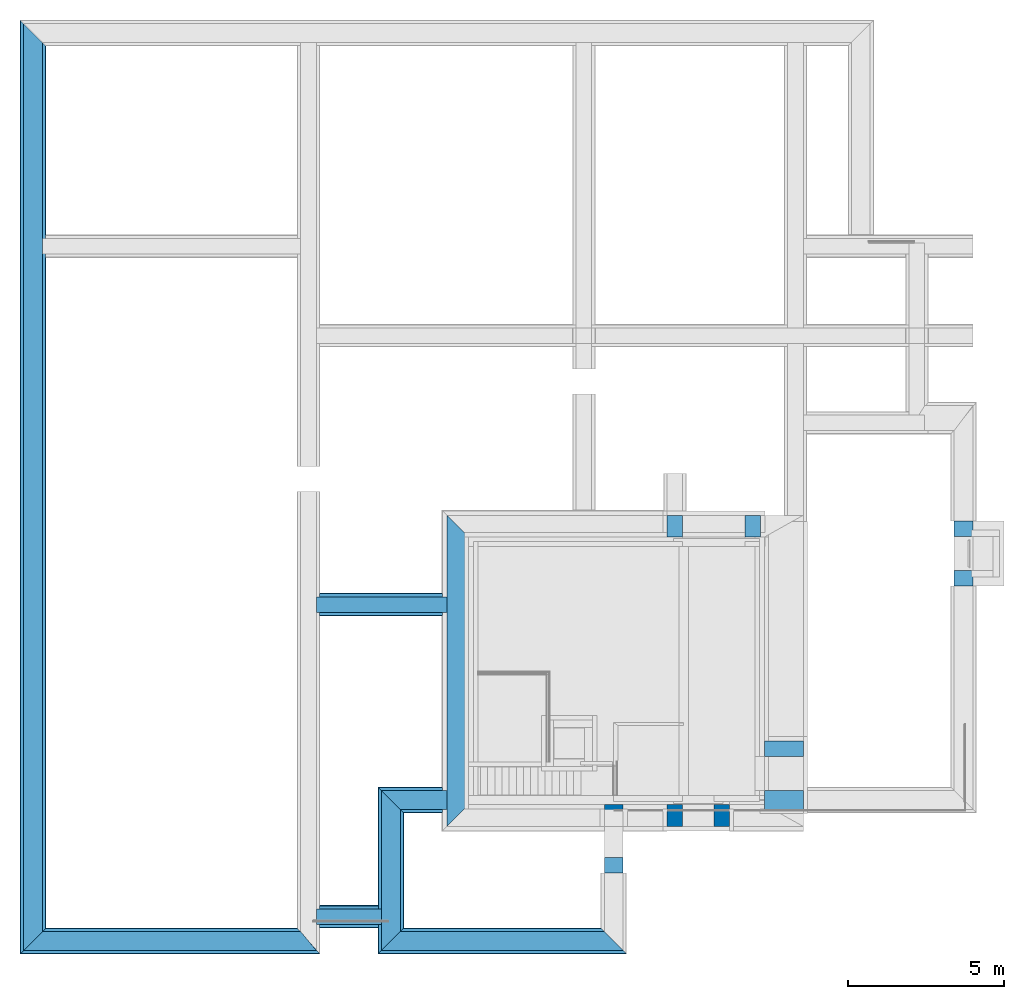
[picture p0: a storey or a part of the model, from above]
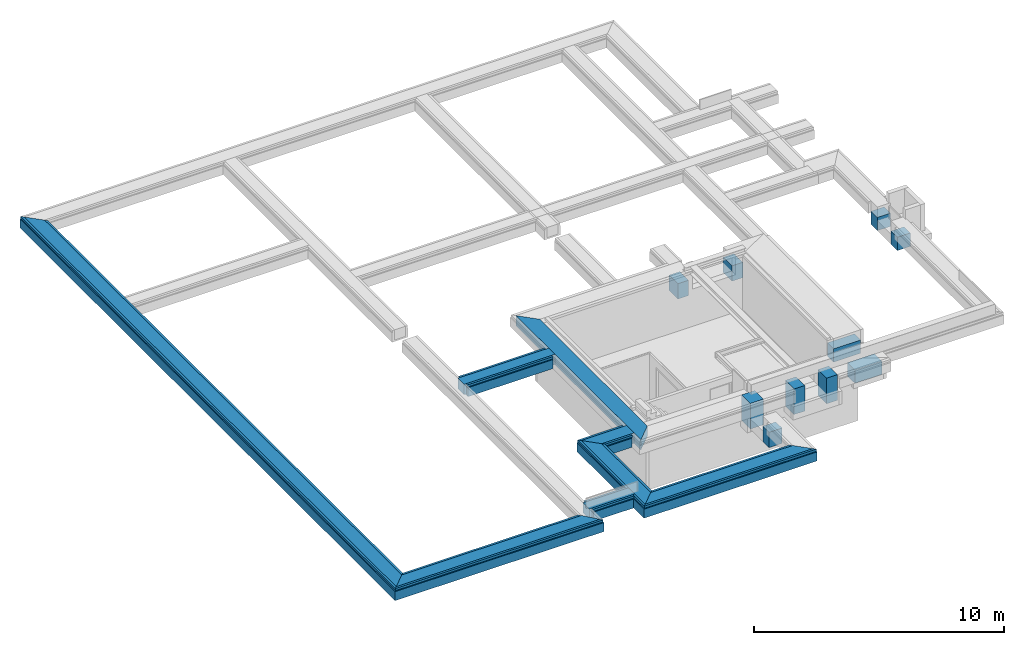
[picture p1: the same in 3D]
Properties of the parts of a building model (IFC2X3), part 1 of 7

# File
Description: ViewDefinition [, SurfaceGeometryAddOnView], Option [Elements to export: Visible elements (on all stories)], Option [Partial Structure Display: Entire Model], Option [IFC Domain: All], Option [Structural Function: All Elements], Option [Convert Grid elements: On], Option [Convert IFC Annotations and Archicad 2D elements: Off], Option [Convert 2D symbols of Doors and Windows: Off], Option [Export geometries that Participates in Collision Detection only: On], Option [Split complex elements: Off], Option [Material Preservation: Explode all], Option [IFC Model position: Survey Point and Project Origin], Option [Curtain Wall export mode: Container Element], Option [Railing export mode: Container Element], Option [Stair export mode: Container Element], Option [Properties To Export: Current Scheme properties only], Option [Space containment: Off], Option [Geometry to type objects: On], Option [Element Properties: Visible Only], Option [Building Material Properties: On], Option [Element Parameters: Off], Option [Component Parameters: Off], Option [IFC Base Quantities: Off], Option [Door Window Parameters: On], Option [IFC Space boundaries: Off], Option [Archicad Zone Categories as IFC Space classification data: Off], Option [Element Classifications: Off]
File name: P:\Project\2022\22004 Zwijndrecht Toermalijn\Archicad\Pdf-Dwg-Ifc-Bimx\20241212 IFC Interieur tbv Daan\22004 Toermalijn IFC totaal.ifc
Time: 2024-12-12T13:59:54
Author: Architect
Organization: Maas Kristinsson Architecten
Written by: DDS_IFC v3.0
Made in: IFC file generated by Graphisoft Archicad 26.0.0 NED FULL Windows version (IFC add-on version: 7004 NED FULL).
Authorization: The authorising person

# IfcProject, Nieuwbouw KC Toermalijn
Description: Schaepmanlaan 23 te Zwijndrecht

# IfcSite, Site
RefLatitude: 51, 27, 0, 0; RefLongitude: 5, 29, 0, 0; RefElevation: 0 mm

# IfcBuildingStorey (4)
In: Naam gebouw
Name | Elevation (mm)
Begane grond | 0
Kelder | -3060
1e verdieping | 3960
2e dakoverzicht | 7820

# IfcBeam: 100X100X5 100 x 100 (5)
In: Begane grond
Type - PredefinedType: BEAM
Material: Metaal - Staal C
Pset_BeamCommon - Slope: 0 deg; IsExternal: no; LoadBearing: yes; Reference: 100X100X5 100 x 100
CPset_Phasing - Renovation Phase: Bestaand
Material Properties - Metaal - Staal C, ThermalConductivity: 52; Metaal - Staal C, SpecificHeatCapacity: 530 J/kg/K; Metaal - Staal C, MassDensity: 7950 kg/m3; Metaal - Staal C, Embodied Energy: 25 (MJ/kg); Metaal - Staal C, Embodied Carbon: 1.91 (kgCO₂/kg); Metaal - Staal C, Name: Metaal - Staal C; Metaal - Staal C, Participates in Collision Detection: yes; Metaal - Staal C, Aardopwarmingsvermogen (GWP): 323.71; Metaal - Staal C, Ozonafbrekend Vermogen (ODP): 0; Metaal - Staal C, Fotochemische Vermogen tot Ozonvorming (POCP): 0.17963; Metaal - Staal C, Verzuringsvermogen (AP): 0.43354; Metaal - Staal C, Eutrofiëringspotentieel (EP): 0.014961; Metaal - Staal C, Abiotisch Uitputtingspotentieel (voor niet fossiele hulpbronnen) (ADPE): 0.00080492; Metaal - Staal C, Abiotisch Uitputtingspotentieel (voor fossiele hulpbronnen) (ADPF): 2862.1; Metaal - Staal C, Databron: https://www.oekobaudat.de/OEKOBAU.DAT/resource/processes/a85fbb4a-60a0-4ba9-9cfa-cdfbe1ec7f00?version=00.01.000

# IfcBeam: 16 Fundering - EPS kist 500x500 1036 x 570 (4)
In: Kelder
Type - PredefinedType: BEAM
Material: Isolatie - Kunststof hard
Pset_BeamCommon - Slope: 0 deg; IsExternal: no; LoadBearing: yes; Reference: 16 Fundering - EPS kist 500x500 1036 x 570
Material Properties - Isolatie - Kunststof hard, ThermalConductivity: 0.029; Isolatie - Kunststof hard, SpecificHeatCapacity: 1470 J/kg/K; Isolatie - Kunststof hard, MassDensity: 100 kg/m3; Isolatie - Kunststof hard, Embodied Energy: 101.5 (MJ/kg); Isolatie - Kunststof hard, Embodied Carbon: 3.48 (kgCO₂/kg); Isolatie - Kunststof hard, Name: Isolatie - Kunststof hard; Isolatie - Kunststof hard, Participates in Collision Detection: yes; Isolatie - Kunststof hard, Aardopwarmingsvermogen (GWP): 0.04; Isolatie - Kunststof hard, Ozonafbrekend Vermogen (ODP): 0; Isolatie - Kunststof hard, Fotochemische Vermogen tot Ozonvorming (POCP): 0; Isolatie - Kunststof hard, Verzuringsvermogen (AP): 0.0000975; Isolatie - Kunststof hard, Eutrofiëringspotentieel (EP): 0.0000237; Isolatie - Kunststof hard, Abiotisch Uitputtingspotentieel (voor niet fossiele hulpbronnen) (ADPE): 0; Isolatie - Kunststof hard, Abiotisch Uitputtingspotentieel (voor fossiele hulpbronnen) (ADPF): 0.47; Isolatie - Kunststof hard, Databron: https://www.oekobaudat.de/OEKOBAU.DAT/resource/processes/41e09ab7-0e73-4303-84fd-97cb0809db02?version=00.04.000
CPset_Phasing - Renovation Phase: Bestaand

# IfcBeam: 16 Fundering - EPS kist 500x500 740 x 570 (11)
In: Kelder
Type - PredefinedType: BEAM
Material: Isolatie - Kunststof hard
Pset_BeamCommon - Slope: 0 deg; IsExternal: no; LoadBearing: yes; Reference: 16 Fundering - EPS kist 500x500 740 x 570
CPset_Phasing - Renovation Phase: Bestaand
Material Properties - Isolatie - Kunststof hard, ThermalConductivity: 0.029; Isolatie - Kunststof hard, SpecificHeatCapacity: 1470 J/kg/K; Isolatie - Kunststof hard, MassDensity: 100 kg/m3; Isolatie - Kunststof hard, Embodied Energy: 101.5 (MJ/kg); Isolatie - Kunststof hard, Embodied Carbon: 3.48 (kgCO₂/kg); Isolatie - Kunststof hard, Name: Isolatie - Kunststof hard; Isolatie - Kunststof hard, Participates in Collision Detection: yes; Isolatie - Kunststof hard, Aardopwarmingsvermogen (GWP): 0.04; Isolatie - Kunststof hard, Ozonafbrekend Vermogen (ODP): 0; Isolatie - Kunststof hard, Fotochemische Vermogen tot Ozonvorming (POCP): 0; Isolatie - Kunststof hard, Verzuringsvermogen (AP): 0.0000975; Isolatie - Kunststof hard, Eutrofiëringspotentieel (EP): 0.0000237; Isolatie - Kunststof hard, Abiotisch Uitputtingspotentieel (voor niet fossiele hulpbronnen) (ADPE): 0; Isolatie - Kunststof hard, Abiotisch Uitputtingspotentieel (voor fossiele hulpbronnen) (ADPF): 0.47; Isolatie - Kunststof hard, Databron: https://www.oekobaudat.de/OEKOBAU.DAT/resource/processes/41e09ab7-0e73-4303-84fd-97cb0809db02?version=00.04.000

# IfcBeam: 16 Fundering - EPS kist 600x500 1040 x 570, n7 Kunststof met cellenstructuur_Regenwaterafvoer-x
In: Kelder
Type - PredefinedType: BEAM
Material: Isolatie - Kunststof hard
Pset_BeamCommon - Slope: 0 deg; IsExternal: no; LoadBearing: yes; Reference: 16 Fundering - EPS kist 600x500 1040 x 570
CPset_Phasing - Renovation Phase: Bestaand
Material Properties - Isolatie - Kunststof hard, ThermalConductivity: 0.029; Isolatie - Kunststof hard, SpecificHeatCapacity: 1470 J/kg/K; Isolatie - Kunststof hard, MassDensity: 100 kg/m3; Isolatie - Kunststof hard, Embodied Energy: 101.5 (MJ/kg); Isolatie - Kunststof hard, Embodied Carbon: 3.48 (kgCO₂/kg); Isolatie - Kunststof hard, Name: Isolatie - Kunststof hard; Isolatie - Kunststof hard, Participates in Collision Detection: yes; Isolatie - Kunststof hard, Aardopwarmingsvermogen (GWP): 0.04; Isolatie - Kunststof hard, Ozonafbrekend Vermogen (ODP): 0; Isolatie - Kunststof hard, Fotochemische Vermogen tot Ozonvorming (POCP): 0; Isolatie - Kunststof hard, Verzuringsvermogen (AP): 0.0000975; Isolatie - Kunststof hard, Eutrofiëringspotentieel (EP): 0.0000237; Isolatie - Kunststof hard, Abiotisch Uitputtingspotentieel (voor niet fossiele hulpbronnen) (ADPE): 0; Isolatie - Kunststof hard, Abiotisch Uitputtingspotentieel (voor fossiele hulpbronnen) (ADPF): 0.47; Isolatie - Kunststof hard, Databron: https://www.oekobaudat.de/OEKOBAU.DAT/resource/processes/41e09ab7-0e73-4303-84fd-97cb0809db02?version=00.04.000

# IfcBeam: 16 Fundering - EPS kist 600x500 840 x 570 (11)
In: Kelder
Type - PredefinedType: BEAM
Material: Isolatie - Kunststof hard
CPset_Phasing - Renovation Phase: Bestaand
Pset_BeamCommon - Slope: 0 deg; IsExternal: no; LoadBearing: yes; Reference: 16 Fundering - EPS kist 600x500 840 x 570
Material Properties - Isolatie - Kunststof hard, ThermalConductivity: 0.029; Isolatie - Kunststof hard, SpecificHeatCapacity: 1470 J/kg/K; Isolatie - Kunststof hard, MassDensity: 100 kg/m3; Isolatie - Kunststof hard, Embodied Energy: 101.5 (MJ/kg); Isolatie - Kunststof hard, Embodied Carbon: 3.48 (kgCO₂/kg); Isolatie - Kunststof hard, Name: Isolatie - Kunststof hard; Isolatie - Kunststof hard, Participates in Collision Detection: yes; Isolatie - Kunststof hard, Aardopwarmingsvermogen (GWP): 0.04; Isolatie - Kunststof hard, Ozonafbrekend Vermogen (ODP): 0; Isolatie - Kunststof hard, Fotochemische Vermogen tot Ozonvorming (POCP): 0; Isolatie - Kunststof hard, Verzuringsvermogen (AP): 0.0000975; Isolatie - Kunststof hard, Eutrofiëringspotentieel (EP): 0.0000237; Isolatie - Kunststof hard, Abiotisch Uitputtingspotentieel (voor niet fossiele hulpbronnen) (ADPE): 0; Isolatie - Kunststof hard, Abiotisch Uitputtingspotentieel (voor fossiele hulpbronnen) (ADPF): 0.47; Isolatie - Kunststof hard, Databron: https://www.oekobaudat.de/OEKOBAU.DAT/resource/processes/41e09ab7-0e73-4303-84fd-97cb0809db02?version=00.04.000

# IfcBeam: 16 Fundering - betonbalk 1250 x 500 (3)
In: Kelder
Type - PredefinedType: BEAM
Material: Beton gewapend C
Pset_BeamCommon - Slope: 0 deg; IsExternal: no; LoadBearing: yes; Reference: 16 Fundering - betonbalk 1250 x 500
CPset_Phasing - Renovation Phase: Bestaand
Material Properties - Beton gewapend C, ThermalConductivity: 2.3; Beton gewapend C, SpecificHeatCapacity: 1000 J/kg/K; Beton gewapend C, MassDensity: 2300 kg/m3; Beton gewapend C, Embodied Energy: 1.92 (MJ/kg); Beton gewapend C, Embodied Carbon: 0.198 (kgCO₂/kg); Beton gewapend C, Name: Beton gewapend C; Beton gewapend C, Participates in Collision Detection: yes; Beton gewapend C, Aardopwarmingsvermogen (GWP): -1.02642; Beton gewapend C, Ozonafbrekend Vermogen (ODP): 0; Beton gewapend C, Fotochemische Vermogen tot Ozonvorming (POCP): 0.000222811; Beton gewapend C, Verzuringsvermogen (AP): -0.00242385; Beton gewapend C, Eutrofiëringspotentieel (EP): -0.000471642; Beton gewapend C, Abiotisch Uitputtingspotentieel (voor niet fossiele hulpbronnen) (ADPE): -2.28121e-07; Beton gewapend C, Abiotisch Uitputtingspotentieel (voor fossiele hulpbronnen) (ADPF): -12.4095; Beton gewapend C, Databron: https://www.oekobaudat.de/OEKOBAU.DAT/resource/processes/d3b59cac-3b4e-4d18-8c3a-780b553c9591?version=20.19.120

# IfcBeam: 16 Fundering - betonbalk 500 x 500 (11)
In: Kelder
Type - PredefinedType: BEAM
Material: Beton gewapend C
CPset_Phasing - Renovation Phase: Bestaand
Pset_BeamCommon - Slope: 0 deg; IsExternal: no; LoadBearing: yes; Reference: 16 Fundering - betonbalk 500 x 500
Material Properties - Beton gewapend C, ThermalConductivity: 2.3; Beton gewapend C, SpecificHeatCapacity: 1000 J/kg/K; Beton gewapend C, MassDensity: 2300 kg/m3; Beton gewapend C, Embodied Energy: 1.92 (MJ/kg); Beton gewapend C, Embodied Carbon: 0.198 (kgCO₂/kg); Beton gewapend C, Name: Beton gewapend C; Beton gewapend C, Participates in Collision Detection: yes; Beton gewapend C, Aardopwarmingsvermogen (GWP): -1.02642; Beton gewapend C, Ozonafbrekend Vermogen (ODP): 0; Beton gewapend C, Fotochemische Vermogen tot Ozonvorming (POCP): 0.000222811; Beton gewapend C, Verzuringsvermogen (AP): -0.00242385; Beton gewapend C, Eutrofiëringspotentieel (EP): -0.000471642; Beton gewapend C, Abiotisch Uitputtingspotentieel (voor niet fossiele hulpbronnen) (ADPE): -2.28121e-07; Beton gewapend C, Abiotisch Uitputtingspotentieel (voor fossiele hulpbronnen) (ADPF): -12.4095; Beton gewapend C, Databron: https://www.oekobaudat.de/OEKOBAU.DAT/resource/processes/d3b59cac-3b4e-4d18-8c3a-780b553c9591?version=20.19.120

# IfcBeam: 16 Fundering - betonbalk 600 x 500 (13)
In: Kelder
Type - PredefinedType: BEAM
Material: Beton gewapend C
Material Properties - Beton gewapend C, ThermalConductivity: 2.3; Beton gewapend C, SpecificHeatCapacity: 1000 J/kg/K; Beton gewapend C, MassDensity: 2300 kg/m3; Beton gewapend C, Embodied Energy: 1.92 (MJ/kg); Beton gewapend C, Embodied Carbon: 0.198 (kgCO₂/kg); Beton gewapend C, Name: Beton gewapend C; Beton gewapend C, Participates in Collision Detection: yes; Beton gewapend C, Aardopwarmingsvermogen (GWP): -1.02642; Beton gewapend C, Ozonafbrekend Vermogen (ODP): 0; Beton gewapend C, Fotochemische Vermogen tot Ozonvorming (POCP): 0.000222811; Beton gewapend C, Verzuringsvermogen (AP): -0.00242385; Beton gewapend C, Eutrofiëringspotentieel (EP): -0.000471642; Beton gewapend C, Abiotisch Uitputtingspotentieel (voor niet fossiele hulpbronnen) (ADPE): -2.28121e-07; Beton gewapend C, Abiotisch Uitputtingspotentieel (voor fossiele hulpbronnen) (ADPF): -12.4095; Beton gewapend C, Databron: https://www.oekobaudat.de/OEKOBAU.DAT/resource/processes/d3b59cac-3b4e-4d18-8c3a-780b553c9591?version=20.19.120
CPset_Phasing - Renovation Phase: Bestaand
Pset_BeamCommon - Slope: 0 deg; IsExternal: no; LoadBearing: yes; Reference: 16 Fundering - betonbalk 600 x 500

# IfcBeam: 16 Fundering - betonbalk 700 x 500 (7)
In: Kelder
Type - PredefinedType: BEAM
Material: Beton gewapend C
Pset_BeamCommon - Slope: 0 deg; IsExternal: no; LoadBearing: yes; Reference: 16 Fundering - betonbalk 700 x 500
CPset_Phasing - Renovation Phase: Bestaand
Material Properties - Beton gewapend C, ThermalConductivity: 2.3; Beton gewapend C, SpecificHeatCapacity: 1000 J/kg/K; Beton gewapend C, MassDensity: 2300 kg/m3; Beton gewapend C, Embodied Energy: 1.92 (MJ/kg); Beton gewapend C, Embodied Carbon: 0.198 (kgCO₂/kg); Beton gewapend C, Name: Beton gewapend C; Beton gewapend C, Participates in Collision Detection: yes; Beton gewapend C, Aardopwarmingsvermogen (GWP): -1.02642; Beton gewapend C, Ozonafbrekend Vermogen (ODP): 0; Beton gewapend C, Fotochemische Vermogen tot Ozonvorming (POCP): 0.000222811; Beton gewapend C, Verzuringsvermogen (AP): -0.00242385; Beton gewapend C, Eutrofiëringspotentieel (EP): -0.000471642; Beton gewapend C, Abiotisch Uitputtingspotentieel (voor niet fossiele hulpbronnen) (ADPE): -2.28121e-07; Beton gewapend C, Abiotisch Uitputtingspotentieel (voor fossiele hulpbronnen) (ADPF): -12.4095; Beton gewapend C, Databron: https://www.oekobaudat.de/OEKOBAU.DAT/resource/processes/d3b59cac-3b4e-4d18-8c3a-780b553c9591?version=20.19.120

# IfcBeam: 16 Fundering - betonbalk 800 x 500, f2- Met cement gebonden producten (alle vulmiddelen)_Regenwaterafvoer-x
In: Kelder
Type - PredefinedType: BEAM
Material: Beton gewapend C
Pset_BeamCommon - Slope: 0 deg; IsExternal: no; LoadBearing: yes; Reference: 16 Fundering - betonbalk 800 x 500
CPset_Phasing - Renovation Phase: Bestaand
Material Properties - Beton gewapend C, ThermalConductivity: 2.3; Beton gewapend C, SpecificHeatCapacity: 1000 J/kg/K; Beton gewapend C, MassDensity: 2300 kg/m3; Beton gewapend C, Embodied Energy: 1.92 (MJ/kg); Beton gewapend C, Embodied Carbon: 0.198 (kgCO₂/kg); Beton gewapend C, Name: Beton gewapend C; Beton gewapend C, Participates in Collision Detection: yes; Beton gewapend C, Aardopwarmingsvermogen (GWP): -1.02642; Beton gewapend C, Ozonafbrekend Vermogen (ODP): 0; Beton gewapend C, Fotochemische Vermogen tot Ozonvorming (POCP): 0.000222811; Beton gewapend C, Verzuringsvermogen (AP): -0.00242385; Beton gewapend C, Eutrofiëringspotentieel (EP): -0.000471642; Beton gewapend C, Abiotisch Uitputtingspotentieel (voor niet fossiele hulpbronnen) (ADPE): -2.28121e-07; Beton gewapend C, Abiotisch Uitputtingspotentieel (voor fossiele hulpbronnen) (ADPF): -12.4095; Beton gewapend C, Databron: https://www.oekobaudat.de/OEKOBAU.DAT/resource/processes/d3b59cac-3b4e-4d18-8c3a-780b553c9591?version=20.19.120

# IfcBeam: 200X200X10 200 x 200 (4)
Type - PredefinedType: BEAM
Pset_BeamCommon - Slope: 0 deg; IsExternal: no; LoadBearing: yes; Reference: 200X200X10 200 x 200
CPset_Phasing - Renovation Phase: Bestaand
Name | In | Material = Metaal - Staal C, Name | Metaal - Staal C, ThermalConductivity | Metaal - Staal C, SpecificHeatCapacity (J/kg/K) | Metaal - Staal C, MassDensity (kg/m3) | Metaal - Staal C, Embodied Energy | Metaal - Staal C, Embodied Carbon | Metaal - Staal C, Participates in Collision Detection | Metaal - Staal C, Aardopwarmingsvermogen (GWP) | Metaal - Staal C, Ozonafbrekend Vermogen (ODP) | Metaal - Staal C, Fotochemische Vermogen tot Ozonvorming (POCP) | Metaal - Staal C, Verzuringsvermogen (AP) | Metaal - Staal C, Eutrofiëringspotentieel (EP) | Metaal - Staal C, Abiotisch Uitputtingspotentieel (voor niet fossiele hulpbronnen) (ADPE) | Metaal - Staal C, Abiotisch Uitputtingspotentieel (voor fossiele hulpbronnen) (ADPF) | Metaal - Staal C, Databron
h METAAL_Regenwaterafvoer-x | Begane grond | Metaal - Staal C | 52 | 530 | 7950 | 25 (MJ/kg) | 1.91 (kgCO₂/kg) | yes | 323.71 | 0 | 0.17963 | 0.43354 | 0.014961 | 0.00080492 | 2862.1 | https://www.oekobaudat.de/OEKOBAU.DAT/resource/processes/a85fbb4a-60a0-4ba9-9cfa-cdfbe1ec7f00?version=00.01.000
2 x h METAAL_Regenwaterafvoer-x | 1e verdieping | Metaal - Staal C | 52 | 530 | 7950 | 25 (MJ/kg) | 1.91 (kgCO₂/kg) | yes | 323.71 | 0 | 0.17963 | 0.43354 | 0.014961 | 0.00080492 | 2862.1 | https://www.oekobaudat.de/OEKOBAU.DAT/resource/processes/a85fbb4a-60a0-4ba9-9cfa-cdfbe1ec7f00?version=00.01.000
_Regenwaterafvoer-x | Begane grond

# IfcBeam: 28 THQ 01 400 x 280 (2)
Type - PredefinedType: BEAM
Material: Metaal - Staal C
CPset_Phasing - Renovation Phase: Bestaand
Pset_BeamCommon - Slope: 0 deg; IsExternal: no; LoadBearing: yes; Reference: 28 THQ 01 400 x 280
Material Properties - Metaal - Staal C, ThermalConductivity: 52; Metaal - Staal C, SpecificHeatCapacity: 530 J/kg/K; Metaal - Staal C, MassDensity: 7950 kg/m3; Metaal - Staal C, Embodied Energy: 25 (MJ/kg); Metaal - Staal C, Embodied Carbon: 1.91 (kgCO₂/kg); Metaal - Staal C, Name: Metaal - Staal C; Metaal - Staal C, Participates in Collision Detection: yes; Metaal - Staal C, Aardopwarmingsvermogen (GWP): 323.71; Metaal - Staal C, Ozonafbrekend Vermogen (ODP): 0; Metaal - Staal C, Fotochemische Vermogen tot Ozonvorming (POCP): 0.17963; Metaal - Staal C, Verzuringsvermogen (AP): 0.43354; Metaal - Staal C, Eutrofiëringspotentieel (EP): 0.014961; Metaal - Staal C, Abiotisch Uitputtingspotentieel (voor niet fossiele hulpbronnen) (ADPE): 0.00080492; Metaal - Staal C, Abiotisch Uitputtingspotentieel (voor fossiele hulpbronnen) (ADPF): 2862.1; Metaal - Staal C, Databron: https://www.oekobaudat.de/OEKOBAU.DAT/resource/processes/a85fbb4a-60a0-4ba9-9cfa-cdfbe1ec7f00?version=00.01.000
Name | In
h METAAL_Regenwaterafvoer-x | Begane grond
h METAAL_Regenwaterafvoer-x | 1e verdieping

# IfcBeam: 28 THQ 02 450 x 345, _Regenwaterafvoer-x
In: Begane grond
Type - PredefinedType: BEAM
Pset_BeamCommon - Slope: 0 deg; IsExternal: no; LoadBearing: yes; Reference: 28 THQ 02 450 x 345
CPset_Phasing - Renovation Phase: Bestaand

# IfcBeam: 28 THQ 03 400 x 290 (2)
In: Begane grond
Type - PredefinedType: BEAM
Material: Metaal - Staal C
Pset_BeamCommon - Slope: 0 deg; IsExternal: no; LoadBearing: yes; Reference: 28 THQ 03 400 x 290
CPset_Phasing - Renovation Phase: Bestaand
Material Properties - Metaal - Staal C, ThermalConductivity: 52; Metaal - Staal C, SpecificHeatCapacity: 530 J/kg/K; Metaal - Staal C, MassDensity: 7950 kg/m3; Metaal - Staal C, Embodied Energy: 25 (MJ/kg); Metaal - Staal C, Embodied Carbon: 1.91 (kgCO₂/kg); Metaal - Staal C, Name: Metaal - Staal C; Metaal - Staal C, Participates in Collision Detection: yes; Metaal - Staal C, Aardopwarmingsvermogen (GWP): 323.71; Metaal - Staal C, Ozonafbrekend Vermogen (ODP): 0; Metaal - Staal C, Fotochemische Vermogen tot Ozonvorming (POCP): 0.17963; Metaal - Staal C, Verzuringsvermogen (AP): 0.43354; Metaal - Staal C, Eutrofiëringspotentieel (EP): 0.014961; Metaal - Staal C, Abiotisch Uitputtingspotentieel (voor niet fossiele hulpbronnen) (ADPE): 0.00080492; Metaal - Staal C, Abiotisch Uitputtingspotentieel (voor fossiele hulpbronnen) (ADPF): 2862.1; Metaal - Staal C, Databron: https://www.oekobaudat.de/OEKOBAU.DAT/resource/processes/a85fbb4a-60a0-4ba9-9cfa-cdfbe1ec7f00?version=00.01.000

# IfcBeam: 28 THQ 04 400 x 277, h METAAL_Regenwaterafvoer-x
In: 1e verdieping
Type - PredefinedType: BEAM
Material: Metaal - Staal C
Pset_BeamCommon - Slope: 0 deg; IsExternal: no; LoadBearing: yes; Reference: 28 THQ 04 400 x 277
Material Properties - Metaal - Staal C, ThermalConductivity: 52; Metaal - Staal C, SpecificHeatCapacity: 530 J/kg/K; Metaal - Staal C, MassDensity: 7950 kg/m3; Metaal - Staal C, Embodied Energy: 25 (MJ/kg); Metaal - Staal C, Embodied Carbon: 1.91 (kgCO₂/kg); Metaal - Staal C, Name: Metaal - Staal C; Metaal - Staal C, Participates in Collision Detection: yes; Metaal - Staal C, Aardopwarmingsvermogen (GWP): 323.71; Metaal - Staal C, Ozonafbrekend Vermogen (ODP): 0; Metaal - Staal C, Fotochemische Vermogen tot Ozonvorming (POCP): 0.17963; Metaal - Staal C, Verzuringsvermogen (AP): 0.43354; Metaal - Staal C, Eutrofiëringspotentieel (EP): 0.014961; Metaal - Staal C, Abiotisch Uitputtingspotentieel (voor niet fossiele hulpbronnen) (ADPE): 0.00080492; Metaal - Staal C, Abiotisch Uitputtingspotentieel (voor fossiele hulpbronnen) (ADPF): 2862.1; Metaal - Staal C, Databron: https://www.oekobaudat.de/OEKOBAU.DAT/resource/processes/a85fbb4a-60a0-4ba9-9cfa-cdfbe1ec7f00?version=00.01.000
CPset_Phasing - Renovation Phase: Bestaand

# IfcBeam: 28 THQ 05 400 x 285, h METAAL_Regenwaterafvoer-x
In: 1e verdieping
Type - PredefinedType: BEAM
Material: Metaal - Staal C
Pset_BeamCommon - Slope: 0 deg; IsExternal: no; LoadBearing: yes; Reference: 28 THQ 05 400 x 285
CPset_Phasing - Renovation Phase: Bestaand
Material Properties - Metaal - Staal C, ThermalConductivity: 52; Metaal - Staal C, SpecificHeatCapacity: 530 J/kg/K; Metaal - Staal C, MassDensity: 7950 kg/m3; Metaal - Staal C, Embodied Energy: 25 (MJ/kg); Metaal - Staal C, Embodied Carbon: 1.91 (kgCO₂/kg); Metaal - Staal C, Name: Metaal - Staal C; Metaal - Staal C, Participates in Collision Detection: yes; Metaal - Staal C, Aardopwarmingsvermogen (GWP): 323.71; Metaal - Staal C, Ozonafbrekend Vermogen (ODP): 0; Metaal - Staal C, Fotochemische Vermogen tot Ozonvorming (POCP): 0.17963; Metaal - Staal C, Verzuringsvermogen (AP): 0.43354; Metaal - Staal C, Eutrofiëringspotentieel (EP): 0.014961; Metaal - Staal C, Abiotisch Uitputtingspotentieel (voor niet fossiele hulpbronnen) (ADPE): 0.00080492; Metaal - Staal C, Abiotisch Uitputtingspotentieel (voor fossiele hulpbronnen) (ADPF): 2862.1; Metaal - Staal C, Databron: https://www.oekobaudat.de/OEKOBAU.DAT/resource/processes/a85fbb4a-60a0-4ba9-9cfa-cdfbe1ec7f00?version=00.01.000

# IfcBeam: 28 THQ 06 400 x 275, h METAAL_Regenwaterafvoer-x
In: 1e verdieping
Type - PredefinedType: BEAM
Material: Metaal - Staal C
Pset_BeamCommon - Slope: 0 deg; IsExternal: no; LoadBearing: yes; Reference: 28 THQ 06 400 x 275
Material Properties - Metaal - Staal C, ThermalConductivity: 52; Metaal - Staal C, SpecificHeatCapacity: 530 J/kg/K; Metaal - Staal C, MassDensity: 7950 kg/m3; Metaal - Staal C, Embodied Energy: 25 (MJ/kg); Metaal - Staal C, Embodied Carbon: 1.91 (kgCO₂/kg); Metaal - Staal C, Name: Metaal - Staal C; Metaal - Staal C, Participates in Collision Detection: yes; Metaal - Staal C, Aardopwarmingsvermogen (GWP): 323.71; Metaal - Staal C, Ozonafbrekend Vermogen (ODP): 0; Metaal - Staal C, Fotochemische Vermogen tot Ozonvorming (POCP): 0.17963; Metaal - Staal C, Verzuringsvermogen (AP): 0.43354; Metaal - Staal C, Eutrofiëringspotentieel (EP): 0.014961; Metaal - Staal C, Abiotisch Uitputtingspotentieel (voor niet fossiele hulpbronnen) (ADPE): 0.00080492; Metaal - Staal C, Abiotisch Uitputtingspotentieel (voor fossiele hulpbronnen) (ADPF): 2862.1; Metaal - Staal C, Databron: https://www.oekobaudat.de/OEKOBAU.DAT/resource/processes/a85fbb4a-60a0-4ba9-9cfa-cdfbe1ec7f00?version=00.01.000
CPset_Phasing - Renovation Phase: Bestaand

# IfcBeam: 28 THQ 07 400 x 285, h METAAL_Regenwaterafvoer-x
In: Begane grond
Type - PredefinedType: BEAM
Material: Metaal - Staal C
Pset_BeamCommon - Slope: 0 deg; IsExternal: no; LoadBearing: yes; Reference: 28 THQ 07 400 x 285
CPset_Phasing - Renovation Phase: Bestaand
Material Properties - Metaal - Staal C, ThermalConductivity: 52; Metaal - Staal C, SpecificHeatCapacity: 530 J/kg/K; Metaal - Staal C, MassDensity: 7950 kg/m3; Metaal - Staal C, Embodied Energy: 25 (MJ/kg); Metaal - Staal C, Embodied Carbon: 1.91 (kgCO₂/kg); Metaal - Staal C, Name: Metaal - Staal C; Metaal - Staal C, Participates in Collision Detection: yes; Metaal - Staal C, Aardopwarmingsvermogen (GWP): 323.71; Metaal - Staal C, Ozonafbrekend Vermogen (ODP): 0; Metaal - Staal C, Fotochemische Vermogen tot Ozonvorming (POCP): 0.17963; Metaal - Staal C, Verzuringsvermogen (AP): 0.43354; Metaal - Staal C, Eutrofiëringspotentieel (EP): 0.014961; Metaal - Staal C, Abiotisch Uitputtingspotentieel (voor niet fossiele hulpbronnen) (ADPE): 0.00080492; Metaal - Staal C, Abiotisch Uitputtingspotentieel (voor fossiele hulpbronnen) (ADPF): 2862.1; Metaal - Staal C, Databron: https://www.oekobaudat.de/OEKOBAU.DAT/resource/processes/a85fbb4a-60a0-4ba9-9cfa-cdfbe1ec7f00?version=00.01.000

# IfcBeam: 28 THQ enkele flens 01 315 x 277 (6)
Type - PredefinedType: BEAM
Material: Metaal - Staal C
Pset_BeamCommon - Slope: 0 deg; IsExternal: no; LoadBearing: yes; Reference: 28 THQ enkele flens 01 315 x 277
CPset_Phasing - Renovation Phase: Bestaand
Material Properties - Metaal - Staal C, ThermalConductivity: 52; Metaal - Staal C, SpecificHeatCapacity: 530 J/kg/K; Metaal - Staal C, MassDensity: 7950 kg/m3; Metaal - Staal C, Embodied Energy: 25 (MJ/kg); Metaal - Staal C, Embodied Carbon: 1.91 (kgCO₂/kg); Metaal - Staal C, Name: Metaal - Staal C; Metaal - Staal C, Participates in Collision Detection: yes; Metaal - Staal C, Aardopwarmingsvermogen (GWP): 323.71; Metaal - Staal C, Ozonafbrekend Vermogen (ODP): 0; Metaal - Staal C, Fotochemische Vermogen tot Ozonvorming (POCP): 0.17963; Metaal - Staal C, Verzuringsvermogen (AP): 0.43354; Metaal - Staal C, Eutrofiëringspotentieel (EP): 0.014961; Metaal - Staal C, Abiotisch Uitputtingspotentieel (voor niet fossiele hulpbronnen) (ADPE): 0.00080492; Metaal - Staal C, Abiotisch Uitputtingspotentieel (voor fossiele hulpbronnen) (ADPF): 2862.1; Metaal - Staal C, Databron: https://www.oekobaudat.de/OEKOBAU.DAT/resource/processes/a85fbb4a-60a0-4ba9-9cfa-cdfbe1ec7f00?version=00.01.000
Name | In
5 x h METAAL_Regenwaterafvoer-x | Begane grond
h METAAL_Regenwaterafvoer-x | 1e verdieping

# IfcBeam: 28 THQ enkele flens 02 320 x 280 (4)
In: Begane grond
Type - PredefinedType: BEAM
Material: Metaal - Staal C
Pset_BeamCommon - Slope: 0 deg; IsExternal: no; LoadBearing: yes; Reference: 28 THQ enkele flens 02 320 x 280
CPset_Phasing - Renovation Phase: Bestaand
Material Properties - Metaal - Staal C, ThermalConductivity: 52; Metaal - Staal C, SpecificHeatCapacity: 530 J/kg/K; Metaal - Staal C, MassDensity: 7950 kg/m3; Metaal - Staal C, Embodied Energy: 25 (MJ/kg); Metaal - Staal C, Embodied Carbon: 1.91 (kgCO₂/kg); Metaal - Staal C, Name: Metaal - Staal C; Metaal - Staal C, Participates in Collision Detection: yes; Metaal - Staal C, Aardopwarmingsvermogen (GWP): 323.71; Metaal - Staal C, Ozonafbrekend Vermogen (ODP): 0; Metaal - Staal C, Fotochemische Vermogen tot Ozonvorming (POCP): 0.17963; Metaal - Staal C, Verzuringsvermogen (AP): 0.43354; Metaal - Staal C, Eutrofiëringspotentieel (EP): 0.014961; Metaal - Staal C, Abiotisch Uitputtingspotentieel (voor niet fossiele hulpbronnen) (ADPE): 0.00080492; Metaal - Staal C, Abiotisch Uitputtingspotentieel (voor fossiele hulpbronnen) (ADPF): 2862.1; Metaal - Staal C, Databron: https://www.oekobaudat.de/OEKOBAU.DAT/resource/processes/a85fbb4a-60a0-4ba9-9cfa-cdfbe1ec7f00?version=00.01.000

# IfcBeam: 28 THQ enkele flens 03 315 x 275 (3)
In: 1e verdieping
Type - PredefinedType: BEAM
Material: Metaal - Staal C
Pset_BeamCommon - Slope: 0 deg; IsExternal: no; LoadBearing: yes; Reference: 28 THQ enkele flens 03 315 x 275
CPset_Phasing - Renovation Phase: Bestaand
Material Properties - Metaal - Staal C, ThermalConductivity: 52; Metaal - Staal C, SpecificHeatCapacity: 530 J/kg/K; Metaal - Staal C, MassDensity: 7950 kg/m3; Metaal - Staal C, Embodied Energy: 25 (MJ/kg); Metaal - Staal C, Embodied Carbon: 1.91 (kgCO₂/kg); Metaal - Staal C, Name: Metaal - Staal C; Metaal - Staal C, Participates in Collision Detection: yes; Metaal - Staal C, Aardopwarmingsvermogen (GWP): 323.71; Metaal - Staal C, Ozonafbrekend Vermogen (ODP): 0; Metaal - Staal C, Fotochemische Vermogen tot Ozonvorming (POCP): 0.17963; Metaal - Staal C, Verzuringsvermogen (AP): 0.43354; Metaal - Staal C, Eutrofiëringspotentieel (EP): 0.014961; Metaal - Staal C, Abiotisch Uitputtingspotentieel (voor niet fossiele hulpbronnen) (ADPE): 0.00080492; Metaal - Staal C, Abiotisch Uitputtingspotentieel (voor fossiele hulpbronnen) (ADPF): 2862.1; Metaal - Staal C, Databron: https://www.oekobaudat.de/OEKOBAU.DAT/resource/processes/a85fbb4a-60a0-4ba9-9cfa-cdfbe1ec7f00?version=00.01.000

# IfcBeam: 28 THQ enkele flens 04 318 x 290 (2)
In: Begane grond
Type - PredefinedType: BEAM
Material: Metaal - Staal C
CPset_Phasing - Renovation Phase: Bestaand
Material Properties - Metaal - Staal C, ThermalConductivity: 52; Metaal - Staal C, SpecificHeatCapacity: 530 J/kg/K; Metaal - Staal C, MassDensity: 7950 kg/m3; Metaal - Staal C, Embodied Energy: 25 (MJ/kg); Metaal - Staal C, Embodied Carbon: 1.91 (kgCO₂/kg); Metaal - Staal C, Name: Metaal - Staal C; Metaal - Staal C, Participates in Collision Detection: yes; Metaal - Staal C, Aardopwarmingsvermogen (GWP): 323.71; Metaal - Staal C, Ozonafbrekend Vermogen (ODP): 0; Metaal - Staal C, Fotochemische Vermogen tot Ozonvorming (POCP): 0.17963; Metaal - Staal C, Verzuringsvermogen (AP): 0.43354; Metaal - Staal C, Eutrofiëringspotentieel (EP): 0.014961; Metaal - Staal C, Abiotisch Uitputtingspotentieel (voor niet fossiele hulpbronnen) (ADPE): 0.00080492; Metaal - Staal C, Abiotisch Uitputtingspotentieel (voor fossiele hulpbronnen) (ADPF): 2862.1; Metaal - Staal C, Databron: https://www.oekobaudat.de/OEKOBAU.DAT/resource/processes/a85fbb4a-60a0-4ba9-9cfa-cdfbe1ec7f00?version=00.01.000
Pset_BeamCommon - Slope: 0 deg; IsExternal: no; LoadBearing: yes; Reference: 28 THQ enkele flens 04 318 x 290

# IfcBeam: 28 THQ enkele flens 06 245 x 280 (2)
Type - PredefinedType: BEAM
Material: Metaal - Staal C
CPset_Phasing - Renovation Phase: Bestaand
Pset_BeamCommon - Slope: 0 deg; IsExternal: no; LoadBearing: yes; Reference: 28 THQ enkele flens 06 245 x 280
Material Properties - Metaal - Staal C, ThermalConductivity: 52; Metaal - Staal C, SpecificHeatCapacity: 530 J/kg/K; Metaal - Staal C, MassDensity: 7950 kg/m3; Metaal - Staal C, Embodied Energy: 25 (MJ/kg); Metaal - Staal C, Embodied Carbon: 1.91 (kgCO₂/kg); Metaal - Staal C, Name: Metaal - Staal C; Metaal - Staal C, Participates in Collision Detection: yes; Metaal - Staal C, Aardopwarmingsvermogen (GWP): 323.71; Metaal - Staal C, Ozonafbrekend Vermogen (ODP): 0; Metaal - Staal C, Fotochemische Vermogen tot Ozonvorming (POCP): 0.17963; Metaal - Staal C, Verzuringsvermogen (AP): 0.43354; Metaal - Staal C, Eutrofiëringspotentieel (EP): 0.014961; Metaal - Staal C, Abiotisch Uitputtingspotentieel (voor niet fossiele hulpbronnen) (ADPE): 0.00080492; Metaal - Staal C, Abiotisch Uitputtingspotentieel (voor fossiele hulpbronnen) (ADPF): 2862.1; Metaal - Staal C, Databron: https://www.oekobaudat.de/OEKOBAU.DAT/resource/processes/a85fbb4a-60a0-4ba9-9cfa-cdfbe1ec7f00?version=00.01.000
Name | In
h METAAL_Regenwaterafvoer-x | Begane grond
h METAAL_Regenwaterafvoer-x | 1e verdieping

# IfcBeam: 28 THQ zonder flens 01 202 x 285, h METAAL_Regenwaterafvoer-x
In: 1e verdieping
Type - PredefinedType: BEAM
Material: Metaal - Staal C
Pset_BeamCommon - Slope: 0 deg; IsExternal: no; LoadBearing: yes; Reference: 28 THQ zonder flens 01 202 x 285
CPset_Phasing - Renovation Phase: Bestaand
Material Properties - Metaal - Staal C, ThermalConductivity: 52; Metaal - Staal C, SpecificHeatCapacity: 530 J/kg/K; Metaal - Staal C, MassDensity: 7950 kg/m3; Metaal - Staal C, Embodied Energy: 25 (MJ/kg); Metaal - Staal C, Embodied Carbon: 1.91 (kgCO₂/kg); Metaal - Staal C, Name: Metaal - Staal C; Metaal - Staal C, Participates in Collision Detection: yes; Metaal - Staal C, Aardopwarmingsvermogen (GWP): 323.71; Metaal - Staal C, Ozonafbrekend Vermogen (ODP): 0; Metaal - Staal C, Fotochemische Vermogen tot Ozonvorming (POCP): 0.17963; Metaal - Staal C, Verzuringsvermogen (AP): 0.43354; Metaal - Staal C, Eutrofiëringspotentieel (EP): 0.014961; Metaal - Staal C, Abiotisch Uitputtingspotentieel (voor niet fossiele hulpbronnen) (ADPE): 0.00080492; Metaal - Staal C, Abiotisch Uitputtingspotentieel (voor fossiele hulpbronnen) (ADPF): 2862.1; Metaal - Staal C, Databron: https://www.oekobaudat.de/OEKOBAU.DAT/resource/processes/a85fbb4a-60a0-4ba9-9cfa-cdfbe1ec7f00?version=00.01.000

# IfcBeam: 30 Duco Louvre deur 55 x 2627, _Regenwaterafvoer-x
In: Begane grond
Type - PredefinedType: BEAM
Pset_BeamCommon - Slope: 0 deg; IsExternal: no; LoadBearing: yes; Reference: 30 Duco Louvre deur 55 x 2627
CPset_Phasing - Renovation Phase: Bestaand

# IfcBeam: 31 Betondorpel 250 x 90 (17)
In: Begane grond
Type - PredefinedType: BEAM
Pset_BeamCommon - Slope: 0 deg; IsExternal: no; LoadBearing: yes; Reference: 31 Betondorpel 250 x 90
CPset_Phasing - Renovation Phase: Bestaand

# IfcBeam: 31 HSB boven hoofdentree 880 x 928, 28_Balk-x
In: Begane grond
Type - PredefinedType: BEAM
CPset_Phasing - Renovation Phase: Bestaand
Pset_BeamCommon - Slope: 0 deg; IsExternal: no; LoadBearing: yes; Reference: 31 HSB boven hoofdentree 880 x 928

# IfcBeam: 31 HSB boven kozijnen 214 x 1000 (40)
Type - PredefinedType: BEAM
CPset_Phasing - Renovation Phase: Bestaand
Pset_BeamCommon - Slope: 0 deg; IsExternal: no; LoadBearing: yes; Reference: 31 HSB boven kozijnen 214 x 1000
Name | In
21 x 28_Balk-x | Begane grond
19 x 28_Balk-x | 1e verdieping

# IfcBeam: 34 Glas balustrade binnen 50 x 1800 (7)
Type - PredefinedType: BEAM
Pset_BeamCommon - IsExternal: no; LoadBearing: yes; Reference: 34 Glas balustrade binnen 50 x 1800
CPset_Phasing - Renovation Phase: Bestaand
Name | In | Slope (deg)
3 x _Regenwaterafvoer-x | Begane grond | 33.6901
2 x _Regenwaterafvoer-x | Begane grond | 0
2 x _Regenwaterafvoer-x | 1e verdieping | 0

# IfcBeam: 41 Latei/geveldrager 158 x 112 (35)
Type - PredefinedType: BEAM
Pset_BeamCommon - Slope: 0 deg; IsExternal: no; LoadBearing: yes; Reference: 41 Latei/geveldrager 158 x 112
CPset_Phasing - Renovation Phase: Bestaand
Name | In
19 x _Regenwaterafvoer-x | Begane grond
16 x _Regenwaterafvoer-x | 1e verdieping

# IfcBeam: 41 Nestkast zwaluw 430 x 175 (7)
In: 1e verdieping
Type - PredefinedType: BEAM
Pset_BeamCommon - Slope: 0 deg; IsExternal: no; LoadBearing: yes; Reference: 41 Nestkast zwaluw 430 x 175
CPset_Phasing - Renovation Phase: Bestaand

# IfcBeam: 41 Overgang stucwerk wand-plafond 176 x 176 (2)
In: Begane grond
Type - PredefinedType: BEAM
Pset_BeamCommon - Slope: 0 deg; IsExternal: no; LoadBearing: yes; Reference: 41 Overgang stucwerk wand-plafond 176 x 176
CPset_Phasing - Renovation Phase: Bestaand

# IfcBeam: 41 Plint stucwerk 48 x 250, g2- Gebakken klei_Regenwaterafvoer-x
In: 1e verdieping
Type - PredefinedType: BEAM
Material: 47 waterdichte laag - bitumen
CPset_Phasing - Renovation Phase: Bestaand
Pset_BeamCommon - Slope: 0 deg; IsExternal: no; LoadBearing: yes; Reference: 41 Plint stucwerk 48 x 250
Material Properties - 47 waterdichte laag - bitumen, ThermalConductivity: 0.9; 47 waterdichte laag - bitumen, SpecificHeatCapacity: 840 J/kg/K; 47 waterdichte laag - bitumen, MassDensity: 1600 kg/m3; 47 waterdichte laag - bitumen, Embodied Energy: 3 (MJ/kg); 47 waterdichte laag - bitumen, Embodied Carbon: 0.23 (kgCO₂/kg); 47 waterdichte laag - bitumen, Name: 47 waterdichte laag - bitumen; 47 waterdichte laag - bitumen, Participates in Collision Detection: yes; 47 waterdichte laag - bitumen, Aardopwarmingsvermogen (GWP): 113; 47 waterdichte laag - bitumen, Ozonafbrekend Vermogen (ODP): 0; 47 waterdichte laag - bitumen, Fotochemische Vermogen tot Ozonvorming (POCP): 0.012; 47 waterdichte laag - bitumen, Verzuringsvermogen (AP): 0.094; 47 waterdichte laag - bitumen, Eutrofiëringspotentieel (EP): 0.0189; 47 waterdichte laag - bitumen, Abiotisch Uitputtingspotentieel (voor niet fossiele hulpbronnen) (ADPE): 0.0000099; 47 waterdichte laag - bitumen, Abiotisch Uitputtingspotentieel (voor fossiele hulpbronnen) (ADPF): 1150; 47 waterdichte laag - bitumen, Databron: https://www.oekobaudat.de/OEKOBAU.DAT/resource/processes/08dd0308-eebf-4db1-82ee-b340d070c9b9?version=00.06.000

# IfcBeam: 41 Plint stucwerk 48 x 550 (2)
In: Begane grond
Type - PredefinedType: BEAM
Material: 47 waterdichte laag - bitumen
CPset_Phasing - Renovation Phase: Bestaand
Pset_BeamCommon - Slope: 0 deg; IsExternal: no; LoadBearing: yes; Reference: 41 Plint stucwerk 48 x 550
Material Properties - 47 waterdichte laag - bitumen, ThermalConductivity: 0.9; 47 waterdichte laag - bitumen, SpecificHeatCapacity: 840 J/kg/K; 47 waterdichte laag - bitumen, MassDensity: 1600 kg/m3; 47 waterdichte laag - bitumen, Embodied Energy: 3 (MJ/kg); 47 waterdichte laag - bitumen, Embodied Carbon: 0.23 (kgCO₂/kg); 47 waterdichte laag - bitumen, Name: 47 waterdichte laag - bitumen; 47 waterdichte laag - bitumen, Participates in Collision Detection: yes; 47 waterdichte laag - bitumen, Aardopwarmingsvermogen (GWP): 113; 47 waterdichte laag - bitumen, Ozonafbrekend Vermogen (ODP): 0; 47 waterdichte laag - bitumen, Fotochemische Vermogen tot Ozonvorming (POCP): 0.012; 47 waterdichte laag - bitumen, Verzuringsvermogen (AP): 0.094; 47 waterdichte laag - bitumen, Eutrofiëringspotentieel (EP): 0.0189; 47 waterdichte laag - bitumen, Abiotisch Uitputtingspotentieel (voor niet fossiele hulpbronnen) (ADPE): 0.0000099; 47 waterdichte laag - bitumen, Abiotisch Uitputtingspotentieel (voor fossiele hulpbronnen) (ADPF): 1150; 47 waterdichte laag - bitumen, Databron: https://www.oekobaudat.de/OEKOBAU.DAT/resource/processes/08dd0308-eebf-4db1-82ee-b340d070c9b9?version=00.06.000

# IfcBeam: 41 Plint stucwerk 62 x 250 (7)
In: 1e verdieping
Type - PredefinedType: BEAM
Material: 47 waterdichte laag - bitumen
Pset_BeamCommon - IsExternal: no; LoadBearing: yes; Reference: 41 Plint stucwerk 62 x 250
CPset_Phasing - Renovation Phase: Bestaand
Material Properties - 47 waterdichte laag - bitumen, ThermalConductivity: 0.9; 47 waterdichte laag - bitumen, SpecificHeatCapacity: 840 J/kg/K; 47 waterdichte laag - bitumen, MassDensity: 1600 kg/m3; 47 waterdichte laag - bitumen, Embodied Energy: 3 (MJ/kg); 47 waterdichte laag - bitumen, Embodied Carbon: 0.23 (kgCO₂/kg); 47 waterdichte laag - bitumen, Name: 47 waterdichte laag - bitumen; 47 waterdichte laag - bitumen, Participates in Collision Detection: yes; 47 waterdichte laag - bitumen, Aardopwarmingsvermogen (GWP): 113; 47 waterdichte laag - bitumen, Ozonafbrekend Vermogen (ODP): 0; 47 waterdichte laag - bitumen, Fotochemische Vermogen tot Ozonvorming (POCP): 0.012; 47 waterdichte laag - bitumen, Verzuringsvermogen (AP): 0.094; 47 waterdichte laag - bitumen, Eutrofiëringspotentieel (EP): 0.0189; 47 waterdichte laag - bitumen, Abiotisch Uitputtingspotentieel (voor niet fossiele hulpbronnen) (ADPE): 0.0000099; 47 waterdichte laag - bitumen, Abiotisch Uitputtingspotentieel (voor fossiele hulpbronnen) (ADPF): 1150; 47 waterdichte laag - bitumen, Databron: https://www.oekobaudat.de/OEKOBAU.DAT/resource/processes/08dd0308-eebf-4db1-82ee-b340d070c9b9?version=00.06.000
Name | Slope (deg)
5 x g2- Gebakken klei_Regenwaterafvoer-x | 0
2 x g2- Gebakken klei_Regenwaterafvoer-x | -33.6901

# IfcBeam: 41 Waterslag 218 x 75 (15)
In: 1e verdieping
Type - PredefinedType: BEAM
Material: Metaal - Aluminium
Pset_BeamCommon - Slope: 0 deg; IsExternal: no; LoadBearing: yes; Reference: 41 Waterslag 218 x 75
Material Properties - Metaal - Aluminium, ThermalConductivity: 160; Metaal - Aluminium, SpecificHeatCapacity: 880 J/kg/K; Metaal - Aluminium, MassDensity: 2800 kg/m3; Metaal - Aluminium, Embodied Energy: 155 (MJ/kg); Metaal - Aluminium, Embodied Carbon: 9.16 (kgCO₂/kg); Metaal - Aluminium, Name: Metaal - Aluminium; Metaal - Aluminium, Participates in Collision Detection: yes; Metaal - Aluminium, Aardopwarmingsvermogen (GWP): 0.002322; Metaal - Aluminium, Ozonafbrekend Vermogen (ODP): 0; Metaal - Aluminium, Fotochemische Vermogen tot Ozonvorming (POCP): 6.194e-07; Metaal - Aluminium, Verzuringsvermogen (AP): 0.000008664; Metaal - Aluminium, Eutrofiëringspotentieel (EP): 0.00000106; Metaal - Aluminium, Abiotisch Uitputtingspotentieel (voor niet fossiele hulpbronnen) (ADPE): 0; Metaal - Aluminium, Abiotisch Uitputtingspotentieel (voor fossiele hulpbronnen) (ADPF): 0.02659; Metaal - Aluminium, Databron: https://www.oekobaudat.de/OEKOBAU.DAT/resource/processes/c83d501f-d07f-4434-9d5c-862a7e8a3026?version=00.01.000; Metaal - Aluminium, Handelsgewicht (kg/m): 0; Metaal - Aluminium, Soortelijk gewicht (kg/m3): 7850; Metaal - Aluminium, Marge materiaal: 1
CPset_Phasing - Renovation Phase: Bestaand

# IfcBeam: 45 Afwerking Geveldrager 305 x 30, _Regenwaterafvoer-x
In: 1e verdieping
Type - PredefinedType: BEAM
Pset_BeamCommon - Slope: 0 deg; IsExternal: no; LoadBearing: yes; Reference: 45 Afwerking Geveldrager 305 x 30
CPset_Phasing - Renovation Phase: Bestaand

# IfcBeam: 45 Buitenplafond entree KOV 847 x 700, _Regenwaterafvoer-x
In: Begane grond
Type - PredefinedType: BEAM
Pset_BeamCommon - Slope: 0 deg; IsExternal: no; LoadBearing: yes; Reference: 45 Buitenplafond entree KOV 847 x 700
CPset_Phasing - Renovation Phase: Bestaand

# IfcBeam: 47 Dakrand metselwerk overstek 443 x 421, 28_Balk-x
In: 2e dakoverzicht
Type - PredefinedType: BEAM
Pset_BeamCommon - Slope: 0 deg; IsExternal: no; LoadBearing: yes; Reference: 47 Dakrand metselwerk overstek 443 x 421
CPset_Phasing - Renovation Phase: Bestaand

# IfcBeam: 47 Dakrand stucwerk overstek 428 x 514, 28_Balk-x
In: 2e dakoverzicht
Type - PredefinedType: BEAM
Pset_BeamCommon - Slope: 0 deg; IsExternal: no; LoadBearing: yes; Reference: 47 Dakrand stucwerk overstek 428 x 514
CPset_Phasing - Renovation Phase: Bestaand

# IfcBeam: 47 Daktrim 45 x 45 (6)
In: 2e dakoverzicht
Type - PredefinedType: BEAM
Material: Metaal - Aluminium
Pset_BeamCommon - Slope: 0 deg; IsExternal: no; LoadBearing: yes; Reference: 47 Daktrim 45 x 45
Material Properties - Metaal - Aluminium, ThermalConductivity: 160; Metaal - Aluminium, SpecificHeatCapacity: 880 J/kg/K; Metaal - Aluminium, MassDensity: 2800 kg/m3; Metaal - Aluminium, Embodied Energy: 155 (MJ/kg); Metaal - Aluminium, Embodied Carbon: 9.16 (kgCO₂/kg); Metaal - Aluminium, Name: Metaal - Aluminium; Metaal - Aluminium, Participates in Collision Detection: yes; Metaal - Aluminium, Aardopwarmingsvermogen (GWP): 0.002322; Metaal - Aluminium, Ozonafbrekend Vermogen (ODP): 0; Metaal - Aluminium, Fotochemische Vermogen tot Ozonvorming (POCP): 6.194e-07; Metaal - Aluminium, Verzuringsvermogen (AP): 0.000008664; Metaal - Aluminium, Eutrofiëringspotentieel (EP): 0.00000106; Metaal - Aluminium, Abiotisch Uitputtingspotentieel (voor niet fossiele hulpbronnen) (ADPE): 0; Metaal - Aluminium, Abiotisch Uitputtingspotentieel (voor fossiele hulpbronnen) (ADPF): 0.02659; Metaal - Aluminium, Databron: https://www.oekobaudat.de/OEKOBAU.DAT/resource/processes/c83d501f-d07f-4434-9d5c-862a7e8a3026?version=00.01.000; Metaal - Aluminium, Handelsgewicht (kg/m): 0; Metaal - Aluminium, Soortelijk gewicht (kg/m3): 7850; Metaal - Aluminium, Marge materiaal: 1
CPset_Phasing - Renovation Phase: Bestaand

# IfcBeam: 47 IPE inpakken 250 x 203 (30)
In: 2e dakoverzicht
Type - PredefinedType: BEAM
CPset_Phasing - Renovation Phase: Bestaand
Pset_BeamCommon - Slope: 0 deg; IsExternal: no; LoadBearing: yes; Reference: 47 IPE inpakken 250 x 203

# IfcBeam: 47 Isoniq M metselwerk 443 x 509 (4)
In: 2e dakoverzicht
Type - PredefinedType: BEAM
Pset_BeamCommon - Slope: 0 deg; IsExternal: no; LoadBearing: yes; Reference: 47 Isoniq M metselwerk 443 x 509
CPset_Phasing - Renovation Phase: Bestaand

# IfcBeam: 47 Isoniq M metselwerk overstek 443 x 1282 (2)
In: 2e dakoverzicht
Type - PredefinedType: BEAM
Pset_BeamCommon - Slope: 0 deg; IsExternal: no; LoadBearing: yes; Reference: 47 Isoniq M metselwerk overstek 443 x 1282
CPset_Phasing - Renovation Phase: Bestaand

# IfcBeam: 47 Isoniq M stucwerk 428 x 509, 28_Balk-x
In: 2e dakoverzicht
Type - PredefinedType: BEAM
CPset_Phasing - Renovation Phase: Bestaand
Pset_BeamCommon - Slope: 0 deg; IsExternal: no; LoadBearing: yes; Reference: 47 Isoniq M stucwerk 428 x 509

# IfcBeam: 70X70X5 70 x 70 (2)
In: Begane grond
Type - PredefinedType: BEAM
Material: Metaal - Staal C
CPset_Phasing - Renovation Phase: Bestaand
Material Properties - Metaal - Staal C, ThermalConductivity: 52; Metaal - Staal C, SpecificHeatCapacity: 530 J/kg/K; Metaal - Staal C, MassDensity: 7950 kg/m3; Metaal - Staal C, Embodied Energy: 25 (MJ/kg); Metaal - Staal C, Embodied Carbon: 1.91 (kgCO₂/kg); Metaal - Staal C, Name: Metaal - Staal C; Metaal - Staal C, Participates in Collision Detection: yes; Metaal - Staal C, Aardopwarmingsvermogen (GWP): 323.71; Metaal - Staal C, Ozonafbrekend Vermogen (ODP): 0; Metaal - Staal C, Fotochemische Vermogen tot Ozonvorming (POCP): 0.17963; Metaal - Staal C, Verzuringsvermogen (AP): 0.43354; Metaal - Staal C, Eutrofiëringspotentieel (EP): 0.014961; Metaal - Staal C, Abiotisch Uitputtingspotentieel (voor niet fossiele hulpbronnen) (ADPE): 0.00080492; Metaal - Staal C, Abiotisch Uitputtingspotentieel (voor fossiele hulpbronnen) (ADPF): 2862.1; Metaal - Staal C, Databron: https://www.oekobaudat.de/OEKOBAU.DAT/resource/processes/a85fbb4a-60a0-4ba9-9cfa-cdfbe1ec7f00?version=00.01.000
Pset_BeamCommon - IsExternal: no; LoadBearing: yes; Reference: 70X70X5 70 x 70
Name | Slope (deg)
h METAAL_Regenwaterafvoer-x | 34.6169
h METAAL_Regenwaterafvoer-x | 0

# IfcBeam: 70x70x5 70 x 70 (4)
In: 1e verdieping
Type - PredefinedType: BEAM
Material: Metaal - Staal C
CPset_Phasing - Renovation Phase: Bestaand
Pset_BeamCommon - IsExternal: no; LoadBearing: yes; Reference: 70x70x5 70 x 70
Material Properties - Metaal - Staal C, ThermalConductivity: 52; Metaal - Staal C, SpecificHeatCapacity: 530 J/kg/K; Metaal - Staal C, MassDensity: 7950 kg/m3; Metaal - Staal C, Embodied Energy: 25 (MJ/kg); Metaal - Staal C, Embodied Carbon: 1.91 (kgCO₂/kg); Metaal - Staal C, Name: Metaal - Staal C; Metaal - Staal C, Participates in Collision Detection: yes; Metaal - Staal C, Aardopwarmingsvermogen (GWP): 323.71; Metaal - Staal C, Ozonafbrekend Vermogen (ODP): 0; Metaal - Staal C, Fotochemische Vermogen tot Ozonvorming (POCP): 0.17963; Metaal - Staal C, Verzuringsvermogen (AP): 0.43354; Metaal - Staal C, Eutrofiëringspotentieel (EP): 0.014961; Metaal - Staal C, Abiotisch Uitputtingspotentieel (voor niet fossiele hulpbronnen) (ADPE): 0.00080492; Metaal - Staal C, Abiotisch Uitputtingspotentieel (voor fossiele hulpbronnen) (ADPF): 2862.1; Metaal - Staal C, Databron: https://www.oekobaudat.de/OEKOBAU.DAT/resource/processes/a85fbb4a-60a0-4ba9-9cfa-cdfbe1ec7f00?version=00.01.000
Name | Slope (deg)
h METAAL_Regenwaterafvoer-x | 32.397
2 x h METAAL_Regenwaterafvoer-x | 33.3645
h METAAL_Regenwaterafvoer-x | 49.3177

# IfcBeam: ALG - ALGEMEEN D30 (38)
In: 1e verdieping
Type - PredefinedType: BEAM
Material: ALG - ALGEMEEN
CPset_Phasing - Renovation Phase: Bestaand
Pset_BeamCommon - Slope: 0 deg; IsExternal: no; LoadBearing: yes; Reference: ALG - ALGEMEEN D30
Material Properties - ALG - ALGEMEEN, ThermalConductivity: 0.27; ALG - ALGEMEEN, SpecificHeatCapacity: 840 J/kg/K; ALG - ALGEMEEN, MassDensity: 800 kg/m3; ALG - ALGEMEEN, Embodied Energy: 2 (MJ/kg); ALG - ALGEMEEN, Embodied Carbon: 0.13 (kgCO₂/kg); ALG - ALGEMEEN, Name: ALG - ALGEMEEN; ALG - ALGEMEEN, Participates in Collision Detection: yes; ALG - ALGEMEEN, Handelsgewicht (kg/m): 0; ALG - ALGEMEEN, Soortelijk gewicht (kg/m3): 7850; ALG - ALGEMEEN, Marge materiaal: 1

# IfcBeam: Gipsplaat 13 x 261 (3)
In: Begane grond
Type - PredefinedType: BEAM
Material: Gipsplaat
Pset_BeamCommon - IsExternal: no; LoadBearing: yes; Reference: Gipsplaat 13 x 261
CPset_Phasing - Renovation Phase: Bestaand
Material Properties - Gipsplaat, ThermalConductivity: 0.23; Gipsplaat, SpecificHeatCapacity: 840 J/kg/K; Gipsplaat, MassDensity: 800 kg/m3; Gipsplaat, Embodied Energy: 6.75 (MJ/kg); Gipsplaat, Embodied Carbon: 0.38 (kgCO₂/kg); Gipsplaat, Name: Gipsplaat; Gipsplaat, Participates in Collision Detection: yes; Gipsplaat, Aardopwarmingsvermogen (GWP): 1.513; Gipsplaat, Ozonafbrekend Vermogen (ODP): 1.32e-07; Gipsplaat, Fotochemische Vermogen tot Ozonvorming (POCP): 0.000358; Gipsplaat, Verzuringsvermogen (AP): 0.0082; Gipsplaat, Eutrofiëringspotentieel (EP): 0.00138; Gipsplaat, Abiotisch Uitputtingspotentieel (voor niet fossiele hulpbronnen) (ADPE): 0.00000729; Gipsplaat, Abiotisch Uitputtingspotentieel (voor fossiele hulpbronnen) (ADPF): 25.04; Gipsplaat, Databron: https://www.oekobaudat.de/OEKOBAU.DAT/resource/processes/1a24808b-9116-422e-93fb-d435f74a038a?version=00.05.000
Name | Slope (deg)
2 x f7 Vormvaste grondstoffen, gebonden met gips_Regenwaterafvoer-x | 33.6901
f7 Vormvaste grondstoffen, gebonden met gips_Regenwaterafvoer-x | 0

# IfcBeam: Gipsplaat 13 x 275 (2)
In: 1e verdieping
Type - PredefinedType: BEAM
Material: Gipsplaat
Pset_BeamCommon - Slope: 0 deg; IsExternal: no; LoadBearing: yes; Reference: Gipsplaat 13 x 275
CPset_Phasing - Renovation Phase: Bestaand
Material Properties - Gipsplaat, ThermalConductivity: 0.23; Gipsplaat, SpecificHeatCapacity: 840 J/kg/K; Gipsplaat, MassDensity: 800 kg/m3; Gipsplaat, Embodied Energy: 6.75 (MJ/kg); Gipsplaat, Embodied Carbon: 0.38 (kgCO₂/kg); Gipsplaat, Name: Gipsplaat; Gipsplaat, Participates in Collision Detection: yes; Gipsplaat, Aardopwarmingsvermogen (GWP): 1.513; Gipsplaat, Ozonafbrekend Vermogen (ODP): 1.32e-07; Gipsplaat, Fotochemische Vermogen tot Ozonvorming (POCP): 0.000358; Gipsplaat, Verzuringsvermogen (AP): 0.0082; Gipsplaat, Eutrofiëringspotentieel (EP): 0.00138; Gipsplaat, Abiotisch Uitputtingspotentieel (voor niet fossiele hulpbronnen) (ADPE): 0.00000729; Gipsplaat, Abiotisch Uitputtingspotentieel (voor fossiele hulpbronnen) (ADPF): 25.04; Gipsplaat, Databron: https://www.oekobaudat.de/OEKOBAU.DAT/resource/processes/1a24808b-9116-422e-93fb-d435f74a038a?version=00.05.000

# IfcBeam: HEA140 140 x 133, h METAAL_Regenwaterafvoer-x
In: Begane grond
Type - PredefinedType: BEAM
Material: Metaal - Staal C
CPset_Phasing - Renovation Phase: Bestaand
Material Properties - Metaal - Staal C, ThermalConductivity: 52; Metaal - Staal C, SpecificHeatCapacity: 530 J/kg/K; Metaal - Staal C, MassDensity: 7950 kg/m3; Metaal - Staal C, Embodied Energy: 25 (MJ/kg); Metaal - Staal C, Embodied Carbon: 1.91 (kgCO₂/kg); Metaal - Staal C, Name: Metaal - Staal C; Metaal - Staal C, Participates in Collision Detection: yes; Metaal - Staal C, Aardopwarmingsvermogen (GWP): 323.71; Metaal - Staal C, Ozonafbrekend Vermogen (ODP): 0; Metaal - Staal C, Fotochemische Vermogen tot Ozonvorming (POCP): 0.17963; Metaal - Staal C, Verzuringsvermogen (AP): 0.43354; Metaal - Staal C, Eutrofiëringspotentieel (EP): 0.014961; Metaal - Staal C, Abiotisch Uitputtingspotentieel (voor niet fossiele hulpbronnen) (ADPE): 0.00080492; Metaal - Staal C, Abiotisch Uitputtingspotentieel (voor fossiele hulpbronnen) (ADPF): 2862.1; Metaal - Staal C, Databron: https://www.oekobaudat.de/OEKOBAU.DAT/resource/processes/a85fbb4a-60a0-4ba9-9cfa-cdfbe1ec7f00?version=00.01.000
Pset_BeamCommon - Slope: 0 deg; IsExternal: no; LoadBearing: yes; Reference: HEA140 140 x 133

# IfcBeam: HEB220 220 x 220, h METAAL_Regenwaterafvoer-x
In: Begane grond
Type - PredefinedType: BEAM
Material: Metaal - Staal C
Pset_BeamCommon - Slope: 0 deg; IsExternal: no; LoadBearing: yes; Reference: HEB220 220 x 220
CPset_Phasing - Renovation Phase: Bestaand
Material Properties - Metaal - Staal C, ThermalConductivity: 52; Metaal - Staal C, SpecificHeatCapacity: 530 J/kg/K; Metaal - Staal C, MassDensity: 7950 kg/m3; Metaal - Staal C, Embodied Energy: 25 (MJ/kg); Metaal - Staal C, Embodied Carbon: 1.91 (kgCO₂/kg); Metaal - Staal C, Name: Metaal - Staal C; Metaal - Staal C, Participates in Collision Detection: yes; Metaal - Staal C, Aardopwarmingsvermogen (GWP): 323.71; Metaal - Staal C, Ozonafbrekend Vermogen (ODP): 0; Metaal - Staal C, Fotochemische Vermogen tot Ozonvorming (POCP): 0.17963; Metaal - Staal C, Verzuringsvermogen (AP): 0.43354; Metaal - Staal C, Eutrofiëringspotentieel (EP): 0.014961; Metaal - Staal C, Abiotisch Uitputtingspotentieel (voor niet fossiele hulpbronnen) (ADPE): 0.00080492; Metaal - Staal C, Abiotisch Uitputtingspotentieel (voor fossiele hulpbronnen) (ADPF): 2862.1; Metaal - Staal C, Databron: https://www.oekobaudat.de/OEKOBAU.DAT/resource/processes/a85fbb4a-60a0-4ba9-9cfa-cdfbe1ec7f00?version=00.01.000

# IfcBeam: HEB260 260 x 260 (7)
Type - PredefinedType: BEAM
Material: Metaal - Staal C
CPset_Phasing - Renovation Phase: Bestaand
Material Properties - Metaal - Staal C, ThermalConductivity: 52; Metaal - Staal C, SpecificHeatCapacity: 530 J/kg/K; Metaal - Staal C, MassDensity: 7950 kg/m3; Metaal - Staal C, Embodied Energy: 25 (MJ/kg); Metaal - Staal C, Embodied Carbon: 1.91 (kgCO₂/kg); Metaal - Staal C, Name: Metaal - Staal C; Metaal - Staal C, Participates in Collision Detection: yes; Metaal - Staal C, Aardopwarmingsvermogen (GWP): 323.71; Metaal - Staal C, Ozonafbrekend Vermogen (ODP): 0; Metaal - Staal C, Fotochemische Vermogen tot Ozonvorming (POCP): 0.17963; Metaal - Staal C, Verzuringsvermogen (AP): 0.43354; Metaal - Staal C, Eutrofiëringspotentieel (EP): 0.014961; Metaal - Staal C, Abiotisch Uitputtingspotentieel (voor niet fossiele hulpbronnen) (ADPE): 0.00080492; Metaal - Staal C, Abiotisch Uitputtingspotentieel (voor fossiele hulpbronnen) (ADPF): 2862.1; Metaal - Staal C, Databron: https://www.oekobaudat.de/OEKOBAU.DAT/resource/processes/a85fbb4a-60a0-4ba9-9cfa-cdfbe1ec7f00?version=00.01.000
Pset_BeamCommon - Slope: 0 deg; IsExternal: no; LoadBearing: yes; Reference: HEB260 260 x 260
Name | In
2 x h METAAL_Regenwaterafvoer-x | Kelder
2 x h METAAL_Regenwaterafvoer-x | Begane grond
3 x h METAAL_Regenwaterafvoer-x | 1e verdieping

# IfcBeam: HEB360 300 x 360, h METAAL_Regenwaterafvoer-x
In: Kelder
Type - PredefinedType: BEAM
Material: Metaal - Staal C
Pset_BeamCommon - Slope: 0 deg; IsExternal: no; LoadBearing: yes; Reference: HEB360 300 x 360
Material Properties - Metaal - Staal C, ThermalConductivity: 52; Metaal - Staal C, SpecificHeatCapacity: 530 J/kg/K; Metaal - Staal C, MassDensity: 7950 kg/m3; Metaal - Staal C, Embodied Energy: 25 (MJ/kg); Metaal - Staal C, Embodied Carbon: 1.91 (kgCO₂/kg); Metaal - Staal C, Name: Metaal - Staal C; Metaal - Staal C, Participates in Collision Detection: yes; Metaal - Staal C, Aardopwarmingsvermogen (GWP): 323.71; Metaal - Staal C, Ozonafbrekend Vermogen (ODP): 0; Metaal - Staal C, Fotochemische Vermogen tot Ozonvorming (POCP): 0.17963; Metaal - Staal C, Verzuringsvermogen (AP): 0.43354; Metaal - Staal C, Eutrofiëringspotentieel (EP): 0.014961; Metaal - Staal C, Abiotisch Uitputtingspotentieel (voor niet fossiele hulpbronnen) (ADPE): 0.00080492; Metaal - Staal C, Abiotisch Uitputtingspotentieel (voor fossiele hulpbronnen) (ADPF): 2862.1; Metaal - Staal C, Databron: https://www.oekobaudat.de/OEKOBAU.DAT/resource/processes/a85fbb4a-60a0-4ba9-9cfa-cdfbe1ec7f00?version=00.01.000
CPset_Phasing - Renovation Phase: Bestaand

# IfcBeam: HEM360 308 x 395 (2)
In: Begane grond
Type - PredefinedType: BEAM
Material: Metaal - Staal C
Pset_BeamCommon - Slope: 0 deg; IsExternal: no; LoadBearing: yes; Reference: HEM360 308 x 395
CPset_Phasing - Renovation Phase: Bestaand
Material Properties - Metaal - Staal C, ThermalConductivity: 52; Metaal - Staal C, SpecificHeatCapacity: 530 J/kg/K; Metaal - Staal C, MassDensity: 7950 kg/m3; Metaal - Staal C, Embodied Energy: 25 (MJ/kg); Metaal - Staal C, Embodied Carbon: 1.91 (kgCO₂/kg); Metaal - Staal C, Name: Metaal - Staal C; Metaal - Staal C, Participates in Collision Detection: yes; Metaal - Staal C, Aardopwarmingsvermogen (GWP): 323.71; Metaal - Staal C, Ozonafbrekend Vermogen (ODP): 0; Metaal - Staal C, Fotochemische Vermogen tot Ozonvorming (POCP): 0.17963; Metaal - Staal C, Verzuringsvermogen (AP): 0.43354; Metaal - Staal C, Eutrofiëringspotentieel (EP): 0.014961; Metaal - Staal C, Abiotisch Uitputtingspotentieel (voor niet fossiele hulpbronnen) (ADPE): 0.00080492; Metaal - Staal C, Abiotisch Uitputtingspotentieel (voor fossiele hulpbronnen) (ADPF): 2862.1; Metaal - Staal C, Databron: https://www.oekobaudat.de/OEKOBAU.DAT/resource/processes/a85fbb4a-60a0-4ba9-9cfa-cdfbe1ec7f00?version=00.01.000

# IfcBeam: Hout - Multiplex 280 x 20, i4 In lagen verlijmd hout_Regenwaterafvoer-x
In: Begane grond
Type - PredefinedType: BEAM
Material: Hout - Multiplex
Pset_BeamCommon - Slope: 33.6901 deg; IsExternal: no; LoadBearing: yes; Reference: Hout - Multiplex 280 x 20
CPset_Phasing - Renovation Phase: Bestaand
Material Properties - Hout - Multiplex, ThermalConductivity: 0.17; Hout - Multiplex, SpecificHeatCapacity: 1600 J/kg/K; Hout - Multiplex, MassDensity: 700 kg/m3; Hout - Multiplex, Embodied Energy: 15 (MJ/kg); Hout - Multiplex, Embodied Carbon: 0.77 (kgCO₂/kg); Hout - Multiplex, Name: Hout - Multiplex; Hout - Multiplex, Participates in Collision Detection: yes; Hout - Multiplex, Aardopwarmingsvermogen (GWP): -32.4496; Hout - Multiplex, Ozonafbrekend Vermogen (ODP): 0; Hout - Multiplex, Fotochemische Vermogen tot Ozonvorming (POCP): -0.00287346; Hout - Multiplex, Verzuringsvermogen (AP): 0.138611; Hout - Multiplex, Eutrofiëringspotentieel (EP): 0.0523292; Hout - Multiplex, Abiotisch Uitputtingspotentieel (voor niet fossiele hulpbronnen) (ADPE): -0.0000777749; Hout - Multiplex, Abiotisch Uitputtingspotentieel (voor fossiele hulpbronnen) (ADPF): -4006.31; Hout - Multiplex, Databron: https://www.oekobaudat.de/OEKOBAU.DAT/resource/processes/cc180aec-8a5c-4e07-b1a0-1ab81dd746ac?version=20.20.120

# IfcBeam: Hout C 59 x 171 (5)
In: 2e dakoverzicht
Type - PredefinedType: BEAM
Material: Hout C
Pset_BeamCommon - Slope: 0 deg; IsExternal: no; LoadBearing: yes; Reference: Hout C 59 x 171
CPset_Phasing - Renovation Phase: Bestaand
Material Properties - Hout C, ThermalConductivity: 0.14; Hout C, SpecificHeatCapacity: 1880 J/kg/K; Hout C, MassDensity: 550 kg/m3; Hout C, Embodied Energy: 7.4 (MJ/kg); Hout C, Embodied Carbon: 0.19 (kgCO₂/kg); Hout C, Name: Hout C; Hout C, Participates in Collision Detection: yes; Hout C, Aardopwarmingsvermogen (GWP): -349.478; Hout C, Ozonafbrekend Vermogen (ODP): 0; Hout C, Fotochemische Vermogen tot Ozonvorming (POCP): -0.028; Hout C, Verzuringsvermogen (AP): -0.352; Hout C, Eutrofiëringspotentieel (EP): -0.059; Hout C, Abiotisch Uitputtingspotentieel (voor fossiele hulpbronnen) (ADPF): -3860.46; Hout C, Databron: https://www.oekobaudat.de/OEKOBAU.DAT/resource/processes/07a5482a-fa4a-484d-8929-b6f6dfd6be3e?version=00.00.027

# IfcBeam: IPE100 55 x 100 (3)
In: 1e verdieping
Type - PredefinedType: BEAM
Material: Metaal - Staal C
Pset_BeamCommon - Slope: 0 deg; IsExternal: no; LoadBearing: yes; Reference: IPE100 55 x 100
CPset_Phasing - Renovation Phase: Bestaand
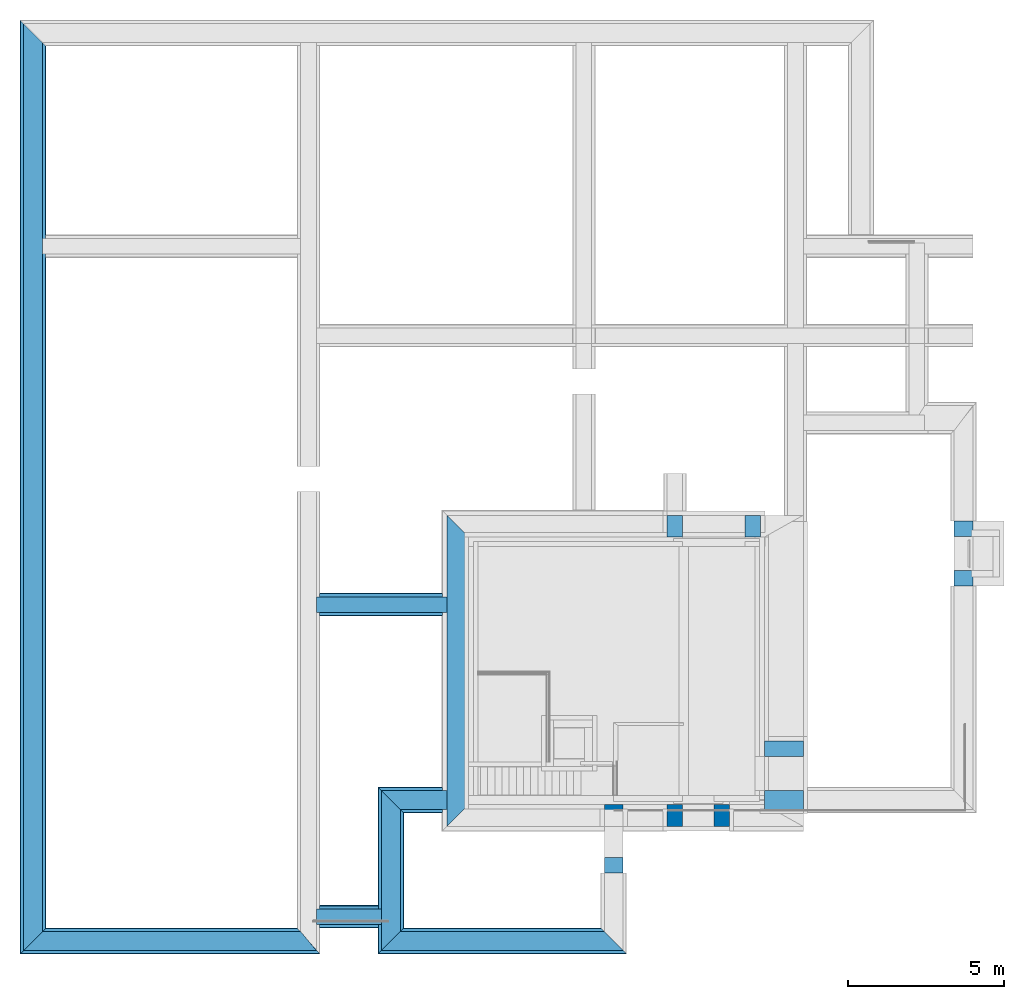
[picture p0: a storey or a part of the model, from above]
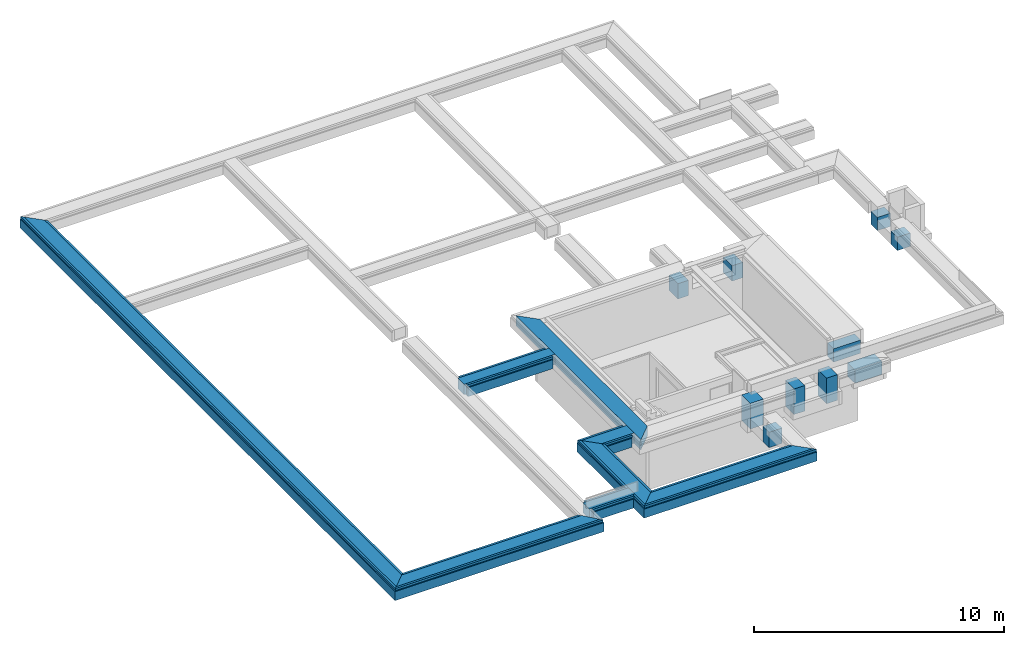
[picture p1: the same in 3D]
Properties of the parts of a building model (IFC2X3), part 2 of 7

# IfcBeam: IPE100 55 x 100 (3)
Material Properties - Metaal - Staal C, ThermalConductivity: 52; Metaal - Staal C, SpecificHeatCapacity: 530 J/kg/K; Metaal - Staal C, MassDensity: 7950 kg/m3; Metaal - Staal C, Embodied Energy: 25 (MJ/kg); Metaal - Staal C, Embodied Carbon: 1.91 (kgCO₂/kg); Metaal - Staal C, Name: Metaal - Staal C; Metaal - Staal C, Participates in Collision Detection: yes; Metaal - Staal C, Aardopwarmingsvermogen (GWP): 323.71; Metaal - Staal C, Ozonafbrekend Vermogen (ODP): 0; Metaal - Staal C, Fotochemische Vermogen tot Ozonvorming (POCP): 0.17963; Metaal - Staal C, Verzuringsvermogen (AP): 0.43354; Metaal - Staal C, Eutrofiëringspotentieel (EP): 0.014961; Metaal - Staal C, Abiotisch Uitputtingspotentieel (voor niet fossiele hulpbronnen) (ADPE): 0.00080492; Metaal - Staal C, Abiotisch Uitputtingspotentieel (voor fossiele hulpbronnen) (ADPF): 2862.1; Metaal - Staal C, Databron: https://www.oekobaudat.de/OEKOBAU.DAT/resource/processes/a85fbb4a-60a0-4ba9-9cfa-cdfbe1ec7f00?version=00.01.000

# IfcBeam: IPE180 91 x 180 (11)
In: 2e dakoverzicht
Type - PredefinedType: BEAM
Material: Metaal - Staal C
Pset_BeamCommon - Slope: 0 deg; IsExternal: no; LoadBearing: yes; Reference: IPE180 91 x 180
Material Properties - Metaal - Staal C, ThermalConductivity: 52; Metaal - Staal C, SpecificHeatCapacity: 530 J/kg/K; Metaal - Staal C, MassDensity: 7950 kg/m3; Metaal - Staal C, Embodied Energy: 25 (MJ/kg); Metaal - Staal C, Embodied Carbon: 1.91 (kgCO₂/kg); Metaal - Staal C, Name: Metaal - Staal C; Metaal - Staal C, Participates in Collision Detection: yes; Metaal - Staal C, Aardopwarmingsvermogen (GWP): 323.71; Metaal - Staal C, Ozonafbrekend Vermogen (ODP): 0; Metaal - Staal C, Fotochemische Vermogen tot Ozonvorming (POCP): 0.17963; Metaal - Staal C, Verzuringsvermogen (AP): 0.43354; Metaal - Staal C, Eutrofiëringspotentieel (EP): 0.014961; Metaal - Staal C, Abiotisch Uitputtingspotentieel (voor niet fossiele hulpbronnen) (ADPE): 0.00080492; Metaal - Staal C, Abiotisch Uitputtingspotentieel (voor fossiele hulpbronnen) (ADPF): 2862.1; Metaal - Staal C, Databron: https://www.oekobaudat.de/OEKOBAU.DAT/resource/processes/a85fbb4a-60a0-4ba9-9cfa-cdfbe1ec7f00?version=00.01.000
CPset_Phasing - Renovation Phase: Bestaand

# IfcBeam: IPE270 135 x 270, h METAAL_Regenwaterafvoer-x
In: Kelder
Type - PredefinedType: BEAM
Material: Metaal - Staal C
Pset_BeamCommon - Slope: 0 deg; IsExternal: no; LoadBearing: yes; Reference: IPE270 135 x 270
CPset_Phasing - Renovation Phase: Bestaand
Material Properties - Metaal - Staal C, ThermalConductivity: 52; Metaal - Staal C, SpecificHeatCapacity: 530 J/kg/K; Metaal - Staal C, MassDensity: 7950 kg/m3; Metaal - Staal C, Embodied Energy: 25 (MJ/kg); Metaal - Staal C, Embodied Carbon: 1.91 (kgCO₂/kg); Metaal - Staal C, Name: Metaal - Staal C; Metaal - Staal C, Participates in Collision Detection: yes; Metaal - Staal C, Aardopwarmingsvermogen (GWP): 323.71; Metaal - Staal C, Ozonafbrekend Vermogen (ODP): 0; Metaal - Staal C, Fotochemische Vermogen tot Ozonvorming (POCP): 0.17963; Metaal - Staal C, Verzuringsvermogen (AP): 0.43354; Metaal - Staal C, Eutrofiëringspotentieel (EP): 0.014961; Metaal - Staal C, Abiotisch Uitputtingspotentieel (voor niet fossiele hulpbronnen) (ADPE): 0.00080492; Metaal - Staal C, Abiotisch Uitputtingspotentieel (voor fossiele hulpbronnen) (ADPF): 2862.1; Metaal - Staal C, Databron: https://www.oekobaudat.de/OEKOBAU.DAT/resource/processes/a85fbb4a-60a0-4ba9-9cfa-cdfbe1ec7f00?version=00.01.000

# IfcBeam: L200X100X10 100 x 200 (4)
In: Begane grond
Type - PredefinedType: BEAM
Material: Metaal - Staal C
Pset_BeamCommon - Slope: 0 deg; IsExternal: no; LoadBearing: yes; Reference: L200X100X10 100 x 200
CPset_Phasing - Renovation Phase: Bestaand
Material Properties - Metaal - Staal C, ThermalConductivity: 52; Metaal - Staal C, SpecificHeatCapacity: 530 J/kg/K; Metaal - Staal C, MassDensity: 7950 kg/m3; Metaal - Staal C, Embodied Energy: 25 (MJ/kg); Metaal - Staal C, Embodied Carbon: 1.91 (kgCO₂/kg); Metaal - Staal C, Name: Metaal - Staal C; Metaal - Staal C, Participates in Collision Detection: yes; Metaal - Staal C, Aardopwarmingsvermogen (GWP): 323.71; Metaal - Staal C, Ozonafbrekend Vermogen (ODP): 0; Metaal - Staal C, Fotochemische Vermogen tot Ozonvorming (POCP): 0.17963; Metaal - Staal C, Verzuringsvermogen (AP): 0.43354; Metaal - Staal C, Eutrofiëringspotentieel (EP): 0.014961; Metaal - Staal C, Abiotisch Uitputtingspotentieel (voor niet fossiele hulpbronnen) (ADPE): 0.00080492; Metaal - Staal C, Abiotisch Uitputtingspotentieel (voor fossiele hulpbronnen) (ADPF): 2862.1; Metaal - Staal C, Databron: https://www.oekobaudat.de/OEKOBAU.DAT/resource/processes/a85fbb4a-60a0-4ba9-9cfa-cdfbe1ec7f00?version=00.01.000

# IfcBeam: Luchtzakken 500mm 500 x 265 (11)
Type - PredefinedType: BEAM
CPset_Phasing - Renovation Phase: Bestaand
Pset_BeamCommon - Slope: 0 deg; IsExternal: no; LoadBearing: yes; Reference: Luchtzakken 500mm 500 x 265
Name | In
6 x _Regenwaterafvoer-x | Begane grond
5 x _Regenwaterafvoer-x | 1e verdieping

# IfcBeam: Metaal - Staal C 15 x 120 (20)
Type - PredefinedType: BEAM
Material: Metaal - Staal C
Pset_BeamCommon - IsExternal: no; LoadBearing: yes; Reference: Metaal - Staal C 15 x 120
CPset_Phasing - Renovation Phase: Bestaand
Material Properties - Metaal - Staal C, ThermalConductivity: 52; Metaal - Staal C, SpecificHeatCapacity: 530 J/kg/K; Metaal - Staal C, MassDensity: 7950 kg/m3; Metaal - Staal C, Embodied Energy: 25 (MJ/kg); Metaal - Staal C, Embodied Carbon: 1.91 (kgCO₂/kg); Metaal - Staal C, Name: Metaal - Staal C; Metaal - Staal C, Participates in Collision Detection: yes; Metaal - Staal C, Aardopwarmingsvermogen (GWP): 323.71; Metaal - Staal C, Ozonafbrekend Vermogen (ODP): 0; Metaal - Staal C, Fotochemische Vermogen tot Ozonvorming (POCP): 0.17963; Metaal - Staal C, Verzuringsvermogen (AP): 0.43354; Metaal - Staal C, Eutrofiëringspotentieel (EP): 0.014961; Metaal - Staal C, Abiotisch Uitputtingspotentieel (voor niet fossiele hulpbronnen) (ADPE): 0.00080492; Metaal - Staal C, Abiotisch Uitputtingspotentieel (voor fossiele hulpbronnen) (ADPF): 2862.1; Metaal - Staal C, Databron: https://www.oekobaudat.de/OEKOBAU.DAT/resource/processes/a85fbb4a-60a0-4ba9-9cfa-cdfbe1ec7f00?version=00.01.000
Name | In | Slope (deg)
2 x h METAAL_Regenwaterafvoer-x | Begane grond | 47.9713
2 x h METAAL_Regenwaterafvoer-x | Begane grond | 34.952
2 x h METAAL_Regenwaterafvoer-x | Begane grond | 51.4044
2 x h METAAL_Regenwaterafvoer-x | Begane grond | 36.5596
2 x h METAAL_Regenwaterafvoer-x | Begane grond | 66.2052
2 x h METAAL_Regenwaterafvoer-x | Begane grond | 72.5176
2 x h METAAL_Regenwaterafvoer-x | 1e verdieping | 34.952
2 x h METAAL_Regenwaterafvoer-x | 1e verdieping | 51.5506
2 x h METAAL_Regenwaterafvoer-x | 1e verdieping | 36.5596
2 x h METAAL_Regenwaterafvoer-x | 1e verdieping | 51.048

# IfcBeam: T140 140 x 140 (4)
In: Begane grond
Type - PredefinedType: BEAM
Material: Metaal - Staal C
Material Properties - Metaal - Staal C, ThermalConductivity: 52; Metaal - Staal C, SpecificHeatCapacity: 530 J/kg/K; Metaal - Staal C, MassDensity: 7950 kg/m3; Metaal - Staal C, Embodied Energy: 25 (MJ/kg); Metaal - Staal C, Embodied Carbon: 1.91 (kgCO₂/kg); Metaal - Staal C, Name: Metaal - Staal C; Metaal - Staal C, Participates in Collision Detection: yes; Metaal - Staal C, Aardopwarmingsvermogen (GWP): 323.71; Metaal - Staal C, Ozonafbrekend Vermogen (ODP): 0; Metaal - Staal C, Fotochemische Vermogen tot Ozonvorming (POCP): 0.17963; Metaal - Staal C, Verzuringsvermogen (AP): 0.43354; Metaal - Staal C, Eutrofiëringspotentieel (EP): 0.014961; Metaal - Staal C, Abiotisch Uitputtingspotentieel (voor niet fossiele hulpbronnen) (ADPE): 0.00080492; Metaal - Staal C, Abiotisch Uitputtingspotentieel (voor fossiele hulpbronnen) (ADPF): 2862.1; Metaal - Staal C, Databron: https://www.oekobaudat.de/OEKOBAU.DAT/resource/processes/a85fbb4a-60a0-4ba9-9cfa-cdfbe1ec7f00?version=00.01.000
Pset_BeamCommon - Slope: 0 deg; IsExternal: no; LoadBearing: yes; Reference: T140 140 x 140
CPset_Phasing - Renovation Phase: Bestaand

# IfcBeam: UNP160 65 x 160 (3)
In: 1e verdieping
Type - PredefinedType: BEAM
Material: Metaal - Staal C
CPset_Phasing - Renovation Phase: Bestaand
Pset_BeamCommon - Slope: 0 deg; IsExternal: no; LoadBearing: yes; Reference: UNP160 65 x 160
Material Properties - Metaal - Staal C, ThermalConductivity: 52; Metaal - Staal C, SpecificHeatCapacity: 530 J/kg/K; Metaal - Staal C, MassDensity: 7950 kg/m3; Metaal - Staal C, Embodied Energy: 25 (MJ/kg); Metaal - Staal C, Embodied Carbon: 1.91 (kgCO₂/kg); Metaal - Staal C, Name: Metaal - Staal C; Metaal - Staal C, Participates in Collision Detection: yes; Metaal - Staal C, Aardopwarmingsvermogen (GWP): 323.71; Metaal - Staal C, Ozonafbrekend Vermogen (ODP): 0; Metaal - Staal C, Fotochemische Vermogen tot Ozonvorming (POCP): 0.17963; Metaal - Staal C, Verzuringsvermogen (AP): 0.43354; Metaal - Staal C, Eutrofiëringspotentieel (EP): 0.014961; Metaal - Staal C, Abiotisch Uitputtingspotentieel (voor niet fossiele hulpbronnen) (ADPE): 0.00080492; Metaal - Staal C, Abiotisch Uitputtingspotentieel (voor fossiele hulpbronnen) (ADPF): 2862.1; Metaal - Staal C, Databron: https://www.oekobaudat.de/OEKOBAU.DAT/resource/processes/a85fbb4a-60a0-4ba9-9cfa-cdfbe1ec7f00?version=00.01.000

# IfcBeam: UNP180 70 x 180 (2)
In: 2e dakoverzicht
Type - PredefinedType: BEAM
Material: Metaal - Staal C
Pset_BeamCommon - Slope: 0 deg; IsExternal: no; LoadBearing: yes; Reference: UNP180 70 x 180
CPset_Phasing - Renovation Phase: Bestaand
Material Properties - Metaal - Staal C, ThermalConductivity: 52; Metaal - Staal C, SpecificHeatCapacity: 530 J/kg/K; Metaal - Staal C, MassDensity: 7950 kg/m3; Metaal - Staal C, Embodied Energy: 25 (MJ/kg); Metaal - Staal C, Embodied Carbon: 1.91 (kgCO₂/kg); Metaal - Staal C, Name: Metaal - Staal C; Metaal - Staal C, Participates in Collision Detection: yes; Metaal - Staal C, Aardopwarmingsvermogen (GWP): 323.71; Metaal - Staal C, Ozonafbrekend Vermogen (ODP): 0; Metaal - Staal C, Fotochemische Vermogen tot Ozonvorming (POCP): 0.17963; Metaal - Staal C, Verzuringsvermogen (AP): 0.43354; Metaal - Staal C, Eutrofiëringspotentieel (EP): 0.014961; Metaal - Staal C, Abiotisch Uitputtingspotentieel (voor niet fossiele hulpbronnen) (ADPE): 0.00080492; Metaal - Staal C, Abiotisch Uitputtingspotentieel (voor fossiele hulpbronnen) (ADPF): 2862.1; Metaal - Staal C, Databron: https://www.oekobaudat.de/OEKOBAU.DAT/resource/processes/a85fbb4a-60a0-4ba9-9cfa-cdfbe1ec7f00?version=00.01.000

# IfcBeam: UNP260 90 x 260 (6)
Type - PredefinedType: BEAM
Material: Metaal - Staal C
CPset_Phasing - Renovation Phase: Bestaand
Material Properties - Metaal - Staal C, ThermalConductivity: 52; Metaal - Staal C, SpecificHeatCapacity: 530 J/kg/K; Metaal - Staal C, MassDensity: 7950 kg/m3; Metaal - Staal C, Embodied Energy: 25 (MJ/kg); Metaal - Staal C, Embodied Carbon: 1.91 (kgCO₂/kg); Metaal - Staal C, Name: Metaal - Staal C; Metaal - Staal C, Participates in Collision Detection: yes; Metaal - Staal C, Aardopwarmingsvermogen (GWP): 323.71; Metaal - Staal C, Ozonafbrekend Vermogen (ODP): 0; Metaal - Staal C, Fotochemische Vermogen tot Ozonvorming (POCP): 0.17963; Metaal - Staal C, Verzuringsvermogen (AP): 0.43354; Metaal - Staal C, Eutrofiëringspotentieel (EP): 0.014961; Metaal - Staal C, Abiotisch Uitputtingspotentieel (voor niet fossiele hulpbronnen) (ADPE): 0.00080492; Metaal - Staal C, Abiotisch Uitputtingspotentieel (voor fossiele hulpbronnen) (ADPF): 2862.1; Metaal - Staal C, Databron: https://www.oekobaudat.de/OEKOBAU.DAT/resource/processes/a85fbb4a-60a0-4ba9-9cfa-cdfbe1ec7f00?version=00.01.000
Pset_BeamCommon - Slope: 0 deg; IsExternal: no; LoadBearing: yes; Reference: UNP260 90 x 260
Name | In
h METAAL_Regenwaterafvoer-x | Kelder
3 x h METAAL_Regenwaterafvoer-x | Begane grond
2 x h METAAL_Regenwaterafvoer-x | 1e verdieping

# IfcBeam: balk_gen_ø42,4*5 windligger 42 x 42 (8)
In: Begane grond
Type - PredefinedType: BEAM
Material: h2_staal_gen
Pset_BeamCommon - Slope: 0 deg; IsExternal: no; LoadBearing: yes; Reference: balk_gen_ø42,4*5 windligger 42 x 42
CPset_Phasing - Renovation Phase: Bestaand
Material Properties - h2_staal_gen, ThermalConductivity: 2.3; h2_staal_gen, SpecificHeatCapacity: 1000 J/kg/K; h2_staal_gen, MassDensity: 2300 kg/m3; h2_staal_gen, Embodied Energy: 1.92 (MJ/kg); h2_staal_gen, Embodied Carbon: 0.198 (kgCO₂/kg); h2_staal_gen, Name: h2_staal_gen; h2_staal_gen, Participates in Collision Detection: yes

# IfcBeam: balk_gen_ø88.9x8 windligger 89 x 89 (2)
In: Begane grond
Type - PredefinedType: BEAM
Material: h2_staal_gen
CPset_Phasing - Renovation Phase: Bestaand
Material Properties - h2_staal_gen, ThermalConductivity: 2.3; h2_staal_gen, SpecificHeatCapacity: 1000 J/kg/K; h2_staal_gen, MassDensity: 2300 kg/m3; h2_staal_gen, Embodied Energy: 1.92 (MJ/kg); h2_staal_gen, Embodied Carbon: 0.198 (kgCO₂/kg); h2_staal_gen, Name: h2_staal_gen; h2_staal_gen, Participates in Collision Detection: yes
Pset_BeamCommon - Slope: 0 deg; IsExternal: no; LoadBearing: yes; Reference: balk_gen_ø88.9x8 windligger 89 x 89

# IfcBuildingElementPart (1646)
Name | In | Material | Renovation Phase
4 x Isolatie - Kunststof hard | Kelder | Isolatie - Kunststof hard | Bestaand | Material Properties - Isolatie - Kunststof hard, ThermalConductivity: 0.029; Isolatie - Kunststof hard, SpecificHeatCapacity: 1470 J/kg/K; Isolatie - Kunststof hard, MassDensity: 100 kg/m3; Isolatie - Kunststof hard, Embodied Energy: 101.5 (MJ/kg); Isolatie - Kunststof hard, Embodied Carbon: 3.48 (kgCO₂/kg); Isolatie - Kunststof hard, Name: Isolatie - Kunststof hard; Isolatie - Kunststof hard, Participates in Collision Detection: yes; Isolatie - Kunststof hard, Aardopwarmingsvermogen (GWP): 0.04; Isolatie - Kunststof hard, Ozonafbrekend Vermogen (ODP): 0; Isolatie - Kunststof hard, Fotochemische Vermogen tot Ozonvorming (POCP): 0; Isolatie - Kunststof hard, Verzuringsvermogen (AP): 0.0000975; Isolatie - Kunststof hard, Eutrofiëringspotentieel (EP): 0.0000237; Isolatie - Kunststof hard, Abiotisch Uitputtingspotentieel (voor niet fossiele hulpbronnen) (ADPE): 0; Isolatie - Kunststof hard, Abiotisch Uitputtingspotentieel (voor fossiele hulpbronnen) (ADPF): 0.47; Isolatie - Kunststof hard, Databron: https://www.oekobaudat.de/OEKOBAU.DAT/resource/processes/41e09ab7-0e73-4303-84fd-97cb0809db02?version=00.04.000
4 x Cementgebonden plaatmateriaal | Kelder | Cementgebonden plaatmateriaal | Bestaand | Material Properties - Cementgebonden plaatmateriaal, ThermalConductivity: 0.45; Cementgebonden plaatmateriaal, SpecificHeatCapacity: 840 J/kg/K; Cementgebonden plaatmateriaal, MassDensity: 1400 kg/m3; Cementgebonden plaatmateriaal, Embodied Energy: 6.75 (MJ/kg); Cementgebonden plaatmateriaal, Embodied Carbon: 0.38 (kgCO₂/kg); Cementgebonden plaatmateriaal, Name: Cementgebonden plaatmateriaal; Cementgebonden plaatmateriaal, Participates in Collision Detection: yes; Cementgebonden plaatmateriaal, Aardopwarmingsvermogen (GWP): 1.62283; Cementgebonden plaatmateriaal, Ozonafbrekend Vermogen (ODP): 0; Cementgebonden plaatmateriaal, Fotochemische Vermogen tot Ozonvorming (POCP): 33.9565; Cementgebonden plaatmateriaal, Verzuringsvermogen (AP): 0.000135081; Cementgebonden plaatmateriaal, Eutrofiëringspotentieel (EP): 0.00274111; Cementgebonden plaatmateriaal, Abiotisch Uitputtingspotentieel (voor niet fossiele hulpbronnen) (ADPE): 0; Cementgebonden plaatmateriaal, Abiotisch Uitputtingspotentieel (voor fossiele hulpbronnen) (ADPF): 0.000893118; Cementgebonden plaatmateriaal, Databron: https://www.oekobaudat.de/OEKOBAU.DAT/resource/processes/07423e99-8c7c-4e93-8311-dcf7ae85c41d?version=20.20.010
8 x Gipsplaat | Kelder | Gipsplaat | Material Properties - Gipsplaat, ThermalConductivity: 0.23; Gipsplaat, SpecificHeatCapacity: 840 J/kg/K; Gipsplaat, MassDensity: 800 kg/m3; Gipsplaat, Embodied Energy: 6.75 (MJ/kg); Gipsplaat, Embodied Carbon: 0.38 (kgCO₂/kg); Gipsplaat, Name: Gipsplaat; Gipsplaat, Participates in Collision Detection: yes; Gipsplaat, Aardopwarmingsvermogen (GWP): 1.513; Gipsplaat, Ozonafbrekend Vermogen (ODP): 1.32e-07; Gipsplaat, Fotochemische Vermogen tot Ozonvorming (POCP): 0.000358; Gipsplaat, Verzuringsvermogen (AP): 0.0082; Gipsplaat, Eutrofiëringspotentieel (EP): 0.00138; Gipsplaat, Abiotisch Uitputtingspotentieel (voor niet fossiele hulpbronnen) (ADPE): 0.00000729; Gipsplaat, Abiotisch Uitputtingspotentieel (voor fossiele hulpbronnen) (ADPF): 25.04; Gipsplaat, Databron: https://www.oekobaudat.de/OEKOBAU.DAT/resource/processes/1a24808b-9116-422e-93fb-d435f74a038a?version=00.05.000
3 x ALG - LICHTE SCHEIDINGSWAND | Kelder | ALG - LICHTE SCHEIDINGSWAND | Material Properties - ALG - LICHTE SCHEIDINGSWAND, ThermalConductivity: 0.27; ALG - LICHTE SCHEIDINGSWAND, SpecificHeatCapacity: 840 J/kg/K; ALG - LICHTE SCHEIDINGSWAND, MassDensity: 800 kg/m3; ALG - LICHTE SCHEIDINGSWAND, Embodied Energy: 2 (MJ/kg); ALG - LICHTE SCHEIDINGSWAND, Embodied Carbon: 0.13 (kgCO₂/kg); ALG - LICHTE SCHEIDINGSWAND, Name: ALG - LICHTE SCHEIDINGSWAND; ALG - LICHTE SCHEIDINGSWAND, Participates in Collision Detection: yes
90 x Metaal - Staal C | Begane grond | Metaal - Staal C | Bestaand | Material Properties - Metaal - Staal C, ThermalConductivity: 52; Metaal - Staal C, SpecificHeatCapacity: 530 J/kg/K; Metaal - Staal C, MassDensity: 7950 kg/m3; Metaal - Staal C, Embodied Energy: 25 (MJ/kg); Metaal - Staal C, Embodied Carbon: 1.91 (kgCO₂/kg); Metaal - Staal C, Name: Metaal - Staal C; Metaal - Staal C, Participates in Collision Detection: yes; Metaal - Staal C, Aardopwarmingsvermogen (GWP): 323.71; Metaal - Staal C, Ozonafbrekend Vermogen (ODP): 0; Metaal - Staal C, Fotochemische Vermogen tot Ozonvorming (POCP): 0.17963; Metaal - Staal C, Verzuringsvermogen (AP): 0.43354; Metaal - Staal C, Eutrofiëringspotentieel (EP): 0.014961; Metaal - Staal C, Abiotisch Uitputtingspotentieel (voor niet fossiele hulpbronnen) (ADPE): 0.00080492; Metaal - Staal C, Abiotisch Uitputtingspotentieel (voor fossiele hulpbronnen) (ADPF): 2862.1; Metaal - Staal C, Databron: https://www.oekobaudat.de/OEKOBAU.DAT/resource/processes/a85fbb4a-60a0-4ba9-9cfa-cdfbe1ec7f00?version=00.01.000
20 x Steen - Kalkzandsteen C | Begane grond | Steen - Kalkzandsteen C | Bestaand | Material Properties - Steen - Kalkzandsteen C, ThermalConductivity: 0.9; Steen - Kalkzandsteen C, SpecificHeatCapacity: 840 J/kg/K; Steen - Kalkzandsteen C, MassDensity: 1900 kg/m3; Steen - Kalkzandsteen C, Embodied Energy: 0.75 (MJ/kg); Steen - Kalkzandsteen C, Embodied Carbon: 0.1 (kgCO₂/kg); Steen - Kalkzandsteen C, Name: Steen - Kalkzandsteen C; Steen - Kalkzandsteen C, Participates in Collision Detection: yes; Steen - Kalkzandsteen C, Aardopwarmingsvermogen (GWP): 5.10595; Steen - Kalkzandsteen C, Ozonafbrekend Vermogen (ODP): 0; Steen - Kalkzandsteen C, Fotochemische Vermogen tot Ozonvorming (POCP): -0.00337081; Steen - Kalkzandsteen C, Verzuringsvermogen (AP): 0.0103135; Steen - Kalkzandsteen C, Eutrofiëringspotentieel (EP): 0.0024518; Steen - Kalkzandsteen C, Abiotisch Uitputtingspotentieel (voor niet fossiele hulpbronnen) (ADPE): 4.2967e-07; Steen - Kalkzandsteen C, Abiotisch Uitputtingspotentieel (voor fossiele hulpbronnen) (ADPF): 68.4425; Steen - Kalkzandsteen C, Databron: https://www.oekobaudat.de/OEKOBAU.DAT/resource/processes/bdda4364-451f-4df2-a68b-5912469ee4c9?version=20.19.120
12 x Steen - Baksteen | Begane grond | Steen - Baksteen | Bestaand | Material Properties - Steen - Baksteen, ThermalConductivity: 0.9; Steen - Baksteen, SpecificHeatCapacity: 840 J/kg/K; Steen - Baksteen, MassDensity: 1600 kg/m3; Steen - Baksteen, Embodied Energy: 3 (MJ/kg); Steen - Baksteen, Embodied Carbon: 0.23 (kgCO₂/kg); Steen - Baksteen, Name: Steen - Baksteen; Steen - Baksteen, Participates in Collision Detection: yes; Steen - Baksteen, Aardopwarmingsvermogen (GWP): 113; Steen - Baksteen, Ozonafbrekend Vermogen (ODP): 0; Steen - Baksteen, Fotochemische Vermogen tot Ozonvorming (POCP): 0.012; Steen - Baksteen, Verzuringsvermogen (AP): 0.094; Steen - Baksteen, Eutrofiëringspotentieel (EP): 0.0189; Steen - Baksteen, Abiotisch Uitputtingspotentieel (voor niet fossiele hulpbronnen) (ADPE): 0.0000099; Steen - Baksteen, Abiotisch Uitputtingspotentieel (voor fossiele hulpbronnen) (ADPF): 1150; Steen - Baksteen, Databron: https://www.oekobaudat.de/OEKOBAU.DAT/resource/processes/08dd0308-eebf-4db1-82ee-b340d070c9b9?version=00.06.000
13 x Isolatie - Steenwol zacht | Begane grond | Isolatie - Steenwol zacht | Bestaand | Material Properties - Isolatie - Steenwol zacht, ThermalConductivity: 0.035; Isolatie - Steenwol zacht, SpecificHeatCapacity: 840 J/kg/K; Isolatie - Steenwol zacht, MassDensity: 45 kg/m3; Isolatie - Steenwol zacht, Embodied Energy: 16.8 (MJ/kg); Isolatie - Steenwol zacht, Embodied Carbon: 1.05 (kgCO₂/kg); Isolatie - Steenwol zacht, Name: Isolatie - Steenwol zacht; Isolatie - Steenwol zacht, Participates in Collision Detection: yes; Isolatie - Steenwol zacht, Aardopwarmingsvermogen (GWP): -1.45742; Isolatie - Steenwol zacht, Fotochemische Vermogen tot Ozonvorming (POCP): -0.000168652; Isolatie - Steenwol zacht, Verzuringsvermogen (AP): -0.00166456; Isolatie - Steenwol zacht, Eutrofiëringspotentieel (EP): -0.000222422; Isolatie - Steenwol zacht, Abiotisch Uitputtingspotentieel (voor niet fossiele hulpbronnen) (ADPE): -2.57402e-07; Isolatie - Steenwol zacht, Abiotisch Uitputtingspotentieel (voor fossiele hulpbronnen) (ADPF): -20.4442; Isolatie - Steenwol zacht, Databron: https://www.oekobaudat.de/OEKOBAU.DAT/resource/processes/bd7319aa-d609-4f27-9460-d11bc966bb2b?version=00.03.000
4 x Glas | Begane grond | Glas | Material Properties - Glas, ThermalConductivity: 1.2; Glas, SpecificHeatCapacity: 795 J/kg/K; Glas, MassDensity: 2180 kg/m3; Glas, Embodied Energy: 15 (MJ/kg); Glas, Embodied Carbon: 0.86 (kgCO₂/kg); Glas, Name: Glas; Glas, Participates in Collision Detection: yes; Glas, Aardopwarmingsvermogen (GWP): 44.3346; Glas, Ozonafbrekend Vermogen (ODP): 0; Glas, Fotochemische Vermogen tot Ozonvorming (POCP): 0.0213557; Glas, Verzuringsvermogen (AP): 0.281643; Glas, Eutrofiëringspotentieel (EP): 0.0316879; Glas, Abiotisch Uitputtingspotentieel (voor niet fossiele hulpbronnen) (ADPE): 0.00000449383; Glas, Abiotisch Uitputtingspotentieel (voor fossiele hulpbronnen) (ADPF): 628.803; Glas, Databron: https://www.oekobaudat.de/OEKOBAU.DAT/resource/processes/1f2d6e42-9ffc-421d-990d-555eee4a7529?version=20.19.120
4 x  | Begane grond
8 x STO pleisterlaag | Begane grond | STO pleisterlaag | Bestaand | Material Properties - STO pleisterlaag, ThermalConductivity: 0; STO pleisterlaag, SpecificHeatCapacity: 0 J/kg/K; STO pleisterlaag, MassDensity: 0 kg/m3; STO pleisterlaag, Embodied Energy: 0 (MJ/kg); STO pleisterlaag, Embodied Carbon: 0 (kgCO₂/kg); STO pleisterlaag, Name: STO pleisterlaag; STO pleisterlaag, Participates in Collision Detection: yes
8 x STO weefsellaag | Begane grond | STO weefsellaag | Bestaand | Material Properties - STO weefsellaag, ThermalConductivity: 0; STO weefsellaag, SpecificHeatCapacity: 0 J/kg/K; STO weefsellaag, MassDensity: 0 kg/m3; STO weefsellaag, Embodied Energy: 0 (MJ/kg); STO weefsellaag, Embodied Carbon: 0 (kgCO₂/kg); STO weefsellaag, Name: STO weefsellaag; STO weefsellaag, Participates in Collision Detection: yes
18 x Isolatie - STO EPS | Begane grond | Isolatie - STO EPS | Bestaand | Material Properties - Isolatie - STO EPS, ThermalConductivity: 0.029; Isolatie - STO EPS, SpecificHeatCapacity: 1470 J/kg/K; Isolatie - STO EPS, MassDensity: 100 kg/m3; Isolatie - STO EPS, Embodied Energy: 101.5 (MJ/kg); Isolatie - STO EPS, Embodied Carbon: 3.48 (kgCO₂/kg); Isolatie - STO EPS, Name: Isolatie - STO EPS; Isolatie - STO EPS, Participates in Collision Detection: yes; Isolatie - STO EPS, Aardopwarmingsvermogen (GWP): 0.04; Isolatie - STO EPS, Ozonafbrekend Vermogen (ODP): 0; Isolatie - STO EPS, Fotochemische Vermogen tot Ozonvorming (POCP): 0; Isolatie - STO EPS, Verzuringsvermogen (AP): 0.0000975; Isolatie - STO EPS, Eutrofiëringspotentieel (EP): 0.0000237; Isolatie - STO EPS, Abiotisch Uitputtingspotentieel (voor niet fossiele hulpbronnen) (ADPE): 0; Isolatie - STO EPS, Abiotisch Uitputtingspotentieel (voor fossiele hulpbronnen) (ADPF): 0.47; Isolatie - STO EPS, Databron: https://www.oekobaudat.de/OEKOBAU.DAT/resource/processes/41e09ab7-0e73-4303-84fd-97cb0809db02?version=00.04.000
16 x STO lijmlaag | Begane grond | STO lijmlaag | Bestaand | Material Properties - STO lijmlaag, ThermalConductivity: 0; STO lijmlaag, SpecificHeatCapacity: 0 J/kg/K; STO lijmlaag, MassDensity: 0 kg/m3; STO lijmlaag, Embodied Energy: 0 (MJ/kg); STO lijmlaag, Embodied Carbon: 0 (kgCO₂/kg); STO lijmlaag, Name: STO lijmlaag; STO lijmlaag, Participates in Collision Detection: yes
ALG - ISOLATIE UITVULLING | Begane grond | ALG - ISOLATIE UITVULLING | Bestaand | Material Properties - ALG - ISOLATIE UITVULLING, ThermalConductivity: 0.035; ALG - ISOLATIE UITVULLING, SpecificHeatCapacity: 840 J/kg/K; ALG - ISOLATIE UITVULLING, MassDensity: 45 kg/m3; ALG - ISOLATIE UITVULLING, Embodied Energy: 16.8 (MJ/kg); ALG - ISOLATIE UITVULLING, Embodied Carbon: 1.05 (kgCO₂/kg); ALG - ISOLATIE UITVULLING, Name: ALG - ISOLATIE UITVULLING; ALG - ISOLATIE UITVULLING, Participates in Collision Detection: yes
3 x Cementgebonden plaatmateriaal | Begane grond | Cementgebonden plaatmateriaal | Bestaand | Material Properties - Cementgebonden plaatmateriaal, ThermalConductivity: 0.45; Cementgebonden plaatmateriaal, SpecificHeatCapacity: 840 J/kg/K; Cementgebonden plaatmateriaal, MassDensity: 1400 kg/m3; Cementgebonden plaatmateriaal, Embodied Energy: 6.75 (MJ/kg); Cementgebonden plaatmateriaal, Embodied Carbon: 0.38 (kgCO₂/kg); Cementgebonden plaatmateriaal, Name: Cementgebonden plaatmateriaal; Cementgebonden plaatmateriaal, Participates in Collision Detection: yes; Cementgebonden plaatmateriaal, Aardopwarmingsvermogen (GWP): 1.62283; Cementgebonden plaatmateriaal, Ozonafbrekend Vermogen (ODP): 0; Cementgebonden plaatmateriaal, Fotochemische Vermogen tot Ozonvorming (POCP): 33.9565; Cementgebonden plaatmateriaal, Verzuringsvermogen (AP): 0.000135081; Cementgebonden plaatmateriaal, Eutrofiëringspotentieel (EP): 0.00274111; Cementgebonden plaatmateriaal, Abiotisch Uitputtingspotentieel (voor niet fossiele hulpbronnen) (ADPE): 0; Cementgebonden plaatmateriaal, Abiotisch Uitputtingspotentieel (voor fossiele hulpbronnen) (ADPF): 0.000893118; Cementgebonden plaatmateriaal, Databron: https://www.oekobaudat.de/OEKOBAU.DAT/resource/processes/07423e99-8c7c-4e93-8311-dcf7ae85c41d?version=20.20.010
4 x Isolatie - Glaswol zacht | Begane grond | Isolatie - Glaswol zacht | Bestaand | Material Properties - Isolatie - Glaswol zacht, ThermalConductivity: 0.04; Isolatie - Glaswol zacht, SpecificHeatCapacity: 1030 J/kg/K; Isolatie - Glaswol zacht, MassDensity: 14 kg/m3; Isolatie - Glaswol zacht, Embodied Energy: 26 (MJ/kg); Isolatie - Glaswol zacht, Embodied Carbon: 1.3 (kgCO₂/kg); Isolatie - Glaswol zacht, Name: Isolatie - Glaswol zacht; Isolatie - Glaswol zacht, Participates in Collision Detection: yes; Isolatie - Glaswol zacht, Aardopwarmingsvermogen (GWP): 86.1825; Isolatie - Glaswol zacht, Ozonafbrekend Vermogen (ODP): 0; Isolatie - Glaswol zacht, Fotochemische Vermogen tot Ozonvorming (POCP): 0.000100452; Isolatie - Glaswol zacht, Verzuringsvermogen (AP): 0.00137534; Isolatie - Glaswol zacht, Eutrofiëringspotentieel (EP): 0.000312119; Isolatie - Glaswol zacht, Abiotisch Uitputtingspotentieel (voor niet fossiele hulpbronnen) (ADPE): 6.48446e-08; Isolatie - Glaswol zacht, Abiotisch Uitputtingspotentieel (voor fossiele hulpbronnen) (ADPF): 3.38861; Isolatie - Glaswol zacht, Databron: https://www.oekobaudat.de/OEKOBAU.DAT/resource/processes/5ef0c519-f5b2-4d45-809d-5f417f90e90b?version=20.19.120
4 x Rockpanel RAL 1001 | Begane grond | Rockpanel RAL 1001 | Bestaand | Material Properties - Rockpanel RAL 1001, ThermalConductivity: 0.45; Rockpanel RAL 1001, SpecificHeatCapacity: 840 J/kg/K; Rockpanel RAL 1001, MassDensity: 1400 kg/m3; Rockpanel RAL 1001, Embodied Energy: 6.75 (MJ/kg); Rockpanel RAL 1001, Embodied Carbon: 0.38 (kgCO₂/kg); Rockpanel RAL 1001, Name: Rockpanel RAL 1001; Rockpanel RAL 1001, Participates in Collision Detection: yes; Rockpanel RAL 1001, Aardopwarmingsvermogen (GWP): 1.62283; Rockpanel RAL 1001, Ozonafbrekend Vermogen (ODP): 0; Rockpanel RAL 1001, Fotochemische Vermogen tot Ozonvorming (POCP): 33.9565; Rockpanel RAL 1001, Verzuringsvermogen (AP): 0.000135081; Rockpanel RAL 1001, Eutrofiëringspotentieel (EP): 0.00274111; Rockpanel RAL 1001, Abiotisch Uitputtingspotentieel (voor niet fossiele hulpbronnen) (ADPE): 0; Rockpanel RAL 1001, Abiotisch Uitputtingspotentieel (voor fossiele hulpbronnen) (ADPF): 0.000893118; Rockpanel RAL 1001, Databron: https://www.oekobaudat.de/OEKOBAU.DAT/resource/processes/07423e99-8c7c-4e93-8311-dcf7ae85c41d?version=20.20.010
3 x Steen - Kalkzandsteen | Begane grond | Steen - Kalkzandsteen | Bestaand | Material Properties - Steen - Kalkzandsteen, ThermalConductivity: 0.9; Steen - Kalkzandsteen, SpecificHeatCapacity: 840 J/kg/K; Steen - Kalkzandsteen, MassDensity: 1900 kg/m3; Steen - Kalkzandsteen, Embodied Energy: 0.75 (MJ/kg); Steen - Kalkzandsteen, Embodied Carbon: 0.1 (kgCO₂/kg); Steen - Kalkzandsteen, Name: Steen - Kalkzandsteen; Steen - Kalkzandsteen, Participates in Collision Detection: yes; Steen - Kalkzandsteen, Aardopwarmingsvermogen (GWP): 1.69601; Steen - Kalkzandsteen, Ozonafbrekend Vermogen (ODP): 0; Steen - Kalkzandsteen, Fotochemische Vermogen tot Ozonvorming (POCP): -0.0042842; Steen - Kalkzandsteen, Verzuringsvermogen (AP): 0.0101137; Steen - Kalkzandsteen, Eutrofiëringspotentieel (EP): 0.00257216; Steen - Kalkzandsteen, Abiotisch Uitputtingspotentieel (voor niet fossiele hulpbronnen) (ADPE): 1.44694e-07; Steen - Kalkzandsteen, Abiotisch Uitputtingspotentieel (voor fossiele hulpbronnen) (ADPF): 23.0485; Steen - Kalkzandsteen, Databron: https://www.oekobaudat.de/OEKOBAU.DAT/resource/processes/a758fb6a-7fb1-4cdc-b652-c42cf2f7632c?version=20.20.020
12 x Isolatie - XPS zwevende dekvloer | Begane grond | Isolatie - XPS zwevende dekvloer | Bestaand | Material Properties - Isolatie - XPS zwevende dekvloer, ThermalConductivity: 0.034; Isolatie - XPS zwevende dekvloer, SpecificHeatCapacity: 1470 J/kg/K; Isolatie - XPS zwevende dekvloer, MassDensity: 35 kg/m3; Isolatie - XPS zwevende dekvloer, Embodied Energy: 88.6 (MJ/kg); Isolatie - XPS zwevende dekvloer, Embodied Carbon: 2.55 (kgCO₂/kg); Isolatie - XPS zwevende dekvloer, Name: Isolatie - XPS zwevende dekvloer; Isolatie - XPS zwevende dekvloer, Participates in Collision Detection: yes
38 x Beton gewapend C | Begane grond | Beton gewapend C | Bestaand | Material Properties - Beton gewapend C, ThermalConductivity: 2.3; Beton gewapend C, SpecificHeatCapacity: 1000 J/kg/K; Beton gewapend C, MassDensity: 2300 kg/m3; Beton gewapend C, Embodied Energy: 1.92 (MJ/kg); Beton gewapend C, Embodied Carbon: 0.198 (kgCO₂/kg); Beton gewapend C, Name: Beton gewapend C; Beton gewapend C, Participates in Collision Detection: yes; Beton gewapend C, Aardopwarmingsvermogen (GWP): -1.02642; Beton gewapend C, Ozonafbrekend Vermogen (ODP): 0; Beton gewapend C, Fotochemische Vermogen tot Ozonvorming (POCP): 0.000222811; Beton gewapend C, Verzuringsvermogen (AP): -0.00242385; Beton gewapend C, Eutrofiëringspotentieel (EP): -0.000471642; Beton gewapend C, Abiotisch Uitputtingspotentieel (voor niet fossiele hulpbronnen) (ADPE): -2.28121e-07; Beton gewapend C, Abiotisch Uitputtingspotentieel (voor fossiele hulpbronnen) (ADPF): -12.4095; Beton gewapend C, Databron: https://www.oekobaudat.de/OEKOBAU.DAT/resource/processes/d3b59cac-3b4e-4d18-8c3a-780b553c9591?version=20.19.120
20 x Isolatie - Kunststof hard | Begane grond | Isolatie - Kunststof hard | Bestaand | Material Properties - Isolatie - Kunststof hard, ThermalConductivity: 0.029; Isolatie - Kunststof hard, SpecificHeatCapacity: 1470 J/kg/K; Isolatie - Kunststof hard, MassDensity: 100 kg/m3; Isolatie - Kunststof hard, Embodied Energy: 101.5 (MJ/kg); Isolatie - Kunststof hard, Embodied Carbon: 3.48 (kgCO₂/kg); Isolatie - Kunststof hard, Name: Isolatie - Kunststof hard; Isolatie - Kunststof hard, Participates in Collision Detection: yes; Isolatie - Kunststof hard, Aardopwarmingsvermogen (GWP): 0.04; Isolatie - Kunststof hard, Ozonafbrekend Vermogen (ODP): 0; Isolatie - Kunststof hard, Fotochemische Vermogen tot Ozonvorming (POCP): 0; Isolatie - Kunststof hard, Verzuringsvermogen (AP): 0.0000975; Isolatie - Kunststof hard, Eutrofiëringspotentieel (EP): 0.0000237; Isolatie - Kunststof hard, Abiotisch Uitputtingspotentieel (voor niet fossiele hulpbronnen) (ADPE): 0; Isolatie - Kunststof hard, Abiotisch Uitputtingspotentieel (voor fossiele hulpbronnen) (ADPF): 0.47; Isolatie - Kunststof hard, Databron: https://www.oekobaudat.de/OEKOBAU.DAT/resource/processes/41e09ab7-0e73-4303-84fd-97cb0809db02?version=00.04.000
274 x Gipsplaat | Begane grond | Gipsplaat | Material Properties - Gipsplaat, ThermalConductivity: 0.23; Gipsplaat, SpecificHeatCapacity: 840 J/kg/K; Gipsplaat, MassDensity: 800 kg/m3; Gipsplaat, Embodied Energy: 6.75 (MJ/kg); Gipsplaat, Embodied Carbon: 0.38 (kgCO₂/kg); Gipsplaat, Name: Gipsplaat; Gipsplaat, Participates in Collision Detection: yes; Gipsplaat, Aardopwarmingsvermogen (GWP): 1.513; Gipsplaat, Ozonafbrekend Vermogen (ODP): 1.32e-07; Gipsplaat, Fotochemische Vermogen tot Ozonvorming (POCP): 0.000358; Gipsplaat, Verzuringsvermogen (AP): 0.0082; Gipsplaat, Eutrofiëringspotentieel (EP): 0.00138; Gipsplaat, Abiotisch Uitputtingspotentieel (voor niet fossiele hulpbronnen) (ADPE): 0.00000729; Gipsplaat, Abiotisch Uitputtingspotentieel (voor fossiele hulpbronnen) (ADPF): 25.04; Gipsplaat, Databron: https://www.oekobaudat.de/OEKOBAU.DAT/resource/processes/1a24808b-9116-422e-93fb-d435f74a038a?version=00.05.000
99 x ALG - LICHTE SCHEIDINGSWAND | Begane grond | ALG - LICHTE SCHEIDINGSWAND | Material Properties - ALG - LICHTE SCHEIDINGSWAND, ThermalConductivity: 0.27; ALG - LICHTE SCHEIDINGSWAND, SpecificHeatCapacity: 840 J/kg/K; ALG - LICHTE SCHEIDINGSWAND, MassDensity: 800 kg/m3; ALG - LICHTE SCHEIDINGSWAND, Embodied Energy: 2 (MJ/kg); ALG - LICHTE SCHEIDINGSWAND, Embodied Carbon: 0.13 (kgCO₂/kg); ALG - LICHTE SCHEIDINGSWAND, Name: ALG - LICHTE SCHEIDINGSWAND; ALG - LICHTE SCHEIDINGSWAND, Participates in Collision Detection: yes
Beton gewapend prefab vloer | Begane grond | Beton gewapend prefab vloer | Bestaand | Material Properties - Beton gewapend prefab vloer, ThermalConductivity: 2.5; Beton gewapend prefab vloer, SpecificHeatCapacity: 1000 J/kg/K; Beton gewapend prefab vloer, MassDensity: 2400 kg/m3; Beton gewapend prefab vloer, Embodied Energy: 2.33 (MJ/kg); Beton gewapend prefab vloer, Embodied Carbon: 0.242 (kgCO₂/kg); Beton gewapend prefab vloer, Name: Beton gewapend prefab vloer; Beton gewapend prefab vloer, Participates in Collision Detection: yes
5 x  | Begane grond |  | Bestaand
5 x Hout C | Begane grond | Hout C | Bestaand | Material Properties - Hout C, ThermalConductivity: 0.14; Hout C, SpecificHeatCapacity: 1880 J/kg/K; Hout C, MassDensity: 550 kg/m3; Hout C, Embodied Energy: 7.4 (MJ/kg); Hout C, Embodied Carbon: 0.19 (kgCO₂/kg); Hout C, Name: Hout C; Hout C, Participates in Collision Detection: yes; Hout C, Aardopwarmingsvermogen (GWP): -349.478; Hout C, Ozonafbrekend Vermogen (ODP): 0; Hout C, Fotochemische Vermogen tot Ozonvorming (POCP): -0.028; Hout C, Verzuringsvermogen (AP): -0.352; Hout C, Eutrofiëringspotentieel (EP): -0.059; Hout C, Abiotisch Uitputtingspotentieel (voor fossiele hulpbronnen) (ADPF): -3860.46; Hout C, Databron: https://www.oekobaudat.de/OEKOBAU.DAT/resource/processes/07a5482a-fa4a-484d-8929-b6f6dfd6be3e?version=00.00.027
ALG - ISOLATIE UITVULLING | Begane grond | ALG - ISOLATIE UITVULLING | Material Properties - ALG - ISOLATIE UITVULLING, ThermalConductivity: 0.035; ALG - ISOLATIE UITVULLING, SpecificHeatCapacity: 840 J/kg/K; ALG - ISOLATIE UITVULLING, MassDensity: 45 kg/m3; ALG - ISOLATIE UITVULLING, Embodied Energy: 16.8 (MJ/kg); ALG - ISOLATIE UITVULLING, Embodied Carbon: 1.05 (kgCO₂/kg); ALG - ISOLATIE UITVULLING, Name: ALG - ISOLATIE UITVULLING; ALG - ISOLATIE UITVULLING, Participates in Collision Detection: yes
Steen - Kalkzandsteen C | Begane grond | Steen - Kalkzandsteen C | Material Properties - Steen - Kalkzandsteen C, ThermalConductivity: 0.9; Steen - Kalkzandsteen C, SpecificHeatCapacity: 840 J/kg/K; Steen - Kalkzandsteen C, MassDensity: 1900 kg/m3; Steen - Kalkzandsteen C, Embodied Energy: 0.75 (MJ/kg); Steen - Kalkzandsteen C, Embodied Carbon: 0.1 (kgCO₂/kg); Steen - Kalkzandsteen C, Name: Steen - Kalkzandsteen C; Steen - Kalkzandsteen C, Participates in Collision Detection: yes; Steen - Kalkzandsteen C, Aardopwarmingsvermogen (GWP): 5.10595; Steen - Kalkzandsteen C, Ozonafbrekend Vermogen (ODP): 0; Steen - Kalkzandsteen C, Fotochemische Vermogen tot Ozonvorming (POCP): -0.00337081; Steen - Kalkzandsteen C, Verzuringsvermogen (AP): 0.0103135; Steen - Kalkzandsteen C, Eutrofiëringspotentieel (EP): 0.0024518; Steen - Kalkzandsteen C, Abiotisch Uitputtingspotentieel (voor niet fossiele hulpbronnen) (ADPE): 4.2967e-07; Steen - Kalkzandsteen C, Abiotisch Uitputtingspotentieel (voor fossiele hulpbronnen) (ADPF): 68.4425; Steen - Kalkzandsteen C, Databron: https://www.oekobaudat.de/OEKOBAU.DAT/resource/processes/bdda4364-451f-4df2-a68b-5912469ee4c9?version=20.19.120
Glas matte folie | Begane grond | Glas matte folie | Bestaand | Material Properties - Glas matte folie, ThermalConductivity: 1.2; Glas matte folie, SpecificHeatCapacity: 795 J/kg/K; Glas matte folie, MassDensity: 2180 kg/m3; Glas matte folie, Embodied Energy: 15 (MJ/kg); Glas matte folie, Embodied Carbon: 0.86 (kgCO₂/kg); Glas matte folie, Name: Glas matte folie; Glas matte folie, Participates in Collision Detection: yes
16 x Glas | Begane grond | Glas | Bestaand | Material Properties - Glas, ThermalConductivity: 1.2; Glas, SpecificHeatCapacity: 795 J/kg/K; Glas, MassDensity: 2180 kg/m3; Glas, Embodied Energy: 15 (MJ/kg); Glas, Embodied Carbon: 0.86 (kgCO₂/kg); Glas, Name: Glas; Glas, Participates in Collision Detection: yes; Glas, Aardopwarmingsvermogen (GWP): 44.3346; Glas, Ozonafbrekend Vermogen (ODP): 0; Glas, Fotochemische Vermogen tot Ozonvorming (POCP): 0.0213557; Glas, Verzuringsvermogen (AP): 0.281643; Glas, Eutrofiëringspotentieel (EP): 0.0316879; Glas, Abiotisch Uitputtingspotentieel (voor niet fossiele hulpbronnen) (ADPE): 0.00000449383; Glas, Abiotisch Uitputtingspotentieel (voor fossiele hulpbronnen) (ADPF): 628.803; Glas, Databron: https://www.oekobaudat.de/OEKOBAU.DAT/resource/processes/1f2d6e42-9ffc-421d-990d-555eee4a7529?version=20.19.120
2 x ALG - LICHTE SCHEIDINGSWAND 125 | Begane grond | ALG - LICHTE SCHEIDINGSWAND 125 | Material Properties - ALG - LICHTE SCHEIDINGSWAND 125, ThermalConductivity: 0.27; ALG - LICHTE SCHEIDINGSWAND 125, SpecificHeatCapacity: 840 J/kg/K; ALG - LICHTE SCHEIDINGSWAND 125, MassDensity: 800 kg/m3; ALG - LICHTE SCHEIDINGSWAND 125, Embodied Energy: 2 (MJ/kg); ALG - LICHTE SCHEIDINGSWAND 125, Embodied Carbon: 0.13 (kgCO₂/kg); ALG - LICHTE SCHEIDINGSWAND 125, Name: ALG - LICHTE SCHEIDINGSWAND 125; ALG - LICHTE SCHEIDINGSWAND 125, Participates in Collision Detection: yes
43 x Gipsplaat | Begane grond | Gipsplaat | Bestaand | Material Properties - Gipsplaat, ThermalConductivity: 0.23; Gipsplaat, SpecificHeatCapacity: 840 J/kg/K; Gipsplaat, MassDensity: 800 kg/m3; Gipsplaat, Embodied Energy: 6.75 (MJ/kg); Gipsplaat, Embodied Carbon: 0.38 (kgCO₂/kg); Gipsplaat, Name: Gipsplaat; Gipsplaat, Participates in Collision Detection: yes; Gipsplaat, Aardopwarmingsvermogen (GWP): 1.513; Gipsplaat, Ozonafbrekend Vermogen (ODP): 1.32e-07; Gipsplaat, Fotochemische Vermogen tot Ozonvorming (POCP): 0.000358; Gipsplaat, Verzuringsvermogen (AP): 0.0082; Gipsplaat, Eutrofiëringspotentieel (EP): 0.00138; Gipsplaat, Abiotisch Uitputtingspotentieel (voor niet fossiele hulpbronnen) (ADPE): 0.00000729; Gipsplaat, Abiotisch Uitputtingspotentieel (voor fossiele hulpbronnen) (ADPF): 25.04; Gipsplaat, Databron: https://www.oekobaudat.de/OEKOBAU.DAT/resource/processes/1a24808b-9116-422e-93fb-d435f74a038a?version=00.05.000
24 x ALG - ISOLATIE | Begane grond | ALG - ISOLATIE | Bestaand | Material Properties - ALG - ISOLATIE, ThermalConductivity: 0.035; ALG - ISOLATIE, SpecificHeatCapacity: 840 J/kg/K; ALG - ISOLATIE, MassDensity: 45 kg/m3; ALG - ISOLATIE, Embodied Energy: 16.8 (MJ/kg); ALG - ISOLATIE, Embodied Carbon: 1.05 (kgCO₂/kg); ALG - ISOLATIE, Name: ALG - ISOLATIE; ALG - ISOLATIE, Participates in Collision Detection: yes
2 x ALG - LICHTE SCHEIDINGSWAND | Begane grond | ALG - LICHTE SCHEIDINGSWAND | Bestaand | Material Properties - ALG - LICHTE SCHEIDINGSWAND, ThermalConductivity: 0.27; ALG - LICHTE SCHEIDINGSWAND, SpecificHeatCapacity: 840 J/kg/K; ALG - LICHTE SCHEIDINGSWAND, MassDensity: 800 kg/m3; ALG - LICHTE SCHEIDINGSWAND, Embodied Energy: 2 (MJ/kg); ALG - LICHTE SCHEIDINGSWAND, Embodied Carbon: 0.13 (kgCO₂/kg); ALG - LICHTE SCHEIDINGSWAND, Name: ALG - LICHTE SCHEIDINGSWAND; ALG - LICHTE SCHEIDINGSWAND, Participates in Collision Detection: yes
2 x Isolatie - Glaswol hard | Begane grond | Isolatie - Glaswol hard | Bestaand | Material Properties - Isolatie - Glaswol hard, ThermalConductivity: 0.033; Isolatie - Glaswol hard, SpecificHeatCapacity: 1030 J/kg/K; Isolatie - Glaswol hard, MassDensity: 64 kg/m3; Isolatie - Glaswol hard, Embodied Energy: 37 (MJ/kg); Isolatie - Glaswol hard, Embodied Carbon: 1.48 (kgCO₂/kg); Isolatie - Glaswol hard, Name: Isolatie - Glaswol hard; Isolatie - Glaswol hard, Participates in Collision Detection: yes; Isolatie - Glaswol hard, Aardopwarmingsvermogen (GWP): 6.1351; Isolatie - Glaswol hard, Ozonafbrekend Vermogen (ODP): 0; Isolatie - Glaswol hard, Fotochemische Vermogen tot Ozonvorming (POCP): 0.0000526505; Isolatie - Glaswol hard, Verzuringsvermogen (AP): 0.00117721; Isolatie - Glaswol hard, Eutrofiëringspotentieel (EP): 0.00018735; Isolatie - Glaswol hard, Abiotisch Uitputtingspotentieel (voor niet fossiele hulpbronnen) (ADPE): 2.14662e-07; Isolatie - Glaswol hard, Abiotisch Uitputtingspotentieel (voor fossiele hulpbronnen) (ADPF): 2.00169; Isolatie - Glaswol hard, Databron: https://www.oekobaudat.de/OEKOBAU.DAT/resource/processes/0a93c854-9521-43c2-9f20-440af5d3e6c5?version=00.01.000
6 x Lucht kolommen | Begane grond | Lucht kolommen | Bestaand | Material Properties - Lucht kolommen, ThermalConductivity: 0.15; Lucht kolommen, SpecificHeatCapacity: 1008 J/kg/K; Lucht kolommen, MassDensity: 1.2 kg/m3; Lucht kolommen, Embodied Energy: 0 (MJ/kg); Lucht kolommen, Embodied Carbon: 0 (kgCO₂/kg); Lucht kolommen, Name: Lucht kolommen; Lucht kolommen, Participates in Collision Detection: yes
17 x Beton gewapend prefab | Begane grond | Beton gewapend prefab | Bestaand | Material Properties - Beton gewapend prefab, ThermalConductivity: 2.5; Beton gewapend prefab, SpecificHeatCapacity: 1000 J/kg/K; Beton gewapend prefab, MassDensity: 2400 kg/m3; Beton gewapend prefab, Embodied Energy: 2.33 (MJ/kg); Beton gewapend prefab, Embodied Carbon: 0.242 (kgCO₂/kg); Beton gewapend prefab, Name: Beton gewapend prefab; Beton gewapend prefab, Participates in Collision Detection: yes; Beton gewapend prefab, Aardopwarmingsvermogen (GWP): 129.993; Beton gewapend prefab, Ozonafbrekend Vermogen (ODP): 0; Beton gewapend prefab, Fotochemische Vermogen tot Ozonvorming (POCP): 0.00471246; Beton gewapend prefab, Verzuringsvermogen (AP): 0.182012; Beton gewapend prefab, Eutrofiëringspotentieel (EP): 0.0346685; Beton gewapend prefab, Abiotisch Uitputtingspotentieel (voor niet fossiele hulpbronnen) (ADPE): 0.000140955; Beton gewapend prefab, Abiotisch Uitputtingspotentieel (voor fossiele hulpbronnen) (ADPF): 604.803; Beton gewapend prefab, Databron: https://www.oekobaudat.de/OEKOBAU.DAT/resource/processes/3470c523-ffcd-48df-93ff-dedfde86572a?version=20.19.010
27 x 21 STO lijmlaag | Begane grond | 21 STO lijmlaag | Material Properties - 21 STO lijmlaag, ThermalConductivity: 0.17; 21 STO lijmlaag, SpecificHeatCapacity: 900 J/kg/K; 21 STO lijmlaag, MassDensity: 1390 kg/m3; 21 STO lijmlaag, Embodied Energy: 77.2 (MJ/kg); 21 STO lijmlaag, Embodied Carbon: 3.1 (kgCO₂/kg); 21 STO lijmlaag, Name: 21 STO lijmlaag; 21 STO lijmlaag, Description: Kunststof; 21 STO lijmlaag, Participates in Collision Detection: yes
27 x 48 vloeivloer Bolidt | Begane grond | 48 vloeivloer Bolidt | Material Properties - 48 vloeivloer Bolidt, ThermalConductivity: 0.17; 48 vloeivloer Bolidt, SpecificHeatCapacity: 900 J/kg/K; 48 vloeivloer Bolidt, MassDensity: 1390 kg/m3; 48 vloeivloer Bolidt, Embodied Energy: 77.2 (MJ/kg); 48 vloeivloer Bolidt, Embodied Carbon: 3.1 (kgCO₂/kg); 48 vloeivloer Bolidt, Name: 48 vloeivloer Bolidt; 48 vloeivloer Bolidt, Participates in Collision Detection: yes; 48 vloeivloer Bolidt, Handelsgewicht (kg/m): 0; 48 vloeivloer Bolidt, Soortelijk gewicht (kg/m3): 7850; 48 vloeivloer Bolidt, Marge materiaal: 1
12 x ALG - ALGEMEEN | Begane grond | ALG - ALGEMEEN | Bestaand | Material Properties - ALG - ALGEMEEN, ThermalConductivity: 0.27; ALG - ALGEMEEN, SpecificHeatCapacity: 840 J/kg/K; ALG - ALGEMEEN, MassDensity: 800 kg/m3; ALG - ALGEMEEN, Embodied Energy: 2 (MJ/kg); ALG - ALGEMEEN, Embodied Carbon: 0.13 (kgCO₂/kg); ALG - ALGEMEEN, Name: ALG - ALGEMEEN; ALG - ALGEMEEN, Participates in Collision Detection: yes; ALG - ALGEMEEN, Handelsgewicht (kg/m): 0; ALG - ALGEMEEN, Soortelijk gewicht (kg/m3): 7850; ALG - ALGEMEEN, Marge materiaal: 1
Isolatie - Kunststof hard | Begane grond | Isolatie - Kunststof hard | Material Properties - Isolatie - Kunststof hard, ThermalConductivity: 0.029; Isolatie - Kunststof hard, SpecificHeatCapacity: 1470 J/kg/K; Isolatie - Kunststof hard, MassDensity: 100 kg/m3; Isolatie - Kunststof hard, Embodied Energy: 101.5 (MJ/kg); Isolatie - Kunststof hard, Embodied Carbon: 3.48 (kgCO₂/kg); Isolatie - Kunststof hard, Name: Isolatie - Kunststof hard; Isolatie - Kunststof hard, Participates in Collision Detection: yes; Isolatie - Kunststof hard, Aardopwarmingsvermogen (GWP): 0.04; Isolatie - Kunststof hard, Ozonafbrekend Vermogen (ODP): 0; Isolatie - Kunststof hard, Fotochemische Vermogen tot Ozonvorming (POCP): 0; Isolatie - Kunststof hard, Verzuringsvermogen (AP): 0.0000975; Isolatie - Kunststof hard, Eutrofiëringspotentieel (EP): 0.0000237; Isolatie - Kunststof hard, Abiotisch Uitputtingspotentieel (voor niet fossiele hulpbronnen) (ADPE): 0; Isolatie - Kunststof hard, Abiotisch Uitputtingspotentieel (voor fossiele hulpbronnen) (ADPF): 0.47; Isolatie - Kunststof hard, Databron: https://www.oekobaudat.de/OEKOBAU.DAT/resource/processes/41e09ab7-0e73-4303-84fd-97cb0809db02?version=00.04.000
7 x Isolatie - XPS zwevende dekvloer | 1e verdieping | Isolatie - XPS zwevende dekvloer | Bestaand | Material Properties - Isolatie - XPS zwevende dekvloer, ThermalConductivity: 0.034; Isolatie - XPS zwevende dekvloer, SpecificHeatCapacity: 1470 J/kg/K; Isolatie - XPS zwevende dekvloer, MassDensity: 35 kg/m3; Isolatie - XPS zwevende dekvloer, Embodied Energy: 88.6 (MJ/kg); Isolatie - XPS zwevende dekvloer, Embodied Carbon: 2.55 (kgCO₂/kg); Isolatie - XPS zwevende dekvloer, Name: Isolatie - XPS zwevende dekvloer; Isolatie - XPS zwevende dekvloer, Participates in Collision Detection: yes
21 x Isolatie - STO EPS | 1e verdieping | Isolatie - STO EPS | Bestaand | Material Properties - Isolatie - STO EPS, ThermalConductivity: 0.029; Isolatie - STO EPS, SpecificHeatCapacity: 1470 J/kg/K; Isolatie - STO EPS, MassDensity: 100 kg/m3; Isolatie - STO EPS, Embodied Energy: 101.5 (MJ/kg); Isolatie - STO EPS, Embodied Carbon: 3.48 (kgCO₂/kg); Isolatie - STO EPS, Name: Isolatie - STO EPS; Isolatie - STO EPS, Participates in Collision Detection: yes; Isolatie - STO EPS, Aardopwarmingsvermogen (GWP): 0.04; Isolatie - STO EPS, Ozonafbrekend Vermogen (ODP): 0; Isolatie - STO EPS, Fotochemische Vermogen tot Ozonvorming (POCP): 0; Isolatie - STO EPS, Verzuringsvermogen (AP): 0.0000975; Isolatie - STO EPS, Eutrofiëringspotentieel (EP): 0.0000237; Isolatie - STO EPS, Abiotisch Uitputtingspotentieel (voor niet fossiele hulpbronnen) (ADPE): 0; Isolatie - STO EPS, Abiotisch Uitputtingspotentieel (voor fossiele hulpbronnen) (ADPF): 0.47; Isolatie - STO EPS, Databron: https://www.oekobaudat.de/OEKOBAU.DAT/resource/processes/41e09ab7-0e73-4303-84fd-97cb0809db02?version=00.04.000
22 x STO lijmlaag | 1e verdieping | STO lijmlaag | Bestaand | Material Properties - STO lijmlaag, ThermalConductivity: 0; STO lijmlaag, SpecificHeatCapacity: 0 J/kg/K; STO lijmlaag, MassDensity: 0 kg/m3; STO lijmlaag, Embodied Energy: 0 (MJ/kg); STO lijmlaag, Embodied Carbon: 0 (kgCO₂/kg); STO lijmlaag, Name: STO lijmlaag; STO lijmlaag, Participates in Collision Detection: yes
13 x Steen - Kalkzandsteen C | 1e verdieping | Steen - Kalkzandsteen C | Bestaand | Material Properties - Steen - Kalkzandsteen C, ThermalConductivity: 0.9; Steen - Kalkzandsteen C, SpecificHeatCapacity: 840 J/kg/K; Steen - Kalkzandsteen C, MassDensity: 1900 kg/m3; Steen - Kalkzandsteen C, Embodied Energy: 0.75 (MJ/kg); Steen - Kalkzandsteen C, Embodied Carbon: 0.1 (kgCO₂/kg); Steen - Kalkzandsteen C, Name: Steen - Kalkzandsteen C; Steen - Kalkzandsteen C, Participates in Collision Detection: yes; Steen - Kalkzandsteen C, Aardopwarmingsvermogen (GWP): 5.10595; Steen - Kalkzandsteen C, Ozonafbrekend Vermogen (ODP): 0; Steen - Kalkzandsteen C, Fotochemische Vermogen tot Ozonvorming (POCP): -0.00337081; Steen - Kalkzandsteen C, Verzuringsvermogen (AP): 0.0103135; Steen - Kalkzandsteen C, Eutrofiëringspotentieel (EP): 0.0024518; Steen - Kalkzandsteen C, Abiotisch Uitputtingspotentieel (voor niet fossiele hulpbronnen) (ADPE): 4.2967e-07; Steen - Kalkzandsteen C, Abiotisch Uitputtingspotentieel (voor fossiele hulpbronnen) (ADPF): 68.4425; Steen - Kalkzandsteen C, Databron: https://www.oekobaudat.de/OEKOBAU.DAT/resource/processes/bdda4364-451f-4df2-a68b-5912469ee4c9?version=20.19.120
12 x STO weefsellaag | 1e verdieping | STO weefsellaag | Bestaand | Material Properties - STO weefsellaag, ThermalConductivity: 0; STO weefsellaag, SpecificHeatCapacity: 0 J/kg/K; STO weefsellaag, MassDensity: 0 kg/m3; STO weefsellaag, Embodied Energy: 0 (MJ/kg); STO weefsellaag, Embodied Carbon: 0 (kgCO₂/kg); STO weefsellaag, Name: STO weefsellaag; STO weefsellaag, Participates in Collision Detection: yes
14 x STO pleisterlaag | 1e verdieping | STO pleisterlaag | Bestaand | Material Properties - STO pleisterlaag, ThermalConductivity: 0; STO pleisterlaag, SpecificHeatCapacity: 0 J/kg/K; STO pleisterlaag, MassDensity: 0 kg/m3; STO pleisterlaag, Embodied Energy: 0 (MJ/kg); STO pleisterlaag, Embodied Carbon: 0 (kgCO₂/kg); STO pleisterlaag, Name: STO pleisterlaag; STO pleisterlaag, Participates in Collision Detection: yes
14 x Steen - Baksteen | 1e verdieping | Steen - Baksteen | Bestaand | Material Properties - Steen - Baksteen, ThermalConductivity: 0.9; Steen - Baksteen, SpecificHeatCapacity: 840 J/kg/K; Steen - Baksteen, MassDensity: 1600 kg/m3; Steen - Baksteen, Embodied Energy: 3 (MJ/kg); Steen - Baksteen, Embodied Carbon: 0.23 (kgCO₂/kg); Steen - Baksteen, Name: Steen - Baksteen; Steen - Baksteen, Participates in Collision Detection: yes; Steen - Baksteen, Aardopwarmingsvermogen (GWP): 113; Steen - Baksteen, Ozonafbrekend Vermogen (ODP): 0; Steen - Baksteen, Fotochemische Vermogen tot Ozonvorming (POCP): 0.012; Steen - Baksteen, Verzuringsvermogen (AP): 0.094; Steen - Baksteen, Eutrofiëringspotentieel (EP): 0.0189; Steen - Baksteen, Abiotisch Uitputtingspotentieel (voor niet fossiele hulpbronnen) (ADPE): 0.0000099; Steen - Baksteen, Abiotisch Uitputtingspotentieel (voor fossiele hulpbronnen) (ADPF): 1150; Steen - Baksteen, Databron: https://www.oekobaudat.de/OEKOBAU.DAT/resource/processes/08dd0308-eebf-4db1-82ee-b340d070c9b9?version=00.06.000
13 x Isolatie - Kunststof hard | 1e verdieping | Isolatie - Kunststof hard | Bestaand | Material Properties - Isolatie - Kunststof hard, ThermalConductivity: 0.029; Isolatie - Kunststof hard, SpecificHeatCapacity: 1470 J/kg/K; Isolatie - Kunststof hard, MassDensity: 100 kg/m3; Isolatie - Kunststof hard, Embodied Energy: 101.5 (MJ/kg); Isolatie - Kunststof hard, Embodied Carbon: 3.48 (kgCO₂/kg); Isolatie - Kunststof hard, Name: Isolatie - Kunststof hard; Isolatie - Kunststof hard, Participates in Collision Detection: yes; Isolatie - Kunststof hard, Aardopwarmingsvermogen (GWP): 0.04; Isolatie - Kunststof hard, Ozonafbrekend Vermogen (ODP): 0; Isolatie - Kunststof hard, Fotochemische Vermogen tot Ozonvorming (POCP): 0; Isolatie - Kunststof hard, Verzuringsvermogen (AP): 0.0000975; Isolatie - Kunststof hard, Eutrofiëringspotentieel (EP): 0.0000237; Isolatie - Kunststof hard, Abiotisch Uitputtingspotentieel (voor niet fossiele hulpbronnen) (ADPE): 0; Isolatie - Kunststof hard, Abiotisch Uitputtingspotentieel (voor fossiele hulpbronnen) (ADPF): 0.47; Isolatie - Kunststof hard, Databron: https://www.oekobaudat.de/OEKOBAU.DAT/resource/processes/41e09ab7-0e73-4303-84fd-97cb0809db02?version=00.04.000
9 x Cementgebonden plaatmateriaal | 1e verdieping | Cementgebonden plaatmateriaal | Bestaand | Material Properties - Cementgebonden plaatmateriaal, ThermalConductivity: 0.45; Cementgebonden plaatmateriaal, SpecificHeatCapacity: 840 J/kg/K; Cementgebonden plaatmateriaal, MassDensity: 1400 kg/m3; Cementgebonden plaatmateriaal, Embodied Energy: 6.75 (MJ/kg); Cementgebonden plaatmateriaal, Embodied Carbon: 0.38 (kgCO₂/kg); Cementgebonden plaatmateriaal, Name: Cementgebonden plaatmateriaal; Cementgebonden plaatmateriaal, Participates in Collision Detection: yes; Cementgebonden plaatmateriaal, Aardopwarmingsvermogen (GWP): 1.62283; Cementgebonden plaatmateriaal, Ozonafbrekend Vermogen (ODP): 0; Cementgebonden plaatmateriaal, Fotochemische Vermogen tot Ozonvorming (POCP): 33.9565; Cementgebonden plaatmateriaal, Verzuringsvermogen (AP): 0.000135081; Cementgebonden plaatmateriaal, Eutrofiëringspotentieel (EP): 0.00274111; Cementgebonden plaatmateriaal, Abiotisch Uitputtingspotentieel (voor niet fossiele hulpbronnen) (ADPE): 0; Cementgebonden plaatmateriaal, Abiotisch Uitputtingspotentieel (voor fossiele hulpbronnen) (ADPF): 0.000893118; Cementgebonden plaatmateriaal, Databron: https://www.oekobaudat.de/OEKOBAU.DAT/resource/processes/07423e99-8c7c-4e93-8311-dcf7ae85c41d?version=20.20.010
10 x Isolatie - Steenwol zacht | 1e verdieping | Isolatie - Steenwol zacht | Bestaand | Material Properties - Isolatie - Steenwol zacht, ThermalConductivity: 0.035; Isolatie - Steenwol zacht, SpecificHeatCapacity: 840 J/kg/K; Isolatie - Steenwol zacht, MassDensity: 45 kg/m3; Isolatie - Steenwol zacht, Embodied Energy: 16.8 (MJ/kg); Isolatie - Steenwol zacht, Embodied Carbon: 1.05 (kgCO₂/kg); Isolatie - Steenwol zacht, Name: Isolatie - Steenwol zacht; Isolatie - Steenwol zacht, Participates in Collision Detection: yes; Isolatie - Steenwol zacht, Aardopwarmingsvermogen (GWP): -1.45742; Isolatie - Steenwol zacht, Fotochemische Vermogen tot Ozonvorming (POCP): -0.000168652; Isolatie - Steenwol zacht, Verzuringsvermogen (AP): -0.00166456; Isolatie - Steenwol zacht, Eutrofiëringspotentieel (EP): -0.000222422; Isolatie - Steenwol zacht, Abiotisch Uitputtingspotentieel (voor niet fossiele hulpbronnen) (ADPE): -2.57402e-07; Isolatie - Steenwol zacht, Abiotisch Uitputtingspotentieel (voor fossiele hulpbronnen) (ADPF): -20.4442; Isolatie - Steenwol zacht, Databron: https://www.oekobaudat.de/OEKOBAU.DAT/resource/processes/bd7319aa-d609-4f27-9460-d11bc966bb2b?version=00.03.000
2 x ALG - ISOLATIE UITVULLING | 1e verdieping | ALG - ISOLATIE UITVULLING | Bestaand | Material Properties - ALG - ISOLATIE UITVULLING, ThermalConductivity: 0.035; ALG - ISOLATIE UITVULLING, SpecificHeatCapacity: 840 J/kg/K; ALG - ISOLATIE UITVULLING, MassDensity: 45 kg/m3; ALG - ISOLATIE UITVULLING, Embodied Energy: 16.8 (MJ/kg); ALG - ISOLATIE UITVULLING, Embodied Carbon: 1.05 (kgCO₂/kg); ALG - ISOLATIE UITVULLING, Name: ALG - ISOLATIE UITVULLING; ALG - ISOLATIE UITVULLING, Participates in Collision Detection: yes
175 x Gipsplaat | 1e verdieping | Gipsplaat | Material Properties - Gipsplaat, ThermalConductivity: 0.23; Gipsplaat, SpecificHeatCapacity: 840 J/kg/K; Gipsplaat, MassDensity: 800 kg/m3; Gipsplaat, Embodied Energy: 6.75 (MJ/kg); Gipsplaat, Embodied Carbon: 0.38 (kgCO₂/kg); Gipsplaat, Name: Gipsplaat; Gipsplaat, Participates in Collision Detection: yes; Gipsplaat, Aardopwarmingsvermogen (GWP): 1.513; Gipsplaat, Ozonafbrekend Vermogen (ODP): 1.32e-07; Gipsplaat, Fotochemische Vermogen tot Ozonvorming (POCP): 0.000358; Gipsplaat, Verzuringsvermogen (AP): 0.0082; Gipsplaat, Eutrofiëringspotentieel (EP): 0.00138; Gipsplaat, Abiotisch Uitputtingspotentieel (voor niet fossiele hulpbronnen) (ADPE): 0.00000729; Gipsplaat, Abiotisch Uitputtingspotentieel (voor fossiele hulpbronnen) (ADPF): 25.04; Gipsplaat, Databron: https://www.oekobaudat.de/OEKOBAU.DAT/resource/processes/1a24808b-9116-422e-93fb-d435f74a038a?version=00.05.000
71 x ALG - LICHTE SCHEIDINGSWAND | 1e verdieping | ALG - LICHTE SCHEIDINGSWAND | Material Properties - ALG - LICHTE SCHEIDINGSWAND, ThermalConductivity: 0.27; ALG - LICHTE SCHEIDINGSWAND, SpecificHeatCapacity: 840 J/kg/K; ALG - LICHTE SCHEIDINGSWAND, MassDensity: 800 kg/m3; ALG - LICHTE SCHEIDINGSWAND, Embodied Energy: 2 (MJ/kg); ALG - LICHTE SCHEIDINGSWAND, Embodied Carbon: 0.13 (kgCO₂/kg); ALG - LICHTE SCHEIDINGSWAND, Name: ALG - LICHTE SCHEIDINGSWAND; ALG - LICHTE SCHEIDINGSWAND, Participates in Collision Detection: yes
63 x Metaal - Staal C | 1e verdieping | Metaal - Staal C | Bestaand | Material Properties - Metaal - Staal C, ThermalConductivity: 52; Metaal - Staal C, SpecificHeatCapacity: 530 J/kg/K; Metaal - Staal C, MassDensity: 7950 kg/m3; Metaal - Staal C, Embodied Energy: 25 (MJ/kg); Metaal - Staal C, Embodied Carbon: 1.91 (kgCO₂/kg); Metaal - Staal C, Name: Metaal - Staal C; Metaal - Staal C, Participates in Collision Detection: yes; Metaal - Staal C, Aardopwarmingsvermogen (GWP): 323.71; Metaal - Staal C, Ozonafbrekend Vermogen (ODP): 0; Metaal - Staal C, Fotochemische Vermogen tot Ozonvorming (POCP): 0.17963; Metaal - Staal C, Verzuringsvermogen (AP): 0.43354; Metaal - Staal C, Eutrofiëringspotentieel (EP): 0.014961; Metaal - Staal C, Abiotisch Uitputtingspotentieel (voor niet fossiele hulpbronnen) (ADPE): 0.00080492; Metaal - Staal C, Abiotisch Uitputtingspotentieel (voor fossiele hulpbronnen) (ADPF): 2862.1; Metaal - Staal C, Databron: https://www.oekobaudat.de/OEKOBAU.DAT/resource/processes/a85fbb4a-60a0-4ba9-9cfa-cdfbe1ec7f00?version=00.01.000
3 x Lucht kolommen | 1e verdieping | Lucht kolommen | Bestaand | Material Properties - Lucht kolommen, ThermalConductivity: 0.15; Lucht kolommen, SpecificHeatCapacity: 1008 J/kg/K; Lucht kolommen, MassDensity: 1.2 kg/m3; Lucht kolommen, Embodied Energy: 0 (MJ/kg); Lucht kolommen, Embodied Carbon: 0 (kgCO₂/kg); Lucht kolommen, Name: Lucht kolommen; Lucht kolommen, Participates in Collision Detection: yes
6 x Hout C | 1e verdieping | Hout C | Bestaand | Material Properties - Hout C, ThermalConductivity: 0.14; Hout C, SpecificHeatCapacity: 1880 J/kg/K; Hout C, MassDensity: 550 kg/m3; Hout C, Embodied Energy: 7.4 (MJ/kg); Hout C, Embodied Carbon: 0.19 (kgCO₂/kg); Hout C, Name: Hout C; Hout C, Participates in Collision Detection: yes; Hout C, Aardopwarmingsvermogen (GWP): -349.478; Hout C, Ozonafbrekend Vermogen (ODP): 0; Hout C, Fotochemische Vermogen tot Ozonvorming (POCP): -0.028; Hout C, Verzuringsvermogen (AP): -0.352; Hout C, Eutrofiëringspotentieel (EP): -0.059; Hout C, Abiotisch Uitputtingspotentieel (voor fossiele hulpbronnen) (ADPF): -3860.46; Hout C, Databron: https://www.oekobaudat.de/OEKOBAU.DAT/resource/processes/07a5482a-fa4a-484d-8929-b6f6dfd6be3e?version=00.00.027
5 x  | 1e verdieping |  | Bestaand
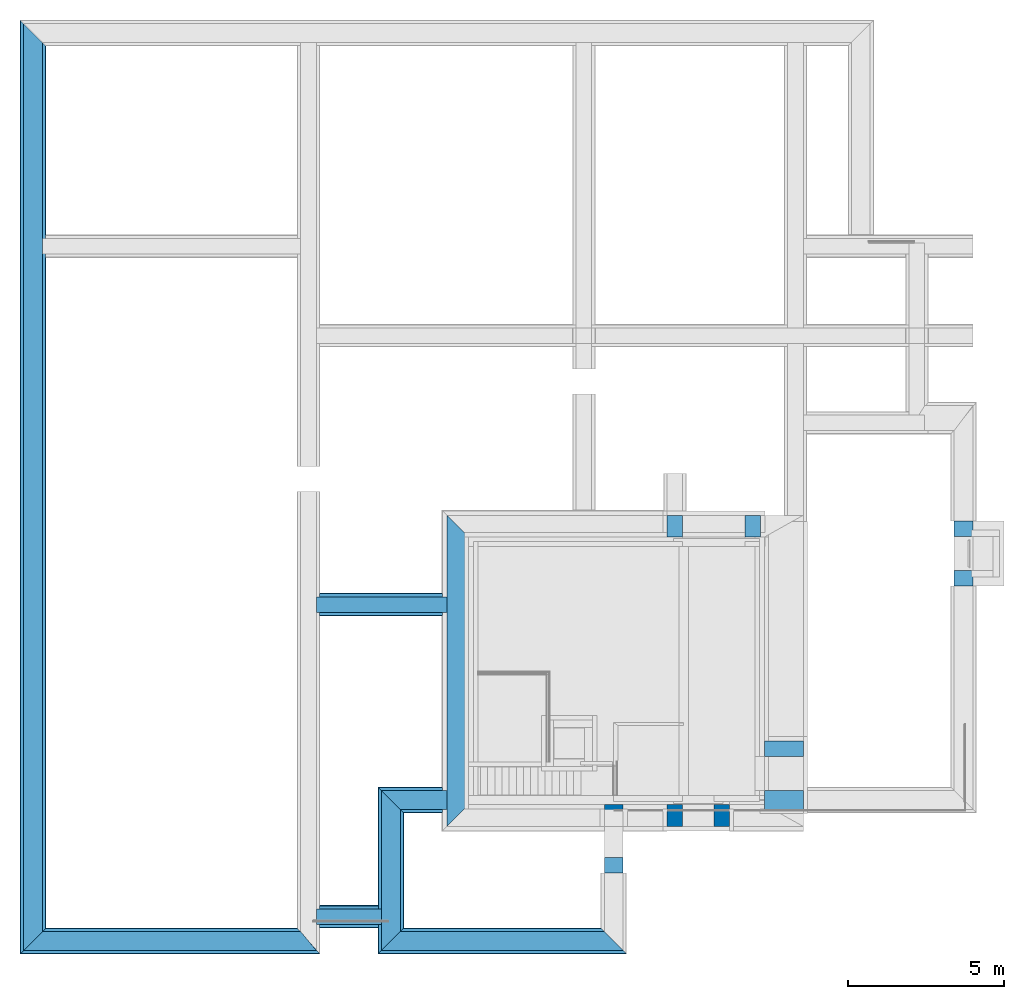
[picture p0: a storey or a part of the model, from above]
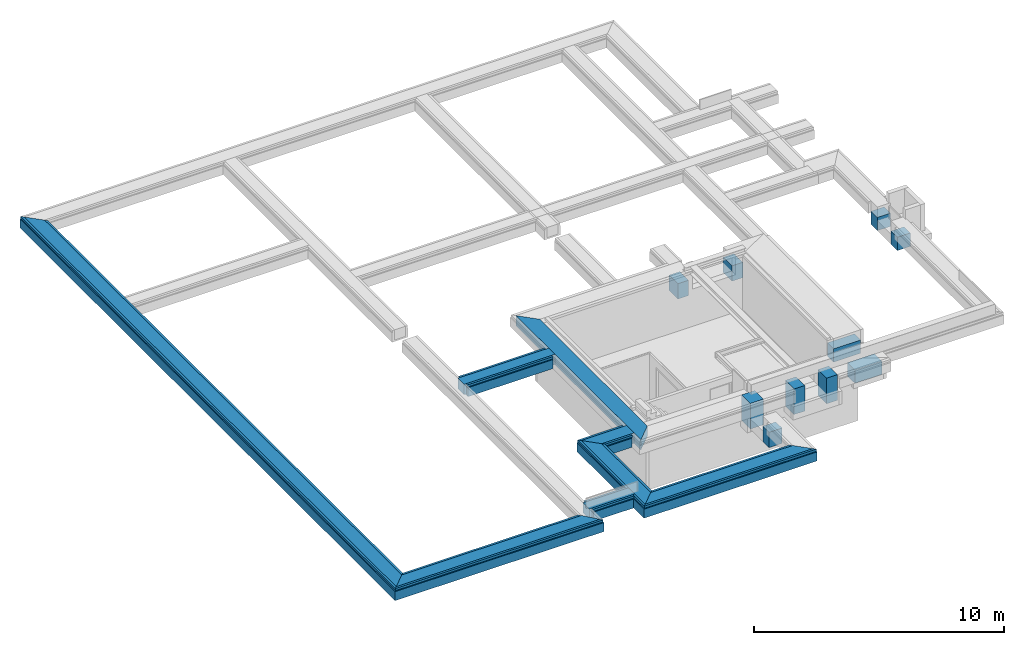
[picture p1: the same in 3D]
Properties of the parts of a building model (IFC2X3), part 3 of 7

# IfcBuildingElementPart (1646)
Name | In | Material | Renovation Phase
9 x Glas | 1e verdieping | Glas | Bestaand | Material Properties - Glas, ThermalConductivity: 1.2; Glas, SpecificHeatCapacity: 795 J/kg/K; Glas, MassDensity: 2180 kg/m3; Glas, Embodied Energy: 15 (MJ/kg); Glas, Embodied Carbon: 0.86 (kgCO₂/kg); Glas, Name: Glas; Glas, Participates in Collision Detection: yes; Glas, Aardopwarmingsvermogen (GWP): 44.3346; Glas, Ozonafbrekend Vermogen (ODP): 0; Glas, Fotochemische Vermogen tot Ozonvorming (POCP): 0.0213557; Glas, Verzuringsvermogen (AP): 0.281643; Glas, Eutrofiëringspotentieel (EP): 0.0316879; Glas, Abiotisch Uitputtingspotentieel (voor niet fossiele hulpbronnen) (ADPE): 0.00000449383; Glas, Abiotisch Uitputtingspotentieel (voor fossiele hulpbronnen) (ADPF): 628.803; Glas, Databron: https://www.oekobaudat.de/OEKOBAU.DAT/resource/processes/1f2d6e42-9ffc-421d-990d-555eee4a7529?version=20.19.120
2 x Glas matte folie | 1e verdieping | Glas matte folie | Bestaand | Material Properties - Glas matte folie, ThermalConductivity: 1.2; Glas matte folie, SpecificHeatCapacity: 795 J/kg/K; Glas matte folie, MassDensity: 2180 kg/m3; Glas matte folie, Embodied Energy: 15 (MJ/kg); Glas matte folie, Embodied Carbon: 0.86 (kgCO₂/kg); Glas matte folie, Name: Glas matte folie; Glas matte folie, Participates in Collision Detection: yes
42 x Gipsplaat | 1e verdieping | Gipsplaat | Bestaand | Material Properties - Gipsplaat, ThermalConductivity: 0.23; Gipsplaat, SpecificHeatCapacity: 840 J/kg/K; Gipsplaat, MassDensity: 800 kg/m3; Gipsplaat, Embodied Energy: 6.75 (MJ/kg); Gipsplaat, Embodied Carbon: 0.38 (kgCO₂/kg); Gipsplaat, Name: Gipsplaat; Gipsplaat, Participates in Collision Detection: yes; Gipsplaat, Aardopwarmingsvermogen (GWP): 1.513; Gipsplaat, Ozonafbrekend Vermogen (ODP): 1.32e-07; Gipsplaat, Fotochemische Vermogen tot Ozonvorming (POCP): 0.000358; Gipsplaat, Verzuringsvermogen (AP): 0.0082; Gipsplaat, Eutrofiëringspotentieel (EP): 0.00138; Gipsplaat, Abiotisch Uitputtingspotentieel (voor niet fossiele hulpbronnen) (ADPE): 0.00000729; Gipsplaat, Abiotisch Uitputtingspotentieel (voor fossiele hulpbronnen) (ADPF): 25.04; Gipsplaat, Databron: https://www.oekobaudat.de/OEKOBAU.DAT/resource/processes/1a24808b-9116-422e-93fb-d435f74a038a?version=00.05.000
20 x ALG - ISOLATIE | 1e verdieping | ALG - ISOLATIE | Bestaand | Material Properties - ALG - ISOLATIE, ThermalConductivity: 0.035; ALG - ISOLATIE, SpecificHeatCapacity: 840 J/kg/K; ALG - ISOLATIE, MassDensity: 45 kg/m3; ALG - ISOLATIE, Embodied Energy: 16.8 (MJ/kg); ALG - ISOLATIE, Embodied Carbon: 1.05 (kgCO₂/kg); ALG - ISOLATIE, Name: ALG - ISOLATIE; ALG - ISOLATIE, Participates in Collision Detection: yes
33 x Beton gewapend C | 1e verdieping | Beton gewapend C | Bestaand | Material Properties - Beton gewapend C, ThermalConductivity: 2.3; Beton gewapend C, SpecificHeatCapacity: 1000 J/kg/K; Beton gewapend C, MassDensity: 2300 kg/m3; Beton gewapend C, Embodied Energy: 1.92 (MJ/kg); Beton gewapend C, Embodied Carbon: 0.198 (kgCO₂/kg); Beton gewapend C, Name: Beton gewapend C; Beton gewapend C, Participates in Collision Detection: yes; Beton gewapend C, Aardopwarmingsvermogen (GWP): -1.02642; Beton gewapend C, Ozonafbrekend Vermogen (ODP): 0; Beton gewapend C, Fotochemische Vermogen tot Ozonvorming (POCP): 0.000222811; Beton gewapend C, Verzuringsvermogen (AP): -0.00242385; Beton gewapend C, Eutrofiëringspotentieel (EP): -0.000471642; Beton gewapend C, Abiotisch Uitputtingspotentieel (voor niet fossiele hulpbronnen) (ADPE): -2.28121e-07; Beton gewapend C, Abiotisch Uitputtingspotentieel (voor fossiele hulpbronnen) (ADPF): -12.4095; Beton gewapend C, Databron: https://www.oekobaudat.de/OEKOBAU.DAT/resource/processes/d3b59cac-3b4e-4d18-8c3a-780b553c9591?version=20.19.120
31 Metaal - Aluminium kozijn | 1e verdieping | 31 Metaal - Aluminium kozijn | Bestaand | Material Properties - 31 Metaal - Aluminium kozijn, ThermalConductivity: 160; 31 Metaal - Aluminium kozijn, SpecificHeatCapacity: 880 J/kg/K; 31 Metaal - Aluminium kozijn, MassDensity: 2800 kg/m3; 31 Metaal - Aluminium kozijn, Embodied Energy: 155 (MJ/kg); 31 Metaal - Aluminium kozijn, Embodied Carbon: 9.16 (kgCO₂/kg); 31 Metaal - Aluminium kozijn, Name: 31 Metaal - Aluminium kozijn; 31 Metaal - Aluminium kozijn, Description: Metaal; 31 Metaal - Aluminium kozijn, Participates in Collision Detection: yes
3 x Isolatie - Kunststof zacht | 1e verdieping | Isolatie - Kunststof zacht | Bestaand | Material Properties - Isolatie - Kunststof zacht, ThermalConductivity: 0.036; Isolatie - Kunststof zacht, SpecificHeatCapacity: 1470 J/kg/K; Isolatie - Kunststof zacht, MassDensity: 20 kg/m3; Isolatie - Kunststof zacht, Embodied Energy: 88.6 (MJ/kg); Isolatie - Kunststof zacht, Embodied Carbon: 2.55 (kgCO₂/kg); Isolatie - Kunststof zacht, Name: Isolatie - Kunststof zacht; Isolatie - Kunststof zacht, Participates in Collision Detection: yes; Isolatie - Kunststof zacht, Aardopwarmingsvermogen (GWP): 2.9328; Isolatie - Kunststof zacht, Ozonafbrekend Vermogen (ODP): 0; Isolatie - Kunststof zacht, Fotochemische Vermogen tot Ozonvorming (POCP): 0.000924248; Isolatie - Kunststof zacht, Verzuringsvermogen (AP): 0.00810258; Isolatie - Kunststof zacht, Eutrofiëringspotentieel (EP): 0.00803134; Isolatie - Kunststof zacht, Abiotisch Uitputtingspotentieel (voor niet fossiele hulpbronnen) (ADPE): 6.06872e-07; Isolatie - Kunststof zacht, Abiotisch Uitputtingspotentieel (voor fossiele hulpbronnen) (ADPF): 42.0438; Isolatie - Kunststof zacht, Databron: https://www.oekobaudat.de/OEKOBAU.DAT/resource/processes/a564fa56-4723-4123-bbbd-2a8780c8c899?version=00.05.000
2 x Rockpanel RAL 1001 | 1e verdieping | Rockpanel RAL 1001 | Bestaand | Material Properties - Rockpanel RAL 1001, ThermalConductivity: 0.45; Rockpanel RAL 1001, SpecificHeatCapacity: 840 J/kg/K; Rockpanel RAL 1001, MassDensity: 1400 kg/m3; Rockpanel RAL 1001, Embodied Energy: 6.75 (MJ/kg); Rockpanel RAL 1001, Embodied Carbon: 0.38 (kgCO₂/kg); Rockpanel RAL 1001, Name: Rockpanel RAL 1001; Rockpanel RAL 1001, Participates in Collision Detection: yes; Rockpanel RAL 1001, Aardopwarmingsvermogen (GWP): 1.62283; Rockpanel RAL 1001, Ozonafbrekend Vermogen (ODP): 0; Rockpanel RAL 1001, Fotochemische Vermogen tot Ozonvorming (POCP): 33.9565; Rockpanel RAL 1001, Verzuringsvermogen (AP): 0.000135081; Rockpanel RAL 1001, Eutrofiëringspotentieel (EP): 0.00274111; Rockpanel RAL 1001, Abiotisch Uitputtingspotentieel (voor niet fossiele hulpbronnen) (ADPE): 0; Rockpanel RAL 1001, Abiotisch Uitputtingspotentieel (voor fossiele hulpbronnen) (ADPF): 0.000893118; Rockpanel RAL 1001, Databron: https://www.oekobaudat.de/OEKOBAU.DAT/resource/processes/07423e99-8c7c-4e93-8311-dcf7ae85c41d?version=20.20.010
4 x Isolatie - Steenwol hard | 1e verdieping | Isolatie - Steenwol hard | Bestaand | Material Properties - Isolatie - Steenwol hard, ThermalConductivity: 0.043; Isolatie - Steenwol hard, SpecificHeatCapacity: 840 J/kg/K; Isolatie - Steenwol hard, MassDensity: 160 kg/m3; Isolatie - Steenwol hard, Embodied Energy: 16.8 (MJ/kg); Isolatie - Steenwol hard, Embodied Carbon: 1.05 (kgCO₂/kg); Isolatie - Steenwol hard, Name: Isolatie - Steenwol hard; Isolatie - Steenwol hard, Participates in Collision Detection: yes; Isolatie - Steenwol hard, Aardopwarmingsvermogen (GWP): -6.78496; Isolatie - Steenwol hard, Ozonafbrekend Vermogen (ODP): 0; Isolatie - Steenwol hard, Fotochemische Vermogen tot Ozonvorming (POCP): -95.1843; Isolatie - Steenwol hard, Verzuringsvermogen (AP): -0.0077477; Isolatie - Steenwol hard, Eutrofiëringspotentieel (EP): -0.00103531; Isolatie - Steenwol hard, Abiotisch Uitputtingspotentieel (voor niet fossiele hulpbronnen) (ADPE): -0.00000119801; Isolatie - Steenwol hard, Abiotisch Uitputtingspotentieel (voor fossiele hulpbronnen) (ADPF): -0.000785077; Isolatie - Steenwol hard, Databron: https://www.oekobaudat.de/OEKOBAU.DAT/resource/processes/e9f65a5d-5e7b-4d57-ac5d-09a059663036?version=00.02.000
5 x Eternit wit | 1e verdieping | Eternit wit | Bestaand | Material Properties - Eternit wit, ThermalConductivity: 0.45; Eternit wit, SpecificHeatCapacity: 840 J/kg/K; Eternit wit, MassDensity: 1400 kg/m3; Eternit wit, Embodied Energy: 6.75 (MJ/kg); Eternit wit, Embodied Carbon: 0.38 (kgCO₂/kg); Eternit wit, Name: Eternit wit; Eternit wit, Participates in Collision Detection: yes; Eternit wit, Aardopwarmingsvermogen (GWP): 1.62283; Eternit wit, Ozonafbrekend Vermogen (ODP): 0; Eternit wit, Fotochemische Vermogen tot Ozonvorming (POCP): 33.9565; Eternit wit, Verzuringsvermogen (AP): 0.000135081; Eternit wit, Eutrofiëringspotentieel (EP): 0.00274111; Eternit wit, Abiotisch Uitputtingspotentieel (voor niet fossiele hulpbronnen) (ADPE): 0; Eternit wit, Abiotisch Uitputtingspotentieel (voor fossiele hulpbronnen) (ADPF): 0.000893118; Eternit wit, Databron: https://www.oekobaudat.de/OEKOBAU.DAT/resource/processes/07423e99-8c7c-4e93-8311-dcf7ae85c41d?version=20.20.010
7 x Beton gewapend C vloer | 1e verdieping | Beton gewapend C vloer | Bestaand | Material Properties - Beton gewapend C vloer, ThermalConductivity: 2.5; Beton gewapend C vloer, SpecificHeatCapacity: 1000 J/kg/K; Beton gewapend C vloer, MassDensity: 2400 kg/m3; Beton gewapend C vloer, Embodied Energy: 2.33 (MJ/kg); Beton gewapend C vloer, Embodied Carbon: 0.242 (kgCO₂/kg); Beton gewapend C vloer, Name: Beton gewapend C vloer; Beton gewapend C vloer, Participates in Collision Detection: yes
7 x Beton C | 1e verdieping | Beton C | Bestaand | Material Properties - Beton C, ThermalConductivity: 2; Beton C, SpecificHeatCapacity: 840 J/kg/K; Beton C, MassDensity: 2400 kg/m3; Beton C, Embodied Energy: 0.75 (MJ/kg); Beton C, Embodied Carbon: 0.1 (kgCO₂/kg); Beton C, Name: Beton C; Beton C, Participates in Collision Detection: yes; Beton C, Aardopwarmingsvermogen (GWP): 1.27649; Beton C, Ozonafbrekend Vermogen (ODP): 0; Beton C, Fotochemische Vermogen tot Ozonvorming (POCP): -0.000842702; Beton C, Verzuringsvermogen (AP): 0.00257837; Beton C, Eutrofiëringspotentieel (EP): 0.000612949; Beton C, Abiotisch Uitputtingspotentieel (voor niet fossiele hulpbronnen) (ADPE): 1.07417e-07; Beton C, Abiotisch Uitputtingspotentieel (voor fossiele hulpbronnen) (ADPF): 17.1106; Beton C, Databron: https://www.oekobaudat.de/OEKOBAU.DAT/resource/processes/d3b59cac-3b4e-4d18-8c3a-780b553c9591?version=20.19.120
14 x 21 STO lijmlaag | 1e verdieping | 21 STO lijmlaag | Material Properties - 21 STO lijmlaag, ThermalConductivity: 0.17; 21 STO lijmlaag, SpecificHeatCapacity: 900 J/kg/K; 21 STO lijmlaag, MassDensity: 1390 kg/m3; 21 STO lijmlaag, Embodied Energy: 77.2 (MJ/kg); 21 STO lijmlaag, Embodied Carbon: 3.1 (kgCO₂/kg); 21 STO lijmlaag, Name: 21 STO lijmlaag; 21 STO lijmlaag, Description: Kunststof; 21 STO lijmlaag, Participates in Collision Detection: yes
14 x 48 vloeivloer Bolidt | 1e verdieping | 48 vloeivloer Bolidt | Material Properties - 48 vloeivloer Bolidt, ThermalConductivity: 0.17; 48 vloeivloer Bolidt, SpecificHeatCapacity: 900 J/kg/K; 48 vloeivloer Bolidt, MassDensity: 1390 kg/m3; 48 vloeivloer Bolidt, Embodied Energy: 77.2 (MJ/kg); 48 vloeivloer Bolidt, Embodied Carbon: 3.1 (kgCO₂/kg); 48 vloeivloer Bolidt, Name: 48 vloeivloer Bolidt; 48 vloeivloer Bolidt, Participates in Collision Detection: yes; 48 vloeivloer Bolidt, Handelsgewicht (kg/m): 0; 48 vloeivloer Bolidt, Soortelijk gewicht (kg/m3): 7850; 48 vloeivloer Bolidt, Marge materiaal: 1
ALG - LICHTE SCHEIDINGSWAND 125 | 1e verdieping | ALG - LICHTE SCHEIDINGSWAND 125 | Material Properties - ALG - LICHTE SCHEIDINGSWAND 125, ThermalConductivity: 0.27; ALG - LICHTE SCHEIDINGSWAND 125, SpecificHeatCapacity: 840 J/kg/K; ALG - LICHTE SCHEIDINGSWAND 125, MassDensity: 800 kg/m3; ALG - LICHTE SCHEIDINGSWAND 125, Embodied Energy: 2 (MJ/kg); ALG - LICHTE SCHEIDINGSWAND 125, Embodied Carbon: 0.13 (kgCO₂/kg); ALG - LICHTE SCHEIDINGSWAND 125, Name: ALG - LICHTE SCHEIDINGSWAND 125; ALG - LICHTE SCHEIDINGSWAND 125, Participates in Collision Detection: yes
10 x ALG - ALGEMEEN | 1e verdieping | ALG - ALGEMEEN | Bestaand | Material Properties - ALG - ALGEMEEN, ThermalConductivity: 0.27; ALG - ALGEMEEN, SpecificHeatCapacity: 840 J/kg/K; ALG - ALGEMEEN, MassDensity: 800 kg/m3; ALG - ALGEMEEN, Embodied Energy: 2 (MJ/kg); ALG - ALGEMEEN, Embodied Carbon: 0.13 (kgCO₂/kg); ALG - ALGEMEEN, Name: ALG - ALGEMEEN; ALG - ALGEMEEN, Participates in Collision Detection: yes; ALG - ALGEMEEN, Handelsgewicht (kg/m): 0; ALG - ALGEMEEN, Soortelijk gewicht (kg/m3): 7850; ALG - ALGEMEEN, Marge materiaal: 1
2 x Isolatie - Steenwol hard | 2e dakoverzicht | Isolatie - Steenwol hard | Bestaand | Material Properties - Isolatie - Steenwol hard, ThermalConductivity: 0.043; Isolatie - Steenwol hard, SpecificHeatCapacity: 840 J/kg/K; Isolatie - Steenwol hard, MassDensity: 160 kg/m3; Isolatie - Steenwol hard, Embodied Energy: 16.8 (MJ/kg); Isolatie - Steenwol hard, Embodied Carbon: 1.05 (kgCO₂/kg); Isolatie - Steenwol hard, Name: Isolatie - Steenwol hard; Isolatie - Steenwol hard, Participates in Collision Detection: yes; Isolatie - Steenwol hard, Aardopwarmingsvermogen (GWP): -6.78496; Isolatie - Steenwol hard, Ozonafbrekend Vermogen (ODP): 0; Isolatie - Steenwol hard, Fotochemische Vermogen tot Ozonvorming (POCP): -95.1843; Isolatie - Steenwol hard, Verzuringsvermogen (AP): -0.0077477; Isolatie - Steenwol hard, Eutrofiëringspotentieel (EP): -0.00103531; Isolatie - Steenwol hard, Abiotisch Uitputtingspotentieel (voor niet fossiele hulpbronnen) (ADPE): -0.00000119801; Isolatie - Steenwol hard, Abiotisch Uitputtingspotentieel (voor fossiele hulpbronnen) (ADPF): -0.000785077; Isolatie - Steenwol hard, Databron: https://www.oekobaudat.de/OEKOBAU.DAT/resource/processes/e9f65a5d-5e7b-4d57-ac5d-09a059663036?version=00.02.000
48 x 47 waterdichte laag - bitumen | 2e dakoverzicht | 47 waterdichte laag - bitumen | Bestaand | Material Properties - 47 waterdichte laag - bitumen, ThermalConductivity: 0.9; 47 waterdichte laag - bitumen, SpecificHeatCapacity: 840 J/kg/K; 47 waterdichte laag - bitumen, MassDensity: 1600 kg/m3; 47 waterdichte laag - bitumen, Embodied Energy: 3 (MJ/kg); 47 waterdichte laag - bitumen, Embodied Carbon: 0.23 (kgCO₂/kg); 47 waterdichte laag - bitumen, Name: 47 waterdichte laag - bitumen; 47 waterdichte laag - bitumen, Participates in Collision Detection: yes; 47 waterdichte laag - bitumen, Aardopwarmingsvermogen (GWP): 113; 47 waterdichte laag - bitumen, Ozonafbrekend Vermogen (ODP): 0; 47 waterdichte laag - bitumen, Fotochemische Vermogen tot Ozonvorming (POCP): 0.012; 47 waterdichte laag - bitumen, Verzuringsvermogen (AP): 0.094; 47 waterdichte laag - bitumen, Eutrofiëringspotentieel (EP): 0.0189; 47 waterdichte laag - bitumen, Abiotisch Uitputtingspotentieel (voor niet fossiele hulpbronnen) (ADPE): 0.0000099; 47 waterdichte laag - bitumen, Abiotisch Uitputtingspotentieel (voor fossiele hulpbronnen) (ADPF): 1150; 47 waterdichte laag - bitumen, Databron: https://www.oekobaudat.de/OEKOBAU.DAT/resource/processes/08dd0308-eebf-4db1-82ee-b340d070c9b9?version=00.06.000
32 x Isolatie - Kunststof hard | 2e dakoverzicht | Isolatie - Kunststof hard | Bestaand | Material Properties - Isolatie - Kunststof hard, ThermalConductivity: 0.029; Isolatie - Kunststof hard, SpecificHeatCapacity: 1470 J/kg/K; Isolatie - Kunststof hard, MassDensity: 100 kg/m3; Isolatie - Kunststof hard, Embodied Energy: 101.5 (MJ/kg); Isolatie - Kunststof hard, Embodied Carbon: 3.48 (kgCO₂/kg); Isolatie - Kunststof hard, Name: Isolatie - Kunststof hard; Isolatie - Kunststof hard, Participates in Collision Detection: yes; Isolatie - Kunststof hard, Aardopwarmingsvermogen (GWP): 0.04; Isolatie - Kunststof hard, Ozonafbrekend Vermogen (ODP): 0; Isolatie - Kunststof hard, Fotochemische Vermogen tot Ozonvorming (POCP): 0; Isolatie - Kunststof hard, Verzuringsvermogen (AP): 0.0000975; Isolatie - Kunststof hard, Eutrofiëringspotentieel (EP): 0.0000237; Isolatie - Kunststof hard, Abiotisch Uitputtingspotentieel (voor niet fossiele hulpbronnen) (ADPE): 0; Isolatie - Kunststof hard, Abiotisch Uitputtingspotentieel (voor fossiele hulpbronnen) (ADPF): 0.47; Isolatie - Kunststof hard, Databron: https://www.oekobaudat.de/OEKOBAU.DAT/resource/processes/41e09ab7-0e73-4303-84fd-97cb0809db02?version=00.04.000
7 x Steen - Baksteen | 2e dakoverzicht | Steen - Baksteen | Bestaand | Material Properties - Steen - Baksteen, ThermalConductivity: 0.9; Steen - Baksteen, SpecificHeatCapacity: 840 J/kg/K; Steen - Baksteen, MassDensity: 1600 kg/m3; Steen - Baksteen, Embodied Energy: 3 (MJ/kg); Steen - Baksteen, Embodied Carbon: 0.23 (kgCO₂/kg); Steen - Baksteen, Name: Steen - Baksteen; Steen - Baksteen, Participates in Collision Detection: yes; Steen - Baksteen, Aardopwarmingsvermogen (GWP): 113; Steen - Baksteen, Ozonafbrekend Vermogen (ODP): 0; Steen - Baksteen, Fotochemische Vermogen tot Ozonvorming (POCP): 0.012; Steen - Baksteen, Verzuringsvermogen (AP): 0.094; Steen - Baksteen, Eutrofiëringspotentieel (EP): 0.0189; Steen - Baksteen, Abiotisch Uitputtingspotentieel (voor niet fossiele hulpbronnen) (ADPE): 0.0000099; Steen - Baksteen, Abiotisch Uitputtingspotentieel (voor fossiele hulpbronnen) (ADPF): 1150; Steen - Baksteen, Databron: https://www.oekobaudat.de/OEKOBAU.DAT/resource/processes/08dd0308-eebf-4db1-82ee-b340d070c9b9?version=00.06.000
9 x Isolatie - Glaswol hard | 2e dakoverzicht | Isolatie - Glaswol hard | Bestaand | Material Properties - Isolatie - Glaswol hard, ThermalConductivity: 0.033; Isolatie - Glaswol hard, SpecificHeatCapacity: 1030 J/kg/K; Isolatie - Glaswol hard, MassDensity: 64 kg/m3; Isolatie - Glaswol hard, Embodied Energy: 37 (MJ/kg); Isolatie - Glaswol hard, Embodied Carbon: 1.48 (kgCO₂/kg); Isolatie - Glaswol hard, Name: Isolatie - Glaswol hard; Isolatie - Glaswol hard, Participates in Collision Detection: yes; Isolatie - Glaswol hard, Aardopwarmingsvermogen (GWP): 6.1351; Isolatie - Glaswol hard, Ozonafbrekend Vermogen (ODP): 0; Isolatie - Glaswol hard, Fotochemische Vermogen tot Ozonvorming (POCP): 0.0000526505; Isolatie - Glaswol hard, Verzuringsvermogen (AP): 0.00117721; Isolatie - Glaswol hard, Eutrofiëringspotentieel (EP): 0.00018735; Isolatie - Glaswol hard, Abiotisch Uitputtingspotentieel (voor niet fossiele hulpbronnen) (ADPE): 2.14662e-07; Isolatie - Glaswol hard, Abiotisch Uitputtingspotentieel (voor fossiele hulpbronnen) (ADPF): 2.00169; Isolatie - Glaswol hard, Databron: https://www.oekobaudat.de/OEKOBAU.DAT/resource/processes/0a93c854-9521-43c2-9f20-440af5d3e6c5?version=00.01.000
2 x Isolatie - Kunststof zacht | 2e dakoverzicht | Isolatie - Kunststof zacht | Bestaand | Material Properties - Isolatie - Kunststof zacht, ThermalConductivity: 0.036; Isolatie - Kunststof zacht, SpecificHeatCapacity: 1470 J/kg/K; Isolatie - Kunststof zacht, MassDensity: 20 kg/m3; Isolatie - Kunststof zacht, Embodied Energy: 88.6 (MJ/kg); Isolatie - Kunststof zacht, Embodied Carbon: 2.55 (kgCO₂/kg); Isolatie - Kunststof zacht, Name: Isolatie - Kunststof zacht; Isolatie - Kunststof zacht, Participates in Collision Detection: yes; Isolatie - Kunststof zacht, Aardopwarmingsvermogen (GWP): 2.9328; Isolatie - Kunststof zacht, Ozonafbrekend Vermogen (ODP): 0; Isolatie - Kunststof zacht, Fotochemische Vermogen tot Ozonvorming (POCP): 0.000924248; Isolatie - Kunststof zacht, Verzuringsvermogen (AP): 0.00810258; Isolatie - Kunststof zacht, Eutrofiëringspotentieel (EP): 0.00803134; Isolatie - Kunststof zacht, Abiotisch Uitputtingspotentieel (voor niet fossiele hulpbronnen) (ADPE): 6.06872e-07; Isolatie - Kunststof zacht, Abiotisch Uitputtingspotentieel (voor fossiele hulpbronnen) (ADPF): 42.0438; Isolatie - Kunststof zacht, Databron: https://www.oekobaudat.de/OEKOBAU.DAT/resource/processes/a564fa56-4723-4123-bbbd-2a8780c8c899?version=00.05.000
2 x Metaal - Staal C | 2e dakoverzicht | Metaal - Staal C | Bestaand | Material Properties - Metaal - Staal C, ThermalConductivity: 52; Metaal - Staal C, SpecificHeatCapacity: 530 J/kg/K; Metaal - Staal C, MassDensity: 7950 kg/m3; Metaal - Staal C, Embodied Energy: 25 (MJ/kg); Metaal - Staal C, Embodied Carbon: 1.91 (kgCO₂/kg); Metaal - Staal C, Name: Metaal - Staal C; Metaal - Staal C, Participates in Collision Detection: yes; Metaal - Staal C, Aardopwarmingsvermogen (GWP): 323.71; Metaal - Staal C, Ozonafbrekend Vermogen (ODP): 0; Metaal - Staal C, Fotochemische Vermogen tot Ozonvorming (POCP): 0.17963; Metaal - Staal C, Verzuringsvermogen (AP): 0.43354; Metaal - Staal C, Eutrofiëringspotentieel (EP): 0.014961; Metaal - Staal C, Abiotisch Uitputtingspotentieel (voor niet fossiele hulpbronnen) (ADPE): 0.00080492; Metaal - Staal C, Abiotisch Uitputtingspotentieel (voor fossiele hulpbronnen) (ADPF): 2862.1; Metaal - Staal C, Databron: https://www.oekobaudat.de/OEKOBAU.DAT/resource/processes/a85fbb4a-60a0-4ba9-9cfa-cdfbe1ec7f00?version=00.01.000
11 x Hout C | 2e dakoverzicht | Hout C | Bestaand | Material Properties - Hout C, ThermalConductivity: 0.14; Hout C, SpecificHeatCapacity: 1880 J/kg/K; Hout C, MassDensity: 550 kg/m3; Hout C, Embodied Energy: 7.4 (MJ/kg); Hout C, Embodied Carbon: 0.19 (kgCO₂/kg); Hout C, Name: Hout C; Hout C, Participates in Collision Detection: yes; Hout C, Aardopwarmingsvermogen (GWP): -349.478; Hout C, Ozonafbrekend Vermogen (ODP): 0; Hout C, Fotochemische Vermogen tot Ozonvorming (POCP): -0.028; Hout C, Verzuringsvermogen (AP): -0.352; Hout C, Eutrofiëringspotentieel (EP): -0.059; Hout C, Abiotisch Uitputtingspotentieel (voor fossiele hulpbronnen) (ADPF): -3860.46; Hout C, Databron: https://www.oekobaudat.de/OEKOBAU.DAT/resource/processes/07a5482a-fa4a-484d-8929-b6f6dfd6be3e?version=00.00.027
4 x Isolatie - Steenwol zacht | 2e dakoverzicht | Isolatie - Steenwol zacht | Bestaand | Material Properties - Isolatie - Steenwol zacht, ThermalConductivity: 0.035; Isolatie - Steenwol zacht, SpecificHeatCapacity: 840 J/kg/K; Isolatie - Steenwol zacht, MassDensity: 45 kg/m3; Isolatie - Steenwol zacht, Embodied Energy: 16.8 (MJ/kg); Isolatie - Steenwol zacht, Embodied Carbon: 1.05 (kgCO₂/kg); Isolatie - Steenwol zacht, Name: Isolatie - Steenwol zacht; Isolatie - Steenwol zacht, Participates in Collision Detection: yes; Isolatie - Steenwol zacht, Aardopwarmingsvermogen (GWP): -1.45742; Isolatie - Steenwol zacht, Fotochemische Vermogen tot Ozonvorming (POCP): -0.000168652; Isolatie - Steenwol zacht, Verzuringsvermogen (AP): -0.00166456; Isolatie - Steenwol zacht, Eutrofiëringspotentieel (EP): -0.000222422; Isolatie - Steenwol zacht, Abiotisch Uitputtingspotentieel (voor niet fossiele hulpbronnen) (ADPE): -2.57402e-07; Isolatie - Steenwol zacht, Abiotisch Uitputtingspotentieel (voor fossiele hulpbronnen) (ADPF): -20.4442; Isolatie - Steenwol zacht, Databron: https://www.oekobaudat.de/OEKOBAU.DAT/resource/processes/bd7319aa-d609-4f27-9460-d11bc966bb2b?version=00.03.000
3 x STO pleisterlaag | 2e dakoverzicht | STO pleisterlaag | Bestaand | Material Properties - STO pleisterlaag, ThermalConductivity: 0; STO pleisterlaag, SpecificHeatCapacity: 0 J/kg/K; STO pleisterlaag, MassDensity: 0 kg/m3; STO pleisterlaag, Embodied Energy: 0 (MJ/kg); STO pleisterlaag, Embodied Carbon: 0 (kgCO₂/kg); STO pleisterlaag, Name: STO pleisterlaag; STO pleisterlaag, Participates in Collision Detection: yes
5 x STO lijmlaag | 2e dakoverzicht | STO lijmlaag | Bestaand | Material Properties - STO lijmlaag, ThermalConductivity: 0; STO lijmlaag, SpecificHeatCapacity: 0 J/kg/K; STO lijmlaag, MassDensity: 0 kg/m3; STO lijmlaag, Embodied Energy: 0 (MJ/kg); STO lijmlaag, Embodied Carbon: 0 (kgCO₂/kg); STO lijmlaag, Name: STO lijmlaag; STO lijmlaag, Participates in Collision Detection: yes
3 x STO weefsellaag | 2e dakoverzicht | STO weefsellaag | Bestaand | Material Properties - STO weefsellaag, ThermalConductivity: 0; STO weefsellaag, SpecificHeatCapacity: 0 J/kg/K; STO weefsellaag, MassDensity: 0 kg/m3; STO weefsellaag, Embodied Energy: 0 (MJ/kg); STO weefsellaag, Embodied Carbon: 0 (kgCO₂/kg); STO weefsellaag, Name: STO weefsellaag; STO weefsellaag, Participates in Collision Detection: yes
3 x Cementgebonden plaatmateriaal | 2e dakoverzicht | Cementgebonden plaatmateriaal | Bestaand | Material Properties - Cementgebonden plaatmateriaal, ThermalConductivity: 0.45; Cementgebonden plaatmateriaal, SpecificHeatCapacity: 840 J/kg/K; Cementgebonden plaatmateriaal, MassDensity: 1400 kg/m3; Cementgebonden plaatmateriaal, Embodied Energy: 6.75 (MJ/kg); Cementgebonden plaatmateriaal, Embodied Carbon: 0.38 (kgCO₂/kg); Cementgebonden plaatmateriaal, Name: Cementgebonden plaatmateriaal; Cementgebonden plaatmateriaal, Participates in Collision Detection: yes; Cementgebonden plaatmateriaal, Aardopwarmingsvermogen (GWP): 1.62283; Cementgebonden plaatmateriaal, Ozonafbrekend Vermogen (ODP): 0; Cementgebonden plaatmateriaal, Fotochemische Vermogen tot Ozonvorming (POCP): 33.9565; Cementgebonden plaatmateriaal, Verzuringsvermogen (AP): 0.000135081; Cementgebonden plaatmateriaal, Eutrofiëringspotentieel (EP): 0.00274111; Cementgebonden plaatmateriaal, Abiotisch Uitputtingspotentieel (voor niet fossiele hulpbronnen) (ADPE): 0; Cementgebonden plaatmateriaal, Abiotisch Uitputtingspotentieel (voor fossiele hulpbronnen) (ADPF): 0.000893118; Cementgebonden plaatmateriaal, Databron: https://www.oekobaudat.de/OEKOBAU.DAT/resource/processes/07423e99-8c7c-4e93-8311-dcf7ae85c41d?version=20.20.010
6 x Isolatie - STO EPS | 2e dakoverzicht | Isolatie - STO EPS | Bestaand | Material Properties - Isolatie - STO EPS, ThermalConductivity: 0.029; Isolatie - STO EPS, SpecificHeatCapacity: 1470 J/kg/K; Isolatie - STO EPS, MassDensity: 100 kg/m3; Isolatie - STO EPS, Embodied Energy: 101.5 (MJ/kg); Isolatie - STO EPS, Embodied Carbon: 3.48 (kgCO₂/kg); Isolatie - STO EPS, Name: Isolatie - STO EPS; Isolatie - STO EPS, Participates in Collision Detection: yes; Isolatie - STO EPS, Aardopwarmingsvermogen (GWP): 0.04; Isolatie - STO EPS, Ozonafbrekend Vermogen (ODP): 0; Isolatie - STO EPS, Fotochemische Vermogen tot Ozonvorming (POCP): 0; Isolatie - STO EPS, Verzuringsvermogen (AP): 0.0000975; Isolatie - STO EPS, Eutrofiëringspotentieel (EP): 0.0000237; Isolatie - STO EPS, Abiotisch Uitputtingspotentieel (voor niet fossiele hulpbronnen) (ADPE): 0; Isolatie - STO EPS, Abiotisch Uitputtingspotentieel (voor fossiele hulpbronnen) (ADPF): 0.47; Isolatie - STO EPS, Databron: https://www.oekobaudat.de/OEKOBAU.DAT/resource/processes/41e09ab7-0e73-4303-84fd-97cb0809db02?version=00.04.000
8 x Gipsplaat | 2e dakoverzicht | Gipsplaat | Material Properties - Gipsplaat, ThermalConductivity: 0.23; Gipsplaat, SpecificHeatCapacity: 840 J/kg/K; Gipsplaat, MassDensity: 800 kg/m3; Gipsplaat, Embodied Energy: 6.75 (MJ/kg); Gipsplaat, Embodied Carbon: 0.38 (kgCO₂/kg); Gipsplaat, Name: Gipsplaat; Gipsplaat, Participates in Collision Detection: yes; Gipsplaat, Aardopwarmingsvermogen (GWP): 1.513; Gipsplaat, Ozonafbrekend Vermogen (ODP): 1.32e-07; Gipsplaat, Fotochemische Vermogen tot Ozonvorming (POCP): 0.000358; Gipsplaat, Verzuringsvermogen (AP): 0.0082; Gipsplaat, Eutrofiëringspotentieel (EP): 0.00138; Gipsplaat, Abiotisch Uitputtingspotentieel (voor niet fossiele hulpbronnen) (ADPE): 0.00000729; Gipsplaat, Abiotisch Uitputtingspotentieel (voor fossiele hulpbronnen) (ADPF): 25.04; Gipsplaat, Databron: https://www.oekobaudat.de/OEKOBAU.DAT/resource/processes/1a24808b-9116-422e-93fb-d435f74a038a?version=00.05.000
4 x ALG - LICHTE SCHEIDINGSWAND | 2e dakoverzicht | ALG - LICHTE SCHEIDINGSWAND | Material Properties - ALG - LICHTE SCHEIDINGSWAND, ThermalConductivity: 0.27; ALG - LICHTE SCHEIDINGSWAND, SpecificHeatCapacity: 840 J/kg/K; ALG - LICHTE SCHEIDINGSWAND, MassDensity: 800 kg/m3; ALG - LICHTE SCHEIDINGSWAND, Embodied Energy: 2 (MJ/kg); ALG - LICHTE SCHEIDINGSWAND, Embodied Carbon: 0.13 (kgCO₂/kg); ALG - LICHTE SCHEIDINGSWAND, Name: ALG - LICHTE SCHEIDINGSWAND; ALG - LICHTE SCHEIDINGSWAND, Participates in Collision Detection: yes

# IfcBuildingElementProxy: ALG - ALGEMEEN 20 (16)
Material: ALG - ALGEMEEN
Material Properties - ALG - ALGEMEEN, ThermalConductivity: 0.27; ALG - ALGEMEEN, SpecificHeatCapacity: 840 J/kg/K; ALG - ALGEMEEN, MassDensity: 800 kg/m3; ALG - ALGEMEEN, Embodied Energy: 2 (MJ/kg); ALG - ALGEMEEN, Embodied Carbon: 0.13 (kgCO₂/kg); ALG - ALGEMEEN, Name: ALG - ALGEMEEN; ALG - ALGEMEEN, Participates in Collision Detection: yes; ALG - ALGEMEEN, Handelsgewicht (kg/m): 0; ALG - ALGEMEEN, Soortelijk gewicht (kg/m3): 7850; ALG - ALGEMEEN, Marge materiaal: 1
Name | In
5 x _Wand-x | Begane grond
11 x _Wand-x | 1e verdieping

# IfcBuildingElementProxy: ALG - ALGEMEEN 55 (3)
In: 1e verdieping
Material: ALG - ALGEMEEN
Material Properties - ALG - ALGEMEEN, ThermalConductivity: 0.27; ALG - ALGEMEEN, SpecificHeatCapacity: 840 J/kg/K; ALG - ALGEMEEN, MassDensity: 800 kg/m3; ALG - ALGEMEEN, Embodied Energy: 2 (MJ/kg); ALG - ALGEMEEN, Embodied Carbon: 0.13 (kgCO₂/kg); ALG - ALGEMEEN, Name: ALG - ALGEMEEN; ALG - ALGEMEEN, Participates in Collision Detection: yes; ALG - ALGEMEEN, Handelsgewicht (kg/m): 0; ALG - ALGEMEEN, Soortelijk gewicht (kg/m3): 7850; ALG - ALGEMEEN, Marge materiaal: 1

# IfcBuildingElementProxy: Beton gewapend C 150 (6)
In: Kelder
Material: Beton gewapend C
Material Properties - Beton gewapend C, ThermalConductivity: 2.3; Beton gewapend C, SpecificHeatCapacity: 1000 J/kg/K; Beton gewapend C, MassDensity: 2300 kg/m3; Beton gewapend C, Embodied Energy: 1.92 (MJ/kg); Beton gewapend C, Embodied Carbon: 0.198 (kgCO₂/kg); Beton gewapend C, Name: Beton gewapend C; Beton gewapend C, Participates in Collision Detection: yes; Beton gewapend C, Aardopwarmingsvermogen (GWP): -1.02642; Beton gewapend C, Ozonafbrekend Vermogen (ODP): 0; Beton gewapend C, Fotochemische Vermogen tot Ozonvorming (POCP): 0.000222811; Beton gewapend C, Verzuringsvermogen (AP): -0.00242385; Beton gewapend C, Eutrofiëringspotentieel (EP): -0.000471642; Beton gewapend C, Abiotisch Uitputtingspotentieel (voor niet fossiele hulpbronnen) (ADPE): -2.28121e-07; Beton gewapend C, Abiotisch Uitputtingspotentieel (voor fossiele hulpbronnen) (ADPF): -12.4095; Beton gewapend C, Databron: https://www.oekobaudat.de/OEKOBAU.DAT/resource/processes/d3b59cac-3b4e-4d18-8c3a-780b553c9591?version=20.19.120

# IfcBuildingElementProxy: Beton gewapend C 200 (5)
In: Kelder
Material: Beton gewapend C
Material Properties - Beton gewapend C, ThermalConductivity: 2.3; Beton gewapend C, SpecificHeatCapacity: 1000 J/kg/K; Beton gewapend C, MassDensity: 2300 kg/m3; Beton gewapend C, Embodied Energy: 1.92 (MJ/kg); Beton gewapend C, Embodied Carbon: 0.198 (kgCO₂/kg); Beton gewapend C, Name: Beton gewapend C; Beton gewapend C, Participates in Collision Detection: yes; Beton gewapend C, Aardopwarmingsvermogen (GWP): -1.02642; Beton gewapend C, Ozonafbrekend Vermogen (ODP): 0; Beton gewapend C, Fotochemische Vermogen tot Ozonvorming (POCP): 0.000222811; Beton gewapend C, Verzuringsvermogen (AP): -0.00242385; Beton gewapend C, Eutrofiëringspotentieel (EP): -0.000471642; Beton gewapend C, Abiotisch Uitputtingspotentieel (voor niet fossiele hulpbronnen) (ADPE): -2.28121e-07; Beton gewapend C, Abiotisch Uitputtingspotentieel (voor fossiele hulpbronnen) (ADPF): -12.4095; Beton gewapend C, Databron: https://www.oekobaudat.de/OEKOBAU.DAT/resource/processes/d3b59cac-3b4e-4d18-8c3a-780b553c9591?version=20.19.120

# IfcBuildingElementProxy: Beton gewapend C 300 (4)
In: Kelder
Material: Beton gewapend C
Material Properties - Beton gewapend C, ThermalConductivity: 2.3; Beton gewapend C, SpecificHeatCapacity: 1000 J/kg/K; Beton gewapend C, MassDensity: 2300 kg/m3; Beton gewapend C, Embodied Energy: 1.92 (MJ/kg); Beton gewapend C, Embodied Carbon: 0.198 (kgCO₂/kg); Beton gewapend C, Name: Beton gewapend C; Beton gewapend C, Participates in Collision Detection: yes; Beton gewapend C, Aardopwarmingsvermogen (GWP): -1.02642; Beton gewapend C, Ozonafbrekend Vermogen (ODP): 0; Beton gewapend C, Fotochemische Vermogen tot Ozonvorming (POCP): 0.000222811; Beton gewapend C, Verzuringsvermogen (AP): -0.00242385; Beton gewapend C, Eutrofiëringspotentieel (EP): -0.000471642; Beton gewapend C, Abiotisch Uitputtingspotentieel (voor niet fossiele hulpbronnen) (ADPE): -2.28121e-07; Beton gewapend C, Abiotisch Uitputtingspotentieel (voor fossiele hulpbronnen) (ADPF): -12.4095; Beton gewapend C, Databron: https://www.oekobaudat.de/OEKOBAU.DAT/resource/processes/d3b59cac-3b4e-4d18-8c3a-780b553c9591?version=20.19.120

# IfcBuildingElementProxy: Beton gewapend prefab 250 (4)
In: Kelder
Material: Beton gewapend prefab
Material Properties - Beton gewapend prefab, ThermalConductivity: 2.5; Beton gewapend prefab, SpecificHeatCapacity: 1000 J/kg/K; Beton gewapend prefab, MassDensity: 2400 kg/m3; Beton gewapend prefab, Embodied Energy: 2.33 (MJ/kg); Beton gewapend prefab, Embodied Carbon: 0.242 (kgCO₂/kg); Beton gewapend prefab, Name: Beton gewapend prefab; Beton gewapend prefab, Participates in Collision Detection: yes; Beton gewapend prefab, Aardopwarmingsvermogen (GWP): 129.993; Beton gewapend prefab, Ozonafbrekend Vermogen (ODP): 0; Beton gewapend prefab, Fotochemische Vermogen tot Ozonvorming (POCP): 0.00471246; Beton gewapend prefab, Verzuringsvermogen (AP): 0.182012; Beton gewapend prefab, Eutrofiëringspotentieel (EP): 0.0346685; Beton gewapend prefab, Abiotisch Uitputtingspotentieel (voor niet fossiele hulpbronnen) (ADPE): 0.000140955; Beton gewapend prefab, Abiotisch Uitputtingspotentieel (voor fossiele hulpbronnen) (ADPF): 604.803; Beton gewapend prefab, Databron: https://www.oekobaudat.de/OEKOBAU.DAT/resource/processes/3470c523-ffcd-48df-93ff-dedfde86572a?version=20.19.010

# IfcBuildingElementProxy: Eternit wit 8, f7 Vormvaste grondstoffen, gebonden met gips_Wand-x
In: Begane grond
Material: Eternit wit
Material Properties - Eternit wit, ThermalConductivity: 0.45; Eternit wit, SpecificHeatCapacity: 840 J/kg/K; Eternit wit, MassDensity: 1400 kg/m3; Eternit wit, Embodied Energy: 6.75 (MJ/kg); Eternit wit, Embodied Carbon: 0.38 (kgCO₂/kg); Eternit wit, Name: Eternit wit; Eternit wit, Participates in Collision Detection: yes; Eternit wit, Aardopwarmingsvermogen (GWP): 1.62283; Eternit wit, Ozonafbrekend Vermogen (ODP): 0; Eternit wit, Fotochemische Vermogen tot Ozonvorming (POCP): 33.9565; Eternit wit, Verzuringsvermogen (AP): 0.000135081; Eternit wit, Eutrofiëringspotentieel (EP): 0.00274111; Eternit wit, Abiotisch Uitputtingspotentieel (voor niet fossiele hulpbronnen) (ADPE): 0; Eternit wit, Abiotisch Uitputtingspotentieel (voor fossiele hulpbronnen) (ADPF): 0.000893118; Eternit wit, Databron: https://www.oekobaudat.de/OEKOBAU.DAT/resource/processes/07423e99-8c7c-4e93-8311-dcf7ae85c41d?version=20.20.010

# IfcBuildingElementProxy: Hout - Multiplex 1 (4)
Material: Hout - Multiplex
Material Properties - Hout - Multiplex, ThermalConductivity: 0.17; Hout - Multiplex, SpecificHeatCapacity: 1600 J/kg/K; Hout - Multiplex, MassDensity: 700 kg/m3; Hout - Multiplex, Embodied Energy: 15 (MJ/kg); Hout - Multiplex, Embodied Carbon: 0.77 (kgCO₂/kg); Hout - Multiplex, Name: Hout - Multiplex; Hout - Multiplex, Participates in Collision Detection: yes; Hout - Multiplex, Aardopwarmingsvermogen (GWP): -32.4496; Hout - Multiplex, Ozonafbrekend Vermogen (ODP): 0; Hout - Multiplex, Fotochemische Vermogen tot Ozonvorming (POCP): -0.00287346; Hout - Multiplex, Verzuringsvermogen (AP): 0.138611; Hout - Multiplex, Eutrofiëringspotentieel (EP): 0.0523292; Hout - Multiplex, Abiotisch Uitputtingspotentieel (voor niet fossiele hulpbronnen) (ADPE): -0.0000777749; Hout - Multiplex, Abiotisch Uitputtingspotentieel (voor fossiele hulpbronnen) (ADPF): -4006.31; Hout - Multiplex, Databron: https://www.oekobaudat.de/OEKOBAU.DAT/resource/processes/cc180aec-8a5c-4e07-b1a0-1ab81dd746ac?version=20.20.120
Name | In
3 x i4 In lagen verlijmd hout_Leeg | Begane grond
i4 In lagen verlijmd hout_Leeg | 1e verdieping

# IfcBuildingElementProxy: Hout - Multiplex 12, i4 In lagen verlijmd hout_Wand-x
In: Begane grond
Material: Hout - Multiplex
Material Properties - Hout - Multiplex, ThermalConductivity: 0.17; Hout - Multiplex, SpecificHeatCapacity: 1600 J/kg/K; Hout - Multiplex, MassDensity: 700 kg/m3; Hout - Multiplex, Embodied Energy: 15 (MJ/kg); Hout - Multiplex, Embodied Carbon: 0.77 (kgCO₂/kg); Hout - Multiplex, Name: Hout - Multiplex; Hout - Multiplex, Participates in Collision Detection: yes; Hout - Multiplex, Aardopwarmingsvermogen (GWP): -32.4496; Hout - Multiplex, Ozonafbrekend Vermogen (ODP): 0; Hout - Multiplex, Fotochemische Vermogen tot Ozonvorming (POCP): -0.00287346; Hout - Multiplex, Verzuringsvermogen (AP): 0.138611; Hout - Multiplex, Eutrofiëringspotentieel (EP): 0.0523292; Hout - Multiplex, Abiotisch Uitputtingspotentieel (voor niet fossiele hulpbronnen) (ADPE): -0.0000777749; Hout - Multiplex, Abiotisch Uitputtingspotentieel (voor fossiele hulpbronnen) (ADPF): -4006.31; Hout - Multiplex, Databron: https://www.oekobaudat.de/OEKOBAU.DAT/resource/processes/cc180aec-8a5c-4e07-b1a0-1ab81dd746ac?version=20.20.120

# IfcBuildingElementProxy: Hout - Multiplex 18, i4 In lagen verlijmd hout_Leeg
In: 1e verdieping
Material: Hout - Multiplex
Material Properties - Hout - Multiplex, ThermalConductivity: 0.17; Hout - Multiplex, SpecificHeatCapacity: 1600 J/kg/K; Hout - Multiplex, MassDensity: 700 kg/m3; Hout - Multiplex, Embodied Energy: 15 (MJ/kg); Hout - Multiplex, Embodied Carbon: 0.77 (kgCO₂/kg); Hout - Multiplex, Name: Hout - Multiplex; Hout - Multiplex, Participates in Collision Detection: yes; Hout - Multiplex, Aardopwarmingsvermogen (GWP): -32.4496; Hout - Multiplex, Ozonafbrekend Vermogen (ODP): 0; Hout - Multiplex, Fotochemische Vermogen tot Ozonvorming (POCP): -0.00287346; Hout - Multiplex, Verzuringsvermogen (AP): 0.138611; Hout - Multiplex, Eutrofiëringspotentieel (EP): 0.0523292; Hout - Multiplex, Abiotisch Uitputtingspotentieel (voor niet fossiele hulpbronnen) (ADPE): -0.0000777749; Hout - Multiplex, Abiotisch Uitputtingspotentieel (voor fossiele hulpbronnen) (ADPF): -4006.31; Hout - Multiplex, Databron: https://www.oekobaudat.de/OEKOBAU.DAT/resource/processes/cc180aec-8a5c-4e07-b1a0-1ab81dd746ac?version=20.20.120

# IfcBuildingElementProxy: Hout AFW 18 (41)
Material: Hout AFW
Material Properties - Hout AFW, ThermalConductivity: 0.14; Hout AFW, SpecificHeatCapacity: 1880 J/kg/K; Hout AFW, MassDensity: 550 kg/m3; Hout AFW, Embodied Energy: 7.4 (MJ/kg); Hout AFW, Embodied Carbon: 0.19 (kgCO₂/kg); Hout AFW, Name: Hout AFW; Hout AFW, Participates in Collision Detection: yes
Name | In
22 x i HOUT_Wand-x | Begane grond
19 x i HOUT_Wand-x | 1e verdieping

# IfcBuildingElementProxy: Hout AFW 20 (56)
Material: Hout AFW
Material Properties - Hout AFW, ThermalConductivity: 0.14; Hout AFW, SpecificHeatCapacity: 1880 J/kg/K; Hout AFW, MassDensity: 550 kg/m3; Hout AFW, Embodied Energy: 7.4 (MJ/kg); Hout AFW, Embodied Carbon: 0.19 (kgCO₂/kg); Hout AFW, Name: Hout AFW; Hout AFW, Participates in Collision Detection: yes
Name | In
24 x i HOUT_Wand-x | Begane grond
32 x i HOUT_Wand-x | 1e verdieping

# IfcBuildingElementProxy: Isolatie - Kunststof hard 140 (21)
In: Kelder
Material: Isolatie - Kunststof hard
Material Properties - Isolatie - Kunststof hard, ThermalConductivity: 0.029; Isolatie - Kunststof hard, SpecificHeatCapacity: 1470 J/kg/K; Isolatie - Kunststof hard, MassDensity: 100 kg/m3; Isolatie - Kunststof hard, Embodied Energy: 101.5 (MJ/kg); Isolatie - Kunststof hard, Embodied Carbon: 3.48 (kgCO₂/kg); Isolatie - Kunststof hard, Name: Isolatie - Kunststof hard; Isolatie - Kunststof hard, Participates in Collision Detection: yes; Isolatie - Kunststof hard, Aardopwarmingsvermogen (GWP): 0.04; Isolatie - Kunststof hard, Ozonafbrekend Vermogen (ODP): 0; Isolatie - Kunststof hard, Fotochemische Vermogen tot Ozonvorming (POCP): 0; Isolatie - Kunststof hard, Verzuringsvermogen (AP): 0.0000975; Isolatie - Kunststof hard, Eutrofiëringspotentieel (EP): 0.0000237; Isolatie - Kunststof hard, Abiotisch Uitputtingspotentieel (voor niet fossiele hulpbronnen) (ADPE): 0; Isolatie - Kunststof hard, Abiotisch Uitputtingspotentieel (voor fossiele hulpbronnen) (ADPF): 0.47; Isolatie - Kunststof hard, Databron: https://www.oekobaudat.de/OEKOBAU.DAT/resource/processes/41e09ab7-0e73-4303-84fd-97cb0809db02?version=00.04.000

# IfcBuildingElementProxy: KZ 150 150 (6)
Material: Steen - Kalkzandsteen C
Material Properties - Steen - Kalkzandsteen C, ThermalConductivity: 0.9; Steen - Kalkzandsteen C, SpecificHeatCapacity: 840 J/kg/K; Steen - Kalkzandsteen C, MassDensity: 1900 kg/m3; Steen - Kalkzandsteen C, Embodied Energy: 0.75 (MJ/kg); Steen - Kalkzandsteen C, Embodied Carbon: 0.1 (kgCO₂/kg); Steen - Kalkzandsteen C, Name: Steen - Kalkzandsteen C; Steen - Kalkzandsteen C, Participates in Collision Detection: yes; Steen - Kalkzandsteen C, Aardopwarmingsvermogen (GWP): 5.10595; Steen - Kalkzandsteen C, Ozonafbrekend Vermogen (ODP): 0; Steen - Kalkzandsteen C, Fotochemische Vermogen tot Ozonvorming (POCP): -0.00337081; Steen - Kalkzandsteen C, Verzuringsvermogen (AP): 0.0103135; Steen - Kalkzandsteen C, Eutrofiëringspotentieel (EP): 0.0024518; Steen - Kalkzandsteen C, Abiotisch Uitputtingspotentieel (voor niet fossiele hulpbronnen) (ADPE): 4.2967e-07; Steen - Kalkzandsteen C, Abiotisch Uitputtingspotentieel (voor fossiele hulpbronnen) (ADPF): 68.4425; Steen - Kalkzandsteen C, Databron: https://www.oekobaudat.de/OEKOBAU.DAT/resource/processes/bdda4364-451f-4df2-a68b-5912469ee4c9?version=20.19.120
Name | In
3 x f1 Gebonden met kalk_Wand-x | Begane grond
3 x f1 Gebonden met kalk_Wand-x | 1e verdieping

# IfcBuildingElementProxy: Metaal - Staal C 4, h METAAL_Wand-x
In: Begane grond
Material: Metaal - Staal C
Material Properties - Metaal - Staal C, ThermalConductivity: 52; Metaal - Staal C, SpecificHeatCapacity: 530 J/kg/K; Metaal - Staal C, MassDensity: 7950 kg/m3; Metaal - Staal C, Embodied Energy: 25 (MJ/kg); Metaal - Staal C, Embodied Carbon: 1.91 (kgCO₂/kg); Metaal - Staal C, Name: Metaal - Staal C; Metaal - Staal C, Participates in Collision Detection: yes; Metaal - Staal C, Aardopwarmingsvermogen (GWP): 323.71; Metaal - Staal C, Ozonafbrekend Vermogen (ODP): 0; Metaal - Staal C, Fotochemische Vermogen tot Ozonvorming (POCP): 0.17963; Metaal - Staal C, Verzuringsvermogen (AP): 0.43354; Metaal - Staal C, Eutrofiëringspotentieel (EP): 0.014961; Metaal - Staal C, Abiotisch Uitputtingspotentieel (voor niet fossiele hulpbronnen) (ADPE): 0.00080492; Metaal - Staal C, Abiotisch Uitputtingspotentieel (voor fossiele hulpbronnen) (ADPF): 2862.1; Metaal - Staal C, Databron: https://www.oekobaudat.de/OEKOBAU.DAT/resource/processes/a85fbb4a-60a0-4ba9-9cfa-cdfbe1ec7f00?version=00.01.000

# IfcBuildingElementProxy: R rond 26, _Merk AN
In: Begane grond
Pset_ConcreteElementGeneral - FireRating: 30 minuten brandwerend
Pset_FireRatingProperties - FireResistanceRating: 30 minuten brandwerend

# IfcBuildingElementProxy: Rnx horizontaal 26 (17)
Name | In
_Merk AB1 | Begane grond
_Merk AE | Begane grond | Pset_ConcreteElementGeneral - FireRating: 30 minuten brandwerend en zelfsluitend; Pset_FireRatingProperties - FireResistanceRating: 30 minuten brandwerend en zelfsluitend
2 x _Merk AC | Begane grond
2 x _Merk AG | Begane grond
_Merk AH | Begane grond
_Merk AL1 | Begane grond
_Merk BJ | 1e verdieping | Pset_ConcreteElementGeneral - FireRating: 30 minuten brandwerend; Pset_FireRatingProperties - FireResistanceRating: 30 minuten brandwerend
_Merk BH | 1e verdieping
3 x _Merk BA | 1e verdieping
_Merk BF | 1e verdieping
_Merk BE | 1e verdieping
_Merk BG | 1e verdieping | Pset_ConcreteElementGeneral - FireRating: 60 minuten brandwerend; Pset_FireRatingProperties - FireResistanceRating: 60 minuten brandwerend
_Merk BK2 | 1e verdieping

# IfcBuildingElementProxy: STO pleisterlaag 3, _Wand-x
In: 1e verdieping
Material: STO pleisterlaag
Material Properties - STO pleisterlaag, ThermalConductivity: 0; STO pleisterlaag, SpecificHeatCapacity: 0 J/kg/K; STO pleisterlaag, MassDensity: 0 kg/m3; STO pleisterlaag, Embodied Energy: 0 (MJ/kg); STO pleisterlaag, Embodied Carbon: 0 (kgCO₂/kg); STO pleisterlaag, Name: STO pleisterlaag; STO pleisterlaag, Participates in Collision Detection: yes

# IfcBuildingElementProxy: Steen - Baksteen 70, g2- Gebakken klei_Wand-x
In: Begane grond
Material: Steen - Baksteen
Material Properties - Steen - Baksteen, ThermalConductivity: 0.9; Steen - Baksteen, SpecificHeatCapacity: 840 J/kg/K; Steen - Baksteen, MassDensity: 1600 kg/m3; Steen - Baksteen, Embodied Energy: 3 (MJ/kg); Steen - Baksteen, Embodied Carbon: 0.23 (kgCO₂/kg); Steen - Baksteen, Name: Steen - Baksteen; Steen - Baksteen, Participates in Collision Detection: yes; Steen - Baksteen, Aardopwarmingsvermogen (GWP): 113; Steen - Baksteen, Ozonafbrekend Vermogen (ODP): 0; Steen - Baksteen, Fotochemische Vermogen tot Ozonvorming (POCP): 0.012; Steen - Baksteen, Verzuringsvermogen (AP): 0.094; Steen - Baksteen, Eutrofiëringspotentieel (EP): 0.0189; Steen - Baksteen, Abiotisch Uitputtingspotentieel (voor niet fossiele hulpbronnen) (ADPE): 0.0000099; Steen - Baksteen, Abiotisch Uitputtingspotentieel (voor fossiele hulpbronnen) (ADPF): 1150; Steen - Baksteen, Databron: https://www.oekobaudat.de/OEKOBAU.DAT/resource/processes/08dd0308-eebf-4db1-82ee-b340d070c9b9?version=00.06.000

# IfcBuildingElementProxy: Vloerafwerking - schoonloopzone 2 15 (3)
In: Begane grond
Material: Vloerafwerking - schoonloopzone 2
Material Properties - Vloerafwerking - schoonloopzone 2, ThermalConductivity: 2.3; Vloerafwerking - schoonloopzone 2, SpecificHeatCapacity: 1000 J/kg/K; Vloerafwerking - schoonloopzone 2, MassDensity: 2300 kg/m3; Vloerafwerking - schoonloopzone 2, Embodied Energy: 1.92 (MJ/kg); Vloerafwerking - schoonloopzone 2, Embodied Carbon: 0.198 (kgCO₂/kg); Vloerafwerking - schoonloopzone 2, Name: Vloerafwerking - schoonloopzone 2; Vloerafwerking - schoonloopzone 2, Participates in Collision Detection: yes

# IfcBuildingElementProxy: Vloerafwerking - schoonloopzone 3 15 (5)
Material: Vloerafwerking - schoonloopzone 3
Material Properties - Vloerafwerking - schoonloopzone 3, ThermalConductivity: 2.3; Vloerafwerking - schoonloopzone 3, SpecificHeatCapacity: 1000 J/kg/K; Vloerafwerking - schoonloopzone 3, MassDensity: 2300 kg/m3; Vloerafwerking - schoonloopzone 3, Embodied Energy: 1.92 (MJ/kg); Vloerafwerking - schoonloopzone 3, Embodied Carbon: 0.198 (kgCO₂/kg); Vloerafwerking - schoonloopzone 3, Name: Vloerafwerking - schoonloopzone 3; Vloerafwerking - schoonloopzone 3, Participates in Collision Detection: yes
Name | In
3 x _schoonloop zone 3 | Begane grond
2 x _43 marmoleum | 1e verdieping

# IfcColumn: 100X100X5 100 x 100 (7)
Type - PredefinedType: COLUMN
Material: Metaal - Staal C
CPset_Phasing - Renovation Phase: Bestaand
Pset_ColumnCommon - Slope: 90 deg; IsExternal: no; LoadBearing: yes; Reference: 100X100X5 100 x 100
Material Properties - Metaal - Staal C, ThermalConductivity: 52; Metaal - Staal C, SpecificHeatCapacity: 530 J/kg/K; Metaal - Staal C, MassDensity: 7950 kg/m3; Metaal - Staal C, Embodied Energy: 25 (MJ/kg); Metaal - Staal C, Embodied Carbon: 1.91 (kgCO₂/kg); Metaal - Staal C, Name: Metaal - Staal C; Metaal - Staal C, Participates in Collision Detection: yes; Metaal - Staal C, Aardopwarmingsvermogen (GWP): 323.71; Metaal - Staal C, Ozonafbrekend Vermogen (ODP): 0; Metaal - Staal C, Fotochemische Vermogen tot Ozonvorming (POCP): 0.17963; Metaal - Staal C, Verzuringsvermogen (AP): 0.43354; Metaal - Staal C, Eutrofiëringspotentieel (EP): 0.014961; Metaal - Staal C, Abiotisch Uitputtingspotentieel (voor niet fossiele hulpbronnen) (ADPE): 0.00080492; Metaal - Staal C, Abiotisch Uitputtingspotentieel (voor fossiele hulpbronnen) (ADPF): 2862.1; Metaal - Staal C, Databron: https://www.oekobaudat.de/OEKOBAU.DAT/resource/processes/a85fbb4a-60a0-4ba9-9cfa-cdfbe1ec7f00?version=00.01.000
Name | In
28_Kolom-x | Begane grond
6 x 28_Kolom-x | 1e verdieping

# IfcColumn: 100X100X6 100 x 100 (4)
In: Begane grond
Type - PredefinedType: COLUMN
Material: Metaal - Staal C
Pset_ColumnCommon - Slope: 90 deg; IsExternal: no; LoadBearing: yes; Reference: 100X100X6 100 x 100
CPset_Phasing - Renovation Phase: Bestaand
Material Properties - Metaal - Staal C, ThermalConductivity: 52; Metaal - Staal C, SpecificHeatCapacity: 530 J/kg/K; Metaal - Staal C, MassDensity: 7950 kg/m3; Metaal - Staal C, Embodied Energy: 25 (MJ/kg); Metaal - Staal C, Embodied Carbon: 1.91 (kgCO₂/kg); Metaal - Staal C, Name: Metaal - Staal C; Metaal - Staal C, Participates in Collision Detection: yes; Metaal - Staal C, Aardopwarmingsvermogen (GWP): 323.71; Metaal - Staal C, Ozonafbrekend Vermogen (ODP): 0; Metaal - Staal C, Fotochemische Vermogen tot Ozonvorming (POCP): 0.17963; Metaal - Staal C, Verzuringsvermogen (AP): 0.43354; Metaal - Staal C, Eutrofiëringspotentieel (EP): 0.014961; Metaal - Staal C, Abiotisch Uitputtingspotentieel (voor niet fossiele hulpbronnen) (ADPE): 0.00080492; Metaal - Staal C, Abiotisch Uitputtingspotentieel (voor fossiele hulpbronnen) (ADPF): 2862.1; Metaal - Staal C, Databron: https://www.oekobaudat.de/OEKOBAU.DAT/resource/processes/a85fbb4a-60a0-4ba9-9cfa-cdfbe1ec7f00?version=00.01.000

# IfcColumn: 100X100X8 100 x 100, 28_Kolom-x
In: Begane grond
Type - PredefinedType: COLUMN
Pset_ColumnCommon - Slope: 90 deg; IsExternal: no; LoadBearing: yes; Reference: 100X100X8 100 x 100
CPset_Phasing - Renovation Phase: Bestaand

# IfcColumn: 120X120X8 120 x 120 (6)
Type - PredefinedType: COLUMN
CPset_Phasing - Renovation Phase: Bestaand
Pset_ColumnCommon - Slope: 90 deg; IsExternal: no; LoadBearing: yes; Reference: 120X120X8 120 x 120
Name | In
3 x 28_Kolom-x | Begane grond
3 x 28_Kolom-x | 1e verdieping

# IfcColumn: 16 Fundering - betonbalk 1250 x 500, 28_Kolom-x
In: Kelder
Type - PredefinedType: COLUMN
Material: Beton gewapend C
Pset_ColumnCommon - Slope: 90 deg; IsExternal: no; LoadBearing: yes; Reference: 16 Fundering - betonbalk 1250 x 500
CPset_Phasing - Renovation Phase: Bestaand
Material Properties - Beton gewapend C, ThermalConductivity: 2.3; Beton gewapend C, SpecificHeatCapacity: 1000 J/kg/K; Beton gewapend C, MassDensity: 2300 kg/m3; Beton gewapend C, Embodied Energy: 1.92 (MJ/kg); Beton gewapend C, Embodied Carbon: 0.198 (kgCO₂/kg); Beton gewapend C, Name: Beton gewapend C; Beton gewapend C, Participates in Collision Detection: yes; Beton gewapend C, Aardopwarmingsvermogen (GWP): -1.02642; Beton gewapend C, Ozonafbrekend Vermogen (ODP): 0; Beton gewapend C, Fotochemische Vermogen tot Ozonvorming (POCP): 0.000222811; Beton gewapend C, Verzuringsvermogen (AP): -0.00242385; Beton gewapend C, Eutrofiëringspotentieel (EP): -0.000471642; Beton gewapend C, Abiotisch Uitputtingspotentieel (voor niet fossiele hulpbronnen) (ADPE): -2.28121e-07; Beton gewapend C, Abiotisch Uitputtingspotentieel (voor fossiele hulpbronnen) (ADPF): -12.4095; Beton gewapend C, Databron: https://www.oekobaudat.de/OEKOBAU.DAT/resource/processes/d3b59cac-3b4e-4d18-8c3a-780b553c9591?version=20.19.120

# IfcColumn: 16 Fundering - betonbalk 1250 x 600, 28_Kolom-x
In: Kelder
Type - PredefinedType: COLUMN
Material: Beton gewapend C
CPset_Phasing - Renovation Phase: Bestaand
Pset_ColumnCommon - Slope: 90 deg; IsExternal: no; LoadBearing: yes; Reference: 16 Fundering - betonbalk 1250 x 600
Material Properties - Beton gewapend C, ThermalConductivity: 2.3; Beton gewapend C, SpecificHeatCapacity: 1000 J/kg/K; Beton gewapend C, MassDensity: 2300 kg/m3; Beton gewapend C, Embodied Energy: 1.92 (MJ/kg); Beton gewapend C, Embodied Carbon: 0.198 (kgCO₂/kg); Beton gewapend C, Name: Beton gewapend C; Beton gewapend C, Participates in Collision Detection: yes; Beton gewapend C, Aardopwarmingsvermogen (GWP): -1.02642; Beton gewapend C, Ozonafbrekend Vermogen (ODP): 0; Beton gewapend C, Fotochemische Vermogen tot Ozonvorming (POCP): 0.000222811; Beton gewapend C, Verzuringsvermogen (AP): -0.00242385; Beton gewapend C, Eutrofiëringspotentieel (EP): -0.000471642; Beton gewapend C, Abiotisch Uitputtingspotentieel (voor niet fossiele hulpbronnen) (ADPE): -2.28121e-07; Beton gewapend C, Abiotisch Uitputtingspotentieel (voor fossiele hulpbronnen) (ADPF): -12.4095; Beton gewapend C, Databron: https://www.oekobaudat.de/OEKOBAU.DAT/resource/processes/d3b59cac-3b4e-4d18-8c3a-780b553c9591?version=20.19.120

# IfcColumn: 16 Fundering - betonbalk 600 x 500 (3)
In: Kelder
Type - PredefinedType: COLUMN
Material: Beton gewapend C
Pset_ColumnCommon - Slope: 90 deg; IsExternal: no; LoadBearing: yes; Reference: 16 Fundering - betonbalk 600 x 500
CPset_Phasing - Renovation Phase: Bestaand
Material Properties - Beton gewapend C, ThermalConductivity: 2.3; Beton gewapend C, SpecificHeatCapacity: 1000 J/kg/K; Beton gewapend C, MassDensity: 2300 kg/m3; Beton gewapend C, Embodied Energy: 1.92 (MJ/kg); Beton gewapend C, Embodied Carbon: 0.198 (kgCO₂/kg); Beton gewapend C, Name: Beton gewapend C; Beton gewapend C, Participates in Collision Detection: yes; Beton gewapend C, Aardopwarmingsvermogen (GWP): -1.02642; Beton gewapend C, Ozonafbrekend Vermogen (ODP): 0; Beton gewapend C, Fotochemische Vermogen tot Ozonvorming (POCP): 0.000222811; Beton gewapend C, Verzuringsvermogen (AP): -0.00242385; Beton gewapend C, Eutrofiëringspotentieel (EP): -0.000471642; Beton gewapend C, Abiotisch Uitputtingspotentieel (voor niet fossiele hulpbronnen) (ADPE): -2.28121e-07; Beton gewapend C, Abiotisch Uitputtingspotentieel (voor fossiele hulpbronnen) (ADPF): -12.4095; Beton gewapend C, Databron: https://www.oekobaudat.de/OEKOBAU.DAT/resource/processes/d3b59cac-3b4e-4d18-8c3a-780b553c9591?version=20.19.120

# IfcColumn: 16 Fundering - betonbalk 600 x 700, 28_Kolom-x
In: Kelder
Type - PredefinedType: COLUMN
Material: Beton gewapend C
Pset_ColumnCommon - Slope: 90 deg; IsExternal: no; LoadBearing: yes; Reference: 16 Fundering - betonbalk 600 x 700
CPset_Phasing - Renovation Phase: Bestaand
Material Properties - Beton gewapend C, ThermalConductivity: 2.3; Beton gewapend C, SpecificHeatCapacity: 1000 J/kg/K; Beton gewapend C, MassDensity: 2300 kg/m3; Beton gewapend C, Embodied Energy: 1.92 (MJ/kg); Beton gewapend C, Embodied Carbon: 0.198 (kgCO₂/kg); Beton gewapend C, Name: Beton gewapend C; Beton gewapend C, Participates in Collision Detection: yes; Beton gewapend C, Aardopwarmingsvermogen (GWP): -1.02642; Beton gewapend C, Ozonafbrekend Vermogen (ODP): 0; Beton gewapend C, Fotochemische Vermogen tot Ozonvorming (POCP): 0.000222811; Beton gewapend C, Verzuringsvermogen (AP): -0.00242385; Beton gewapend C, Eutrofiëringspotentieel (EP): -0.000471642; Beton gewapend C, Abiotisch Uitputtingspotentieel (voor niet fossiele hulpbronnen) (ADPE): -2.28121e-07; Beton gewapend C, Abiotisch Uitputtingspotentieel (voor fossiele hulpbronnen) (ADPF): -12.4095; Beton gewapend C, Databron: https://www.oekobaudat.de/OEKOBAU.DAT/resource/processes/d3b59cac-3b4e-4d18-8c3a-780b553c9591?version=20.19.120

# IfcColumn: 16 Fundering - betonbalk 700 x 500 (4)
In: Kelder
Type - PredefinedType: COLUMN
Material: Beton gewapend C
Pset_ColumnCommon - Slope: 90 deg; IsExternal: no; LoadBearing: yes; Reference: 16 Fundering - betonbalk 700 x 500
CPset_Phasing - Renovation Phase: Bestaand
Material Properties - Beton gewapend C, ThermalConductivity: 2.3; Beton gewapend C, SpecificHeatCapacity: 1000 J/kg/K; Beton gewapend C, MassDensity: 2300 kg/m3; Beton gewapend C, Embodied Energy: 1.92 (MJ/kg); Beton gewapend C, Embodied Carbon: 0.198 (kgCO₂/kg); Beton gewapend C, Name: Beton gewapend C; Beton gewapend C, Participates in Collision Detection: yes; Beton gewapend C, Aardopwarmingsvermogen (GWP): -1.02642; Beton gewapend C, Ozonafbrekend Vermogen (ODP): 0; Beton gewapend C, Fotochemische Vermogen tot Ozonvorming (POCP): 0.000222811; Beton gewapend C, Verzuringsvermogen (AP): -0.00242385; Beton gewapend C, Eutrofiëringspotentieel (EP): -0.000471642; Beton gewapend C, Abiotisch Uitputtingspotentieel (voor niet fossiele hulpbronnen) (ADPE): -2.28121e-07; Beton gewapend C, Abiotisch Uitputtingspotentieel (voor fossiele hulpbronnen) (ADPF): -12.4095; Beton gewapend C, Databron: https://www.oekobaudat.de/OEKOBAU.DAT/resource/processes/d3b59cac-3b4e-4d18-8c3a-780b553c9591?version=20.19.120

# IfcColumn: 193.7X12.5 194 x 194 (6)
Type - PredefinedType: COLUMN
Pset_ColumnCommon - Slope: 90 deg; IsExternal: no; LoadBearing: yes; Reference: 193.7X12.5 194 x 194
CPset_Phasing - Renovation Phase: Bestaand
Name | In
4 x 28_Kolom-x | Begane grond
2 x 28_Kolom-x | 1e verdieping

# IfcColumn: 200X200X10 200 x 200 (57)
Type - PredefinedType: COLUMN
Pset_ColumnCommon - Slope: 90 deg; IsExternal: no; LoadBearing: yes; Reference: 200X200X10 200 x 200
CPset_Phasing - Renovation Phase: Bestaand
Name | In
33 x 28_Kolom-x | Begane grond
24 x 28_Kolom-x | 1e verdieping

# IfcColumn: 21 Hoekaansluiting staalplaat 154 x 250, 28_Kolom-x
In: Begane grond
Type - PredefinedType: COLUMN
Pset_ColumnCommon - Slope: 90 deg; IsExternal: no; LoadBearing: yes; Reference: 21 Hoekaansluiting staalplaat 154 x 250
CPset_Phasing - Renovation Phase: Bestaand

# IfcColumn: 21 Hoekaansluiting stucwerk 250 x 176, 28_Kolom-x
In: 1e verdieping
Type - PredefinedType: COLUMN
Pset_ColumnCommon - Slope: 90 deg; IsExternal: no; LoadBearing: yes; Reference: 21 Hoekaansluiting stucwerk 250 x 176
CPset_Phasing - Renovation Phase: Bestaand

# IfcColumn: 21 Kopsekant stucwerk 434 x 140, 28_Kolom-x
In: 1e verdieping
Type - PredefinedType: COLUMN
CPset_Phasing - Renovation Phase: Bestaand
Pset_ColumnCommon - Slope: 90 deg; IsExternal: no; LoadBearing: yes; Reference: 21 Kopsekant stucwerk 434 x 140

# IfcColumn: 50 HWA 100 100 x 100, 28_Kolom-x
In: Begane grond
Type - PredefinedType: COLUMN
CPset_Phasing - Renovation Phase: Bestaand
Pset_ColumnCommon - Slope: 90 deg; IsExternal: no; LoadBearing: yes; Reference: 50 HWA 100 100 x 100

# IfcColumn: 50 HWA pluvia 190 x 190, 28_Kolom-x
In: Begane grond
Type - PredefinedType: COLUMN
Pset_ColumnCommon - Slope: 90 deg; IsExternal: no; LoadBearing: yes; Reference: 50 HWA pluvia 190 x 190
CPset_Phasing - Renovation Phase: Bestaand

# IfcColumn: 70X70X5 70 x 70 (2)
In: Begane grond
Type - PredefinedType: COLUMN
Material: Metaal - Staal C
Pset_ColumnCommon - Slope: 90 deg; IsExternal: no; LoadBearing: yes; Reference: 70X70X5 70 x 70
CPset_Phasing - Renovation Phase: Bestaand
Material Properties - Metaal - Staal C, ThermalConductivity: 52; Metaal - Staal C, SpecificHeatCapacity: 530 J/kg/K; Metaal - Staal C, MassDensity: 7950 kg/m3; Metaal - Staal C, Embodied Energy: 25 (MJ/kg); Metaal - Staal C, Embodied Carbon: 1.91 (kgCO₂/kg); Metaal - Staal C, Name: Metaal - Staal C; Metaal - Staal C, Participates in Collision Detection: yes; Metaal - Staal C, Aardopwarmingsvermogen (GWP): 323.71; Metaal - Staal C, Ozonafbrekend Vermogen (ODP): 0; Metaal - Staal C, Fotochemische Vermogen tot Ozonvorming (POCP): 0.17963; Metaal - Staal C, Verzuringsvermogen (AP): 0.43354; Metaal - Staal C, Eutrofiëringspotentieel (EP): 0.014961; Metaal - Staal C, Abiotisch Uitputtingspotentieel (voor niet fossiele hulpbronnen) (ADPE): 0.00080492; Metaal - Staal C, Abiotisch Uitputtingspotentieel (voor fossiele hulpbronnen) (ADPF): 2862.1; Metaal - Staal C, Databron: https://www.oekobaudat.de/OEKOBAU.DAT/resource/processes/a85fbb4a-60a0-4ba9-9cfa-cdfbe1ec7f00?version=00.01.000

# IfcColumn: 80x40x5 80 x 40, 28_Kolom-x
In: Begane grond
Type - PredefinedType: COLUMN
Material: Metaal - Staal C
Pset_ColumnCommon - Slope: 90 deg; IsExternal: no; LoadBearing: yes; Reference: 80x40x5 80 x 40
CPset_Phasing - Renovation Phase: Bestaand
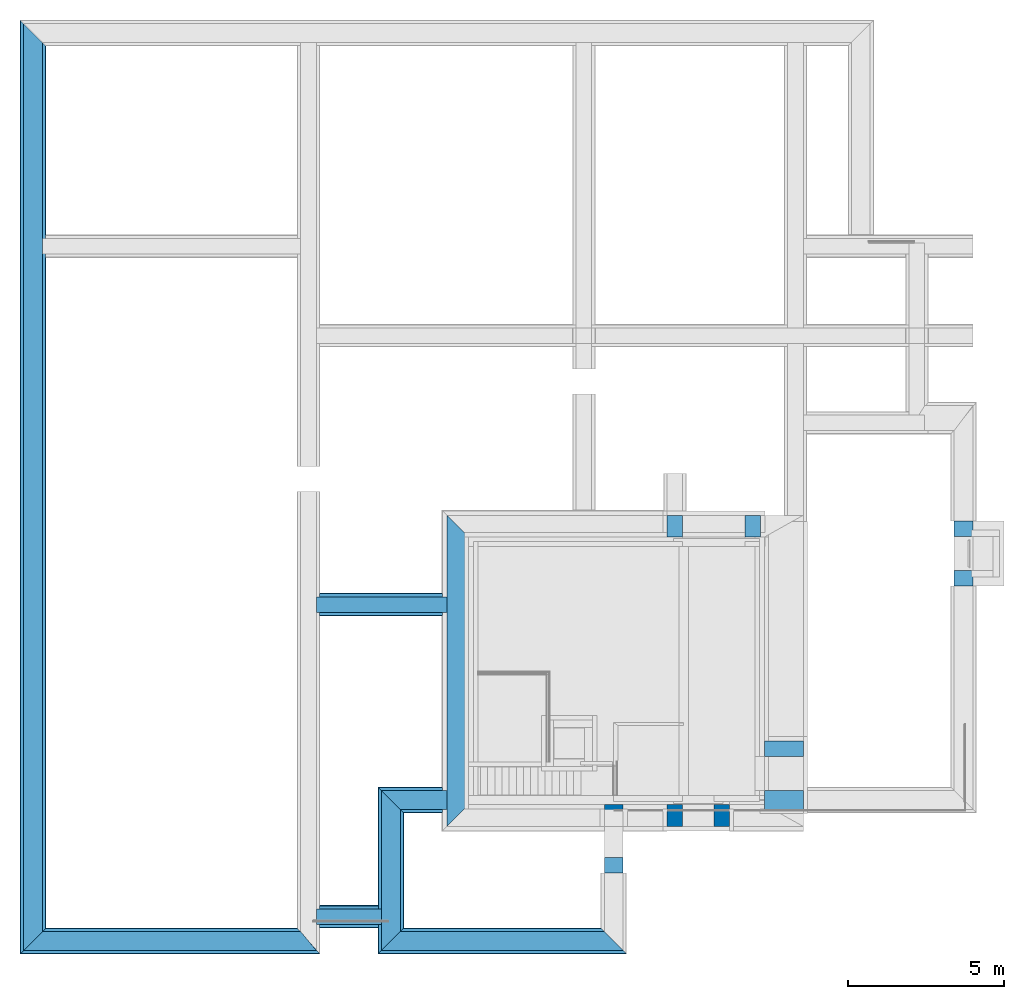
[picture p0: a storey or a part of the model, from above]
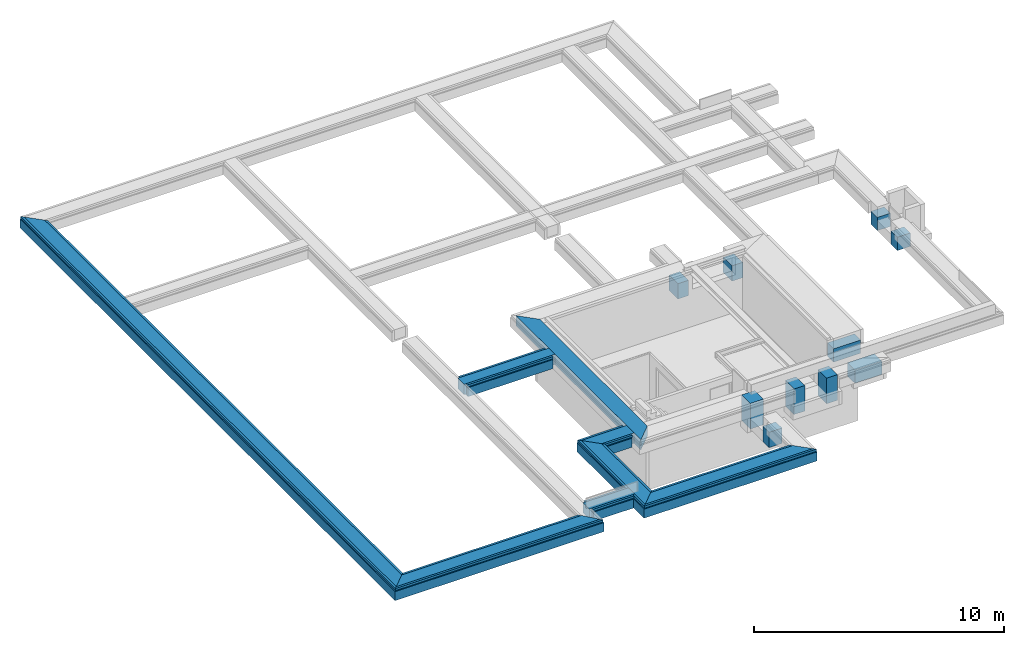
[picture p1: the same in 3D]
Properties of the parts of a building model (IFC2X3), part 4 of 7

# IfcColumn: 80x40x5 80 x 40, 28_Kolom-x
Material Properties - Metaal - Staal C, ThermalConductivity: 52; Metaal - Staal C, SpecificHeatCapacity: 530 J/kg/K; Metaal - Staal C, MassDensity: 7950 kg/m3; Metaal - Staal C, Embodied Energy: 25 (MJ/kg); Metaal - Staal C, Embodied Carbon: 1.91 (kgCO₂/kg); Metaal - Staal C, Name: Metaal - Staal C; Metaal - Staal C, Participates in Collision Detection: yes; Metaal - Staal C, Aardopwarmingsvermogen (GWP): 323.71; Metaal - Staal C, Ozonafbrekend Vermogen (ODP): 0; Metaal - Staal C, Fotochemische Vermogen tot Ozonvorming (POCP): 0.17963; Metaal - Staal C, Verzuringsvermogen (AP): 0.43354; Metaal - Staal C, Eutrofiëringspotentieel (EP): 0.014961; Metaal - Staal C, Abiotisch Uitputtingspotentieel (voor niet fossiele hulpbronnen) (ADPE): 0.00080492; Metaal - Staal C, Abiotisch Uitputtingspotentieel (voor fossiele hulpbronnen) (ADPF): 2862.1; Metaal - Staal C, Databron: https://www.oekobaudat.de/OEKOBAU.DAT/resource/processes/a85fbb4a-60a0-4ba9-9cfa-cdfbe1ec7f00?version=00.01.000

# IfcColumn: ALG - ALGEMEEN 20 x 20 (48)
Type - PredefinedType: COLUMN
Material: ALG - ALGEMEEN
Material Properties - ALG - ALGEMEEN, ThermalConductivity: 0.27; ALG - ALGEMEEN, SpecificHeatCapacity: 840 J/kg/K; ALG - ALGEMEEN, MassDensity: 800 kg/m3; ALG - ALGEMEEN, Embodied Energy: 2 (MJ/kg); ALG - ALGEMEEN, Embodied Carbon: 0.13 (kgCO₂/kg); ALG - ALGEMEEN, Name: ALG - ALGEMEEN; ALG - ALGEMEEN, Participates in Collision Detection: yes; ALG - ALGEMEEN, Handelsgewicht (kg/m): 0; ALG - ALGEMEEN, Soortelijk gewicht (kg/m3): 7850; ALG - ALGEMEEN, Marge materiaal: 1
CPset_Phasing - Renovation Phase: Bestaand
Pset_ColumnCommon - Slope: 90 deg; IsExternal: no; LoadBearing: yes; Reference: ALG - ALGEMEEN 20 x 20
Name | In
18 x 28_Kolom-x | Begane grond
30 x 28_Kolom-x | 1e verdieping

# IfcColumn: HEA100 100 x 96, 28_Kolom-x
In: Begane grond
Type - PredefinedType: COLUMN
Material: Metaal - Staal C
CPset_Phasing - Renovation Phase: Bestaand
Pset_ColumnCommon - Slope: 90 deg; IsExternal: no; LoadBearing: yes; Reference: HEA100 100 x 96
Material Properties - Metaal - Staal C, ThermalConductivity: 52; Metaal - Staal C, SpecificHeatCapacity: 530 J/kg/K; Metaal - Staal C, MassDensity: 7950 kg/m3; Metaal - Staal C, Embodied Energy: 25 (MJ/kg); Metaal - Staal C, Embodied Carbon: 1.91 (kgCO₂/kg); Metaal - Staal C, Name: Metaal - Staal C; Metaal - Staal C, Participates in Collision Detection: yes; Metaal - Staal C, Aardopwarmingsvermogen (GWP): 323.71; Metaal - Staal C, Ozonafbrekend Vermogen (ODP): 0; Metaal - Staal C, Fotochemische Vermogen tot Ozonvorming (POCP): 0.17963; Metaal - Staal C, Verzuringsvermogen (AP): 0.43354; Metaal - Staal C, Eutrofiëringspotentieel (EP): 0.014961; Metaal - Staal C, Abiotisch Uitputtingspotentieel (voor niet fossiele hulpbronnen) (ADPE): 0.00080492; Metaal - Staal C, Abiotisch Uitputtingspotentieel (voor fossiele hulpbronnen) (ADPF): 2862.1; Metaal - Staal C, Databron: https://www.oekobaudat.de/OEKOBAU.DAT/resource/processes/a85fbb4a-60a0-4ba9-9cfa-cdfbe1ec7f00?version=00.01.000

# IfcColumn: HEB140 140 x 140, 28_Kolom-x
In: 1e verdieping
Type - PredefinedType: COLUMN
Material: Metaal - Staal C
Pset_ColumnCommon - Slope: 90 deg; IsExternal: no; LoadBearing: yes; Reference: HEB140 140 x 140
CPset_Phasing - Renovation Phase: Bestaand
Material Properties - Metaal - Staal C, ThermalConductivity: 52; Metaal - Staal C, SpecificHeatCapacity: 530 J/kg/K; Metaal - Staal C, MassDensity: 7950 kg/m3; Metaal - Staal C, Embodied Energy: 25 (MJ/kg); Metaal - Staal C, Embodied Carbon: 1.91 (kgCO₂/kg); Metaal - Staal C, Name: Metaal - Staal C; Metaal - Staal C, Participates in Collision Detection: yes; Metaal - Staal C, Aardopwarmingsvermogen (GWP): 323.71; Metaal - Staal C, Ozonafbrekend Vermogen (ODP): 0; Metaal - Staal C, Fotochemische Vermogen tot Ozonvorming (POCP): 0.17963; Metaal - Staal C, Verzuringsvermogen (AP): 0.43354; Metaal - Staal C, Eutrofiëringspotentieel (EP): 0.014961; Metaal - Staal C, Abiotisch Uitputtingspotentieel (voor niet fossiele hulpbronnen) (ADPE): 0.00080492; Metaal - Staal C, Abiotisch Uitputtingspotentieel (voor fossiele hulpbronnen) (ADPF): 2862.1; Metaal - Staal C, Databron: https://www.oekobaudat.de/OEKOBAU.DAT/resource/processes/a85fbb4a-60a0-4ba9-9cfa-cdfbe1ec7f00?version=00.01.000

# IfcColumn: Hout C 125 x 125 (2)
Type - PredefinedType: COLUMN
Material: Hout C
Pset_ColumnCommon - Slope: 90 deg; IsExternal: no; LoadBearing: yes; Reference: Hout C 125 x 125
CPset_Phasing - Renovation Phase: Bestaand
Material Properties - Hout C, ThermalConductivity: 0.14; Hout C, SpecificHeatCapacity: 1880 J/kg/K; Hout C, MassDensity: 550 kg/m3; Hout C, Embodied Energy: 7.4 (MJ/kg); Hout C, Embodied Carbon: 0.19 (kgCO₂/kg); Hout C, Name: Hout C; Hout C, Participates in Collision Detection: yes; Hout C, Aardopwarmingsvermogen (GWP): -349.478; Hout C, Ozonafbrekend Vermogen (ODP): 0; Hout C, Fotochemische Vermogen tot Ozonvorming (POCP): -0.028; Hout C, Verzuringsvermogen (AP): -0.352; Hout C, Eutrofiëringspotentieel (EP): -0.059; Hout C, Abiotisch Uitputtingspotentieel (voor fossiele hulpbronnen) (ADPF): -3860.46; Hout C, Databron: https://www.oekobaudat.de/OEKOBAU.DAT/resource/processes/07a5482a-fa4a-484d-8929-b6f6dfd6be3e?version=00.00.027
Name | In
28_Kolom-x | Begane grond
28_Kolom-x | 1e verdieping

# IfcColumn: Hout C 80 x 325, 28_Kolom-x
In: 1e verdieping
Type - PredefinedType: COLUMN
Material: Hout C
CPset_Phasing - Renovation Phase: Bestaand
Pset_ColumnCommon - Slope: 90 deg; IsExternal: no; LoadBearing: yes; Reference: Hout C 80 x 325
Material Properties - Hout C, ThermalConductivity: 0.14; Hout C, SpecificHeatCapacity: 1880 J/kg/K; Hout C, MassDensity: 550 kg/m3; Hout C, Embodied Energy: 7.4 (MJ/kg); Hout C, Embodied Carbon: 0.19 (kgCO₂/kg); Hout C, Name: Hout C; Hout C, Participates in Collision Detection: yes; Hout C, Aardopwarmingsvermogen (GWP): -349.478; Hout C, Ozonafbrekend Vermogen (ODP): 0; Hout C, Fotochemische Vermogen tot Ozonvorming (POCP): -0.028; Hout C, Verzuringsvermogen (AP): -0.352; Hout C, Eutrofiëringspotentieel (EP): -0.059; Hout C, Abiotisch Uitputtingspotentieel (voor fossiele hulpbronnen) (ADPF): -3860.46; Hout C, Databron: https://www.oekobaudat.de/OEKOBAU.DAT/resource/processes/07a5482a-fa4a-484d-8929-b6f6dfd6be3e?version=00.00.027

# IfcColumn: IPE200 100 x 200 (5)
In: 1e verdieping
Type - PredefinedType: COLUMN
Material: Metaal - Staal C
Pset_ColumnCommon - Slope: 90 deg; IsExternal: no; LoadBearing: yes; Reference: IPE200 100 x 200
CPset_Phasing - Renovation Phase: Bestaand
Material Properties - Metaal - Staal C, ThermalConductivity: 52; Metaal - Staal C, SpecificHeatCapacity: 530 J/kg/K; Metaal - Staal C, MassDensity: 7950 kg/m3; Metaal - Staal C, Embodied Energy: 25 (MJ/kg); Metaal - Staal C, Embodied Carbon: 1.91 (kgCO₂/kg); Metaal - Staal C, Name: Metaal - Staal C; Metaal - Staal C, Participates in Collision Detection: yes; Metaal - Staal C, Aardopwarmingsvermogen (GWP): 323.71; Metaal - Staal C, Ozonafbrekend Vermogen (ODP): 0; Metaal - Staal C, Fotochemische Vermogen tot Ozonvorming (POCP): 0.17963; Metaal - Staal C, Verzuringsvermogen (AP): 0.43354; Metaal - Staal C, Eutrofiëringspotentieel (EP): 0.014961; Metaal - Staal C, Abiotisch Uitputtingspotentieel (voor niet fossiele hulpbronnen) (ADPE): 0.00080492; Metaal - Staal C, Abiotisch Uitputtingspotentieel (voor fossiele hulpbronnen) (ADPF): 2862.1; Metaal - Staal C, Databron: https://www.oekobaudat.de/OEKOBAU.DAT/resource/processes/a85fbb4a-60a0-4ba9-9cfa-cdfbe1ec7f00?version=00.01.000

# IfcCovering (282)
Name | In | Material | Renovation Phase
5 x Metaal - Aluminium | Begane grond | Metaal - Aluminium | Material Properties - Metaal - Aluminium, ThermalConductivity: 160; Metaal - Aluminium, SpecificHeatCapacity: 880 J/kg/K; Metaal - Aluminium, MassDensity: 2800 kg/m3; Metaal - Aluminium, Embodied Energy: 155 (MJ/kg); Metaal - Aluminium, Embodied Carbon: 9.16 (kgCO₂/kg); Metaal - Aluminium, Name: Metaal - Aluminium; Metaal - Aluminium, Participates in Collision Detection: yes; Metaal - Aluminium, Aardopwarmingsvermogen (GWP): 0.002322; Metaal - Aluminium, Ozonafbrekend Vermogen (ODP): 0; Metaal - Aluminium, Fotochemische Vermogen tot Ozonvorming (POCP): 6.194e-07; Metaal - Aluminium, Verzuringsvermogen (AP): 0.000008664; Metaal - Aluminium, Eutrofiëringspotentieel (EP): 0.00000106; Metaal - Aluminium, Abiotisch Uitputtingspotentieel (voor niet fossiele hulpbronnen) (ADPE): 0; Metaal - Aluminium, Abiotisch Uitputtingspotentieel (voor fossiele hulpbronnen) (ADPF): 0.02659; Metaal - Aluminium, Databron: https://www.oekobaudat.de/OEKOBAU.DAT/resource/processes/c83d501f-d07f-4434-9d5c-862a7e8a3026?version=00.01.000; Metaal - Aluminium, Handelsgewicht (kg/m): 0; Metaal - Aluminium, Soortelijk gewicht (kg/m3): 7850; Metaal - Aluminium, Marge materiaal: 1
12 x Cement - dekvloer | Begane grond | Cement - dekvloer | Bestaand | PredefinedType: FLOORING; Material Properties - Cement - dekvloer, ThermalConductivity: 0.93; Cement - dekvloer, SpecificHeatCapacity: 840 J/kg/K; Cement - dekvloer, MassDensity: 1900 kg/m3; Cement - dekvloer, Embodied Energy: 0.97 (MJ/kg); Cement - dekvloer, Embodied Carbon: 0.146 (kgCO₂/kg); Cement - dekvloer, Name: Cement - dekvloer; Cement - dekvloer, Participates in Collision Detection: yes
15 x Hout - Multiplex Oregon Pine | Begane grond | Hout - Multiplex Oregon Pine | Material Properties - Hout - Multiplex Oregon Pine, ThermalConductivity: 0.17; Hout - Multiplex Oregon Pine, SpecificHeatCapacity: 1600 J/kg/K; Hout - Multiplex Oregon Pine, MassDensity: 700 kg/m3; Hout - Multiplex Oregon Pine, Embodied Energy: 15 (MJ/kg); Hout - Multiplex Oregon Pine, Embodied Carbon: 0.77 (kgCO₂/kg); Hout - Multiplex Oregon Pine, Name: Hout - Multiplex Oregon Pine; Hout - Multiplex Oregon Pine, Participates in Collision Detection: yes; Hout - Multiplex Oregon Pine, Aardopwarmingsvermogen (GWP): -32.4496; Hout - Multiplex Oregon Pine, Ozonafbrekend Vermogen (ODP): 0; Hout - Multiplex Oregon Pine, Fotochemische Vermogen tot Ozonvorming (POCP): -0.00287346; Hout - Multiplex Oregon Pine, Verzuringsvermogen (AP): 0.138611; Hout - Multiplex Oregon Pine, Eutrofiëringspotentieel (EP): 0.0523292; Hout - Multiplex Oregon Pine, Abiotisch Uitputtingspotentieel (voor niet fossiele hulpbronnen) (ADPE): -0.0000777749; Hout - Multiplex Oregon Pine, Abiotisch Uitputtingspotentieel (voor fossiele hulpbronnen) (ADPF): -4006.31; Hout - Multiplex Oregon Pine, Databron: https://www.oekobaudat.de/OEKOBAU.DAT/resource/processes/cc180aec-8a5c-4e07-b1a0-1ab81dd746ac?version=20.20.120
27 x Tegels - Wand | Begane grond | Tegels - Wand | Material Properties - Tegels - Wand, ThermalConductivity: 1.3; Tegels - Wand, SpecificHeatCapacity: 840 J/kg/K; Tegels - Wand, MassDensity: 2300 kg/m3; Tegels - Wand, Embodied Energy: 10 (MJ/kg); Tegels - Wand, Embodied Carbon: 0.7 (kgCO₂/kg); Tegels - Wand, Name: Tegels - Wand; Tegels - Wand, Participates in Collision Detection: yes; Tegels - Wand, Aardopwarmingsvermogen (GWP): 0.109; Tegels - Wand, Ozonafbrekend Vermogen (ODP): 0; Tegels - Wand, Fotochemische Vermogen tot Ozonvorming (POCP): 5.2e-07; Tegels - Wand, Verzuringsvermogen (AP): 0.000011; Tegels - Wand, Eutrofiëringspotentieel (EP): 0.0000024; Tegels - Wand, Abiotisch Uitputtingspotentieel (voor niet fossiele hulpbronnen) (ADPE): 0; Tegels - Wand, Abiotisch Uitputtingspotentieel (voor fossiele hulpbronnen) (ADPF): 0.022; Tegels - Wand, Databron: https://www.oekobaudat.de/OEKOBAU.DAT/resource/processes/a2b5b7c9-db13-4dbd-be23-b0ff9f0cbd98?version=00.08.000
35 x Metaal - Aluminium | Begane grond | Metaal - Aluminium | Bestaand | Material Properties - Metaal - Aluminium, ThermalConductivity: 160; Metaal - Aluminium, SpecificHeatCapacity: 880 J/kg/K; Metaal - Aluminium, MassDensity: 2800 kg/m3; Metaal - Aluminium, Embodied Energy: 155 (MJ/kg); Metaal - Aluminium, Embodied Carbon: 9.16 (kgCO₂/kg); Metaal - Aluminium, Name: Metaal - Aluminium; Metaal - Aluminium, Participates in Collision Detection: yes; Metaal - Aluminium, Aardopwarmingsvermogen (GWP): 0.002322; Metaal - Aluminium, Ozonafbrekend Vermogen (ODP): 0; Metaal - Aluminium, Fotochemische Vermogen tot Ozonvorming (POCP): 6.194e-07; Metaal - Aluminium, Verzuringsvermogen (AP): 0.000008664; Metaal - Aluminium, Eutrofiëringspotentieel (EP): 0.00000106; Metaal - Aluminium, Abiotisch Uitputtingspotentieel (voor niet fossiele hulpbronnen) (ADPE): 0; Metaal - Aluminium, Abiotisch Uitputtingspotentieel (voor fossiele hulpbronnen) (ADPF): 0.02659; Metaal - Aluminium, Databron: https://www.oekobaudat.de/OEKOBAU.DAT/resource/processes/c83d501f-d07f-4434-9d5c-862a7e8a3026?version=00.01.000; Metaal - Aluminium, Handelsgewicht (kg/m): 0; Metaal - Aluminium, Soortelijk gewicht (kg/m3): 7850; Metaal - Aluminium, Marge materiaal: 1
44 x Hout - Vloer | Begane grond | Hout - Vloer | Bestaand | Material Properties - Hout - Vloer, ThermalConductivity: 0.14; Hout - Vloer, SpecificHeatCapacity: 1880 J/kg/K; Hout - Vloer, MassDensity: 550 kg/m3; Hout - Vloer, Embodied Energy: 7.4 (MJ/kg); Hout - Vloer, Embodied Carbon: 0.19 (kgCO₂/kg); Hout - Vloer, Name: Hout - Vloer; Hout - Vloer, Participates in Collision Detection: yes; Hout - Vloer, Aardopwarmingsvermogen (GWP): -305.99; Hout - Vloer, Ozonafbrekend Vermogen (ODP): 0; Hout - Vloer, Fotochemische Vermogen tot Ozonvorming (POCP): -0.0271506; Hout - Vloer, Verzuringsvermogen (AP): -0.34152; Hout - Vloer, Eutrofiëringspotentieel (EP): -0.0577755; Hout - Vloer, Abiotisch Uitputtingspotentieel (voor niet fossiele hulpbronnen) (ADPE): -0.000110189; Hout - Vloer, Abiotisch Uitputtingspotentieel (voor fossiele hulpbronnen) (ADPF): -3837.35; Hout - Vloer, Databron: https://www.oekobaudat.de/OEKOBAU.DAT/resource/processes/7f12b868-0c13-4a5d-bfe7-0f05734cca89?version=00.00.021
21 x Hout - Multiplex | Begane grond | Hout - Multiplex | Bestaand | Material Properties - Hout - Multiplex, ThermalConductivity: 0.17; Hout - Multiplex, SpecificHeatCapacity: 1600 J/kg/K; Hout - Multiplex, MassDensity: 700 kg/m3; Hout - Multiplex, Embodied Energy: 15 (MJ/kg); Hout - Multiplex, Embodied Carbon: 0.77 (kgCO₂/kg); Hout - Multiplex, Name: Hout - Multiplex; Hout - Multiplex, Participates in Collision Detection: yes; Hout - Multiplex, Aardopwarmingsvermogen (GWP): -32.4496; Hout - Multiplex, Ozonafbrekend Vermogen (ODP): 0; Hout - Multiplex, Fotochemische Vermogen tot Ozonvorming (POCP): -0.00287346; Hout - Multiplex, Verzuringsvermogen (AP): 0.138611; Hout - Multiplex, Eutrofiëringspotentieel (EP): 0.0523292; Hout - Multiplex, Abiotisch Uitputtingspotentieel (voor niet fossiele hulpbronnen) (ADPE): -0.0000777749; Hout - Multiplex, Abiotisch Uitputtingspotentieel (voor fossiele hulpbronnen) (ADPF): -4006.31; Hout - Multiplex, Databron: https://www.oekobaudat.de/OEKOBAU.DAT/resource/processes/cc180aec-8a5c-4e07-b1a0-1ab81dd746ac?version=20.20.120
7 x Cement - dekvloer | 1e verdieping | Cement - dekvloer | Bestaand | PredefinedType: FLOORING; Material Properties - Cement - dekvloer, ThermalConductivity: 0.93; Cement - dekvloer, SpecificHeatCapacity: 840 J/kg/K; Cement - dekvloer, MassDensity: 1900 kg/m3; Cement - dekvloer, Embodied Energy: 0.97 (MJ/kg); Cement - dekvloer, Embodied Carbon: 0.146 (kgCO₂/kg); Cement - dekvloer, Name: Cement - dekvloer; Cement - dekvloer, Participates in Collision Detection: yes
12 x Hout - Multiplex Oregon Pine | 1e verdieping | Hout - Multiplex Oregon Pine | Material Properties - Hout - Multiplex Oregon Pine, ThermalConductivity: 0.17; Hout - Multiplex Oregon Pine, SpecificHeatCapacity: 1600 J/kg/K; Hout - Multiplex Oregon Pine, MassDensity: 700 kg/m3; Hout - Multiplex Oregon Pine, Embodied Energy: 15 (MJ/kg); Hout - Multiplex Oregon Pine, Embodied Carbon: 0.77 (kgCO₂/kg); Hout - Multiplex Oregon Pine, Name: Hout - Multiplex Oregon Pine; Hout - Multiplex Oregon Pine, Participates in Collision Detection: yes; Hout - Multiplex Oregon Pine, Aardopwarmingsvermogen (GWP): -32.4496; Hout - Multiplex Oregon Pine, Ozonafbrekend Vermogen (ODP): 0; Hout - Multiplex Oregon Pine, Fotochemische Vermogen tot Ozonvorming (POCP): -0.00287346; Hout - Multiplex Oregon Pine, Verzuringsvermogen (AP): 0.138611; Hout - Multiplex Oregon Pine, Eutrofiëringspotentieel (EP): 0.0523292; Hout - Multiplex Oregon Pine, Abiotisch Uitputtingspotentieel (voor niet fossiele hulpbronnen) (ADPE): -0.0000777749; Hout - Multiplex Oregon Pine, Abiotisch Uitputtingspotentieel (voor fossiele hulpbronnen) (ADPF): -4006.31; Hout - Multiplex Oregon Pine, Databron: https://www.oekobaudat.de/OEKOBAU.DAT/resource/processes/cc180aec-8a5c-4e07-b1a0-1ab81dd746ac?version=20.20.120
5 x Metaal - Aluminium | 1e verdieping | Metaal - Aluminium | Bestaand | Material Properties - Metaal - Aluminium, ThermalConductivity: 160; Metaal - Aluminium, SpecificHeatCapacity: 880 J/kg/K; Metaal - Aluminium, MassDensity: 2800 kg/m3; Metaal - Aluminium, Embodied Energy: 155 (MJ/kg); Metaal - Aluminium, Embodied Carbon: 9.16 (kgCO₂/kg); Metaal - Aluminium, Name: Metaal - Aluminium; Metaal - Aluminium, Participates in Collision Detection: yes; Metaal - Aluminium, Aardopwarmingsvermogen (GWP): 0.002322; Metaal - Aluminium, Ozonafbrekend Vermogen (ODP): 0; Metaal - Aluminium, Fotochemische Vermogen tot Ozonvorming (POCP): 6.194e-07; Metaal - Aluminium, Verzuringsvermogen (AP): 0.000008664; Metaal - Aluminium, Eutrofiëringspotentieel (EP): 0.00000106; Metaal - Aluminium, Abiotisch Uitputtingspotentieel (voor niet fossiele hulpbronnen) (ADPE): 0; Metaal - Aluminium, Abiotisch Uitputtingspotentieel (voor fossiele hulpbronnen) (ADPF): 0.02659; Metaal - Aluminium, Databron: https://www.oekobaudat.de/OEKOBAU.DAT/resource/processes/c83d501f-d07f-4434-9d5c-862a7e8a3026?version=00.01.000; Metaal - Aluminium, Handelsgewicht (kg/m): 0; Metaal - Aluminium, Soortelijk gewicht (kg/m3): 7850; Metaal - Aluminium, Marge materiaal: 1
20 x Hout - Multiplex | 1e verdieping | Hout - Multiplex | Bestaand | Material Properties - Hout - Multiplex, ThermalConductivity: 0.17; Hout - Multiplex, SpecificHeatCapacity: 1600 J/kg/K; Hout - Multiplex, MassDensity: 700 kg/m3; Hout - Multiplex, Embodied Energy: 15 (MJ/kg); Hout - Multiplex, Embodied Carbon: 0.77 (kgCO₂/kg); Hout - Multiplex, Name: Hout - Multiplex; Hout - Multiplex, Participates in Collision Detection: yes; Hout - Multiplex, Aardopwarmingsvermogen (GWP): -32.4496; Hout - Multiplex, Ozonafbrekend Vermogen (ODP): 0; Hout - Multiplex, Fotochemische Vermogen tot Ozonvorming (POCP): -0.00287346; Hout - Multiplex, Verzuringsvermogen (AP): 0.138611; Hout - Multiplex, Eutrofiëringspotentieel (EP): 0.0523292; Hout - Multiplex, Abiotisch Uitputtingspotentieel (voor niet fossiele hulpbronnen) (ADPE): -0.0000777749; Hout - Multiplex, Abiotisch Uitputtingspotentieel (voor fossiele hulpbronnen) (ADPF): -4006.31; Hout - Multiplex, Databron: https://www.oekobaudat.de/OEKOBAU.DAT/resource/processes/cc180aec-8a5c-4e07-b1a0-1ab81dd746ac?version=20.20.120
14 x Tegels - Wand | 1e verdieping | Tegels - Wand | Material Properties - Tegels - Wand, ThermalConductivity: 1.3; Tegels - Wand, SpecificHeatCapacity: 840 J/kg/K; Tegels - Wand, MassDensity: 2300 kg/m3; Tegels - Wand, Embodied Energy: 10 (MJ/kg); Tegels - Wand, Embodied Carbon: 0.7 (kgCO₂/kg); Tegels - Wand, Name: Tegels - Wand; Tegels - Wand, Participates in Collision Detection: yes; Tegels - Wand, Aardopwarmingsvermogen (GWP): 0.109; Tegels - Wand, Ozonafbrekend Vermogen (ODP): 0; Tegels - Wand, Fotochemische Vermogen tot Ozonvorming (POCP): 5.2e-07; Tegels - Wand, Verzuringsvermogen (AP): 0.000011; Tegels - Wand, Eutrofiëringspotentieel (EP): 0.0000024; Tegels - Wand, Abiotisch Uitputtingspotentieel (voor niet fossiele hulpbronnen) (ADPE): 0; Tegels - Wand, Abiotisch Uitputtingspotentieel (voor fossiele hulpbronnen) (ADPF): 0.022; Tegels - Wand, Databron: https://www.oekobaudat.de/OEKOBAU.DAT/resource/processes/a2b5b7c9-db13-4dbd-be23-b0ff9f0cbd98?version=00.08.000
38 x Hout - Vloer | 1e verdieping | Hout - Vloer | Bestaand | Material Properties - Hout - Vloer, ThermalConductivity: 0.14; Hout - Vloer, SpecificHeatCapacity: 1880 J/kg/K; Hout - Vloer, MassDensity: 550 kg/m3; Hout - Vloer, Embodied Energy: 7.4 (MJ/kg); Hout - Vloer, Embodied Carbon: 0.19 (kgCO₂/kg); Hout - Vloer, Name: Hout - Vloer; Hout - Vloer, Participates in Collision Detection: yes; Hout - Vloer, Aardopwarmingsvermogen (GWP): -305.99; Hout - Vloer, Ozonafbrekend Vermogen (ODP): 0; Hout - Vloer, Fotochemische Vermogen tot Ozonvorming (POCP): -0.0271506; Hout - Vloer, Verzuringsvermogen (AP): -0.34152; Hout - Vloer, Eutrofiëringspotentieel (EP): -0.0577755; Hout - Vloer, Abiotisch Uitputtingspotentieel (voor niet fossiele hulpbronnen) (ADPE): -0.000110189; Hout - Vloer, Abiotisch Uitputtingspotentieel (voor fossiele hulpbronnen) (ADPF): -3837.35; Hout - Vloer, Databron: https://www.oekobaudat.de/OEKOBAU.DAT/resource/processes/7f12b868-0c13-4a5d-bfe7-0f05734cca89?version=00.00.021
Metaal - Staal AFW | 1e verdieping | Metaal - Staal AFW | Bestaand | Material Properties - Metaal - Staal AFW, ThermalConductivity: 52; Metaal - Staal AFW, SpecificHeatCapacity: 530 J/kg/K; Metaal - Staal AFW, MassDensity: 7950 kg/m3; Metaal - Staal AFW, Embodied Energy: 25 (MJ/kg); Metaal - Staal AFW, Embodied Carbon: 1.91 (kgCO₂/kg); Metaal - Staal AFW, Name: Metaal - Staal AFW; Metaal - Staal AFW, Participates in Collision Detection: yes; Metaal - Staal AFW, Aardopwarmingsvermogen (GWP): 12.4; Metaal - Staal AFW, Ozonafbrekend Vermogen (ODP): 0; Metaal - Staal AFW, Fotochemische Vermogen tot Ozonvorming (POCP): 0.00443; Metaal - Staal AFW, Verzuringsvermogen (AP): 0.0382; Metaal - Staal AFW, Eutrofiëringspotentieel (EP): 0.00359; Metaal - Staal AFW, Abiotisch Uitputtingspotentieel (voor niet fossiele hulpbronnen) (ADPE): 0.000573; Metaal - Staal AFW, Abiotisch Uitputtingspotentieel (voor fossiele hulpbronnen) (ADPF): 126; Metaal - Staal AFW, Databron: https://www.oekobaudat.de/OEKOBAU.DAT/resource/processes/c3ac069a-6cc4-4d41-a5fc-565615547792?version=00.02.000; Metaal - Staal AFW, Handelsgewicht (kg/m): 0; Metaal - Staal AFW, Soortelijk gewicht (kg/m3): 7850; Metaal - Staal AFW, Marge materiaal: 1
9 x Hout - Spaanplaat | 2e dakoverzicht | Hout - Spaanplaat | Bestaand | Material Properties - Hout - Spaanplaat, ThermalConductivity: 0.14; Hout - Spaanplaat, SpecificHeatCapacity: 1880 J/kg/K; Hout - Spaanplaat, MassDensity: 600 kg/m3; Hout - Spaanplaat, Embodied Energy: 14.5 (MJ/kg); Hout - Spaanplaat, Embodied Carbon: 0.52 (kgCO₂/kg); Hout - Spaanplaat, Name: Hout - Spaanplaat; Hout - Spaanplaat, Participates in Collision Detection: yes; Hout - Spaanplaat, Aardopwarmingsvermogen (GWP): 0.834797; Hout - Spaanplaat, Ozonafbrekend Vermogen (ODP): 0; Hout - Spaanplaat, Fotochemische Vermogen tot Ozonvorming (POCP): 0; Hout - Spaanplaat, Verzuringsvermogen (AP): 0.00349774; Hout - Spaanplaat, Eutrofiëringspotentieel (EP): 0.000879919; Hout - Spaanplaat, Abiotisch Uitputtingspotentieel (voor niet fossiele hulpbronnen) (ADPE): 7.02937e-08; Hout - Spaanplaat, Abiotisch Uitputtingspotentieel (voor fossiele hulpbronnen) (ADPF): 11.5231; Hout - Spaanplaat, Databron: https://www.oekobaudat.de/OEKOBAU.DAT/resource/processes/e7d523b7-36d9-4066-89ee-40a2c276dd8f?version=00.00.020
7 x Hout - Vloer | 2e dakoverzicht | Hout - Vloer | Bestaand | Material Properties - Hout - Vloer, ThermalConductivity: 0.14; Hout - Vloer, SpecificHeatCapacity: 1880 J/kg/K; Hout - Vloer, MassDensity: 550 kg/m3; Hout - Vloer, Embodied Energy: 7.4 (MJ/kg); Hout - Vloer, Embodied Carbon: 0.19 (kgCO₂/kg); Hout - Vloer, Name: Hout - Vloer; Hout - Vloer, Participates in Collision Detection: yes; Hout - Vloer, Aardopwarmingsvermogen (GWP): -305.99; Hout - Vloer, Ozonafbrekend Vermogen (ODP): 0; Hout - Vloer, Fotochemische Vermogen tot Ozonvorming (POCP): -0.0271506; Hout - Vloer, Verzuringsvermogen (AP): -0.34152; Hout - Vloer, Eutrofiëringspotentieel (EP): -0.0577755; Hout - Vloer, Abiotisch Uitputtingspotentieel (voor niet fossiele hulpbronnen) (ADPE): -0.000110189; Hout - Vloer, Abiotisch Uitputtingspotentieel (voor fossiele hulpbronnen) (ADPF): -3837.35; Hout - Vloer, Databron: https://www.oekobaudat.de/OEKOBAU.DAT/resource/processes/7f12b868-0c13-4a5d-bfe7-0f05734cca89?version=00.00.021
9 x Hout - Multiplex | 2e dakoverzicht | Hout - Multiplex | Bestaand | Material Properties - Hout - Multiplex, ThermalConductivity: 0.17; Hout - Multiplex, SpecificHeatCapacity: 1600 J/kg/K; Hout - Multiplex, MassDensity: 700 kg/m3; Hout - Multiplex, Embodied Energy: 15 (MJ/kg); Hout - Multiplex, Embodied Carbon: 0.77 (kgCO₂/kg); Hout - Multiplex, Name: Hout - Multiplex; Hout - Multiplex, Participates in Collision Detection: yes; Hout - Multiplex, Aardopwarmingsvermogen (GWP): -32.4496; Hout - Multiplex, Ozonafbrekend Vermogen (ODP): 0; Hout - Multiplex, Fotochemische Vermogen tot Ozonvorming (POCP): -0.00287346; Hout - Multiplex, Verzuringsvermogen (AP): 0.138611; Hout - Multiplex, Eutrofiëringspotentieel (EP): 0.0523292; Hout - Multiplex, Abiotisch Uitputtingspotentieel (voor niet fossiele hulpbronnen) (ADPE): -0.0000777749; Hout - Multiplex, Abiotisch Uitputtingspotentieel (voor fossiele hulpbronnen) (ADPF): -4006.31; Hout - Multiplex, Databron: https://www.oekobaudat.de/OEKOBAU.DAT/resource/processes/cc180aec-8a5c-4e07-b1a0-1ab81dd746ac?version=20.20.120
Hout - Multiplex Oregon Pine | 2e dakoverzicht | Hout - Multiplex Oregon Pine | Bestaand | Material Properties - Hout - Multiplex Oregon Pine, ThermalConductivity: 0.17; Hout - Multiplex Oregon Pine, SpecificHeatCapacity: 1600 J/kg/K; Hout - Multiplex Oregon Pine, MassDensity: 700 kg/m3; Hout - Multiplex Oregon Pine, Embodied Energy: 15 (MJ/kg); Hout - Multiplex Oregon Pine, Embodied Carbon: 0.77 (kgCO₂/kg); Hout - Multiplex Oregon Pine, Name: Hout - Multiplex Oregon Pine; Hout - Multiplex Oregon Pine, Participates in Collision Detection: yes; Hout - Multiplex Oregon Pine, Aardopwarmingsvermogen (GWP): -32.4496; Hout - Multiplex Oregon Pine, Ozonafbrekend Vermogen (ODP): 0; Hout - Multiplex Oregon Pine, Fotochemische Vermogen tot Ozonvorming (POCP): -0.00287346; Hout - Multiplex Oregon Pine, Verzuringsvermogen (AP): 0.138611; Hout - Multiplex Oregon Pine, Eutrofiëringspotentieel (EP): 0.0523292; Hout - Multiplex Oregon Pine, Abiotisch Uitputtingspotentieel (voor niet fossiele hulpbronnen) (ADPE): -0.0000777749; Hout - Multiplex Oregon Pine, Abiotisch Uitputtingspotentieel (voor fossiele hulpbronnen) (ADPF): -4006.31; Hout - Multiplex Oregon Pine, Databron: https://www.oekobaudat.de/OEKOBAU.DAT/resource/processes/cc180aec-8a5c-4e07-b1a0-1ab81dd746ac?version=20.20.120

# IfcCurtainWall: Curtain Wall Type, 21_Vliesgevel-x
In: 1e verdieping
CPset_Phasing - Renovation Phase: Bestaand
Pset_CurtainWallCommon - Reference: Type vliesgevel; IsExternal: yes

# IfcDoor: D1 26 (6)
Type - OperationType: SINGLE_SWING_LEFT; ParameterTakesPrecedence: no; Sizeable: no
Type - Door Lining Properties - LiningDepth: 139 mm; LiningThickness: 90 mm; LiningOffset: -132 mm
Type - Door Panel Properties - Panel 1 - PanelDepth: 40 mm; PanelOperation: SWINGING; PanelWidth: 1; PanelPosition: MIDDLE
OverallHeight: 2600 mm
Material - Frame / Draaiend deel: Achtergrond; Deurblad: Achtergrond; Onderdorpel: Ongewapend beton; Stofdorpel: Ongewapend beton; Vensterbank: Ongewapend beton; Ventilatierooster: Ongewapend beton; Spouwlat: Ongewapend beton; Rollaag / Latei: Ongewapend beton; Afwerking dagkant buiten: Ongewapend beton; Afwerking dagkant binnen: Ongewapend beton; Zonwering - behuizing: Ongewapend beton; Zonwering - isolatie: Ongewapend beton; Glas: Glas - algemeen
CPset_Phasing - Renovation Phase: Bestaand
Pset_DoorCommon - ThermalTransmittance: 0
Name | In | OverallWidth (mm)
_02.06 | Begane grond | 1130 | Pset_FireRatingProperties - FireResistanceRating: 30 minuten brandwerend en zelfsluitend; Pset_DoorCommon - GlazingAreaFraction: 1.39885
_02.02 | Begane grond | 1080 | Pset_DoorCommon - GlazingAreaFraction: 1.2995
_02.05 | Begane grond | 980
_02.03 | Begane grond | 1080
_02.04 | Begane grond | 1080
_02.04 | 1e verdieping | 1080

# IfcDoor: D1 26, _02.07
In: 1e verdieping
Type - OperationType: SINGLE_SWING_LEFT; ParameterTakesPrecedence: no; Sizeable: no
Type - Door Lining Properties - LiningDepth: 139 mm; LiningThickness: 90 mm; LiningOffset: -37 mm
Type - Door Panel Properties - Panel 1 - PanelDepth: 40 mm; PanelOperation: SWINGING; PanelWidth: 1; PanelPosition: MIDDLE
OverallHeight: 2600 mm; OverallWidth: 1080 mm
Material - Frame / Draaiend deel: Achtergrond; Deurblad: Achtergrond; Onderdorpel: Ongewapend beton; Stofdorpel: Ongewapend beton; Vensterbank: Ongewapend beton; Ventilatierooster: Ongewapend beton; Spouwlat: Ongewapend beton; Rollaag / Latei: Ongewapend beton; Afwerking dagkant buiten: Ongewapend beton; Afwerking dagkant binnen: Ongewapend beton; Zonwering - behuizing: Ongewapend beton; Zonwering - isolatie: Ongewapend beton; Glas: Glas - algemeen
Pset_DoorCommon - ThermalTransmittance: 0
CPset_Phasing - Renovation Phase: Bestaand

# IfcDoor: D1 26 (2)
Type - OperationType: SINGLE_SWING_LEFT; ParameterTakesPrecedence: no; Sizeable: no
Type - Door Lining Properties - LiningDepth: 139 mm; LiningThickness: 90 mm; LiningOffset: -69.5 mm
Type - Door Panel Properties - Panel 1 - PanelDepth: 40 mm; PanelOperation: SWINGING; PanelWidth: 1; PanelPosition: MIDDLE
OverallHeight: 2600 mm; OverallWidth: 1130 mm
Pset_DoorCommon - ThermalTransmittance: 0; GlazingAreaFraction: 1.39885
Material - Frame / Draaiend deel: Achtergrond; Deurblad: Achtergrond; Onderdorpel: Ongewapend beton; Stofdorpel: Ongewapend beton; Vensterbank: Ongewapend beton; Ventilatierooster: Ongewapend beton; Spouwlat: Ongewapend beton; Rollaag / Latei: Ongewapend beton; Afwerking dagkant buiten: Ongewapend beton; Afwerking dagkant binnen: Ongewapend beton; Zonwering - behuizing: Ongewapend beton; Zonwering - isolatie: Ongewapend beton; Glas: Glas - algemeen
CPset_Phasing - Renovation Phase: Bestaand
Name | In
_02.01 | Begane grond
_02.01 | 1e verdieping

# IfcDoor: D1 26 (6)
Type - OperationType: SINGLE_SWING_LEFT; ParameterTakesPrecedence: no; Sizeable: no
Type - Door Lining Properties - LiningDepth: 20 mm; LiningThickness: 20 mm; LiningOffset: -10 mm
Type - Door Panel Properties - Panel 1 - PanelDepth: 20 mm; PanelOperation: SWINGING; PanelWidth: 1; PanelPosition: MIDDLE
OverallHeight: 2320 mm; OverallWidth: 740 mm
Pset_DoorCommon - ThermalTransmittance: 0
Material - Frame / Draaiend deel: Achtergrond; Deurblad: Achtergrond; Onderdorpel: n.v.t.; Stofdorpel: n.v.t.; Vensterbank: n.v.t.; Ventilatierooster: n.v.t.; Spouwlat: n.v.t.; Rollaag / Latei: n.v.t.; Afwerking dagkant buiten: n.v.t.; Afwerking dagkant binnen: n.v.t.; Zonwering - behuizing: n.v.t.; Zonwering - isolatie: n.v.t.; Glas: Glas - algemeen
CPset_Phasing - Renovation Phase: Bestaand
Name | In
2 x _- | Begane grond
4 x _- | 1e verdieping

# IfcDoor: D1 26 (2)
Type - OperationType: SINGLE_SWING_RIGHT; ParameterTakesPrecedence: no; Sizeable: no
Type - Door Lining Properties - LiningDepth: 114 mm; LiningThickness: 67 mm; LiningOffset: -107 mm
Type - Door Panel Properties - Panel 1 - PanelDepth: 40 mm; PanelOperation: SWINGING; PanelWidth: 1; PanelPosition: MIDDLE
Pset_DoorCommon - ThermalTransmittance: 0
Material - Frame / Draaiend deel: Achtergrond; Deurblad: Achtergrond; Onderdorpel: Ongewapend beton; Stofdorpel: Ongewapend beton; Vensterbank: Ongewapend beton; Ventilatierooster: Ongewapend beton; Spouwlat: Ongewapend beton; Rollaag / Latei: Ongewapend beton; Afwerking dagkant buiten: Ongewapend beton; Afwerking dagkant binnen: Ongewapend beton; Zonwering - behuizing: Ongewapend beton; Zonwering - isolatie: Ongewapend beton; Glas: Glas - algemeen
CPset_Phasing - Renovation Phase: Bestaand
Name | In | OverallHeight (mm) | OverallWidth (mm)
_01.07 | Kelder | 2367 | 1034 | Pset_FireRatingProperties - FireResistanceRating: 60 minuten brandwerend en zelfsluitend
_01.08 | 1e verdieping | 2600 | 864.498

# IfcDoor: D1 26 (7)
Type - OperationType: SINGLE_SWING_RIGHT; ParameterTakesPrecedence: no; Sizeable: no
Type - Door Lining Properties - LiningDepth: 139 mm; LiningThickness: 90 mm; LiningOffset: -132 mm
Type - Door Panel Properties - Panel 1 - PanelDepth: 40 mm; PanelOperation: SWINGING; PanelWidth: 1; PanelPosition: MIDDLE
OverallHeight: 2600 mm; OverallWidth: 1080 mm
Material - Frame / Draaiend deel: Achtergrond; Deurblad: Achtergrond; Onderdorpel: Ongewapend beton; Stofdorpel: Ongewapend beton; Vensterbank: Ongewapend beton; Ventilatierooster: Ongewapend beton; Spouwlat: Ongewapend beton; Rollaag / Latei: Ongewapend beton; Afwerking dagkant buiten: Ongewapend beton; Afwerking dagkant binnen: Ongewapend beton; Zonwering - behuizing: Ongewapend beton; Zonwering - isolatie: Ongewapend beton; Glas: Glas - algemeen
Pset_DoorCommon - ThermalTransmittance: 0
CPset_Phasing - Renovation Phase: Bestaand
Name | In
2 x _01.02 | Begane grond | Pset_DoorCommon - GlazingAreaFraction: 1.2995
_01.04 | Begane grond
_01.03 | Begane grond
_01.04 | 1e verdieping
2 x _01.03 | 1e verdieping

# IfcDoor: D1 26, _01.01
In: Begane grond
Type - OperationType: SINGLE_SWING_RIGHT; ParameterTakesPrecedence: no; Sizeable: no
Type - Door Lining Properties - LiningDepth: 139 mm; LiningThickness: 90 mm; LiningOffset: -182 mm
Type - Door Panel Properties - Panel 1 - PanelDepth: 40 mm; PanelOperation: SWINGING; PanelWidth: 1; PanelPosition: MIDDLE
OverallHeight: 2600 mm; OverallWidth: 1130 mm
Material - Frame / Draaiend deel: Achtergrond; Deurblad: Achtergrond; Onderdorpel: Ongewapend beton; Stofdorpel: Ongewapend beton; Vensterbank: Ongewapend beton; Ventilatierooster: Ongewapend beton; Spouwlat: Ongewapend beton; Rollaag / Latei: Ongewapend beton; Afwerking dagkant buiten: Ongewapend beton; Afwerking dagkant binnen: Ongewapend beton; Zonwering - behuizing: Ongewapend beton; Zonwering - isolatie: Ongewapend beton; Glas: Glas - algemeen
Pset_DoorCommon - ThermalTransmittance: 0; GlazingAreaFraction: 1.39885
CPset_Phasing - Renovation Phase: Bestaand

# IfcDoor: D1 26 (19)
Type - OperationType: SINGLE_SWING_RIGHT; ParameterTakesPrecedence: no; Sizeable: no
Type - Door Lining Properties - LiningDepth: 139 mm; LiningThickness: 90 mm; LiningOffset: -69.5 mm
Type - Door Panel Properties - Panel 1 - PanelDepth: 40 mm; PanelOperation: SWINGING; PanelWidth: 1; PanelPosition: MIDDLE
OverallHeight: 2600 mm
Pset_DoorCommon - ThermalTransmittance: 0
Material - Frame / Draaiend deel: Achtergrond; Deurblad: Achtergrond; Onderdorpel: Ongewapend beton; Stofdorpel: Ongewapend beton; Vensterbank: Ongewapend beton; Ventilatierooster: Ongewapend beton; Spouwlat: Ongewapend beton; Rollaag / Latei: Ongewapend beton; Afwerking dagkant buiten: Ongewapend beton; Afwerking dagkant binnen: Ongewapend beton; Zonwering - behuizing: Ongewapend beton; Zonwering - isolatie: Ongewapend beton; Glas: Glas - algemeen
CPset_Phasing - Renovation Phase: Bestaand
Name | In | OverallWidth (mm) | GlazingAreaFraction
3 x _01.02 | Begane grond | 1080 | 1.2995
_01.06 | Begane grond | 1130 | 1.39885 | Pset_FireRatingProperties - FireResistanceRating: 30 minuten brandwerend en zelfsluitend
6 x _01.01 | Begane grond | 1130 | 1.39885
8 x _01.01 | 1e verdieping | 1130 | 1.39885
_01.02 | 1e verdieping | 1080 | 1.2995

# IfcDoor: D1 26 (5)
Type - OperationType: SINGLE_SWING_RIGHT; ParameterTakesPrecedence: no; Sizeable: no
Type - Door Lining Properties - LiningDepth: 139 mm; LiningThickness: 90 mm; LiningOffset: -7 mm
Type - Door Panel Properties - Panel 1 - PanelDepth: 40 mm; PanelOperation: SWINGING; PanelWidth: 1; PanelPosition: MIDDLE
OverallHeight: 2600 mm
Material - Frame / Draaiend deel: Achtergrond; Deurblad: Achtergrond; Onderdorpel: Ongewapend beton; Stofdorpel: Ongewapend beton; Vensterbank: Ongewapend beton; Ventilatierooster: Ongewapend beton; Spouwlat: Ongewapend beton; Rollaag / Latei: Ongewapend beton; Afwerking dagkant buiten: Ongewapend beton; Afwerking dagkant binnen: Ongewapend beton; Zonwering - behuizing: Ongewapend beton; Zonwering - isolatie: Ongewapend beton; Glas: Glas - algemeen
CPset_Phasing - Renovation Phase: Bestaand
Pset_DoorCommon - ThermalTransmittance: 0
Name | In | OverallWidth (mm) | GlazingAreaFraction
_01.02 | Begane grond | 1080 | 1.2995
_01.01 | Begane grond | 1130 | 1.39885
2 x _01.02 | 1e verdieping | 1080 | 1.2995
_01.05 | Begane grond | 930

# IfcDoor: D1 26 (2)
Type - OperationType: SINGLE_SWING_RIGHT; ParameterTakesPrecedence: no; Sizeable: no
Type - Door Lining Properties - LiningDepth: 20 mm; LiningThickness: 20 mm; LiningOffset: -10 mm
Type - Door Panel Properties - Panel 1 - PanelDepth: 20 mm; PanelOperation: SWINGING; PanelWidth: 1; PanelPosition: MIDDLE
OverallHeight: 2320 mm; OverallWidth: 740 mm
Material - Frame / Draaiend deel: Achtergrond; Deurblad: Achtergrond; Onderdorpel: n.v.t.; Stofdorpel: n.v.t.; Vensterbank: n.v.t.; Ventilatierooster: n.v.t.; Spouwlat: n.v.t.; Rollaag / Latei: n.v.t.; Afwerking dagkant buiten: n.v.t.; Afwerking dagkant binnen: n.v.t.; Zonwering - behuizing: n.v.t.; Zonwering - isolatie: n.v.t.; Glas: Glas - algemeen
Pset_DoorCommon - ThermalTransmittance: 0
CPset_Phasing - Renovation Phase: Bestaand
Name | In
_- | Begane grond
_- | 1e verdieping

# IfcDoor: D2 26, _03.06
In: Kelder
Type - OperationType: DOUBLE_DOOR_SINGLE_SWING; ParameterTakesPrecedence: no; Sizeable: no
Type - Door Lining Properties - LiningDepth: 114 mm; LiningThickness: 67 mm; LiningOffset: -107 mm
Type - Door Panel Properties - Panel 1 - PanelDepth: 40 mm; PanelOperation: SWINGING; PanelWidth: 0.510429; PanelPosition: LEFT
Type - Door Panel Properties - Panel 2 - PanelDepth: 40 mm; PanelOperation: SWINGING; PanelWidth: 0.510429; PanelPosition: RIGHT
OverallHeight: 2367 mm; OverallWidth: 1764 mm
Material - Frame / Draaiend deel: Achtergrond; Deurblad: Achtergrond; Onderdorpel: Ongewapend beton; Stofdorpel: Ongewapend beton; Vensterbank: Ongewapend beton; Ventilatierooster: Ongewapend beton; Spouwlat: Ongewapend beton; Rollaag / Latei: Ongewapend beton; Afwerking dagkant buiten: Ongewapend beton; Afwerking dagkant binnen: Ongewapend beton; Zonwering - behuizing: Ongewapend beton; Zonwering - isolatie: Ongewapend beton; Glas: Glas - algemeen
Pset_DoorCommon - ThermalTransmittance: 0
CPset_Phasing - Renovation Phase: Bestaand

# IfcDoor: D2 26, _03.05
In: 1e verdieping
Type - OperationType: DOUBLE_DOOR_SINGLE_SWING; ParameterTakesPrecedence: no; Sizeable: no
Type - Door Lining Properties - LiningDepth: 139 mm; LiningThickness: 90 mm; LiningOffset: -132 mm
Type - Door Panel Properties - Panel 1 - PanelDepth: 40 mm; PanelOperation: SWINGING; PanelWidth: 0.50929; PanelPosition: LEFT
Type - Door Panel Properties - Panel 2 - PanelDepth: 40 mm; PanelOperation: SWINGING; PanelWidth: 0.50929; PanelPosition: RIGHT
OverallHeight: 2600 mm; OverallWidth: 2010 mm
Pset_DoorCommon - FireRating: 30; ThermalTransmittance: 0; GlazingAreaFraction: 2.59105; SelfClosing: yes
Material - Frame / Draaiend deel: Achtergrond; Deurblad: Achtergrond; Onderdorpel: Ongewapend beton; Stofdorpel: Ongewapend beton; Vensterbank: Ongewapend beton; Ventilatierooster: Ongewapend beton; Spouwlat: Ongewapend beton; Rollaag / Latei: Ongewapend beton; Afwerking dagkant buiten: Ongewapend beton; Afwerking dagkant binnen: Ongewapend beton; Zonwering - behuizing: Ongewapend beton; Zonwering - isolatie: Ongewapend beton; Glas: Glas - algemeen
Pset_FireRatingProperties - FireResistanceRating: 30 minuten brandwerend en zelfsluitend
CPset_Phasing - Renovation Phase: Bestaand

# IfcDoor: D2 26, _03.03
In: 1e verdieping
Type - OperationType: DOUBLE_DOOR_SINGLE_SWING; ParameterTakesPrecedence: no; Sizeable: no
Type - Door Lining Properties - LiningDepth: 139 mm; LiningThickness: 90 mm; LiningOffset: -132 mm
Type - Door Panel Properties - Panel 1 - PanelDepth: 40 mm; PanelOperation: SWINGING; PanelWidth: 0.50929; PanelPosition: RIGHT
Type - Door Panel Properties - Panel 2 - PanelDepth: 40 mm; PanelOperation: SWINGING; PanelWidth: 0.50929; PanelPosition: LEFT
OverallHeight: 2600 mm; OverallWidth: 2010 mm
Pset_DoorCommon - ThermalTransmittance: 0
Material - Frame / Draaiend deel: Achtergrond; Deurblad: Achtergrond; Onderdorpel: Ongewapend beton; Stofdorpel: Ongewapend beton; Vensterbank: Ongewapend beton; Ventilatierooster: Ongewapend beton; Spouwlat: Ongewapend beton; Rollaag / Latei: Ongewapend beton; Afwerking dagkant buiten: Ongewapend beton; Afwerking dagkant binnen: Ongewapend beton; Zonwering - behuizing: Ongewapend beton; Zonwering - isolatie: Ongewapend beton; Glas: Glas - algemeen
CPset_Phasing - Renovation Phase: Bestaand

# IfcDoor: D2 26, _03.01
In: Begane grond
Type - OperationType: DOUBLE_DOOR_SINGLE_SWING; ParameterTakesPrecedence: no; Sizeable: no
Type - Door Lining Properties - LiningDepth: 139 mm; LiningThickness: 90 mm; LiningOffset: -132 mm
Type - Door Panel Properties - Panel 1 - PanelDepth: 40 mm; PanelOperation: SWINGING; PanelWidth: 0.510429; PanelPosition: RIGHT
Type - Door Panel Properties - Panel 2 - PanelDepth: 40 mm; PanelOperation: SWINGING; PanelWidth: 0.510429; PanelPosition: LEFT
OverallHeight: 2600 mm; OverallWidth: 1810 mm
Pset_DoorCommon - ThermalTransmittance: 0
Material - Frame / Draaiend deel: Achtergrond; Deurblad: Achtergrond; Onderdorpel: Ongewapend beton; Stofdorpel: Ongewapend beton; Vensterbank: Ongewapend beton; Ventilatierooster: Ongewapend beton; Spouwlat: Ongewapend beton; Rollaag / Latei: Ongewapend beton; Afwerking dagkant buiten: Ongewapend beton; Afwerking dagkant binnen: Ongewapend beton; Zonwering - behuizing: Ongewapend beton; Zonwering - isolatie: Ongewapend beton; Glas: Glas - algemeen
CPset_Phasing - Renovation Phase: Bestaand

# IfcDoor: D2 26 (2)
In: Begane grond
Type - OperationType: DOUBLE_DOOR_SINGLE_SWING; ParameterTakesPrecedence: no; Sizeable: no
Type - Door Lining Properties - LiningDepth: 139 mm; LiningThickness: 90 mm; LiningOffset: -132 mm
Type - Door Panel Properties - Panel 1 - PanelDepth: 40 mm; PanelOperation: SWINGING; PanelWidth: 0.512078; PanelPosition: LEFT
Type - Door Panel Properties - Panel 2 - PanelDepth: 40 mm; PanelOperation: SWINGING; PanelWidth: 0.512078; PanelPosition: RIGHT
OverallHeight: 2600 mm; OverallWidth: 1587.5 mm
Material - Frame / Draaiend deel: Achtergrond; Deurblad: Achtergrond; Onderdorpel: Ongewapend beton; Stofdorpel: Ongewapend beton; Vensterbank: Ongewapend beton; Ventilatierooster: Ongewapend beton; Spouwlat: Ongewapend beton; Rollaag / Latei: Ongewapend beton; Afwerking dagkant buiten: Ongewapend beton; Afwerking dagkant binnen: Ongewapend beton; Zonwering - behuizing: Ongewapend beton; Zonwering - isolatie: Ongewapend beton; Glas: Glas - algemeen
CPset_Phasing - Renovation Phase: Bestaand
Pset_DoorCommon - ThermalTransmittance: 0

# IfcDoor: D2 26, _03.02
In: Begane grond
Type - OperationType: DOUBLE_DOOR_SINGLE_SWING; ParameterTakesPrecedence: no; Sizeable: no
Type - Door Lining Properties - LiningDepth: 139 mm; LiningThickness: 90 mm; LiningOffset: -7 mm
Type - Door Panel Properties - Panel 1 - PanelDepth: 40 mm; PanelOperation: SWINGING; PanelWidth: 0.50929; PanelPosition: LEFT
Type - Door Panel Properties - Panel 2 - PanelDepth: 40 mm; PanelOperation: SWINGING; PanelWidth: 0.50929; PanelPosition: RIGHT
OverallHeight: 2600 mm; OverallWidth: 2010 mm
Pset_DoorCommon - ThermalTransmittance: 0; GlazingAreaFraction: 2.59105
Material - Frame / Draaiend deel: Achtergrond; Deurblad: Achtergrond; Onderdorpel: Ongewapend beton; Stofdorpel: Ongewapend beton; Vensterbank: Ongewapend beton; Ventilatierooster: Ongewapend beton; Spouwlat: Ongewapend beton; Rollaag / Latei: Ongewapend beton; Afwerking dagkant buiten: Ongewapend beton; Afwerking dagkant binnen: Ongewapend beton; Zonwering - behuizing: Ongewapend beton; Zonwering - isolatie: Ongewapend beton; Glas: Glas - algemeen
CPset_Phasing - Renovation Phase: Bestaand

# IfcDoor: D2 26, _03.02
In: Begane grond
Type - OperationType: DOUBLE_DOOR_SINGLE_SWING; ParameterTakesPrecedence: no; Sizeable: no
Type - Door Lining Properties - LiningDepth: 139 mm; LiningThickness: 90 mm; LiningOffset: -7 mm
Type - Door Panel Properties - Panel 1 - PanelDepth: 40 mm; PanelOperation: SWINGING; PanelWidth: 0.50929; PanelPosition: RIGHT
Type - Door Panel Properties - Panel 2 - PanelDepth: 40 mm; PanelOperation: SWINGING; PanelWidth: 0.50929; PanelPosition: LEFT
OverallHeight: 2600 mm; OverallWidth: 2010 mm
Pset_DoorCommon - ThermalTransmittance: 0; GlazingAreaFraction: 2.59105
Material - Frame / Draaiend deel: Achtergrond; Deurblad: Achtergrond; Onderdorpel: Ongewapend beton; Stofdorpel: Ongewapend beton; Vensterbank: Ongewapend beton; Ventilatierooster: Ongewapend beton; Spouwlat: Ongewapend beton; Rollaag / Latei: Ongewapend beton; Afwerking dagkant buiten: Ongewapend beton; Afwerking dagkant binnen: Ongewapend beton; Zonwering - behuizing: Ongewapend beton; Zonwering - isolatie: Ongewapend beton; Glas: Glas - algemeen
CPset_Phasing - Renovation Phase: Bestaand

# IfcDoor: D2 26, _03.02
In: 1e verdieping
Type - OperationType: DOUBLE_DOOR_SINGLE_SWING; ParameterTakesPrecedence: no; Sizeable: no
Type - Door Lining Properties - LiningDepth: 139 mm; LiningThickness: 90 mm; LiningOffset: -72.5 mm
Type - Door Panel Properties - Panel 1 - PanelDepth: 40 mm; PanelOperation: SWINGING; PanelWidth: 0.50929; PanelPosition: LEFT
Type - Door Panel Properties - Panel 2 - PanelDepth: 40 mm; PanelOperation: SWINGING; PanelWidth: 0.50929; PanelPosition: RIGHT
OverallHeight: 2600 mm; OverallWidth: 2010 mm
Pset_DoorCommon - ThermalTransmittance: 0; GlazingAreaFraction: 2.59105
Material - Frame / Draaiend deel: Achtergrond; Deurblad: Achtergrond; Onderdorpel: Ongewapend beton; Stofdorpel: Ongewapend beton; Vensterbank: Ongewapend beton; Ventilatierooster: Ongewapend beton; Spouwlat: Ongewapend beton; Rollaag / Latei: Ongewapend beton; Afwerking dagkant buiten: Ongewapend beton; Afwerking dagkant binnen: Ongewapend beton; Zonwering - behuizing: Ongewapend beton; Zonwering - isolatie: Ongewapend beton; Glas: Glas - algemeen
CPset_Phasing - Renovation Phase: Bestaand

# IfcDoor: D2 26, _03.01
In: 1e verdieping
Type - OperationType: DOUBLE_DOOR_SINGLE_SWING; ParameterTakesPrecedence: no; Sizeable: no
Type - Door Lining Properties - LiningDepth: 139 mm; LiningThickness: 90 mm; LiningOffset: 3 mm
Type - Door Panel Properties - Panel 1 - PanelDepth: 40 mm; PanelOperation: SWINGING; PanelWidth: 0.510429; PanelPosition: LEFT
Type - Door Panel Properties - Panel 2 - PanelDepth: 40 mm; PanelOperation: SWINGING; PanelWidth: 0.510429; PanelPosition: RIGHT
OverallHeight: 2600 mm; OverallWidth: 1810 mm
CPset_Phasing - Renovation Phase: Bestaand
Material - Frame / Draaiend deel: Achtergrond; Deurblad: Achtergrond; Onderdorpel: Ongewapend beton; Stofdorpel: Ongewapend beton; Vensterbank: Ongewapend beton; Ventilatierooster: Ongewapend beton; Spouwlat: Ongewapend beton; Rollaag / Latei: Ongewapend beton; Afwerking dagkant buiten: Ongewapend beton; Afwerking dagkant binnen: Ongewapend beton; Zonwering - behuizing: Ongewapend beton; Zonwering - isolatie: Ongewapend beton; Glas: Glas - algemeen
Pset_DoorCommon - ThermalTransmittance: 0

# IfcDoor: DS1 voor wand 26 (2)
In: Begane grond
Type - OperationType: SLIDING_TO_LEFT; ParameterTakesPrecedence: no; Sizeable: no
Type - Door Panel Properties - Panel 1 - PanelDepth: 105 mm; PanelOperation: SLIDING; PanelWidth: 1; PanelPosition: MIDDLE
OverallHeight: 2600 mm; OverallWidth: 3250 mm
Material - Frame / Draaiend deel: Loofhout (01); Deurblad: n.v.t.; Onderdorpel: n.v.t.; Stofdorpel: n.v.t.; Vensterbank: n.v.t.; Spouwlat: n.v.t.; Rollaag / Latei: n.v.t.; Afwerking dagkant buiten: n.v.t.; Afwerking dagkant binnen: n.v.t.; Zonwering - behuizing: n.v.t.; Zonwering - isolatie: n.v.t.; Glas: Glas - algemeen
Pset_DoorCommon - ThermalTransmittance: 0; GlazingAreaFraction: 4.845
CPset_Phasing - Renovation Phase: Bestaand
Pset_ManufacturerTypeInformation - Manufacturer: Breedveld SL110gl

# IfcDoor: DS1 voor wand 26 (2)
In: Begane grond
Type - OperationType: SLIDING_TO_RIGHT; ParameterTakesPrecedence: no; Sizeable: no
Type - Door Panel Properties - Panel 1 - PanelDepth: 105 mm; PanelOperation: SLIDING; PanelWidth: 1; PanelPosition: MIDDLE
OverallHeight: 2600 mm; OverallWidth: 3250 mm
Pset_DoorCommon - ThermalTransmittance: 0; GlazingAreaFraction: 4.845
Material - Frame / Draaiend deel: Loofhout (01); Deurblad: n.v.t.; Onderdorpel: n.v.t.; Stofdorpel: n.v.t.; Vensterbank: n.v.t.; Spouwlat: n.v.t.; Rollaag / Latei: n.v.t.; Afwerking dagkant buiten: n.v.t.; Afwerking dagkant binnen: n.v.t.; Zonwering - behuizing: n.v.t.; Zonwering - isolatie: n.v.t.; Glas: Glas - algemeen
Pset_ManufacturerTypeInformation - Manufacturer: Breedveld SL110gl
CPset_Phasing - Renovation Phase: Bestaand

# IfcDoor: R1 26 (69)
Type - OperationType: SINGLE_SWING_RIGHT; ParameterTakesPrecedence: no; Sizeable: no
Pset_DoorCommon - ThermalTransmittance: 0; IsExternal: yes
Material - Frame / Draaiend deel: n.v.t.; Onderdorpel: n.v.t.; Vensterbank: n.v.t.; Ventilatierooster: n.v.t.; Spouwlat: n.v.t.; Rollaag / Latei: n.v.t.; Afwerking dagkant buiten: n.v.t.; Afwerking dagkant binnen: n.v.t.; Zonwering - behuizing: n.v.t.; Zonwering - isolatie: n.v.t.; Glas: Glas - algemeen
CPset_Phasing - Renovation Phase: Bestaand
Name | In | OverallHeight (mm) | OverallWidth (mm) | GlazingAreaFraction
_B.17 | Begane grond | 2600 | 1006 | 2.47296
4 x _B.01 | Begane grond | 2600 | 1200 | 2.9696
2 x _B.13 | Begane grond | 2600 | 499.976 | 1.17754
_B.14 | Begane grond | 2600 | 334 | 0.75264
_C.06 | Begane grond | 1400 | 1810 | 2.4072
2 x _C.02 | Begane grond | 1400 | 1900 | 2.5296
2 x _B.05 | Begane grond | 2600 | 600 | 1.4336
_B.15 | Begane grond | 2600 | 315 | 0.703999
2 x _C.03 | Begane grond | 1400 | 1010 | 1.3192
_C.04 | Begane grond | 1400 | 774.999 | 0.999599
_C.07 | Begane grond | 1400 | 600 | 0.7616
2 x _B.02 | Begane grond | 2600 | 900 | 2.2016
2 x _B.04 | Begane grond | 2600 | 630 | 1.5104
2 x _B.07 | Begane grond | 2600 | 680 | 1.6384
_B.11 | Begane grond | 2600 | 625 | 1.4976
_B.03 | Begane grond | 2600 | 1220 | 3.0208
2 x _B.06 | Begane grond | 2600 | 1050 | 2.5856
4 x _C.01 | Begane grond | 1400 | 2100 | 2.8016
_B.09 | Begane grond | 2600 | 656.001 | 1.57696
_B.16 | Begane grond | 2600 | 301 | 0.66816
_C.04 | Begane grond | 1400 | 775 | 0.999599
_F.01 | 1e verdieping | 2600 | 600 | 1.4336
3 x _B.02 | 1e verdieping | 2600 | 900 | 2.2016
2 x _C.02 | 1e verdieping | 1400 | 1900 | 2.5296
2 x _B.08 | 1e verdieping | 2600 | 770 | 1.8688
2 x _B.07 | 1e verdieping | 2600 | 680 | 1.6384
_C.05 | 1e verdieping | 1400 | 1810 | 2.4072
3 x _B.01 | 1e verdieping | 2600 | 1200 | 2.9696
_B.10 | 1e verdieping | 2600 | 671.001 | 1.61536
_C.09 | 1e verdieping | 1400 | 220 | 0.2448
3 x _D.01 | 1e verdieping | 900 | 2130 | 1.7974
_D.03 | 1e verdieping | 900 | 1740.01 | 1.46201
_B.12 | 1e verdieping | 2600 | 515 | 1.216
_D.05 | 1e verdieping | 900 | 1215 | 1.0105
_D.04 | 1e verdieping | 900 | 1440.01 | 1.20401
2 x _D.02 | 1e verdieping | 900 | 1430 | 1.1954
_A.05 | 1e verdieping | 2600 | 860 | 2.0655 | Pset_DoorCommon - FireRating: 30; Pset_FireRatingProperties - FireResistanceRating: 30 minuten brandwerend
2 x _B.06 | 1e verdieping | 2600 | 1050 | 2.5856
_B.03 | 1e verdieping | 2600 | 1220 | 3.0208
4 x _C.01 | 1e verdieping | 1400 | 2100 | 2.8016
_B.09 | 1e verdieping | 2600 | 656.001 | 1.57696

# IfcDoor: Rnx horizontaal 26, _A.01a
In: 1e verdieping
Type - OperationType: DOUBLE_DOOR_SINGLE_SWING; ParameterTakesPrecedence: no; Sizeable: no
OverallHeight: 1400 mm; OverallWidth: 2120 mm
CPset_Phasing - Renovation Phase: Bestaand
Material - Frame / Draaiend deel: n.v.t.; Onderdorpel: n.v.t.; Vensterbank: n.v.t.; Ventilatierooster: n.v.t.; Spouwlat: n.v.t.; Rollaag / Latei: n.v.t.; Afwerking dagkant buiten: n.v.t.; Afwerking dagkant binnen: n.v.t.; Zonwering - behuizing: n.v.t.; Zonwering - isolatie: n.v.t.; Glas: Glas - algemeen
Pset_FireRatingProperties - FireResistanceRating: 30 minuten brandwerend
Pset_DoorCommon - FireRating: 30; ThermalTransmittance: 0; GlazingAreaFraction: 2.7405; IsExternal: yes

# IfcDoor: Rnx horizontaal 26 (2)
In: 1e verdieping
Type - OperationType: REVOLVING; ParameterTakesPrecedence: no; Sizeable: no
OverallHeight: 1400 mm
Pset_DoorCommon - FireRating: 30; ThermalTransmittance: 0; IsExternal: yes
Pset_FireRatingProperties - FireResistanceRating: 30 minuten brandwerend
CPset_Phasing - Renovation Phase: Bestaand
Material - Frame / Draaiend deel: n.v.t.; Onderdorpel: n.v.t.; Vensterbank: n.v.t.; Ventilatierooster: n.v.t.; Spouwlat: n.v.t.; Rollaag / Latei: n.v.t.; Afwerking dagkant buiten: n.v.t.; Afwerking dagkant binnen: n.v.t.; Zonwering - behuizing: n.v.t.; Zonwering - isolatie: n.v.t.; Glas: Glas - algemeen
Name | OverallWidth (mm) | GlazingAreaFraction
_A.01b | 4015 | 5.19075
_A.02 | 7824.95 | 10.1722

# IfcDoor: Rnx horizontaal 26, _A.04
In: 1e verdieping
Type - OperationType: SINGLE_SWING_RIGHT; ParameterTakesPrecedence: no; Sizeable: no
OverallHeight: 2240 mm; OverallWidth: 3345 mm
Pset_DoorCommon - FireRating: 30; ThermalTransmittance: 0; GlazingAreaFraction: 6.1491; IsExternal: yes
Material - Frame / Draaiend deel: n.v.t.; Onderdorpel: n.v.t.; Vensterbank: n.v.t.; Ventilatierooster: n.v.t.; Spouwlat: n.v.t.; Rollaag / Latei: n.v.t.; Afwerking dagkant buiten: n.v.t.; Afwerking dagkant binnen: n.v.t.; Zonwering - behuizing: n.v.t.; Zonwering - isolatie: n.v.t.; Glas: Glas - algemeen
Pset_FireRatingProperties - FireResistanceRating: 30 minuten brandwerend
CPset_Phasing - Renovation Phase: Bestaand

# IfcFlowStorageDevice: Gootsteen 02 26 (4)
Type - PredefinedType: EXPANSION
CPset_Phasing - Renovation Phase: Bestaand
Name | In
2 x 56_Object-x | Begane grond
2 x 56_Object-x | 1e verdieping

# IfcFlowStorageDevice: Invalidentoilet 26, 56_Leeg
In: Begane grond
Type - PredefinedType: EXPANSION
CPset_Phasing - Renovation Phase: Bestaand

# IfcFlowStorageDevice: Kraan wand 26 (6)
Type - PredefinedType: EXPANSION
CPset_Phasing - Renovation Phase: Bestaand
Name | In
2 x 56_Leeg | Begane grond
4 x 56_Leeg | 1e verdieping

# IfcFlowStorageDevice: Toilet 26 (14)
Type - PredefinedType: EXPANSION
CPset_Phasing - Renovation Phase: Bestaand
Name | In
8 x 56_Leeg | Begane grond
6 x 56_Leeg | 1e verdieping

# IfcFlowStorageDevice: Wasbak 26 (8)
Type - PredefinedType: EXPANSION
CPset_Phasing - Renovation Phase: Bestaand
Name | In
5 x 56_Object-x | Begane grond
3 x 56_Object-x | 1e verdieping

# IfcFlowTerminal: Rooster wand rechthoekig 26, 57_Object-x
In: Kelder
Type - PredefinedType: GRILLE
CPset_Phasing - Renovation Phase: Bestaand

# IfcFurnishingElement: 43 Forbo Striato 0, 72_43 marmoleum
In: 1e verdieping
Type - ElementType: SHELF
Material: 43 Forbo Striato
CPset_Phasing - Renovation Phase: Bestaand
Material Properties - 43 Forbo Striato, ThermalConductivity: 2.3; 43 Forbo Striato, SpecificHeatCapacity: 1000 J/kg/K; 43 Forbo Striato, MassDensity: 2300 kg/m3; 43 Forbo Striato, Embodied Energy: 1.92 (MJ/kg); 43 Forbo Striato, Embodied Carbon: 0.198 (kgCO₂/kg); 43 Forbo Striato, Name: 43 Forbo Striato; 43 Forbo Striato, Participates in Collision Detection: yes

# IfcFurnishingElement: 43 Forbo Striato 2 (5)
Type - ElementType: SHELF
Material: 43 Forbo Striato
CPset_Phasing - Renovation Phase: Bestaand
Material Properties - 43 Forbo Striato, ThermalConductivity: 2.3; 43 Forbo Striato, SpecificHeatCapacity: 1000 J/kg/K; 43 Forbo Striato, MassDensity: 2300 kg/m3; 43 Forbo Striato, Embodied Energy: 1.92 (MJ/kg); 43 Forbo Striato, Embodied Carbon: 0.198 (kgCO₂/kg); 43 Forbo Striato, Name: 43 Forbo Striato; 43 Forbo Striato, Participates in Collision Detection: yes
Name | In
3 x 72_43 marmoleum | Begane grond
2 x 72_43 marmoleum | 1e verdieping

# IfcFurnishingElement: 43 Forbo Walton 2 (22)
Type - ElementType: SHELF
Material: 43 Forbo Walton
CPset_Phasing - Renovation Phase: Bestaand
Material Properties - 43 Forbo Walton, ThermalConductivity: 2.3; 43 Forbo Walton, SpecificHeatCapacity: 1000 J/kg/K; 43 Forbo Walton, MassDensity: 2300 kg/m3; 43 Forbo Walton, Embodied Energy: 1.92 (MJ/kg); 43 Forbo Walton, Embodied Carbon: 0.198 (kgCO₂/kg); 43 Forbo Walton, Name: 43 Forbo Walton; 43 Forbo Walton, Participates in Collision Detection: yes
Name | In
9 x 72_43 marmoleum | Begane grond
72_44 marmoleum | Begane grond
8 x 72_43 marmoleum | 1e verdieping
3 x 72_44 marmoleum | 1e verdieping
72_45 marmoleum | 1e verdieping

# IfcFurnishingElement: 48 vloeivloer Bolidt 2 (13)
Type - ElementType: SHELF
Material: 48 vloeivloer Bolidt
CPset_Phasing - Renovation Phase: Bestaand
Material Properties - 48 vloeivloer Bolidt, ThermalConductivity: 0.17; 48 vloeivloer Bolidt, SpecificHeatCapacity: 900 J/kg/K; 48 vloeivloer Bolidt, MassDensity: 1390 kg/m3; 48 vloeivloer Bolidt, Embodied Energy: 77.2 (MJ/kg); 48 vloeivloer Bolidt, Embodied Carbon: 3.1 (kgCO₂/kg); 48 vloeivloer Bolidt, Name: 48 vloeivloer Bolidt; 48 vloeivloer Bolidt, Participates in Collision Detection: yes; 48 vloeivloer Bolidt, Handelsgewicht (kg/m): 0; 48 vloeivloer Bolidt, Soortelijk gewicht (kg/m3): 7850; 48 vloeivloer Bolidt, Marge materiaal: 1
Name | In
2 x 72_44 vloeivloer | Begane grond
2 x 72_43 vloeivloer | Begane grond
2 x 72_47 vloeivloer | Begane grond
72_45 vloeivloer | Begane grond
72_46 vloeivloer | Begane grond
2 x 72_46 vloeivloer | 1e verdieping
72_43 vloeivloer | 1e verdieping
72_45 vloeivloer | 1e verdieping
72_47 vloeivloer | 1e verdieping

# IfcFurnishingElement: Beton gewapend C vloer 300 (2)
In: Kelder
Type - ElementType: SHELF
Material: Beton gewapend C vloer
Material Properties - Beton gewapend C vloer, ThermalConductivity: 2.5; Beton gewapend C vloer, SpecificHeatCapacity: 1000 J/kg/K; Beton gewapend C vloer, MassDensity: 2400 kg/m3; Beton gewapend C vloer, Embodied Energy: 2.33 (MJ/kg); Beton gewapend C vloer, Embodied Carbon: 0.242 (kgCO₂/kg); Beton gewapend C vloer, Name: Beton gewapend C vloer; Beton gewapend C vloer, Participates in Collision Detection: yes
CPset_Phasing - Renovation Phase: Bestaand

# IfcFurnishingElement: Beton gewapend C vloer 50, 72_
In: Kelder
Type - ElementType: SHELF
Material: Beton gewapend C vloer
CPset_Phasing - Renovation Phase: Bestaand
Material Properties - Beton gewapend C vloer, ThermalConductivity: 2.5; Beton gewapend C vloer, SpecificHeatCapacity: 1000 J/kg/K; Beton gewapend C vloer, MassDensity: 2400 kg/m3; Beton gewapend C vloer, Embodied Energy: 2.33 (MJ/kg); Beton gewapend C vloer, Embodied Carbon: 0.242 (kgCO₂/kg); Beton gewapend C vloer, Name: Beton gewapend C vloer; Beton gewapend C vloer, Participates in Collision Detection: yes

# IfcFurnishingElement: Beton gewapend prefab 250, 72_
In: Kelder
Type - ElementType: SHELF
Material: Beton gewapend prefab
CPset_Phasing - Renovation Phase: Bestaand
Material Properties - Beton gewapend prefab, ThermalConductivity: 2.5; Beton gewapend prefab, SpecificHeatCapacity: 1000 J/kg/K; Beton gewapend prefab, MassDensity: 2400 kg/m3; Beton gewapend prefab, Embodied Energy: 2.33 (MJ/kg); Beton gewapend prefab, Embodied Carbon: 0.242 (kgCO₂/kg); Beton gewapend prefab, Name: Beton gewapend prefab; Beton gewapend prefab, Participates in Collision Detection: yes; Beton gewapend prefab, Aardopwarmingsvermogen (GWP): 129.993; Beton gewapend prefab, Ozonafbrekend Vermogen (ODP): 0; Beton gewapend prefab, Fotochemische Vermogen tot Ozonvorming (POCP): 0.00471246; Beton gewapend prefab, Verzuringsvermogen (AP): 0.182012; Beton gewapend prefab, Eutrofiëringspotentieel (EP): 0.0346685; Beton gewapend prefab, Abiotisch Uitputtingspotentieel (voor niet fossiele hulpbronnen) (ADPE): 0.000140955; Beton gewapend prefab, Abiotisch Uitputtingspotentieel (voor fossiele hulpbronnen) (ADPF): 604.803; Beton gewapend prefab, Databron: https://www.oekobaudat.de/OEKOBAU.DAT/resource/processes/3470c523-ffcd-48df-93ff-dedfde86572a?version=20.19.010

# IfcFurnishingElement: Grind 150, 72_
In: Kelder
Type - ElementType: SHELF
Material: Grind
CPset_Phasing - Renovation Phase: Bestaand
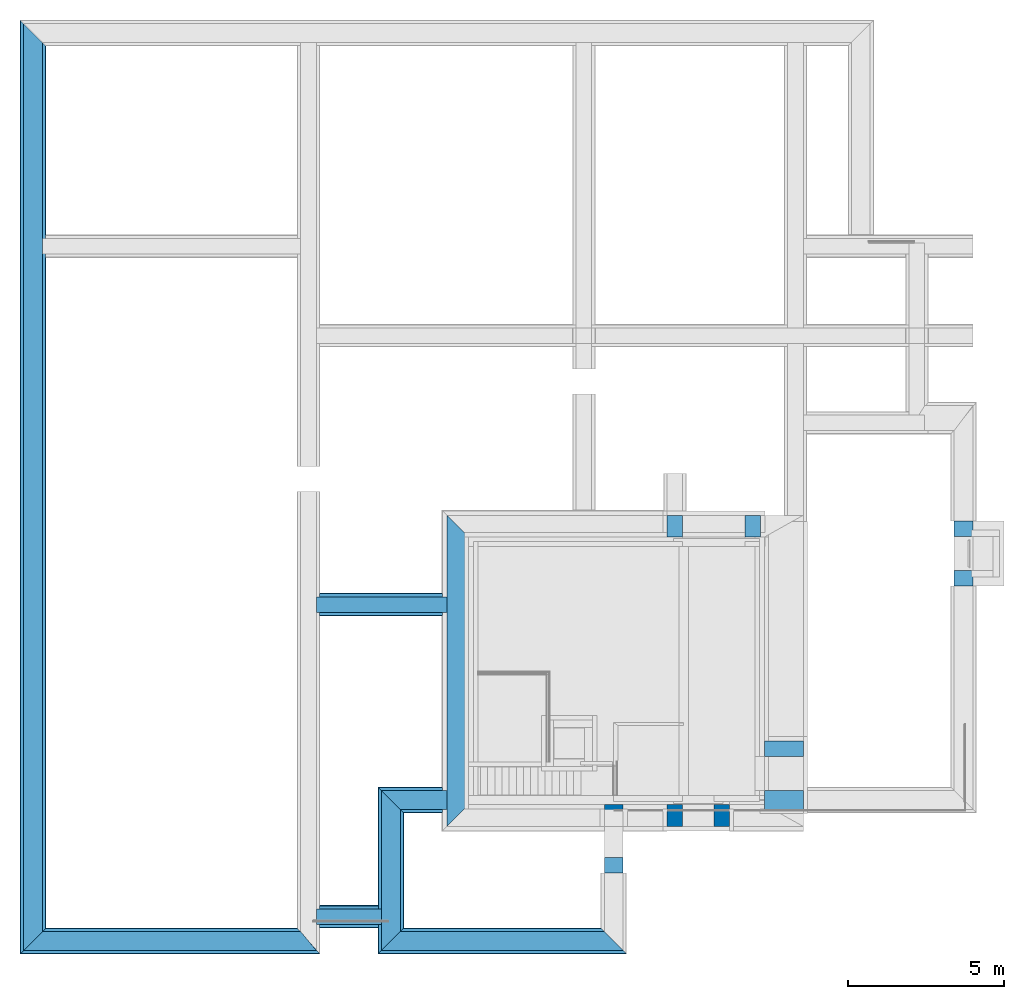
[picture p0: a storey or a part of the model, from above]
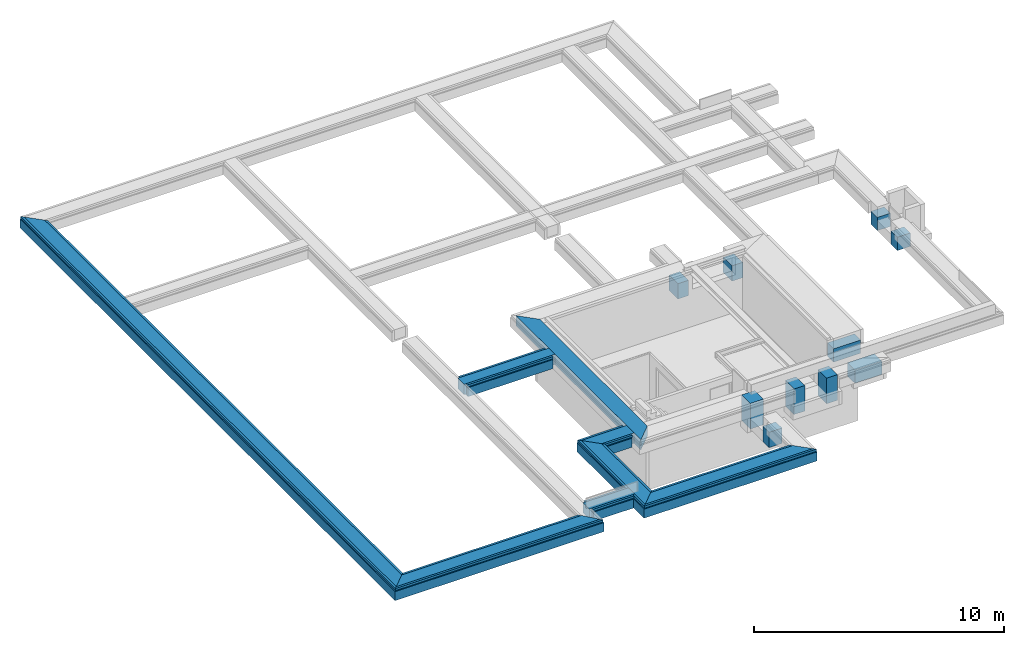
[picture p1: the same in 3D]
Properties of the parts of a building model (IFC2X3), part 5 of 7

# IfcFurnishingElement: Grind 150, 72_
Material Properties - Grind, ThermalConductivity: 1.4; Grind, SpecificHeatCapacity: 1000 J/kg/K; Grind, MassDensity: 1800 kg/m3; Grind, Embodied Energy: 0.083 (MJ/kg); Grind, Embodied Carbon: 0.0048 (kgCO₂/kg); Grind, Name: Grind; Grind, Participates in Collision Detection: yes

# IfcFurnishingElement: Isolatie - Kunststof hard 140 (7)
In: Kelder
Type - ElementType: SHELF
Material: Isolatie - Kunststof hard
Material Properties - Isolatie - Kunststof hard, ThermalConductivity: 0.029; Isolatie - Kunststof hard, SpecificHeatCapacity: 1470 J/kg/K; Isolatie - Kunststof hard, MassDensity: 100 kg/m3; Isolatie - Kunststof hard, Embodied Energy: 101.5 (MJ/kg); Isolatie - Kunststof hard, Embodied Carbon: 3.48 (kgCO₂/kg); Isolatie - Kunststof hard, Name: Isolatie - Kunststof hard; Isolatie - Kunststof hard, Participates in Collision Detection: yes; Isolatie - Kunststof hard, Aardopwarmingsvermogen (GWP): 0.04; Isolatie - Kunststof hard, Ozonafbrekend Vermogen (ODP): 0; Isolatie - Kunststof hard, Fotochemische Vermogen tot Ozonvorming (POCP): 0; Isolatie - Kunststof hard, Verzuringsvermogen (AP): 0.0000975; Isolatie - Kunststof hard, Eutrofiëringspotentieel (EP): 0.0000237; Isolatie - Kunststof hard, Abiotisch Uitputtingspotentieel (voor niet fossiele hulpbronnen) (ADPE): 0; Isolatie - Kunststof hard, Abiotisch Uitputtingspotentieel (voor fossiele hulpbronnen) (ADPF): 0.47; Isolatie - Kunststof hard, Databron: https://www.oekobaudat.de/OEKOBAU.DAT/resource/processes/41e09ab7-0e73-4303-84fd-97cb0809db02?version=00.04.000
CPset_Phasing - Renovation Phase: Bestaand

# IfcFurnishingElement: Vloerafwerking - schoonloopzone 1 25 (10)
Type - ElementType: SHELF
Material: Vloerafwerking - schoonloopzone 1
CPset_Phasing - Renovation Phase: Bestaand
Material Properties - Vloerafwerking - schoonloopzone 1, ThermalConductivity: 2.3; Vloerafwerking - schoonloopzone 1, SpecificHeatCapacity: 1000 J/kg/K; Vloerafwerking - schoonloopzone 1, MassDensity: 2300 kg/m3; Vloerafwerking - schoonloopzone 1, Embodied Energy: 1.92 (MJ/kg); Vloerafwerking - schoonloopzone 1, Embodied Carbon: 0.198 (kgCO₂/kg); Vloerafwerking - schoonloopzone 1, Name: Vloerafwerking - schoonloopzone 1; Vloerafwerking - schoonloopzone 1, Participates in Collision Detection: yes
Name | In
8 x 72_43 schoonloop zone 1 | Begane grond
2 x 72_43 schoonloop zone 1 | 1e verdieping

# IfcFurnishingElement: Vloerafwerking - schoonloopzone 3 10, 72_43 marmoleum
In: Begane grond
Type - ElementType: SHELF
Material: Vloerafwerking - schoonloopzone 3
CPset_Phasing - Renovation Phase: Bestaand
Material Properties - Vloerafwerking - schoonloopzone 3, ThermalConductivity: 2.3; Vloerafwerking - schoonloopzone 3, SpecificHeatCapacity: 1000 J/kg/K; Vloerafwerking - schoonloopzone 3, MassDensity: 2300 kg/m3; Vloerafwerking - schoonloopzone 3, Embodied Energy: 1.92 (MJ/kg); Vloerafwerking - schoonloopzone 3, Embodied Carbon: 0.198 (kgCO₂/kg); Vloerafwerking - schoonloopzone 3, Name: Vloerafwerking - schoonloopzone 3; Vloerafwerking - schoonloopzone 3, Participates in Collision Detection: yes

# IfcMember: 50 x 313 (7)
In: 1e verdieping
Type - PredefinedType: MULLION
Material: Metaal - Staal AFW
Pset_MemberCommon - Slope: 90 deg
CPset_Phasing - Renovation Phase: Bestaand
Material Properties - Metaal - Staal AFW, ThermalConductivity: 52; Metaal - Staal AFW, SpecificHeatCapacity: 530 J/kg/K; Metaal - Staal AFW, MassDensity: 7950 kg/m3; Metaal - Staal AFW, Embodied Energy: 25 (MJ/kg); Metaal - Staal AFW, Embodied Carbon: 1.91 (kgCO₂/kg); Metaal - Staal AFW, Name: Metaal - Staal AFW; Metaal - Staal AFW, Participates in Collision Detection: yes; Metaal - Staal AFW, Aardopwarmingsvermogen (GWP): 12.4; Metaal - Staal AFW, Ozonafbrekend Vermogen (ODP): 0; Metaal - Staal AFW, Fotochemische Vermogen tot Ozonvorming (POCP): 0.00443; Metaal - Staal AFW, Verzuringsvermogen (AP): 0.0382; Metaal - Staal AFW, Eutrofiëringspotentieel (EP): 0.00359; Metaal - Staal AFW, Abiotisch Uitputtingspotentieel (voor niet fossiele hulpbronnen) (ADPE): 0.000573; Metaal - Staal AFW, Abiotisch Uitputtingspotentieel (voor fossiele hulpbronnen) (ADPF): 126; Metaal - Staal AFW, Databron: https://www.oekobaudat.de/OEKOBAU.DAT/resource/processes/c3ac069a-6cc4-4d41-a5fc-565615547792?version=00.02.000; Metaal - Staal AFW, Handelsgewicht (kg/m): 0; Metaal - Staal AFW, Soortelijk gewicht (kg/m3): 7850; Metaal - Staal AFW, Marge materiaal: 1
Name
6 x _Kader-x
h METAAL_Kader-x

# IfcMember: Boundary Frame 50 x 313 (62)
In: 1e verdieping
Type - PredefinedType: MULLION
Material: Metaal - Staal AFW
CPset_Phasing - Renovation Phase: Bestaand
Material Properties - Metaal - Staal AFW, ThermalConductivity: 52; Metaal - Staal AFW, SpecificHeatCapacity: 530 J/kg/K; Metaal - Staal AFW, MassDensity: 7950 kg/m3; Metaal - Staal AFW, Embodied Energy: 25 (MJ/kg); Metaal - Staal AFW, Embodied Carbon: 1.91 (kgCO₂/kg); Metaal - Staal AFW, Name: Metaal - Staal AFW; Metaal - Staal AFW, Participates in Collision Detection: yes; Metaal - Staal AFW, Aardopwarmingsvermogen (GWP): 12.4; Metaal - Staal AFW, Ozonafbrekend Vermogen (ODP): 0; Metaal - Staal AFW, Fotochemische Vermogen tot Ozonvorming (POCP): 0.00443; Metaal - Staal AFW, Verzuringsvermogen (AP): 0.0382; Metaal - Staal AFW, Eutrofiëringspotentieel (EP): 0.00359; Metaal - Staal AFW, Abiotisch Uitputtingspotentieel (voor niet fossiele hulpbronnen) (ADPE): 0.000573; Metaal - Staal AFW, Abiotisch Uitputtingspotentieel (voor fossiele hulpbronnen) (ADPF): 126; Metaal - Staal AFW, Databron: https://www.oekobaudat.de/OEKOBAU.DAT/resource/processes/c3ac069a-6cc4-4d41-a5fc-565615547792?version=00.02.000; Metaal - Staal AFW, Handelsgewicht (kg/m): 0; Metaal - Staal AFW, Soortelijk gewicht (kg/m3): 7850; Metaal - Staal AFW, Marge materiaal: 1
Name | Slope (deg)
11 x h METAAL_Kader-x | 90
h METAAL_Kader-x | 1.04867e-07
8 x h METAAL_Kader-x | 33.6901
36 x h METAAL_Kader-x | 0
h METAAL_Kader-x | 33.69
3 x _Kader-x | 0
2 x h METAAL_Kader-x | 0.00000103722

# IfcMember: IfcMember (57)
In: 1e verdieping
Type - ElementType: Rail; PredefinedType: USERDEFINED
Material: Metaal - RVS
Material Properties - Metaal - RVS, ThermalConductivity: 17; Metaal - RVS, SpecificHeatCapacity: 460 J/kg/K; Metaal - RVS, MassDensity: 7900 kg/m3; Metaal - RVS, Embodied Energy: 56.7 (MJ/kg); Metaal - RVS, Embodied Carbon: 6.15 (kgCO₂/kg); Metaal - RVS, Name: Metaal - RVS; Metaal - RVS, Participates in Collision Detection: yes; Metaal - RVS, Aardopwarmingsvermogen (GWP): 0.00255297; Metaal - RVS, Ozonafbrekend Vermogen (ODP): 0; Metaal - RVS, Fotochemische Vermogen tot Ozonvorming (POCP): -0.0000016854; Metaal - RVS, Verzuringsvermogen (AP): 0.00000515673; Metaal - RVS, Eutrofiëringspotentieel (EP): 0.0000012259; Metaal - RVS, Abiotisch Uitputtingspotentieel (voor niet fossiele hulpbronnen) (ADPE): 0; Metaal - RVS, Abiotisch Uitputtingspotentieel (voor fossiele hulpbronnen) (ADPF): 0.0342213; Metaal - RVS, Databron: https://www.oekobaudat.de/OEKOBAU.DAT/resource/processes/88559403-7658-48f2-bac9-7986b4d0f4c2?version=20.19.120; Metaal - RVS, Handelsgewicht (kg/m): 0; Metaal - RVS, Soortelijk gewicht (kg/m3): 7850; Metaal - RVS, Marge materiaal: 1
CPset_Phasing - Renovation Phase: Bestaand
Name
9 x h3 Staal legeringen_Handregel-x
28 x h3 Staal legeringen_
15 x h3 Staal legeringen_Regel-x
4 x _Regel-x
_

# IfcMember: IfcMember (2)
In: 1e verdieping
Type - PredefinedType: POST
CPset_Phasing - Renovation Phase: Bestaand
Name | Material
h3 Staal legeringen_ | Metaal - RVS | Material Properties - Metaal - RVS, ThermalConductivity: 17; Metaal - RVS, SpecificHeatCapacity: 460 J/kg/K; Metaal - RVS, MassDensity: 7900 kg/m3; Metaal - RVS, Embodied Energy: 56.7 (MJ/kg); Metaal - RVS, Embodied Carbon: 6.15 (kgCO₂/kg); Metaal - RVS, Name: Metaal - RVS; Metaal - RVS, Participates in Collision Detection: yes; Metaal - RVS, Aardopwarmingsvermogen (GWP): 0.00255297; Metaal - RVS, Ozonafbrekend Vermogen (ODP): 0; Metaal - RVS, Fotochemische Vermogen tot Ozonvorming (POCP): -0.0000016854; Metaal - RVS, Verzuringsvermogen (AP): 0.00000515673; Metaal - RVS, Eutrofiëringspotentieel (EP): 0.0000012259; Metaal - RVS, Abiotisch Uitputtingspotentieel (voor niet fossiele hulpbronnen) (ADPE): 0; Metaal - RVS, Abiotisch Uitputtingspotentieel (voor fossiele hulpbronnen) (ADPF): 0.0342213; Metaal - RVS, Databron: https://www.oekobaudat.de/OEKOBAU.DAT/resource/processes/88559403-7658-48f2-bac9-7986b4d0f4c2?version=20.19.120; Metaal - RVS, Handelsgewicht (kg/m): 0; Metaal - RVS, Soortelijk gewicht (kg/m3): 7850; Metaal - RVS, Marge materiaal: 1
i HOUT_ | Hout AFW | Material Properties - Hout AFW, ThermalConductivity: 0.14; Hout AFW, SpecificHeatCapacity: 1880 J/kg/K; Hout AFW, MassDensity: 550 kg/m3; Hout AFW, Embodied Energy: 7.4 (MJ/kg); Hout AFW, Embodied Carbon: 0.19 (kgCO₂/kg); Hout AFW, Name: Hout AFW; Hout AFW, Participates in Collision Detection: yes

# IfcMember: Mullion Frame 50 x 313 (60)
In: 1e verdieping
Type - PredefinedType: MULLION
Material: Metaal - Staal AFW
Pset_MemberCommon - Slope: 90 deg
CPset_Phasing - Renovation Phase: Bestaand
Material Properties - Metaal - Staal AFW, ThermalConductivity: 52; Metaal - Staal AFW, SpecificHeatCapacity: 530 J/kg/K; Metaal - Staal AFW, MassDensity: 7950 kg/m3; Metaal - Staal AFW, Embodied Energy: 25 (MJ/kg); Metaal - Staal AFW, Embodied Carbon: 1.91 (kgCO₂/kg); Metaal - Staal AFW, Name: Metaal - Staal AFW; Metaal - Staal AFW, Participates in Collision Detection: yes; Metaal - Staal AFW, Aardopwarmingsvermogen (GWP): 12.4; Metaal - Staal AFW, Ozonafbrekend Vermogen (ODP): 0; Metaal - Staal AFW, Fotochemische Vermogen tot Ozonvorming (POCP): 0.00443; Metaal - Staal AFW, Verzuringsvermogen (AP): 0.0382; Metaal - Staal AFW, Eutrofiëringspotentieel (EP): 0.00359; Metaal - Staal AFW, Abiotisch Uitputtingspotentieel (voor niet fossiele hulpbronnen) (ADPE): 0.000573; Metaal - Staal AFW, Abiotisch Uitputtingspotentieel (voor fossiele hulpbronnen) (ADPF): 126; Metaal - Staal AFW, Databron: https://www.oekobaudat.de/OEKOBAU.DAT/resource/processes/c3ac069a-6cc4-4d41-a5fc-565615547792?version=00.02.000; Metaal - Staal AFW, Handelsgewicht (kg/m): 0; Metaal - Staal AFW, Soortelijk gewicht (kg/m3): 7850; Metaal - Staal AFW, Marge materiaal: 1
Name
14 x h METAAL_Kader-x
46 x _Kader-x

# IfcMember: Transom Frame 50 x 258 (53)
In: 1e verdieping
Type - PredefinedType: MULLION
Material: Metaal - Staal AFW
CPset_Phasing - Renovation Phase: Bestaand
Material Properties - Metaal - Staal AFW, ThermalConductivity: 52; Metaal - Staal AFW, SpecificHeatCapacity: 530 J/kg/K; Metaal - Staal AFW, MassDensity: 7950 kg/m3; Metaal - Staal AFW, Embodied Energy: 25 (MJ/kg); Metaal - Staal AFW, Embodied Carbon: 1.91 (kgCO₂/kg); Metaal - Staal AFW, Name: Metaal - Staal AFW; Metaal - Staal AFW, Participates in Collision Detection: yes; Metaal - Staal AFW, Aardopwarmingsvermogen (GWP): 12.4; Metaal - Staal AFW, Ozonafbrekend Vermogen (ODP): 0; Metaal - Staal AFW, Fotochemische Vermogen tot Ozonvorming (POCP): 0.00443; Metaal - Staal AFW, Verzuringsvermogen (AP): 0.0382; Metaal - Staal AFW, Eutrofiëringspotentieel (EP): 0.00359; Metaal - Staal AFW, Abiotisch Uitputtingspotentieel (voor niet fossiele hulpbronnen) (ADPE): 0.000573; Metaal - Staal AFW, Abiotisch Uitputtingspotentieel (voor fossiele hulpbronnen) (ADPF): 126; Metaal - Staal AFW, Databron: https://www.oekobaudat.de/OEKOBAU.DAT/resource/processes/c3ac069a-6cc4-4d41-a5fc-565615547792?version=00.02.000; Metaal - Staal AFW, Handelsgewicht (kg/m): 0; Metaal - Staal AFW, Soortelijk gewicht (kg/m3): 7850; Metaal - Staal AFW, Marge materiaal: 1
Name | Slope (deg)
14 x h METAAL_Kader-x | 0
h METAAL_Kader-x | 0.00000286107
27 x _Kader-x | 0
2 x h METAAL_Kader-x | 1.3105e-07
2 x h METAAL_Kader-x | 6.84963e-07
h METAAL_Kader-x | 0.00000213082
h METAAL_Kader-x | 0.00000824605
h METAAL_Kader-x | 0.0000083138
h METAAL_Kader-x | 4.74058e-07
h METAAL_Kader-x | 0.00000263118
h METAAL_Kader-x | 6.54756e-07
_Kader-x | 4.12717e-07

# IfcOpeningElement (215)
Name | In
5 x _Opening-x | Kelder | CPset_Phasing - Renovation Phase: Bestaand
_01.07 | Kelder
_03.06 | Kelder
6 x _Merk AF | Begane grond
_Merk AB2 | Begane grond
2 x _Merk AA | Begane grond
15 x _- | Begane grond
_Merk AB1 | Begane grond
_Merk AE | Begane grond
_Merk AN | Begane grond
_Merk AJ | Begane grond
4 x _B.01 | Begane grond
_B.17 | Begane grond
2 x _B.13 | Begane grond
_02.04 | Begane grond
6 x _01.02 | Begane grond
8 x _01.01 | Begane grond
_01.05 | Begane grond
_B.14 | Begane grond
_01.04 | Begane grond
_02.03 | Begane grond
2 x _03.02 | Begane grond
_C.06 | Begane grond
_01.06 | Begane grond
2 x _C.02 | Begane grond
_B.15 | Begane grond
2 x _B.05 | Begane grond
_02.06 | Begane grond
2 x _C.03 | Begane grond
_02.02 | Begane grond
2 x _C.04 | Begane grond
_C.07 | Begane grond
_01.03 | Begane grond
2 x _B.02 | Begane grond
_04.02 | Begane grond
2 x _B.04 | Begane grond
_04.01 | Begane grond
2 x _B.07 | Begane grond
_B.11 | Begane grond
2 x _03.04 | Begane grond
_02.05 | Begane grond
2 x _B.06 | Begane grond
4 x _C.01 | Begane grond
_B.03 | Begane grond
_B.09 | Begane grond
_B.16 | Begane grond
_Merk AK | Begane grond
_02.01 | Begane grond
2 x _Merk AC | Begane grond
2 x _Merk AG | Begane grond
2 x _Merk AD | Begane grond
_03.01 | Begane grond
3 x _Opening-x | Begane grond | CPset_Phasing - Renovation Phase: Bestaand
_Merk AH | Begane grond
_Merk AL1 | Begane grond
_Merk AL2 | Begane grond
_Merk BH | 1e verdieping
_Merk BJ | 1e verdieping
3 x _Merk BA | 1e verdieping
4 x _Merk BB | 1e verdieping
_Merk BC2 | 1e verdieping
_Merk BC1 | 1e verdieping
4 x _Merk BD | 1e verdieping
_Merk BE | 1e verdieping
_Merk BF | 1e verdieping
_F.01 | 1e verdieping
8 x _01.01 | 1e verdieping
3 x _B.02 | 1e verdieping
2 x _C.02 | 1e verdieping
2 x _B.07 | 1e verdieping
2 x _B.08 | 1e verdieping
_02.01 | 1e verdieping
2 x _01.03 | 1e verdieping
_C.05 | 1e verdieping
3 x _B.01 | 1e verdieping
3 x _01.02 | 1e verdieping
_03.03 | 1e verdieping
_C.09 | 1e verdieping
_B.10 | 1e verdieping
_A.01b | 1e verdieping
_A.01a | 1e verdieping
_A.04 | 1e verdieping
_03.05 | 1e verdieping
_A.02 | 1e verdieping
_03.01 | 1e verdieping
9 x _- | 1e verdieping
3 x _D.01 | 1e verdieping
_03.02 | 1e verdieping
_D.03 | 1e verdieping
_B.12 | 1e verdieping
_D.05 | 1e verdieping
_D.04 | 1e verdieping
2 x _D.02 | 1e verdieping
_Opening-x | 1e verdieping | CPset_Phasing - Renovation Phase: Bestaand
_Merk BG | 1e verdieping
_02.07 | 1e verdieping
_01.04 | 1e verdieping
_Merk BK1 | 1e verdieping
_Merk BK2 | 1e verdieping
_Merk BK3 | 1e verdieping
_02.04 | 1e verdieping
_A.05 | 1e verdieping
2 x _Wandeinde-x | 1e verdieping
4 x _C.01 | 1e verdieping
2 x _B.06 | 1e verdieping
_B.03 | 1e verdieping
_B.09 | 1e verdieping
_01.08 | 1e verdieping
8 x _Opening-x | 2e dakoverzicht | CPset_Phasing - Renovation Phase: Bestaand

# IfcPlate: 1969 x 1500 x 42, _Paneel-x
In: 1e verdieping
Type - PredefinedType: CURTAIN_PANEL
CPset_Phasing - Renovation Phase: Bestaand

# IfcPlate: Main Panel 1010 x 125 x 42, o GLAS_Paneel-x
In: 1e verdieping
Type - PredefinedType: CURTAIN_PANEL
Material: Glas
Material Properties - Glas, ThermalConductivity: 1.2; Glas, SpecificHeatCapacity: 795 J/kg/K; Glas, MassDensity: 2180 kg/m3; Glas, Embodied Energy: 15 (MJ/kg); Glas, Embodied Carbon: 0.86 (kgCO₂/kg); Glas, Name: Glas; Glas, Participates in Collision Detection: yes; Glas, Aardopwarmingsvermogen (GWP): 44.3346; Glas, Ozonafbrekend Vermogen (ODP): 0; Glas, Fotochemische Vermogen tot Ozonvorming (POCP): 0.0213557; Glas, Verzuringsvermogen (AP): 0.281643; Glas, Eutrofiëringspotentieel (EP): 0.0316879; Glas, Abiotisch Uitputtingspotentieel (voor niet fossiele hulpbronnen) (ADPE): 0.00000449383; Glas, Abiotisch Uitputtingspotentieel (voor fossiele hulpbronnen) (ADPF): 628.803; Glas, Databron: https://www.oekobaudat.de/OEKOBAU.DAT/resource/processes/1f2d6e42-9ffc-421d-990d-555eee4a7529?version=20.19.120
CPset_Phasing - Renovation Phase: Bestaand

# IfcPlate: Main Panel 1010 x 1430 x 42, o GLAS_Paneel-x
In: 1e verdieping
Type - PredefinedType: CURTAIN_PANEL
Material: Glas
CPset_Phasing - Renovation Phase: Bestaand
Material Properties - Glas, ThermalConductivity: 1.2; Glas, SpecificHeatCapacity: 795 J/kg/K; Glas, MassDensity: 2180 kg/m3; Glas, Embodied Energy: 15 (MJ/kg); Glas, Embodied Carbon: 0.86 (kgCO₂/kg); Glas, Name: Glas; Glas, Participates in Collision Detection: yes; Glas, Aardopwarmingsvermogen (GWP): 44.3346; Glas, Ozonafbrekend Vermogen (ODP): 0; Glas, Fotochemische Vermogen tot Ozonvorming (POCP): 0.0213557; Glas, Verzuringsvermogen (AP): 0.281643; Glas, Eutrofiëringspotentieel (EP): 0.0316879; Glas, Abiotisch Uitputtingspotentieel (voor niet fossiele hulpbronnen) (ADPE): 0.00000449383; Glas, Abiotisch Uitputtingspotentieel (voor fossiele hulpbronnen) (ADPF): 628.803; Glas, Databron: https://www.oekobaudat.de/OEKOBAU.DAT/resource/processes/1f2d6e42-9ffc-421d-990d-555eee4a7529?version=20.19.120

# IfcPlate: Main Panel 1010 x 1500 x 42, o GLAS_Paneel-x
In: 1e verdieping
Type - PredefinedType: CURTAIN_PANEL
Material: Glas
CPset_Phasing - Renovation Phase: Bestaand
Material Properties - Glas, ThermalConductivity: 1.2; Glas, SpecificHeatCapacity: 795 J/kg/K; Glas, MassDensity: 2180 kg/m3; Glas, Embodied Energy: 15 (MJ/kg); Glas, Embodied Carbon: 0.86 (kgCO₂/kg); Glas, Name: Glas; Glas, Participates in Collision Detection: yes; Glas, Aardopwarmingsvermogen (GWP): 44.3346; Glas, Ozonafbrekend Vermogen (ODP): 0; Glas, Fotochemische Vermogen tot Ozonvorming (POCP): 0.0213557; Glas, Verzuringsvermogen (AP): 0.281643; Glas, Eutrofiëringspotentieel (EP): 0.0316879; Glas, Abiotisch Uitputtingspotentieel (voor niet fossiele hulpbronnen) (ADPE): 0.00000449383; Glas, Abiotisch Uitputtingspotentieel (voor fossiele hulpbronnen) (ADPF): 628.803; Glas, Databron: https://www.oekobaudat.de/OEKOBAU.DAT/resource/processes/1f2d6e42-9ffc-421d-990d-555eee4a7529?version=20.19.120

# IfcPlate: Main Panel 1010 x 85 x 42, o GLAS_Paneel-x
In: 1e verdieping
Type - PredefinedType: CURTAIN_PANEL
Material: Glas
Material Properties - Glas, ThermalConductivity: 1.2; Glas, SpecificHeatCapacity: 795 J/kg/K; Glas, MassDensity: 2180 kg/m3; Glas, Embodied Energy: 15 (MJ/kg); Glas, Embodied Carbon: 0.86 (kgCO₂/kg); Glas, Name: Glas; Glas, Participates in Collision Detection: yes; Glas, Aardopwarmingsvermogen (GWP): 44.3346; Glas, Ozonafbrekend Vermogen (ODP): 0; Glas, Fotochemische Vermogen tot Ozonvorming (POCP): 0.0213557; Glas, Verzuringsvermogen (AP): 0.281643; Glas, Eutrofiëringspotentieel (EP): 0.0316879; Glas, Abiotisch Uitputtingspotentieel (voor niet fossiele hulpbronnen) (ADPE): 0.00000449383; Glas, Abiotisch Uitputtingspotentieel (voor fossiele hulpbronnen) (ADPF): 628.803; Glas, Databron: https://www.oekobaudat.de/OEKOBAU.DAT/resource/processes/1f2d6e42-9ffc-421d-990d-555eee4a7529?version=20.19.120
CPset_Phasing - Renovation Phase: Bestaand

# IfcPlate: Main Panel 1038 x 1000 x 42, o GLAS_Paneel-x
In: 1e verdieping
Type - PredefinedType: CURTAIN_PANEL
Material: Glas
CPset_Phasing - Renovation Phase: Bestaand
Material Properties - Glas, ThermalConductivity: 1.2; Glas, SpecificHeatCapacity: 795 J/kg/K; Glas, MassDensity: 2180 kg/m3; Glas, Embodied Energy: 15 (MJ/kg); Glas, Embodied Carbon: 0.86 (kgCO₂/kg); Glas, Name: Glas; Glas, Participates in Collision Detection: yes; Glas, Aardopwarmingsvermogen (GWP): 44.3346; Glas, Ozonafbrekend Vermogen (ODP): 0; Glas, Fotochemische Vermogen tot Ozonvorming (POCP): 0.0213557; Glas, Verzuringsvermogen (AP): 0.281643; Glas, Eutrofiëringspotentieel (EP): 0.0316879; Glas, Abiotisch Uitputtingspotentieel (voor niet fossiele hulpbronnen) (ADPE): 0.00000449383; Glas, Abiotisch Uitputtingspotentieel (voor fossiele hulpbronnen) (ADPF): 628.803; Glas, Databron: https://www.oekobaudat.de/OEKOBAU.DAT/resource/processes/1f2d6e42-9ffc-421d-990d-555eee4a7529?version=20.19.120

# IfcPlate: Main Panel 1038 x 125 x 42, o GLAS_Paneel-x
In: 1e verdieping
Type - PredefinedType: CURTAIN_PANEL
Material: Glas
CPset_Phasing - Renovation Phase: Bestaand
Material Properties - Glas, ThermalConductivity: 1.2; Glas, SpecificHeatCapacity: 795 J/kg/K; Glas, MassDensity: 2180 kg/m3; Glas, Embodied Energy: 15 (MJ/kg); Glas, Embodied Carbon: 0.86 (kgCO₂/kg); Glas, Name: Glas; Glas, Participates in Collision Detection: yes; Glas, Aardopwarmingsvermogen (GWP): 44.3346; Glas, Ozonafbrekend Vermogen (ODP): 0; Glas, Fotochemische Vermogen tot Ozonvorming (POCP): 0.0213557; Glas, Verzuringsvermogen (AP): 0.281643; Glas, Eutrofiëringspotentieel (EP): 0.0316879; Glas, Abiotisch Uitputtingspotentieel (voor niet fossiele hulpbronnen) (ADPE): 0.00000449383; Glas, Abiotisch Uitputtingspotentieel (voor fossiele hulpbronnen) (ADPF): 628.803; Glas, Databron: https://www.oekobaudat.de/OEKOBAU.DAT/resource/processes/1f2d6e42-9ffc-421d-990d-555eee4a7529?version=20.19.120

# IfcPlate: Main Panel 1038 x 1500 x 42, o GLAS_Paneel-x
In: 1e verdieping
Type - PredefinedType: CURTAIN_PANEL
Material: Glas
Material Properties - Glas, ThermalConductivity: 1.2; Glas, SpecificHeatCapacity: 795 J/kg/K; Glas, MassDensity: 2180 kg/m3; Glas, Embodied Energy: 15 (MJ/kg); Glas, Embodied Carbon: 0.86 (kgCO₂/kg); Glas, Name: Glas; Glas, Participates in Collision Detection: yes; Glas, Aardopwarmingsvermogen (GWP): 44.3346; Glas, Ozonafbrekend Vermogen (ODP): 0; Glas, Fotochemische Vermogen tot Ozonvorming (POCP): 0.0213557; Glas, Verzuringsvermogen (AP): 0.281643; Glas, Eutrofiëringspotentieel (EP): 0.0316879; Glas, Abiotisch Uitputtingspotentieel (voor niet fossiele hulpbronnen) (ADPE): 0.00000449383; Glas, Abiotisch Uitputtingspotentieel (voor fossiele hulpbronnen) (ADPF): 628.803; Glas, Databron: https://www.oekobaudat.de/OEKOBAU.DAT/resource/processes/1f2d6e42-9ffc-421d-990d-555eee4a7529?version=20.19.120
CPset_Phasing - Renovation Phase: Bestaand

# IfcPlate: Main Panel 1070 x 125 x 42, o GLAS_Paneel-x
In: 1e verdieping
Type - PredefinedType: CURTAIN_PANEL
Material: Glas
CPset_Phasing - Renovation Phase: Bestaand
Material Properties - Glas, ThermalConductivity: 1.2; Glas, SpecificHeatCapacity: 795 J/kg/K; Glas, MassDensity: 2180 kg/m3; Glas, Embodied Energy: 15 (MJ/kg); Glas, Embodied Carbon: 0.86 (kgCO₂/kg); Glas, Name: Glas; Glas, Participates in Collision Detection: yes; Glas, Aardopwarmingsvermogen (GWP): 44.3346; Glas, Ozonafbrekend Vermogen (ODP): 0; Glas, Fotochemische Vermogen tot Ozonvorming (POCP): 0.0213557; Glas, Verzuringsvermogen (AP): 0.281643; Glas, Eutrofiëringspotentieel (EP): 0.0316879; Glas, Abiotisch Uitputtingspotentieel (voor niet fossiele hulpbronnen) (ADPE): 0.00000449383; Glas, Abiotisch Uitputtingspotentieel (voor fossiele hulpbronnen) (ADPF): 628.803; Glas, Databron: https://www.oekobaudat.de/OEKOBAU.DAT/resource/processes/1f2d6e42-9ffc-421d-990d-555eee4a7529?version=20.19.120

# IfcPlate: Main Panel 1070 x 1430 x 42, o GLAS_Paneel-x
In: 1e verdieping
Type - PredefinedType: CURTAIN_PANEL
Material: Glas
CPset_Phasing - Renovation Phase: Bestaand
Material Properties - Glas, ThermalConductivity: 1.2; Glas, SpecificHeatCapacity: 795 J/kg/K; Glas, MassDensity: 2180 kg/m3; Glas, Embodied Energy: 15 (MJ/kg); Glas, Embodied Carbon: 0.86 (kgCO₂/kg); Glas, Name: Glas; Glas, Participates in Collision Detection: yes; Glas, Aardopwarmingsvermogen (GWP): 44.3346; Glas, Ozonafbrekend Vermogen (ODP): 0; Glas, Fotochemische Vermogen tot Ozonvorming (POCP): 0.0213557; Glas, Verzuringsvermogen (AP): 0.281643; Glas, Eutrofiëringspotentieel (EP): 0.0316879; Glas, Abiotisch Uitputtingspotentieel (voor niet fossiele hulpbronnen) (ADPE): 0.00000449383; Glas, Abiotisch Uitputtingspotentieel (voor fossiele hulpbronnen) (ADPF): 628.803; Glas, Databron: https://www.oekobaudat.de/OEKOBAU.DAT/resource/processes/1f2d6e42-9ffc-421d-990d-555eee4a7529?version=20.19.120

# IfcPlate: Main Panel 1070 x 1500 x 42, o GLAS_Paneel-x
In: 1e verdieping
Type - PredefinedType: CURTAIN_PANEL
Material: Glas
CPset_Phasing - Renovation Phase: Bestaand
Material Properties - Glas, ThermalConductivity: 1.2; Glas, SpecificHeatCapacity: 795 J/kg/K; Glas, MassDensity: 2180 kg/m3; Glas, Embodied Energy: 15 (MJ/kg); Glas, Embodied Carbon: 0.86 (kgCO₂/kg); Glas, Name: Glas; Glas, Participates in Collision Detection: yes; Glas, Aardopwarmingsvermogen (GWP): 44.3346; Glas, Ozonafbrekend Vermogen (ODP): 0; Glas, Fotochemische Vermogen tot Ozonvorming (POCP): 0.0213557; Glas, Verzuringsvermogen (AP): 0.281643; Glas, Eutrofiëringspotentieel (EP): 0.0316879; Glas, Abiotisch Uitputtingspotentieel (voor niet fossiele hulpbronnen) (ADPE): 0.00000449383; Glas, Abiotisch Uitputtingspotentieel (voor fossiele hulpbronnen) (ADPF): 628.803; Glas, Databron: https://www.oekobaudat.de/OEKOBAU.DAT/resource/processes/1f2d6e42-9ffc-421d-990d-555eee4a7529?version=20.19.120

# IfcPlate: Main Panel 1070 x 85 x 42, o GLAS_Paneel-x
In: 1e verdieping
Type - PredefinedType: CURTAIN_PANEL
Material: Glas
CPset_Phasing - Renovation Phase: Bestaand
Material Properties - Glas, ThermalConductivity: 1.2; Glas, SpecificHeatCapacity: 795 J/kg/K; Glas, MassDensity: 2180 kg/m3; Glas, Embodied Energy: 15 (MJ/kg); Glas, Embodied Carbon: 0.86 (kgCO₂/kg); Glas, Name: Glas; Glas, Participates in Collision Detection: yes; Glas, Aardopwarmingsvermogen (GWP): 44.3346; Glas, Ozonafbrekend Vermogen (ODP): 0; Glas, Fotochemische Vermogen tot Ozonvorming (POCP): 0.0213557; Glas, Verzuringsvermogen (AP): 0.281643; Glas, Eutrofiëringspotentieel (EP): 0.0316879; Glas, Abiotisch Uitputtingspotentieel (voor niet fossiele hulpbronnen) (ADPE): 0.00000449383; Glas, Abiotisch Uitputtingspotentieel (voor fossiele hulpbronnen) (ADPF): 628.803; Glas, Databron: https://www.oekobaudat.de/OEKOBAU.DAT/resource/processes/1f2d6e42-9ffc-421d-990d-555eee4a7529?version=20.19.120

# IfcPlate: Main Panel 195 x 962 x 42, o GLAS_Paneel-x
In: 1e verdieping
Type - PredefinedType: CURTAIN_PANEL
Material: Glas
CPset_Phasing - Renovation Phase: Bestaand
Material Properties - Glas, ThermalConductivity: 1.2; Glas, SpecificHeatCapacity: 795 J/kg/K; Glas, MassDensity: 2180 kg/m3; Glas, Embodied Energy: 15 (MJ/kg); Glas, Embodied Carbon: 0.86 (kgCO₂/kg); Glas, Name: Glas; Glas, Participates in Collision Detection: yes; Glas, Aardopwarmingsvermogen (GWP): 44.3346; Glas, Ozonafbrekend Vermogen (ODP): 0; Glas, Fotochemische Vermogen tot Ozonvorming (POCP): 0.0213557; Glas, Verzuringsvermogen (AP): 0.281643; Glas, Eutrofiëringspotentieel (EP): 0.0316879; Glas, Abiotisch Uitputtingspotentieel (voor niet fossiele hulpbronnen) (ADPE): 0.00000449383; Glas, Abiotisch Uitputtingspotentieel (voor fossiele hulpbronnen) (ADPF): 628.803; Glas, Databron: https://www.oekobaudat.de/OEKOBAU.DAT/resource/processes/1f2d6e42-9ffc-421d-990d-555eee4a7529?version=20.19.120

# IfcPlate: Main Panel 1969 x 125 x 42, o GLAS_Paneel-x
In: 1e verdieping
Type - PredefinedType: CURTAIN_PANEL
Material: Glas
CPset_Phasing - Renovation Phase: Bestaand
Material Properties - Glas, ThermalConductivity: 1.2; Glas, SpecificHeatCapacity: 795 J/kg/K; Glas, MassDensity: 2180 kg/m3; Glas, Embodied Energy: 15 (MJ/kg); Glas, Embodied Carbon: 0.86 (kgCO₂/kg); Glas, Name: Glas; Glas, Participates in Collision Detection: yes; Glas, Aardopwarmingsvermogen (GWP): 44.3346; Glas, Ozonafbrekend Vermogen (ODP): 0; Glas, Fotochemische Vermogen tot Ozonvorming (POCP): 0.0213557; Glas, Verzuringsvermogen (AP): 0.281643; Glas, Eutrofiëringspotentieel (EP): 0.0316879; Glas, Abiotisch Uitputtingspotentieel (voor niet fossiele hulpbronnen) (ADPE): 0.00000449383; Glas, Abiotisch Uitputtingspotentieel (voor fossiele hulpbronnen) (ADPF): 628.803; Glas, Databron: https://www.oekobaudat.de/OEKOBAU.DAT/resource/processes/1f2d6e42-9ffc-421d-990d-555eee4a7529?version=20.19.120

# IfcPlate: Main Panel 1978 x 10 x 42, o GLAS_Paneel-x
In: 1e verdieping
Type - PredefinedType: CURTAIN_PANEL
Material: Glas
CPset_Phasing - Renovation Phase: Bestaand
Material Properties - Glas, ThermalConductivity: 1.2; Glas, SpecificHeatCapacity: 795 J/kg/K; Glas, MassDensity: 2180 kg/m3; Glas, Embodied Energy: 15 (MJ/kg); Glas, Embodied Carbon: 0.86 (kgCO₂/kg); Glas, Name: Glas; Glas, Participates in Collision Detection: yes; Glas, Aardopwarmingsvermogen (GWP): 44.3346; Glas, Ozonafbrekend Vermogen (ODP): 0; Glas, Fotochemische Vermogen tot Ozonvorming (POCP): 0.0213557; Glas, Verzuringsvermogen (AP): 0.281643; Glas, Eutrofiëringspotentieel (EP): 0.0316879; Glas, Abiotisch Uitputtingspotentieel (voor niet fossiele hulpbronnen) (ADPE): 0.00000449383; Glas, Abiotisch Uitputtingspotentieel (voor fossiele hulpbronnen) (ADPF): 628.803; Glas, Databron: https://www.oekobaudat.de/OEKOBAU.DAT/resource/processes/1f2d6e42-9ffc-421d-990d-555eee4a7529?version=20.19.120

# IfcPlate: Main Panel 320 x 1027 x 42, o GLAS_Paneel-x
In: 1e verdieping
Type - PredefinedType: CURTAIN_PANEL
Material: Glas
Material Properties - Glas, ThermalConductivity: 1.2; Glas, SpecificHeatCapacity: 795 J/kg/K; Glas, MassDensity: 2180 kg/m3; Glas, Embodied Energy: 15 (MJ/kg); Glas, Embodied Carbon: 0.86 (kgCO₂/kg); Glas, Name: Glas; Glas, Participates in Collision Detection: yes; Glas, Aardopwarmingsvermogen (GWP): 44.3346; Glas, Ozonafbrekend Vermogen (ODP): 0; Glas, Fotochemische Vermogen tot Ozonvorming (POCP): 0.0213557; Glas, Verzuringsvermogen (AP): 0.281643; Glas, Eutrofiëringspotentieel (EP): 0.0316879; Glas, Abiotisch Uitputtingspotentieel (voor niet fossiele hulpbronnen) (ADPE): 0.00000449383; Glas, Abiotisch Uitputtingspotentieel (voor fossiele hulpbronnen) (ADPF): 628.803; Glas, Databron: https://www.oekobaudat.de/OEKOBAU.DAT/resource/processes/1f2d6e42-9ffc-421d-990d-555eee4a7529?version=20.19.120
CPset_Phasing - Renovation Phase: Bestaand

# IfcPlate: Main Panel 367 x 125 x 42, o GLAS_Paneel-x
In: 1e verdieping
Type - PredefinedType: CURTAIN_PANEL
Material: Glas
Material Properties - Glas, ThermalConductivity: 1.2; Glas, SpecificHeatCapacity: 795 J/kg/K; Glas, MassDensity: 2180 kg/m3; Glas, Embodied Energy: 15 (MJ/kg); Glas, Embodied Carbon: 0.86 (kgCO₂/kg); Glas, Name: Glas; Glas, Participates in Collision Detection: yes; Glas, Aardopwarmingsvermogen (GWP): 44.3346; Glas, Ozonafbrekend Vermogen (ODP): 0; Glas, Fotochemische Vermogen tot Ozonvorming (POCP): 0.0213557; Glas, Verzuringsvermogen (AP): 0.281643; Glas, Eutrofiëringspotentieel (EP): 0.0316879; Glas, Abiotisch Uitputtingspotentieel (voor niet fossiele hulpbronnen) (ADPE): 0.00000449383; Glas, Abiotisch Uitputtingspotentieel (voor fossiele hulpbronnen) (ADPF): 628.803; Glas, Databron: https://www.oekobaudat.de/OEKOBAU.DAT/resource/processes/1f2d6e42-9ffc-421d-990d-555eee4a7529?version=20.19.120
CPset_Phasing - Renovation Phase: Bestaand

# IfcPlate: Main Panel 367 x 1500 x 42, o GLAS_Paneel-x
In: 1e verdieping
Type - PredefinedType: CURTAIN_PANEL
Material: Glas
CPset_Phasing - Renovation Phase: Bestaand
Material Properties - Glas, ThermalConductivity: 1.2; Glas, SpecificHeatCapacity: 795 J/kg/K; Glas, MassDensity: 2180 kg/m3; Glas, Embodied Energy: 15 (MJ/kg); Glas, Embodied Carbon: 0.86 (kgCO₂/kg); Glas, Name: Glas; Glas, Participates in Collision Detection: yes; Glas, Aardopwarmingsvermogen (GWP): 44.3346; Glas, Ozonafbrekend Vermogen (ODP): 0; Glas, Fotochemische Vermogen tot Ozonvorming (POCP): 0.0213557; Glas, Verzuringsvermogen (AP): 0.281643; Glas, Eutrofiëringspotentieel (EP): 0.0316879; Glas, Abiotisch Uitputtingspotentieel (voor niet fossiele hulpbronnen) (ADPE): 0.00000449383; Glas, Abiotisch Uitputtingspotentieel (voor fossiele hulpbronnen) (ADPF): 628.803; Glas, Databron: https://www.oekobaudat.de/OEKOBAU.DAT/resource/processes/1f2d6e42-9ffc-421d-990d-555eee4a7529?version=20.19.120

# IfcPlate: Main Panel 43 x 125 x 42, o GLAS_Paneel-x
In: 1e verdieping
Type - PredefinedType: CURTAIN_PANEL
Material: Glas
Material Properties - Glas, ThermalConductivity: 1.2; Glas, SpecificHeatCapacity: 795 J/kg/K; Glas, MassDensity: 2180 kg/m3; Glas, Embodied Energy: 15 (MJ/kg); Glas, Embodied Carbon: 0.86 (kgCO₂/kg); Glas, Name: Glas; Glas, Participates in Collision Detection: yes; Glas, Aardopwarmingsvermogen (GWP): 44.3346; Glas, Ozonafbrekend Vermogen (ODP): 0; Glas, Fotochemische Vermogen tot Ozonvorming (POCP): 0.0213557; Glas, Verzuringsvermogen (AP): 0.281643; Glas, Eutrofiëringspotentieel (EP): 0.0316879; Glas, Abiotisch Uitputtingspotentieel (voor niet fossiele hulpbronnen) (ADPE): 0.00000449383; Glas, Abiotisch Uitputtingspotentieel (voor fossiele hulpbronnen) (ADPF): 628.803; Glas, Databron: https://www.oekobaudat.de/OEKOBAU.DAT/resource/processes/1f2d6e42-9ffc-421d-990d-555eee4a7529?version=20.19.120
CPset_Phasing - Renovation Phase: Bestaand

# IfcPlate: Main Panel 43 x 1430 x 42, o GLAS_Paneel-x
In: 1e verdieping
Type - PredefinedType: CURTAIN_PANEL
Material: Glas
Material Properties - Glas, ThermalConductivity: 1.2; Glas, SpecificHeatCapacity: 795 J/kg/K; Glas, MassDensity: 2180 kg/m3; Glas, Embodied Energy: 15 (MJ/kg); Glas, Embodied Carbon: 0.86 (kgCO₂/kg); Glas, Name: Glas; Glas, Participates in Collision Detection: yes; Glas, Aardopwarmingsvermogen (GWP): 44.3346; Glas, Ozonafbrekend Vermogen (ODP): 0; Glas, Fotochemische Vermogen tot Ozonvorming (POCP): 0.0213557; Glas, Verzuringsvermogen (AP): 0.281643; Glas, Eutrofiëringspotentieel (EP): 0.0316879; Glas, Abiotisch Uitputtingspotentieel (voor niet fossiele hulpbronnen) (ADPE): 0.00000449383; Glas, Abiotisch Uitputtingspotentieel (voor fossiele hulpbronnen) (ADPF): 628.803; Glas, Databron: https://www.oekobaudat.de/OEKOBAU.DAT/resource/processes/1f2d6e42-9ffc-421d-990d-555eee4a7529?version=20.19.120
CPset_Phasing - Renovation Phase: Bestaand

# IfcPlate: Main Panel 43 x 1500 x 42, o GLAS_Paneel-x
In: 1e verdieping
Type - PredefinedType: CURTAIN_PANEL
Material: Glas
CPset_Phasing - Renovation Phase: Bestaand
Material Properties - Glas, ThermalConductivity: 1.2; Glas, SpecificHeatCapacity: 795 J/kg/K; Glas, MassDensity: 2180 kg/m3; Glas, Embodied Energy: 15 (MJ/kg); Glas, Embodied Carbon: 0.86 (kgCO₂/kg); Glas, Name: Glas; Glas, Participates in Collision Detection: yes; Glas, Aardopwarmingsvermogen (GWP): 44.3346; Glas, Ozonafbrekend Vermogen (ODP): 0; Glas, Fotochemische Vermogen tot Ozonvorming (POCP): 0.0213557; Glas, Verzuringsvermogen (AP): 0.281643; Glas, Eutrofiëringspotentieel (EP): 0.0316879; Glas, Abiotisch Uitputtingspotentieel (voor niet fossiele hulpbronnen) (ADPE): 0.00000449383; Glas, Abiotisch Uitputtingspotentieel (voor fossiele hulpbronnen) (ADPF): 628.803; Glas, Databron: https://www.oekobaudat.de/OEKOBAU.DAT/resource/processes/1f2d6e42-9ffc-421d-990d-555eee4a7529?version=20.19.120

# IfcPlate: Main Panel 43 x 85 x 42, o GLAS_Paneel-x
In: 1e verdieping
Type - PredefinedType: CURTAIN_PANEL
Material: Glas
CPset_Phasing - Renovation Phase: Bestaand
Material Properties - Glas, ThermalConductivity: 1.2; Glas, SpecificHeatCapacity: 795 J/kg/K; Glas, MassDensity: 2180 kg/m3; Glas, Embodied Energy: 15 (MJ/kg); Glas, Embodied Carbon: 0.86 (kgCO₂/kg); Glas, Name: Glas; Glas, Participates in Collision Detection: yes; Glas, Aardopwarmingsvermogen (GWP): 44.3346; Glas, Ozonafbrekend Vermogen (ODP): 0; Glas, Fotochemische Vermogen tot Ozonvorming (POCP): 0.0213557; Glas, Verzuringsvermogen (AP): 0.281643; Glas, Eutrofiëringspotentieel (EP): 0.0316879; Glas, Abiotisch Uitputtingspotentieel (voor niet fossiele hulpbronnen) (ADPE): 0.00000449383; Glas, Abiotisch Uitputtingspotentieel (voor fossiele hulpbronnen) (ADPF): 628.803; Glas, Databron: https://www.oekobaudat.de/OEKOBAU.DAT/resource/processes/1f2d6e42-9ffc-421d-990d-555eee4a7529?version=20.19.120

# IfcPlate: Main Panel 433 x 125 x 42, o GLAS_Paneel-x
In: 1e verdieping
Type - PredefinedType: CURTAIN_PANEL
Material: Glas
CPset_Phasing - Renovation Phase: Bestaand
Material Properties - Glas, ThermalConductivity: 1.2; Glas, SpecificHeatCapacity: 795 J/kg/K; Glas, MassDensity: 2180 kg/m3; Glas, Embodied Energy: 15 (MJ/kg); Glas, Embodied Carbon: 0.86 (kgCO₂/kg); Glas, Name: Glas; Glas, Participates in Collision Detection: yes; Glas, Aardopwarmingsvermogen (GWP): 44.3346; Glas, Ozonafbrekend Vermogen (ODP): 0; Glas, Fotochemische Vermogen tot Ozonvorming (POCP): 0.0213557; Glas, Verzuringsvermogen (AP): 0.281643; Glas, Eutrofiëringspotentieel (EP): 0.0316879; Glas, Abiotisch Uitputtingspotentieel (voor niet fossiele hulpbronnen) (ADPE): 0.00000449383; Glas, Abiotisch Uitputtingspotentieel (voor fossiele hulpbronnen) (ADPF): 628.803; Glas, Databron: https://www.oekobaudat.de/OEKOBAU.DAT/resource/processes/1f2d6e42-9ffc-421d-990d-555eee4a7529?version=20.19.120

# IfcPlate: Main Panel 433 x 1430 x 42, o GLAS_Paneel-x
In: 1e verdieping
Type - PredefinedType: CURTAIN_PANEL
Material: Glas
CPset_Phasing - Renovation Phase: Bestaand
Material Properties - Glas, ThermalConductivity: 1.2; Glas, SpecificHeatCapacity: 795 J/kg/K; Glas, MassDensity: 2180 kg/m3; Glas, Embodied Energy: 15 (MJ/kg); Glas, Embodied Carbon: 0.86 (kgCO₂/kg); Glas, Name: Glas; Glas, Participates in Collision Detection: yes; Glas, Aardopwarmingsvermogen (GWP): 44.3346; Glas, Ozonafbrekend Vermogen (ODP): 0; Glas, Fotochemische Vermogen tot Ozonvorming (POCP): 0.0213557; Glas, Verzuringsvermogen (AP): 0.281643; Glas, Eutrofiëringspotentieel (EP): 0.0316879; Glas, Abiotisch Uitputtingspotentieel (voor niet fossiele hulpbronnen) (ADPE): 0.00000449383; Glas, Abiotisch Uitputtingspotentieel (voor fossiele hulpbronnen) (ADPF): 628.803; Glas, Databron: https://www.oekobaudat.de/OEKOBAU.DAT/resource/processes/1f2d6e42-9ffc-421d-990d-555eee4a7529?version=20.19.120

# IfcPlate: Main Panel 433 x 1500 x 42, o GLAS_Paneel-x
In: 1e verdieping
Type - PredefinedType: CURTAIN_PANEL
Material: Glas
Material Properties - Glas, ThermalConductivity: 1.2; Glas, SpecificHeatCapacity: 795 J/kg/K; Glas, MassDensity: 2180 kg/m3; Glas, Embodied Energy: 15 (MJ/kg); Glas, Embodied Carbon: 0.86 (kgCO₂/kg); Glas, Name: Glas; Glas, Participates in Collision Detection: yes; Glas, Aardopwarmingsvermogen (GWP): 44.3346; Glas, Ozonafbrekend Vermogen (ODP): 0; Glas, Fotochemische Vermogen tot Ozonvorming (POCP): 0.0213557; Glas, Verzuringsvermogen (AP): 0.281643; Glas, Eutrofiëringspotentieel (EP): 0.0316879; Glas, Abiotisch Uitputtingspotentieel (voor niet fossiele hulpbronnen) (ADPE): 0.00000449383; Glas, Abiotisch Uitputtingspotentieel (voor fossiele hulpbronnen) (ADPF): 628.803; Glas, Databron: https://www.oekobaudat.de/OEKOBAU.DAT/resource/processes/1f2d6e42-9ffc-421d-990d-555eee4a7529?version=20.19.120
CPset_Phasing - Renovation Phase: Bestaand

# IfcPlate: Main Panel 433 x 85 x 42, o GLAS_Paneel-x
In: 1e verdieping
Type - PredefinedType: CURTAIN_PANEL
Material: Glas
CPset_Phasing - Renovation Phase: Bestaand
Material Properties - Glas, ThermalConductivity: 1.2; Glas, SpecificHeatCapacity: 795 J/kg/K; Glas, MassDensity: 2180 kg/m3; Glas, Embodied Energy: 15 (MJ/kg); Glas, Embodied Carbon: 0.86 (kgCO₂/kg); Glas, Name: Glas; Glas, Participates in Collision Detection: yes; Glas, Aardopwarmingsvermogen (GWP): 44.3346; Glas, Ozonafbrekend Vermogen (ODP): 0; Glas, Fotochemische Vermogen tot Ozonvorming (POCP): 0.0213557; Glas, Verzuringsvermogen (AP): 0.281643; Glas, Eutrofiëringspotentieel (EP): 0.0316879; Glas, Abiotisch Uitputtingspotentieel (voor niet fossiele hulpbronnen) (ADPE): 0.00000449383; Glas, Abiotisch Uitputtingspotentieel (voor fossiele hulpbronnen) (ADPF): 628.803; Glas, Databron: https://www.oekobaudat.de/OEKOBAU.DAT/resource/processes/1f2d6e42-9ffc-421d-990d-555eee4a7529?version=20.19.120

# IfcPlate: Main Panel 533 x 125 x 42 (2)
In: 1e verdieping
Type - PredefinedType: CURTAIN_PANEL
Material: Glas
CPset_Phasing - Renovation Phase: Bestaand
Material Properties - Glas, ThermalConductivity: 1.2; Glas, SpecificHeatCapacity: 795 J/kg/K; Glas, MassDensity: 2180 kg/m3; Glas, Embodied Energy: 15 (MJ/kg); Glas, Embodied Carbon: 0.86 (kgCO₂/kg); Glas, Name: Glas; Glas, Participates in Collision Detection: yes; Glas, Aardopwarmingsvermogen (GWP): 44.3346; Glas, Ozonafbrekend Vermogen (ODP): 0; Glas, Fotochemische Vermogen tot Ozonvorming (POCP): 0.0213557; Glas, Verzuringsvermogen (AP): 0.281643; Glas, Eutrofiëringspotentieel (EP): 0.0316879; Glas, Abiotisch Uitputtingspotentieel (voor niet fossiele hulpbronnen) (ADPE): 0.00000449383; Glas, Abiotisch Uitputtingspotentieel (voor fossiele hulpbronnen) (ADPF): 628.803; Glas, Databron: https://www.oekobaudat.de/OEKOBAU.DAT/resource/processes/1f2d6e42-9ffc-421d-990d-555eee4a7529?version=20.19.120

# IfcPlate: Main Panel 533 x 1500 x 42 (2)
In: 1e verdieping
Type - PredefinedType: CURTAIN_PANEL
Material: Glas
Material Properties - Glas, ThermalConductivity: 1.2; Glas, SpecificHeatCapacity: 795 J/kg/K; Glas, MassDensity: 2180 kg/m3; Glas, Embodied Energy: 15 (MJ/kg); Glas, Embodied Carbon: 0.86 (kgCO₂/kg); Glas, Name: Glas; Glas, Participates in Collision Detection: yes; Glas, Aardopwarmingsvermogen (GWP): 44.3346; Glas, Ozonafbrekend Vermogen (ODP): 0; Glas, Fotochemische Vermogen tot Ozonvorming (POCP): 0.0213557; Glas, Verzuringsvermogen (AP): 0.281643; Glas, Eutrofiëringspotentieel (EP): 0.0316879; Glas, Abiotisch Uitputtingspotentieel (voor niet fossiele hulpbronnen) (ADPE): 0.00000449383; Glas, Abiotisch Uitputtingspotentieel (voor fossiele hulpbronnen) (ADPF): 628.803; Glas, Databron: https://www.oekobaudat.de/OEKOBAU.DAT/resource/processes/1f2d6e42-9ffc-421d-990d-555eee4a7529?version=20.19.120
CPset_Phasing - Renovation Phase: Bestaand

# IfcPlate: Main Panel 533 x 965 x 42, o GLAS_Paneel-x
In: 1e verdieping
Type - PredefinedType: CURTAIN_PANEL
Material: Glas
Material Properties - Glas, ThermalConductivity: 1.2; Glas, SpecificHeatCapacity: 795 J/kg/K; Glas, MassDensity: 2180 kg/m3; Glas, Embodied Energy: 15 (MJ/kg); Glas, Embodied Carbon: 0.86 (kgCO₂/kg); Glas, Name: Glas; Glas, Participates in Collision Detection: yes; Glas, Aardopwarmingsvermogen (GWP): 44.3346; Glas, Ozonafbrekend Vermogen (ODP): 0; Glas, Fotochemische Vermogen tot Ozonvorming (POCP): 0.0213557; Glas, Verzuringsvermogen (AP): 0.281643; Glas, Eutrofiëringspotentieel (EP): 0.0316879; Glas, Abiotisch Uitputtingspotentieel (voor niet fossiele hulpbronnen) (ADPE): 0.00000449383; Glas, Abiotisch Uitputtingspotentieel (voor fossiele hulpbronnen) (ADPF): 628.803; Glas, Databron: https://www.oekobaudat.de/OEKOBAU.DAT/resource/processes/1f2d6e42-9ffc-421d-990d-555eee4a7529?version=20.19.120
CPset_Phasing - Renovation Phase: Bestaand

# IfcPlate: Main Panel 633 x 125 x 42, o GLAS_Paneel-x
In: 1e verdieping
Type - PredefinedType: CURTAIN_PANEL
Material: Glas
CPset_Phasing - Renovation Phase: Bestaand
Material Properties - Glas, ThermalConductivity: 1.2; Glas, SpecificHeatCapacity: 795 J/kg/K; Glas, MassDensity: 2180 kg/m3; Glas, Embodied Energy: 15 (MJ/kg); Glas, Embodied Carbon: 0.86 (kgCO₂/kg); Glas, Name: Glas; Glas, Participates in Collision Detection: yes; Glas, Aardopwarmingsvermogen (GWP): 44.3346; Glas, Ozonafbrekend Vermogen (ODP): 0; Glas, Fotochemische Vermogen tot Ozonvorming (POCP): 0.0213557; Glas, Verzuringsvermogen (AP): 0.281643; Glas, Eutrofiëringspotentieel (EP): 0.0316879; Glas, Abiotisch Uitputtingspotentieel (voor niet fossiele hulpbronnen) (ADPE): 0.00000449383; Glas, Abiotisch Uitputtingspotentieel (voor fossiele hulpbronnen) (ADPF): 628.803; Glas, Databron: https://www.oekobaudat.de/OEKOBAU.DAT/resource/processes/1f2d6e42-9ffc-421d-990d-555eee4a7529?version=20.19.120

# IfcPlate: Main Panel 633 x 1500 x 42, o GLAS_Paneel-x
In: 1e verdieping
Type - PredefinedType: CURTAIN_PANEL
Material: Glas
CPset_Phasing - Renovation Phase: Bestaand
Material Properties - Glas, ThermalConductivity: 1.2; Glas, SpecificHeatCapacity: 795 J/kg/K; Glas, MassDensity: 2180 kg/m3; Glas, Embodied Energy: 15 (MJ/kg); Glas, Embodied Carbon: 0.86 (kgCO₂/kg); Glas, Name: Glas; Glas, Participates in Collision Detection: yes; Glas, Aardopwarmingsvermogen (GWP): 44.3346; Glas, Ozonafbrekend Vermogen (ODP): 0; Glas, Fotochemische Vermogen tot Ozonvorming (POCP): 0.0213557; Glas, Verzuringsvermogen (AP): 0.281643; Glas, Eutrofiëringspotentieel (EP): 0.0316879; Glas, Abiotisch Uitputtingspotentieel (voor niet fossiele hulpbronnen) (ADPE): 0.00000449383; Glas, Abiotisch Uitputtingspotentieel (voor fossiele hulpbronnen) (ADPF): 628.803; Glas, Databron: https://www.oekobaudat.de/OEKOBAU.DAT/resource/processes/1f2d6e42-9ffc-421d-990d-555eee4a7529?version=20.19.120

# IfcPlate: Main Panel 717 x 125 x 42, o GLAS_Paneel-x
In: 1e verdieping
Type - PredefinedType: CURTAIN_PANEL
Material: Glas
CPset_Phasing - Renovation Phase: Bestaand
Material Properties - Glas, ThermalConductivity: 1.2; Glas, SpecificHeatCapacity: 795 J/kg/K; Glas, MassDensity: 2180 kg/m3; Glas, Embodied Energy: 15 (MJ/kg); Glas, Embodied Carbon: 0.86 (kgCO₂/kg); Glas, Name: Glas; Glas, Participates in Collision Detection: yes; Glas, Aardopwarmingsvermogen (GWP): 44.3346; Glas, Ozonafbrekend Vermogen (ODP): 0; Glas, Fotochemische Vermogen tot Ozonvorming (POCP): 0.0213557; Glas, Verzuringsvermogen (AP): 0.281643; Glas, Eutrofiëringspotentieel (EP): 0.0316879; Glas, Abiotisch Uitputtingspotentieel (voor niet fossiele hulpbronnen) (ADPE): 0.00000449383; Glas, Abiotisch Uitputtingspotentieel (voor fossiele hulpbronnen) (ADPF): 628.803; Glas, Databron: https://www.oekobaudat.de/OEKOBAU.DAT/resource/processes/1f2d6e42-9ffc-421d-990d-555eee4a7529?version=20.19.120

# IfcPlate: Main Panel 717 x 1500 x 42, o GLAS_Paneel-x
In: 1e verdieping
Type - PredefinedType: CURTAIN_PANEL
Material: Glas
CPset_Phasing - Renovation Phase: Bestaand
Material Properties - Glas, ThermalConductivity: 1.2; Glas, SpecificHeatCapacity: 795 J/kg/K; Glas, MassDensity: 2180 kg/m3; Glas, Embodied Energy: 15 (MJ/kg); Glas, Embodied Carbon: 0.86 (kgCO₂/kg); Glas, Name: Glas; Glas, Participates in Collision Detection: yes; Glas, Aardopwarmingsvermogen (GWP): 44.3346; Glas, Ozonafbrekend Vermogen (ODP): 0; Glas, Fotochemische Vermogen tot Ozonvorming (POCP): 0.0213557; Glas, Verzuringsvermogen (AP): 0.281643; Glas, Eutrofiëringspotentieel (EP): 0.0316879; Glas, Abiotisch Uitputtingspotentieel (voor niet fossiele hulpbronnen) (ADPE): 0.00000449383; Glas, Abiotisch Uitputtingspotentieel (voor fossiele hulpbronnen) (ADPF): 628.803; Glas, Databron: https://www.oekobaudat.de/OEKOBAU.DAT/resource/processes/1f2d6e42-9ffc-421d-990d-555eee4a7529?version=20.19.120

# IfcPlate: Main Panel 780 x 125 x 42, o GLAS_Paneel-x
In: 1e verdieping
Type - PredefinedType: CURTAIN_PANEL
Material: Glas
CPset_Phasing - Renovation Phase: Bestaand
Material Properties - Glas, ThermalConductivity: 1.2; Glas, SpecificHeatCapacity: 795 J/kg/K; Glas, MassDensity: 2180 kg/m3; Glas, Embodied Energy: 15 (MJ/kg); Glas, Embodied Carbon: 0.86 (kgCO₂/kg); Glas, Name: Glas; Glas, Participates in Collision Detection: yes; Glas, Aardopwarmingsvermogen (GWP): 44.3346; Glas, Ozonafbrekend Vermogen (ODP): 0; Glas, Fotochemische Vermogen tot Ozonvorming (POCP): 0.0213557; Glas, Verzuringsvermogen (AP): 0.281643; Glas, Eutrofiëringspotentieel (EP): 0.0316879; Glas, Abiotisch Uitputtingspotentieel (voor niet fossiele hulpbronnen) (ADPE): 0.00000449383; Glas, Abiotisch Uitputtingspotentieel (voor fossiele hulpbronnen) (ADPF): 628.803; Glas, Databron: https://www.oekobaudat.de/OEKOBAU.DAT/resource/processes/1f2d6e42-9ffc-421d-990d-555eee4a7529?version=20.19.120

# IfcPlate: Main Panel 780 x 1430 x 42, o GLAS_Paneel-x
In: 1e verdieping
Type - PredefinedType: CURTAIN_PANEL
Material: Glas
CPset_Phasing - Renovation Phase: Bestaand
Material Properties - Glas, ThermalConductivity: 1.2; Glas, SpecificHeatCapacity: 795 J/kg/K; Glas, MassDensity: 2180 kg/m3; Glas, Embodied Energy: 15 (MJ/kg); Glas, Embodied Carbon: 0.86 (kgCO₂/kg); Glas, Name: Glas; Glas, Participates in Collision Detection: yes; Glas, Aardopwarmingsvermogen (GWP): 44.3346; Glas, Ozonafbrekend Vermogen (ODP): 0; Glas, Fotochemische Vermogen tot Ozonvorming (POCP): 0.0213557; Glas, Verzuringsvermogen (AP): 0.281643; Glas, Eutrofiëringspotentieel (EP): 0.0316879; Glas, Abiotisch Uitputtingspotentieel (voor niet fossiele hulpbronnen) (ADPE): 0.00000449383; Glas, Abiotisch Uitputtingspotentieel (voor fossiele hulpbronnen) (ADPF): 628.803; Glas, Databron: https://www.oekobaudat.de/OEKOBAU.DAT/resource/processes/1f2d6e42-9ffc-421d-990d-555eee4a7529?version=20.19.120

# IfcPlate: Main Panel 780 x 85 x 42, o GLAS_Paneel-x
In: 1e verdieping
Type - PredefinedType: CURTAIN_PANEL
Material: Glas
CPset_Phasing - Renovation Phase: Bestaand
Material Properties - Glas, ThermalConductivity: 1.2; Glas, SpecificHeatCapacity: 795 J/kg/K; Glas, MassDensity: 2180 kg/m3; Glas, Embodied Energy: 15 (MJ/kg); Glas, Embodied Carbon: 0.86 (kgCO₂/kg); Glas, Name: Glas; Glas, Participates in Collision Detection: yes; Glas, Aardopwarmingsvermogen (GWP): 44.3346; Glas, Ozonafbrekend Vermogen (ODP): 0; Glas, Fotochemische Vermogen tot Ozonvorming (POCP): 0.0213557; Glas, Verzuringsvermogen (AP): 0.281643; Glas, Eutrofiëringspotentieel (EP): 0.0316879; Glas, Abiotisch Uitputtingspotentieel (voor niet fossiele hulpbronnen) (ADPE): 0.00000449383; Glas, Abiotisch Uitputtingspotentieel (voor fossiele hulpbronnen) (ADPF): 628.803; Glas, Databron: https://www.oekobaudat.de/OEKOBAU.DAT/resource/processes/1f2d6e42-9ffc-421d-990d-555eee4a7529?version=20.19.120

# IfcPlate: Main Panel 788 x 40 x 42, o GLAS_Paneel-x
In: 1e verdieping
Type - PredefinedType: CURTAIN_PANEL
Material: Glas
CPset_Phasing - Renovation Phase: Bestaand
Material Properties - Glas, ThermalConductivity: 1.2; Glas, SpecificHeatCapacity: 795 J/kg/K; Glas, MassDensity: 2180 kg/m3; Glas, Embodied Energy: 15 (MJ/kg); Glas, Embodied Carbon: 0.86 (kgCO₂/kg); Glas, Name: Glas; Glas, Participates in Collision Detection: yes; Glas, Aardopwarmingsvermogen (GWP): 44.3346; Glas, Ozonafbrekend Vermogen (ODP): 0; Glas, Fotochemische Vermogen tot Ozonvorming (POCP): 0.0213557; Glas, Verzuringsvermogen (AP): 0.281643; Glas, Eutrofiëringspotentieel (EP): 0.0316879; Glas, Abiotisch Uitputtingspotentieel (voor niet fossiele hulpbronnen) (ADPE): 0.00000449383; Glas, Abiotisch Uitputtingspotentieel (voor fossiele hulpbronnen) (ADPF): 628.803; Glas, Databron: https://www.oekobaudat.de/OEKOBAU.DAT/resource/processes/1f2d6e42-9ffc-421d-990d-555eee4a7529?version=20.19.120

# IfcPlate: Main Panel 843 x 125 x 42, o GLAS_Paneel-x
In: 1e verdieping
Type - PredefinedType: CURTAIN_PANEL
Material: Glas
CPset_Phasing - Renovation Phase: Bestaand
Material Properties - Glas, ThermalConductivity: 1.2; Glas, SpecificHeatCapacity: 795 J/kg/K; Glas, MassDensity: 2180 kg/m3; Glas, Embodied Energy: 15 (MJ/kg); Glas, Embodied Carbon: 0.86 (kgCO₂/kg); Glas, Name: Glas; Glas, Participates in Collision Detection: yes; Glas, Aardopwarmingsvermogen (GWP): 44.3346; Glas, Ozonafbrekend Vermogen (ODP): 0; Glas, Fotochemische Vermogen tot Ozonvorming (POCP): 0.0213557; Glas, Verzuringsvermogen (AP): 0.281643; Glas, Eutrofiëringspotentieel (EP): 0.0316879; Glas, Abiotisch Uitputtingspotentieel (voor niet fossiele hulpbronnen) (ADPE): 0.00000449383; Glas, Abiotisch Uitputtingspotentieel (voor fossiele hulpbronnen) (ADPF): 628.803; Glas, Databron: https://www.oekobaudat.de/OEKOBAU.DAT/resource/processes/1f2d6e42-9ffc-421d-990d-555eee4a7529?version=20.19.120

# IfcPlate: Main Panel 843 x 1430 x 42, o GLAS_Paneel-x
In: 1e verdieping
Type - PredefinedType: CURTAIN_PANEL
Material: Glas
Material Properties - Glas, ThermalConductivity: 1.2; Glas, SpecificHeatCapacity: 795 J/kg/K; Glas, MassDensity: 2180 kg/m3; Glas, Embodied Energy: 15 (MJ/kg); Glas, Embodied Carbon: 0.86 (kgCO₂/kg); Glas, Name: Glas; Glas, Participates in Collision Detection: yes; Glas, Aardopwarmingsvermogen (GWP): 44.3346; Glas, Ozonafbrekend Vermogen (ODP): 0; Glas, Fotochemische Vermogen tot Ozonvorming (POCP): 0.0213557; Glas, Verzuringsvermogen (AP): 0.281643; Glas, Eutrofiëringspotentieel (EP): 0.0316879; Glas, Abiotisch Uitputtingspotentieel (voor niet fossiele hulpbronnen) (ADPE): 0.00000449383; Glas, Abiotisch Uitputtingspotentieel (voor fossiele hulpbronnen) (ADPF): 628.803; Glas, Databron: https://www.oekobaudat.de/OEKOBAU.DAT/resource/processes/1f2d6e42-9ffc-421d-990d-555eee4a7529?version=20.19.120
CPset_Phasing - Renovation Phase: Bestaand

# IfcPlate: Main Panel 843 x 1500 x 42, o GLAS_Paneel-x
In: 1e verdieping
Type - PredefinedType: CURTAIN_PANEL
Material: Glas
CPset_Phasing - Renovation Phase: Bestaand
Material Properties - Glas, ThermalConductivity: 1.2; Glas, SpecificHeatCapacity: 795 J/kg/K; Glas, MassDensity: 2180 kg/m3; Glas, Embodied Energy: 15 (MJ/kg); Glas, Embodied Carbon: 0.86 (kgCO₂/kg); Glas, Name: Glas; Glas, Participates in Collision Detection: yes; Glas, Aardopwarmingsvermogen (GWP): 44.3346; Glas, Ozonafbrekend Vermogen (ODP): 0; Glas, Fotochemische Vermogen tot Ozonvorming (POCP): 0.0213557; Glas, Verzuringsvermogen (AP): 0.281643; Glas, Eutrofiëringspotentieel (EP): 0.0316879; Glas, Abiotisch Uitputtingspotentieel (voor niet fossiele hulpbronnen) (ADPE): 0.00000449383; Glas, Abiotisch Uitputtingspotentieel (voor fossiele hulpbronnen) (ADPF): 628.803; Glas, Databron: https://www.oekobaudat.de/OEKOBAU.DAT/resource/processes/1f2d6e42-9ffc-421d-990d-555eee4a7529?version=20.19.120

# IfcPlate: Main Panel 843 x 85 x 42, o GLAS_Paneel-x
In: 1e verdieping
Type - PredefinedType: CURTAIN_PANEL
Material: Glas
CPset_Phasing - Renovation Phase: Bestaand
Material Properties - Glas, ThermalConductivity: 1.2; Glas, SpecificHeatCapacity: 795 J/kg/K; Glas, MassDensity: 2180 kg/m3; Glas, Embodied Energy: 15 (MJ/kg); Glas, Embodied Carbon: 0.86 (kgCO₂/kg); Glas, Name: Glas; Glas, Participates in Collision Detection: yes; Glas, Aardopwarmingsvermogen (GWP): 44.3346; Glas, Ozonafbrekend Vermogen (ODP): 0; Glas, Fotochemische Vermogen tot Ozonvorming (POCP): 0.0213557; Glas, Verzuringsvermogen (AP): 0.281643; Glas, Eutrofiëringspotentieel (EP): 0.0316879; Glas, Abiotisch Uitputtingspotentieel (voor niet fossiele hulpbronnen) (ADPE): 0.00000449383; Glas, Abiotisch Uitputtingspotentieel (voor fossiele hulpbronnen) (ADPF): 628.803; Glas, Databron: https://www.oekobaudat.de/OEKOBAU.DAT/resource/processes/1f2d6e42-9ffc-421d-990d-555eee4a7529?version=20.19.120

# IfcRailing: Railing Type (7)
In: 1e verdieping
Pset_RailingCommon - IsExternal: no
CPset_Phasing - Renovation Phase: Bestaand

# IfcRoof (31)
CPset_Phasing - Renovation Phase: Bestaand
Pset_RoofCommon - IsExternal: yes
Name | In | Material | TotalArea (m2) | Isolatie - Kunststof hard, ThermalConductivity | Isolatie - Kunststof hard, SpecificHeatCapacity (J/kg/K) | Isolatie - Kunststof hard, MassDensity (kg/m3) | Isolatie - Kunststof hard, Embodied Energy | Isolatie - Kunststof hard, Embodied Carbon | Isolatie - Kunststof hard, Name | Isolatie - Kunststof hard, Participates in Collision Detection | Isolatie - Kunststof hard, Aardopwarmingsvermogen (GWP) | Isolatie - Kunststof hard, Ozonafbrekend Vermogen (ODP) = Isolatie - Kunststof hard, Fotochemische Vermogen tot Ozonvorming (POCP) = Isolatie - Kunststof hard, Abiotisch Uitputtingspotentieel (voor niet fossiele hulpbronnen) (ADPE) | Isolatie - Kunststof hard, Verzuringsvermogen (AP) | Isolatie - Kunststof hard, Eutrofiëringspotentieel (EP) | Isolatie - Kunststof hard, Abiotisch Uitputtingspotentieel (voor fossiele hulpbronnen) (ADPF) | Isolatie - Kunststof hard, Databron
27_Dak-x | Begane grond | Isolatie - Kunststof hard | 1.60882 | 0.029 | 1470 | 100 | 101.5 (MJ/kg) | 3.48 (kgCO₂/kg) | Isolatie - Kunststof hard | yes | 0.04 | 0 | 0.0000975 | 0.0000237 | 0.47 | https://www.oekobaudat.de/OEKOBAU.DAT/resource/processes/41e09ab7-0e73-4303-84fd-97cb0809db02?version=00.04.000
27_Dak-x | Begane grond | Isolatie - Kunststof hard | 0.39 | 0.029 | 1470 | 100 | 101.5 (MJ/kg) | 3.48 (kgCO₂/kg) | Isolatie - Kunststof hard | yes | 0.04 | 0 | 0.0000975 | 0.0000237 | 0.47 | https://www.oekobaudat.de/OEKOBAU.DAT/resource/processes/41e09ab7-0e73-4303-84fd-97cb0809db02?version=00.04.000
27_Dak-x | Begane grond | Isolatie - Kunststof hard | 0.532877 | 0.029 | 1470 | 100 | 101.5 (MJ/kg) | 3.48 (kgCO₂/kg) | Isolatie - Kunststof hard | yes | 0.04 | 0 | 0.0000975 | 0.0000237 | 0.47 | https://www.oekobaudat.de/OEKOBAU.DAT/resource/processes/41e09ab7-0e73-4303-84fd-97cb0809db02?version=00.04.000
27_Dak-x | Begane grond | Metaal - Aluminium | 4.15459 | Material Properties - Metaal - Aluminium, ThermalConductivity: 160; Metaal - Aluminium, SpecificHeatCapacity: 880 J/kg/K; Metaal - Aluminium, MassDensity: 2800 kg/m3; Metaal - Aluminium, Embodied Energy: 155 (MJ/kg); Metaal - Aluminium, Embodied Carbon: 9.16 (kgCO₂/kg); Metaal - Aluminium, Name: Metaal - Aluminium; Metaal - Aluminium, Participates in Collision Detection: yes; Metaal - Aluminium, Aardopwarmingsvermogen (GWP): 0.002322; Metaal - Aluminium, Ozonafbrekend Vermogen (ODP): 0; Metaal - Aluminium, Fotochemische Vermogen tot Ozonvorming (POCP): 6.194e-07; Metaal - Aluminium, Verzuringsvermogen (AP): 0.000008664; Metaal - Aluminium, Eutrofiëringspotentieel (EP): 0.00000106; Metaal - Aluminium, Abiotisch Uitputtingspotentieel (voor niet fossiele hulpbronnen) (ADPE): 0; Metaal - Aluminium, Abiotisch Uitputtingspotentieel (voor fossiele hulpbronnen) (ADPF): 0.02659; Metaal - Aluminium, Databron: https://www.oekobaudat.de/OEKOBAU.DAT/resource/processes/c83d501f-d07f-4434-9d5c-862a7e8a3026?version=00.01.000; Metaal - Aluminium, Handelsgewicht (kg/m): 0; Metaal - Aluminium, Soortelijk gewicht (kg/m3): 7850; Metaal - Aluminium, Marge materiaal: 1
27_Dak-x | Begane grond | Gipsplaat | 2.01742 | Material Properties - Gipsplaat, ThermalConductivity: 0.23; Gipsplaat, SpecificHeatCapacity: 840 J/kg/K; Gipsplaat, MassDensity: 800 kg/m3; Gipsplaat, Embodied Energy: 6.75 (MJ/kg); Gipsplaat, Embodied Carbon: 0.38 (kgCO₂/kg); Gipsplaat, Name: Gipsplaat; Gipsplaat, Participates in Collision Detection: yes; Gipsplaat, Aardopwarmingsvermogen (GWP): 1.513; Gipsplaat, Ozonafbrekend Vermogen (ODP): 1.32e-07; Gipsplaat, Fotochemische Vermogen tot Ozonvorming (POCP): 0.000358; Gipsplaat, Verzuringsvermogen (AP): 0.0082; Gipsplaat, Eutrofiëringspotentieel (EP): 0.00138; Gipsplaat, Abiotisch Uitputtingspotentieel (voor niet fossiele hulpbronnen) (ADPE): 0.00000729; Gipsplaat, Abiotisch Uitputtingspotentieel (voor fossiele hulpbronnen) (ADPF): 25.04; Gipsplaat, Databron: https://www.oekobaudat.de/OEKOBAU.DAT/resource/processes/1a24808b-9116-422e-93fb-d435f74a038a?version=00.05.000
2 x 27_Dak-x | Begane grond | Isolatie - Kunststof hard | 1.94541 | 0.029 | 1470 | 100 | 101.5 (MJ/kg) | 3.48 (kgCO₂/kg) | Isolatie - Kunststof hard | yes | 0.04 | 0 | 0.0000975 | 0.0000237 | 0.47 | https://www.oekobaudat.de/OEKOBAU.DAT/resource/processes/41e09ab7-0e73-4303-84fd-97cb0809db02?version=00.04.000
2 x 27_Dak-x | Begane grond | Isolatie - Kunststof hard | 0.603238 | 0.029 | 1470 | 100 | 101.5 (MJ/kg) | 3.48 (kgCO₂/kg) | Isolatie - Kunststof hard | yes | 0.04 | 0 | 0.0000975 | 0.0000237 | 0.47 | https://www.oekobaudat.de/OEKOBAU.DAT/resource/processes/41e09ab7-0e73-4303-84fd-97cb0809db02?version=00.04.000
27_Dak-x | Begane grond | Isolatie - Kunststof hard | 0.0429223 | 0.029 | 1470 | 100 | 101.5 (MJ/kg) | 3.48 (kgCO₂/kg) | Isolatie - Kunststof hard | yes | 0.04 | 0 | 0.0000975 | 0.0000237 | 0.47 | https://www.oekobaudat.de/OEKOBAU.DAT/resource/processes/41e09ab7-0e73-4303-84fd-97cb0809db02?version=00.04.000
27_Dak-x | Begane grond | Isolatie - Kunststof hard | 0.217698 | 0.029 | 1470 | 100 | 101.5 (MJ/kg) | 3.48 (kgCO₂/kg) | Isolatie - Kunststof hard | yes | 0.04 | 0 | 0.0000975 | 0.0000237 | 0.47 | https://www.oekobaudat.de/OEKOBAU.DAT/resource/processes/41e09ab7-0e73-4303-84fd-97cb0809db02?version=00.04.000
2 x 27_Dak-x | Begane grond | Isolatie - Kunststof hard | 0.488812 | 0.029 | 1470 | 100 | 101.5 (MJ/kg) | 3.48 (kgCO₂/kg) | Isolatie - Kunststof hard | yes | 0.04 | 0 | 0.0000975 | 0.0000237 | 0.47 | https://www.oekobaudat.de/OEKOBAU.DAT/resource/processes/41e09ab7-0e73-4303-84fd-97cb0809db02?version=00.04.000
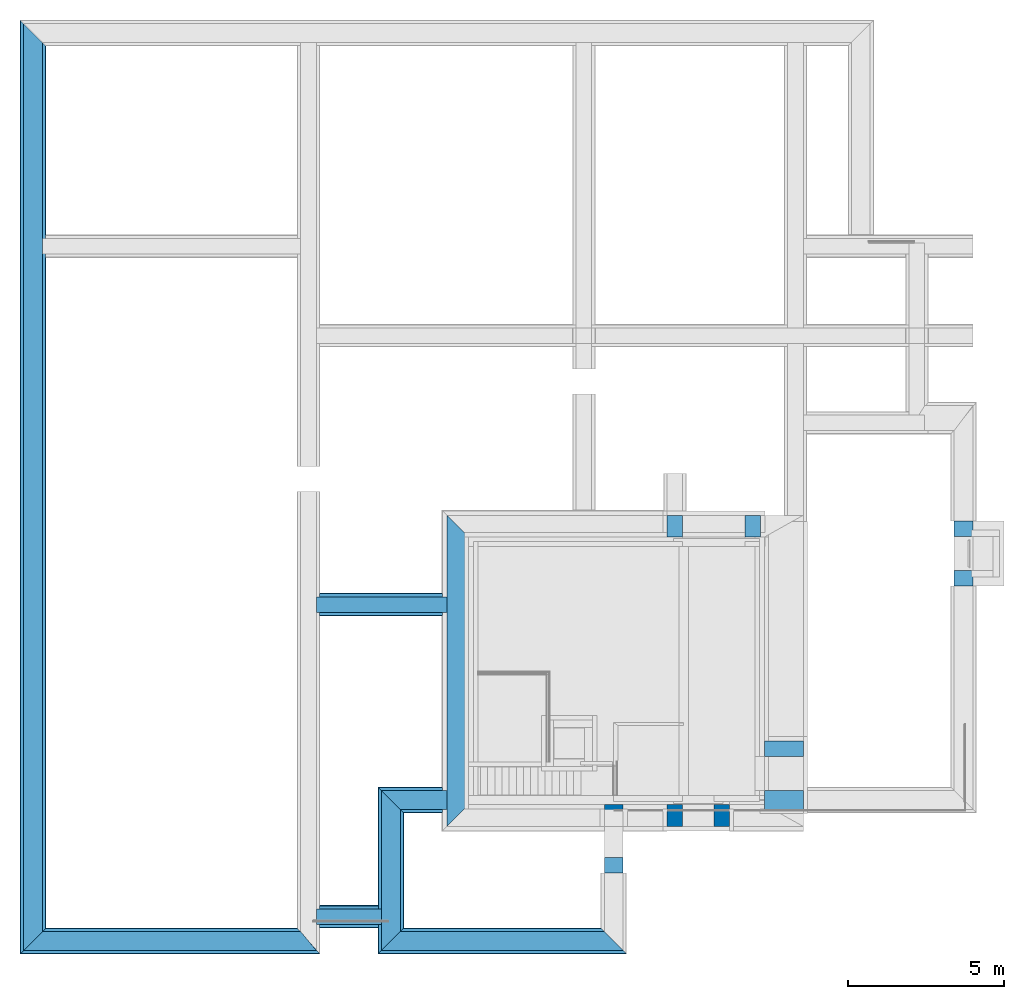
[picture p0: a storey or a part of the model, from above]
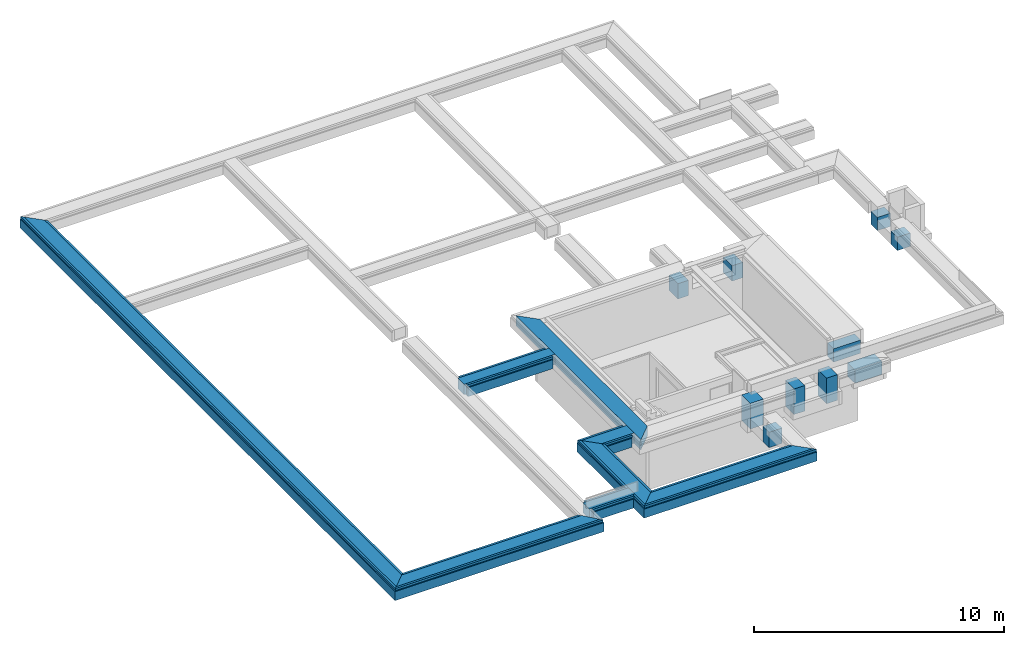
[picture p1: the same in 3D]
Properties of the parts of a building model (IFC2X3), part 6 of 7

# IfcRoof (31)
Name | In | Material | TotalArea (m2) | Isolatie - Kunststof hard, ThermalConductivity | Isolatie - Kunststof hard, SpecificHeatCapacity (J/kg/K) | Isolatie - Kunststof hard, MassDensity (kg/m3) | Isolatie - Kunststof hard, Embodied Energy | Isolatie - Kunststof hard, Embodied Carbon | Isolatie - Kunststof hard, Name | Isolatie - Kunststof hard, Participates in Collision Detection | Isolatie - Kunststof hard, Aardopwarmingsvermogen (GWP) | Isolatie - Kunststof hard, Ozonafbrekend Vermogen (ODP) = Isolatie - Kunststof hard, Fotochemische Vermogen tot Ozonvorming (POCP) = Isolatie - Kunststof hard, Abiotisch Uitputtingspotentieel (voor niet fossiele hulpbronnen) (ADPE) | Isolatie - Kunststof hard, Verzuringsvermogen (AP) | Isolatie - Kunststof hard, Eutrofiëringspotentieel (EP) | Isolatie - Kunststof hard, Abiotisch Uitputtingspotentieel (voor fossiele hulpbronnen) (ADPF) | Isolatie - Kunststof hard, Databron
27_Dak-x | Begane grond | Isolatie - Kunststof hard | 0.130758 | 0.029 | 1470 | 100 | 101.5 (MJ/kg) | 3.48 (kgCO₂/kg) | Isolatie - Kunststof hard | yes | 0.04 | 0 | 0.0000975 | 0.0000237 | 0.47 | https://www.oekobaudat.de/OEKOBAU.DAT/resource/processes/41e09ab7-0e73-4303-84fd-97cb0809db02?version=00.04.000
27_Dak-x | Begane grond | Isolatie - Kunststof hard | 0 | 0.029 | 1470 | 100 | 101.5 (MJ/kg) | 3.48 (kgCO₂/kg) | Isolatie - Kunststof hard | yes | 0.04 | 0 | 0.0000975 | 0.0000237 | 0.47 | https://www.oekobaudat.de/OEKOBAU.DAT/resource/processes/41e09ab7-0e73-4303-84fd-97cb0809db02?version=00.04.000
27_Dak-x | Begane grond | Isolatie - Kunststof hard | 0.136919 | 0.029 | 1470 | 100 | 101.5 (MJ/kg) | 3.48 (kgCO₂/kg) | Isolatie - Kunststof hard | yes | 0.04 | 0 | 0.0000975 | 0.0000237 | 0.47 | https://www.oekobaudat.de/OEKOBAU.DAT/resource/processes/41e09ab7-0e73-4303-84fd-97cb0809db02?version=00.04.000
27_Dak-x | Begane grond | Isolatie - Kunststof hard | 0.219275 | 0.029 | 1470 | 100 | 101.5 (MJ/kg) | 3.48 (kgCO₂/kg) | Isolatie - Kunststof hard | yes | 0.04 | 0 | 0.0000975 | 0.0000237 | 0.47 | https://www.oekobaudat.de/OEKOBAU.DAT/resource/processes/41e09ab7-0e73-4303-84fd-97cb0809db02?version=00.04.000
27_Dak-x | Begane grond | Isolatie - Kunststof hard | 0.0969175 | 0.029 | 1470 | 100 | 101.5 (MJ/kg) | 3.48 (kgCO₂/kg) | Isolatie - Kunststof hard | yes | 0.04 | 0 | 0.0000975 | 0.0000237 | 0.47 | https://www.oekobaudat.de/OEKOBAU.DAT/resource/processes/41e09ab7-0e73-4303-84fd-97cb0809db02?version=00.04.000
27_Dak-x | 1e verdieping | 47 waterdichte laag - bitumen | 26.366 | Material Properties - 47 waterdichte laag - bitumen, ThermalConductivity: 0.9; 47 waterdichte laag - bitumen, SpecificHeatCapacity: 840 J/kg/K; 47 waterdichte laag - bitumen, MassDensity: 1600 kg/m3; 47 waterdichte laag - bitumen, Embodied Energy: 3 (MJ/kg); 47 waterdichte laag - bitumen, Embodied Carbon: 0.23 (kgCO₂/kg); 47 waterdichte laag - bitumen, Name: 47 waterdichte laag - bitumen; 47 waterdichte laag - bitumen, Participates in Collision Detection: yes; 47 waterdichte laag - bitumen, Aardopwarmingsvermogen (GWP): 113; 47 waterdichte laag - bitumen, Ozonafbrekend Vermogen (ODP): 0; 47 waterdichte laag - bitumen, Fotochemische Vermogen tot Ozonvorming (POCP): 0.012; 47 waterdichte laag - bitumen, Verzuringsvermogen (AP): 0.094; 47 waterdichte laag - bitumen, Eutrofiëringspotentieel (EP): 0.0189; 47 waterdichte laag - bitumen, Abiotisch Uitputtingspotentieel (voor niet fossiele hulpbronnen) (ADPE): 0.0000099; 47 waterdichte laag - bitumen, Abiotisch Uitputtingspotentieel (voor fossiele hulpbronnen) (ADPF): 1150; 47 waterdichte laag - bitumen, Databron: https://www.oekobaudat.de/OEKOBAU.DAT/resource/processes/08dd0308-eebf-4db1-82ee-b340d070c9b9?version=00.06.000
27_Dak-x | 1e verdieping | 47 waterdichte laag - bitumen | 32.9855 | Material Properties - 47 waterdichte laag - bitumen, ThermalConductivity: 0.9; 47 waterdichte laag - bitumen, SpecificHeatCapacity: 840 J/kg/K; 47 waterdichte laag - bitumen, MassDensity: 1600 kg/m3; 47 waterdichte laag - bitumen, Embodied Energy: 3 (MJ/kg); 47 waterdichte laag - bitumen, Embodied Carbon: 0.23 (kgCO₂/kg); 47 waterdichte laag - bitumen, Name: 47 waterdichte laag - bitumen; 47 waterdichte laag - bitumen, Participates in Collision Detection: yes; 47 waterdichte laag - bitumen, Aardopwarmingsvermogen (GWP): 113; 47 waterdichte laag - bitumen, Ozonafbrekend Vermogen (ODP): 0; 47 waterdichte laag - bitumen, Fotochemische Vermogen tot Ozonvorming (POCP): 0.012; 47 waterdichte laag - bitumen, Verzuringsvermogen (AP): 0.094; 47 waterdichte laag - bitumen, Eutrofiëringspotentieel (EP): 0.0189; 47 waterdichte laag - bitumen, Abiotisch Uitputtingspotentieel (voor niet fossiele hulpbronnen) (ADPE): 0.0000099; 47 waterdichte laag - bitumen, Abiotisch Uitputtingspotentieel (voor fossiele hulpbronnen) (ADPF): 1150; 47 waterdichte laag - bitumen, Databron: https://www.oekobaudat.de/OEKOBAU.DAT/resource/processes/08dd0308-eebf-4db1-82ee-b340d070c9b9?version=00.06.000
27_Dak-x | 1e verdieping | 47 waterdichte laag - bitumen | 5.46311 | Material Properties - 47 waterdichte laag - bitumen, ThermalConductivity: 0.9; 47 waterdichte laag - bitumen, SpecificHeatCapacity: 840 J/kg/K; 47 waterdichte laag - bitumen, MassDensity: 1600 kg/m3; 47 waterdichte laag - bitumen, Embodied Energy: 3 (MJ/kg); 47 waterdichte laag - bitumen, Embodied Carbon: 0.23 (kgCO₂/kg); 47 waterdichte laag - bitumen, Name: 47 waterdichte laag - bitumen; 47 waterdichte laag - bitumen, Participates in Collision Detection: yes; 47 waterdichte laag - bitumen, Aardopwarmingsvermogen (GWP): 113; 47 waterdichte laag - bitumen, Ozonafbrekend Vermogen (ODP): 0; 47 waterdichte laag - bitumen, Fotochemische Vermogen tot Ozonvorming (POCP): 0.012; 47 waterdichte laag - bitumen, Verzuringsvermogen (AP): 0.094; 47 waterdichte laag - bitumen, Eutrofiëringspotentieel (EP): 0.0189; 47 waterdichte laag - bitumen, Abiotisch Uitputtingspotentieel (voor niet fossiele hulpbronnen) (ADPE): 0.0000099; 47 waterdichte laag - bitumen, Abiotisch Uitputtingspotentieel (voor fossiele hulpbronnen) (ADPF): 1150; 47 waterdichte laag - bitumen, Databron: https://www.oekobaudat.de/OEKOBAU.DAT/resource/processes/08dd0308-eebf-4db1-82ee-b340d070c9b9?version=00.06.000
27_Dak-x | 1e verdieping | 47 waterdichte laag - bitumen | 5.5376 | Material Properties - 47 waterdichte laag - bitumen, ThermalConductivity: 0.9; 47 waterdichte laag - bitumen, SpecificHeatCapacity: 840 J/kg/K; 47 waterdichte laag - bitumen, MassDensity: 1600 kg/m3; 47 waterdichte laag - bitumen, Embodied Energy: 3 (MJ/kg); 47 waterdichte laag - bitumen, Embodied Carbon: 0.23 (kgCO₂/kg); 47 waterdichte laag - bitumen, Name: 47 waterdichte laag - bitumen; 47 waterdichte laag - bitumen, Participates in Collision Detection: yes; 47 waterdichte laag - bitumen, Aardopwarmingsvermogen (GWP): 113; 47 waterdichte laag - bitumen, Ozonafbrekend Vermogen (ODP): 0; 47 waterdichte laag - bitumen, Fotochemische Vermogen tot Ozonvorming (POCP): 0.012; 47 waterdichte laag - bitumen, Verzuringsvermogen (AP): 0.094; 47 waterdichte laag - bitumen, Eutrofiëringspotentieel (EP): 0.0189; 47 waterdichte laag - bitumen, Abiotisch Uitputtingspotentieel (voor niet fossiele hulpbronnen) (ADPE): 0.0000099; 47 waterdichte laag - bitumen, Abiotisch Uitputtingspotentieel (voor fossiele hulpbronnen) (ADPF): 1150; 47 waterdichte laag - bitumen, Databron: https://www.oekobaudat.de/OEKOBAU.DAT/resource/processes/08dd0308-eebf-4db1-82ee-b340d070c9b9?version=00.06.000
27_Dak-x | 2e dakoverzicht | 47 waterdichte laag - bitumen | 74.9568 | Material Properties - 47 waterdichte laag - bitumen, ThermalConductivity: 0.9; 47 waterdichte laag - bitumen, SpecificHeatCapacity: 840 J/kg/K; 47 waterdichte laag - bitumen, MassDensity: 1600 kg/m3; 47 waterdichte laag - bitumen, Embodied Energy: 3 (MJ/kg); 47 waterdichte laag - bitumen, Embodied Carbon: 0.23 (kgCO₂/kg); 47 waterdichte laag - bitumen, Name: 47 waterdichte laag - bitumen; 47 waterdichte laag - bitumen, Participates in Collision Detection: yes; 47 waterdichte laag - bitumen, Aardopwarmingsvermogen (GWP): 113; 47 waterdichte laag - bitumen, Ozonafbrekend Vermogen (ODP): 0; 47 waterdichte laag - bitumen, Fotochemische Vermogen tot Ozonvorming (POCP): 0.012; 47 waterdichte laag - bitumen, Verzuringsvermogen (AP): 0.094; 47 waterdichte laag - bitumen, Eutrofiëringspotentieel (EP): 0.0189; 47 waterdichte laag - bitumen, Abiotisch Uitputtingspotentieel (voor niet fossiele hulpbronnen) (ADPE): 0.0000099; 47 waterdichte laag - bitumen, Abiotisch Uitputtingspotentieel (voor fossiele hulpbronnen) (ADPF): 1150; 47 waterdichte laag - bitumen, Databron: https://www.oekobaudat.de/OEKOBAU.DAT/resource/processes/08dd0308-eebf-4db1-82ee-b340d070c9b9?version=00.06.000
27_Dak-x | 2e dakoverzicht | Glas | 0.5225 | Material Properties - Glas, ThermalConductivity: 1.2; Glas, SpecificHeatCapacity: 795 J/kg/K; Glas, MassDensity: 2180 kg/m3; Glas, Embodied Energy: 15 (MJ/kg); Glas, Embodied Carbon: 0.86 (kgCO₂/kg); Glas, Name: Glas; Glas, Participates in Collision Detection: yes; Glas, Aardopwarmingsvermogen (GWP): 44.3346; Glas, Ozonafbrekend Vermogen (ODP): 0; Glas, Fotochemische Vermogen tot Ozonvorming (POCP): 0.0213557; Glas, Verzuringsvermogen (AP): 0.281643; Glas, Eutrofiëringspotentieel (EP): 0.0316879; Glas, Abiotisch Uitputtingspotentieel (voor niet fossiele hulpbronnen) (ADPE): 0.00000449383; Glas, Abiotisch Uitputtingspotentieel (voor fossiele hulpbronnen) (ADPF): 628.803; Glas, Databron: https://www.oekobaudat.de/OEKOBAU.DAT/resource/processes/1f2d6e42-9ffc-421d-990d-555eee4a7529?version=20.19.120
27_Dak-x | 2e dakoverzicht | Glas | 1.5759 | Material Properties - Glas, ThermalConductivity: 1.2; Glas, SpecificHeatCapacity: 795 J/kg/K; Glas, MassDensity: 2180 kg/m3; Glas, Embodied Energy: 15 (MJ/kg); Glas, Embodied Carbon: 0.86 (kgCO₂/kg); Glas, Name: Glas; Glas, Participates in Collision Detection: yes; Glas, Aardopwarmingsvermogen (GWP): 44.3346; Glas, Ozonafbrekend Vermogen (ODP): 0; Glas, Fotochemische Vermogen tot Ozonvorming (POCP): 0.0213557; Glas, Verzuringsvermogen (AP): 0.281643; Glas, Eutrofiëringspotentieel (EP): 0.0316879; Glas, Abiotisch Uitputtingspotentieel (voor niet fossiele hulpbronnen) (ADPE): 0.00000449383; Glas, Abiotisch Uitputtingspotentieel (voor fossiele hulpbronnen) (ADPF): 628.803; Glas, Databron: https://www.oekobaudat.de/OEKOBAU.DAT/resource/processes/1f2d6e42-9ffc-421d-990d-555eee4a7529?version=20.19.120
27_Dak-x | 2e dakoverzicht | 47 waterdichte laag - bitumen | 191.681 | Material Properties - 47 waterdichte laag - bitumen, ThermalConductivity: 0.9; 47 waterdichte laag - bitumen, SpecificHeatCapacity: 840 J/kg/K; 47 waterdichte laag - bitumen, MassDensity: 1600 kg/m3; 47 waterdichte laag - bitumen, Embodied Energy: 3 (MJ/kg); 47 waterdichte laag - bitumen, Embodied Carbon: 0.23 (kgCO₂/kg); 47 waterdichte laag - bitumen, Name: 47 waterdichte laag - bitumen; 47 waterdichte laag - bitumen, Participates in Collision Detection: yes; 47 waterdichte laag - bitumen, Aardopwarmingsvermogen (GWP): 113; 47 waterdichte laag - bitumen, Ozonafbrekend Vermogen (ODP): 0; 47 waterdichte laag - bitumen, Fotochemische Vermogen tot Ozonvorming (POCP): 0.012; 47 waterdichte laag - bitumen, Verzuringsvermogen (AP): 0.094; 47 waterdichte laag - bitumen, Eutrofiëringspotentieel (EP): 0.0189; 47 waterdichte laag - bitumen, Abiotisch Uitputtingspotentieel (voor niet fossiele hulpbronnen) (ADPE): 0.0000099; 47 waterdichte laag - bitumen, Abiotisch Uitputtingspotentieel (voor fossiele hulpbronnen) (ADPF): 1150; 47 waterdichte laag - bitumen, Databron: https://www.oekobaudat.de/OEKOBAU.DAT/resource/processes/08dd0308-eebf-4db1-82ee-b340d070c9b9?version=00.06.000
2 x 27_Dak-x | 2e dakoverzicht | 47 waterdichte laag - bitumen | 19.5294 | Material Properties - 47 waterdichte laag - bitumen, ThermalConductivity: 0.9; 47 waterdichte laag - bitumen, SpecificHeatCapacity: 840 J/kg/K; 47 waterdichte laag - bitumen, MassDensity: 1600 kg/m3; 47 waterdichte laag - bitumen, Embodied Energy: 3 (MJ/kg); 47 waterdichte laag - bitumen, Embodied Carbon: 0.23 (kgCO₂/kg); 47 waterdichte laag - bitumen, Name: 47 waterdichte laag - bitumen; 47 waterdichte laag - bitumen, Participates in Collision Detection: yes; 47 waterdichte laag - bitumen, Aardopwarmingsvermogen (GWP): 113; 47 waterdichte laag - bitumen, Ozonafbrekend Vermogen (ODP): 0; 47 waterdichte laag - bitumen, Fotochemische Vermogen tot Ozonvorming (POCP): 0.012; 47 waterdichte laag - bitumen, Verzuringsvermogen (AP): 0.094; 47 waterdichte laag - bitumen, Eutrofiëringspotentieel (EP): 0.0189; 47 waterdichte laag - bitumen, Abiotisch Uitputtingspotentieel (voor niet fossiele hulpbronnen) (ADPE): 0.0000099; 47 waterdichte laag - bitumen, Abiotisch Uitputtingspotentieel (voor fossiele hulpbronnen) (ADPF): 1150; 47 waterdichte laag - bitumen, Databron: https://www.oekobaudat.de/OEKOBAU.DAT/resource/processes/08dd0308-eebf-4db1-82ee-b340d070c9b9?version=00.06.000
2 x 27_Dak-x | 2e dakoverzicht | 47 waterdichte laag - bitumen | 147.967 | Material Properties - 47 waterdichte laag - bitumen, ThermalConductivity: 0.9; 47 waterdichte laag - bitumen, SpecificHeatCapacity: 840 J/kg/K; 47 waterdichte laag - bitumen, MassDensity: 1600 kg/m3; 47 waterdichte laag - bitumen, Embodied Energy: 3 (MJ/kg); 47 waterdichte laag - bitumen, Embodied Carbon: 0.23 (kgCO₂/kg); 47 waterdichte laag - bitumen, Name: 47 waterdichte laag - bitumen; 47 waterdichte laag - bitumen, Participates in Collision Detection: yes; 47 waterdichte laag - bitumen, Aardopwarmingsvermogen (GWP): 113; 47 waterdichte laag - bitumen, Ozonafbrekend Vermogen (ODP): 0; 47 waterdichte laag - bitumen, Fotochemische Vermogen tot Ozonvorming (POCP): 0.012; 47 waterdichte laag - bitumen, Verzuringsvermogen (AP): 0.094; 47 waterdichte laag - bitumen, Eutrofiëringspotentieel (EP): 0.0189; 47 waterdichte laag - bitumen, Abiotisch Uitputtingspotentieel (voor niet fossiele hulpbronnen) (ADPE): 0.0000099; 47 waterdichte laag - bitumen, Abiotisch Uitputtingspotentieel (voor fossiele hulpbronnen) (ADPF): 1150; 47 waterdichte laag - bitumen, Databron: https://www.oekobaudat.de/OEKOBAU.DAT/resource/processes/08dd0308-eebf-4db1-82ee-b340d070c9b9?version=00.06.000
27_Dak-x | 2e dakoverzicht | 47 waterdichte laag - bitumen | 128.558 | Material Properties - 47 waterdichte laag - bitumen, ThermalConductivity: 0.9; 47 waterdichte laag - bitumen, SpecificHeatCapacity: 840 J/kg/K; 47 waterdichte laag - bitumen, MassDensity: 1600 kg/m3; 47 waterdichte laag - bitumen, Embodied Energy: 3 (MJ/kg); 47 waterdichte laag - bitumen, Embodied Carbon: 0.23 (kgCO₂/kg); 47 waterdichte laag - bitumen, Name: 47 waterdichte laag - bitumen; 47 waterdichte laag - bitumen, Participates in Collision Detection: yes; 47 waterdichte laag - bitumen, Aardopwarmingsvermogen (GWP): 113; 47 waterdichte laag - bitumen, Ozonafbrekend Vermogen (ODP): 0; 47 waterdichte laag - bitumen, Fotochemische Vermogen tot Ozonvorming (POCP): 0.012; 47 waterdichte laag - bitumen, Verzuringsvermogen (AP): 0.094; 47 waterdichte laag - bitumen, Eutrofiëringspotentieel (EP): 0.0189; 47 waterdichte laag - bitumen, Abiotisch Uitputtingspotentieel (voor niet fossiele hulpbronnen) (ADPE): 0.0000099; 47 waterdichte laag - bitumen, Abiotisch Uitputtingspotentieel (voor fossiele hulpbronnen) (ADPF): 1150; 47 waterdichte laag - bitumen, Databron: https://www.oekobaudat.de/OEKOBAU.DAT/resource/processes/08dd0308-eebf-4db1-82ee-b340d070c9b9?version=00.06.000

# IfcSlab: 23 Geisoleerde kanaalplaat 260 380, _Vloer-x
In: Begane grond
CPset_Phasing - Renovation Phase: Bestaand
Pset_SlabCommon - IsExternal: no; LoadBearing: yes

# IfcSlab: 23 Kanaalplaat 260 260 (5)
Material: Beton gewapend prefab vloer
CPset_Phasing - Renovation Phase: Bestaand
Pset_SlabCommon - IsExternal: no; LoadBearing: yes
Material Properties - Beton gewapend prefab vloer, ThermalConductivity: 2.5; Beton gewapend prefab vloer, SpecificHeatCapacity: 1000 J/kg/K; Beton gewapend prefab vloer, MassDensity: 2400 kg/m3; Beton gewapend prefab vloer, Embodied Energy: 2.33 (MJ/kg); Beton gewapend prefab vloer, Embodied Carbon: 0.242 (kgCO₂/kg); Beton gewapend prefab vloer, Name: Beton gewapend prefab vloer; Beton gewapend prefab vloer, Participates in Collision Detection: yes
Name | In
_Vloer-x | Begane grond
3 x _Vloer-x | 1e verdieping
_Vloer-x | 2e dakoverzicht

# IfcSlab: 23 Zetwerk op Isolatie 63, _Vloer-x
In: 1e verdieping
Pset_SlabCommon - IsExternal: no; LoadBearing: yes
CPset_Phasing - Renovation Phase: Bestaand

# IfcSlab: 27 Dak isolatie 350, _Vloer-x
In: 2e dakoverzicht
CPset_Phasing - Renovation Phase: Bestaand
Pset_SlabCommon - IsExternal: no; LoadBearing: yes

# IfcSlab: 27 Dakterras isolatie 350 (2)
In: 1e verdieping
Pset_SlabCommon - IsExternal: no; LoadBearing: yes
CPset_Phasing - Renovation Phase: Bestaand

# IfcSlab: 27 HSB dak 192, _Vloer-x
In: 1e verdieping
CPset_Phasing - Renovation Phase: Bestaand
Pset_SlabCommon - IsExternal: no; LoadBearing: yes

# IfcSlab: 27 HSB dak voorgevel 189, _Vloer-x
In: 2e dakoverzicht
CPset_Phasing - Renovation Phase: Bestaand
Pset_SlabCommon - IsExternal: no; LoadBearing: yes

# IfcSlab: 43 Zwevende dekvloer 100 (19)
CPset_Phasing - Renovation Phase: Bestaand
Pset_SlabCommon - IsExternal: no; LoadBearing: no
Name | In
12 x _Vloer-x | Begane grond
7 x _Vloer-x | 1e verdieping

# IfcSlab: 45 Geisoleerd buiten plafond 160 176, _Vloer-x
In: Begane grond
Pset_SlabCommon - IsExternal: no; LoadBearing: yes
CPset_Phasing - Renovation Phase: Bestaand

# IfcSlab: 45 Geisoleerd buiten plafond 80 104, _Vloer-x
In: 2e dakoverzicht
CPset_Phasing - Renovation Phase: Bestaand
Pset_SlabCommon - IsExternal: no; LoadBearing: yes

# IfcSlab: 45 Geisoleerd plafond 90 104, f7 Vormvaste grondstoffen, gebonden met gips_Vloer-x
In: 2e dakoverzicht
Material: Gipsplaat
CPset_Phasing - Renovation Phase: Bestaand
Pset_SlabCommon - IsExternal: no; LoadBearing: yes
Material Properties - Gipsplaat, ThermalConductivity: 0.23; Gipsplaat, SpecificHeatCapacity: 840 J/kg/K; Gipsplaat, MassDensity: 800 kg/m3; Gipsplaat, Embodied Energy: 6.75 (MJ/kg); Gipsplaat, Embodied Carbon: 0.38 (kgCO₂/kg); Gipsplaat, Name: Gipsplaat; Gipsplaat, Participates in Collision Detection: yes; Gipsplaat, Aardopwarmingsvermogen (GWP): 1.513; Gipsplaat, Ozonafbrekend Vermogen (ODP): 1.32e-07; Gipsplaat, Fotochemische Vermogen tot Ozonvorming (POCP): 0.000358; Gipsplaat, Verzuringsvermogen (AP): 0.0082; Gipsplaat, Eutrofiëringspotentieel (EP): 0.00138; Gipsplaat, Abiotisch Uitputtingspotentieel (voor niet fossiele hulpbronnen) (ADPE): 0.00000729; Gipsplaat, Abiotisch Uitputtingspotentieel (voor fossiele hulpbronnen) (ADPF): 25.04; Gipsplaat, Databron: https://www.oekobaudat.de/OEKOBAU.DAT/resource/processes/1a24808b-9116-422e-93fb-d435f74a038a?version=00.05.000

# IfcSlab: ALG - BINNENAFWERKING 1337, _Vloer-x
In: 1e verdieping
Material: ALG - BINNENAFWERKING
CPset_Phasing - Renovation Phase: Bestaand
Pset_SlabCommon - IsExternal: no; LoadBearing: yes
Material Properties - ALG - BINNENAFWERKING, ThermalConductivity: 0.27; ALG - BINNENAFWERKING, SpecificHeatCapacity: 840 J/kg/K; ALG - BINNENAFWERKING, MassDensity: 800 kg/m3; ALG - BINNENAFWERKING, Embodied Energy: 2 (MJ/kg); ALG - BINNENAFWERKING, Embodied Carbon: 0.13 (kgCO₂/kg); ALG - BINNENAFWERKING, Name: ALG - BINNENAFWERKING; ALG - BINNENAFWERKING, Participates in Collision Detection: yes

# IfcSlab: ALG - BINNENAFWERKING 2100, _Vloer-x
In: 1e verdieping
Material: ALG - BINNENAFWERKING
CPset_Phasing - Renovation Phase: Bestaand
Material Properties - ALG - BINNENAFWERKING, ThermalConductivity: 0.27; ALG - BINNENAFWERKING, SpecificHeatCapacity: 840 J/kg/K; ALG - BINNENAFWERKING, MassDensity: 800 kg/m3; ALG - BINNENAFWERKING, Embodied Energy: 2 (MJ/kg); ALG - BINNENAFWERKING, Embodied Carbon: 0.13 (kgCO₂/kg); ALG - BINNENAFWERKING, Name: ALG - BINNENAFWERKING; ALG - BINNENAFWERKING, Participates in Collision Detection: yes
Pset_SlabCommon - IsExternal: no; LoadBearing: yes

# IfcSlab: ALG - BINNENAFWERKING 900, _Vloer-x
In: 1e verdieping
Material: ALG - BINNENAFWERKING
CPset_Phasing - Renovation Phase: Bestaand
Material Properties - ALG - BINNENAFWERKING, ThermalConductivity: 0.27; ALG - BINNENAFWERKING, SpecificHeatCapacity: 840 J/kg/K; ALG - BINNENAFWERKING, MassDensity: 800 kg/m3; ALG - BINNENAFWERKING, Embodied Energy: 2 (MJ/kg); ALG - BINNENAFWERKING, Embodied Carbon: 0.13 (kgCO₂/kg); ALG - BINNENAFWERKING, Name: ALG - BINNENAFWERKING; ALG - BINNENAFWERKING, Participates in Collision Detection: yes
Pset_SlabCommon - IsExternal: no; LoadBearing: yes

# IfcSlab: Beton C 50 (2)
In: 1e verdieping
Material: Beton C
Pset_SlabCommon - IsExternal: no; LoadBearing: yes
Material Properties - Beton C, ThermalConductivity: 2; Beton C, SpecificHeatCapacity: 840 J/kg/K; Beton C, MassDensity: 2400 kg/m3; Beton C, Embodied Energy: 0.75 (MJ/kg); Beton C, Embodied Carbon: 0.1 (kgCO₂/kg); Beton C, Name: Beton C; Beton C, Participates in Collision Detection: yes; Beton C, Aardopwarmingsvermogen (GWP): 1.27649; Beton C, Ozonafbrekend Vermogen (ODP): 0; Beton C, Fotochemische Vermogen tot Ozonvorming (POCP): -0.000842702; Beton C, Verzuringsvermogen (AP): 0.00257837; Beton C, Eutrofiëringspotentieel (EP): 0.000612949; Beton C, Abiotisch Uitputtingspotentieel (voor niet fossiele hulpbronnen) (ADPE): 1.07417e-07; Beton C, Abiotisch Uitputtingspotentieel (voor fossiele hulpbronnen) (ADPF): 17.1106; Beton C, Databron: https://www.oekobaudat.de/OEKOBAU.DAT/resource/processes/d3b59cac-3b4e-4d18-8c3a-780b553c9591?version=20.19.120
CPset_Phasing - Renovation Phase: Bestaand

# IfcSlab: Beton gewapend C 100, f2- Met cement gebonden producten (alle vulmiddelen)_Vloer-x
In: Begane grond
Material: Beton gewapend C
Pset_SlabCommon - IsExternal: no; LoadBearing: yes
CPset_Phasing - Renovation Phase: Bestaand
Material Properties - Beton gewapend C, ThermalConductivity: 2.3; Beton gewapend C, SpecificHeatCapacity: 1000 J/kg/K; Beton gewapend C, MassDensity: 2300 kg/m3; Beton gewapend C, Embodied Energy: 1.92 (MJ/kg); Beton gewapend C, Embodied Carbon: 0.198 (kgCO₂/kg); Beton gewapend C, Name: Beton gewapend C; Beton gewapend C, Participates in Collision Detection: yes; Beton gewapend C, Aardopwarmingsvermogen (GWP): -1.02642; Beton gewapend C, Ozonafbrekend Vermogen (ODP): 0; Beton gewapend C, Fotochemische Vermogen tot Ozonvorming (POCP): 0.000222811; Beton gewapend C, Verzuringsvermogen (AP): -0.00242385; Beton gewapend C, Eutrofiëringspotentieel (EP): -0.000471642; Beton gewapend C, Abiotisch Uitputtingspotentieel (voor niet fossiele hulpbronnen) (ADPE): -2.28121e-07; Beton gewapend C, Abiotisch Uitputtingspotentieel (voor fossiele hulpbronnen) (ADPF): -12.4095; Beton gewapend C, Databron: https://www.oekobaudat.de/OEKOBAU.DAT/resource/processes/d3b59cac-3b4e-4d18-8c3a-780b553c9591?version=20.19.120

# IfcSlab: Beton gewapend C vloer 120, f2- Met cement gebonden producten (alle vulmiddelen)_Vloer-x
In: 1e verdieping
Material: Beton gewapend C vloer
CPset_Phasing - Renovation Phase: Bestaand
Pset_SlabCommon - IsExternal: no; LoadBearing: yes
Material Properties - Beton gewapend C vloer, ThermalConductivity: 2.5; Beton gewapend C vloer, SpecificHeatCapacity: 1000 J/kg/K; Beton gewapend C vloer, MassDensity: 2400 kg/m3; Beton gewapend C vloer, Embodied Energy: 2.33 (MJ/kg); Beton gewapend C vloer, Embodied Carbon: 0.242 (kgCO₂/kg); Beton gewapend C vloer, Name: Beton gewapend C vloer; Beton gewapend C vloer, Participates in Collision Detection: yes

# IfcSlab: Beton gewapend C vloer 180 (6)
In: Begane grond
Material: Beton gewapend C vloer
Pset_SlabCommon - IsExternal: no; LoadBearing: yes
Material Properties - Beton gewapend C vloer, ThermalConductivity: 2.5; Beton gewapend C vloer, SpecificHeatCapacity: 1000 J/kg/K; Beton gewapend C vloer, MassDensity: 2400 kg/m3; Beton gewapend C vloer, Embodied Energy: 2.33 (MJ/kg); Beton gewapend C vloer, Embodied Carbon: 0.242 (kgCO₂/kg); Beton gewapend C vloer, Name: Beton gewapend C vloer; Beton gewapend C vloer, Participates in Collision Detection: yes
CPset_Phasing - Renovation Phase: Bestaand

# IfcSlab: Beton gewapend C vloer 230, f2- Met cement gebonden producten (alle vulmiddelen)_Vloer-x
In: Begane grond
Material: Beton gewapend C vloer
CPset_Phasing - Renovation Phase: Bestaand
Pset_SlabCommon - IsExternal: no; LoadBearing: yes
Material Properties - Beton gewapend C vloer, ThermalConductivity: 2.5; Beton gewapend C vloer, SpecificHeatCapacity: 1000 J/kg/K; Beton gewapend C vloer, MassDensity: 2400 kg/m3; Beton gewapend C vloer, Embodied Energy: 2.33 (MJ/kg); Beton gewapend C vloer, Embodied Carbon: 0.242 (kgCO₂/kg); Beton gewapend C vloer, Name: Beton gewapend C vloer; Beton gewapend C vloer, Participates in Collision Detection: yes

# IfcSlab: Beton gewapend prefab vloer 260, _Vloer-x
In: 1e verdieping
Material: Beton gewapend prefab vloer
Pset_SlabCommon - IsExternal: no; LoadBearing: yes
CPset_Phasing - Renovation Phase: Bestaand
Material Properties - Beton gewapend prefab vloer, ThermalConductivity: 2.5; Beton gewapend prefab vloer, SpecificHeatCapacity: 1000 J/kg/K; Beton gewapend prefab vloer, MassDensity: 2400 kg/m3; Beton gewapend prefab vloer, Embodied Energy: 2.33 (MJ/kg); Beton gewapend prefab vloer, Embodied Carbon: 0.242 (kgCO₂/kg); Beton gewapend prefab vloer, Name: Beton gewapend prefab vloer; Beton gewapend prefab vloer, Participates in Collision Detection: yes

# IfcSlab: Cementgebonden plaatmateriaal 12 (2)
Material: Cementgebonden plaatmateriaal
CPset_Phasing - Renovation Phase: Bestaand
Material Properties - Cementgebonden plaatmateriaal, ThermalConductivity: 0.45; Cementgebonden plaatmateriaal, SpecificHeatCapacity: 840 J/kg/K; Cementgebonden plaatmateriaal, MassDensity: 1400 kg/m3; Cementgebonden plaatmateriaal, Embodied Energy: 6.75 (MJ/kg); Cementgebonden plaatmateriaal, Embodied Carbon: 0.38 (kgCO₂/kg); Cementgebonden plaatmateriaal, Name: Cementgebonden plaatmateriaal; Cementgebonden plaatmateriaal, Participates in Collision Detection: yes; Cementgebonden plaatmateriaal, Aardopwarmingsvermogen (GWP): 1.62283; Cementgebonden plaatmateriaal, Ozonafbrekend Vermogen (ODP): 0; Cementgebonden plaatmateriaal, Fotochemische Vermogen tot Ozonvorming (POCP): 33.9565; Cementgebonden plaatmateriaal, Verzuringsvermogen (AP): 0.000135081; Cementgebonden plaatmateriaal, Eutrofiëringspotentieel (EP): 0.00274111; Cementgebonden plaatmateriaal, Abiotisch Uitputtingspotentieel (voor niet fossiele hulpbronnen) (ADPE): 0; Cementgebonden plaatmateriaal, Abiotisch Uitputtingspotentieel (voor fossiele hulpbronnen) (ADPF): 0.000893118; Cementgebonden plaatmateriaal, Databron: https://www.oekobaudat.de/OEKOBAU.DAT/resource/processes/07423e99-8c7c-4e93-8311-dcf7ae85c41d?version=20.20.010
Pset_SlabCommon - IsExternal: no; LoadBearing: yes
Name | In
f7 Vormvaste grondstoffen, gebonden met gips_Vloer-x | 1e verdieping
f7 Vormvaste grondstoffen, gebonden met gips_Vloer-x | 2e dakoverzicht

# IfcSlab: Gipsplaat 12 (24)
Material: Gipsplaat
CPset_Phasing - Renovation Phase: Bestaand
Pset_SlabCommon - IsExternal: no; LoadBearing: yes
Material Properties - Gipsplaat, ThermalConductivity: 0.23; Gipsplaat, SpecificHeatCapacity: 840 J/kg/K; Gipsplaat, MassDensity: 800 kg/m3; Gipsplaat, Embodied Energy: 6.75 (MJ/kg); Gipsplaat, Embodied Carbon: 0.38 (kgCO₂/kg); Gipsplaat, Name: Gipsplaat; Gipsplaat, Participates in Collision Detection: yes; Gipsplaat, Aardopwarmingsvermogen (GWP): 1.513; Gipsplaat, Ozonafbrekend Vermogen (ODP): 1.32e-07; Gipsplaat, Fotochemische Vermogen tot Ozonvorming (POCP): 0.000358; Gipsplaat, Verzuringsvermogen (AP): 0.0082; Gipsplaat, Eutrofiëringspotentieel (EP): 0.00138; Gipsplaat, Abiotisch Uitputtingspotentieel (voor niet fossiele hulpbronnen) (ADPE): 0.00000729; Gipsplaat, Abiotisch Uitputtingspotentieel (voor fossiele hulpbronnen) (ADPF): 25.04; Gipsplaat, Databron: https://www.oekobaudat.de/OEKOBAU.DAT/resource/processes/1a24808b-9116-422e-93fb-d435f74a038a?version=00.05.000
Name | In
15 x f7 Vormvaste grondstoffen, gebonden met gips_Vloer-x | Begane grond
9 x f7 Vormvaste grondstoffen, gebonden met gips_Vloer-x | 1e verdieping

# IfcSlab: Gipsplaat 25 (2)
In: 1e verdieping
Material: Gipsplaat
Material Properties - Gipsplaat, ThermalConductivity: 0.23; Gipsplaat, SpecificHeatCapacity: 840 J/kg/K; Gipsplaat, MassDensity: 800 kg/m3; Gipsplaat, Embodied Energy: 6.75 (MJ/kg); Gipsplaat, Embodied Carbon: 0.38 (kgCO₂/kg); Gipsplaat, Name: Gipsplaat; Gipsplaat, Participates in Collision Detection: yes; Gipsplaat, Aardopwarmingsvermogen (GWP): 1.513; Gipsplaat, Ozonafbrekend Vermogen (ODP): 1.32e-07; Gipsplaat, Fotochemische Vermogen tot Ozonvorming (POCP): 0.000358; Gipsplaat, Verzuringsvermogen (AP): 0.0082; Gipsplaat, Eutrofiëringspotentieel (EP): 0.00138; Gipsplaat, Abiotisch Uitputtingspotentieel (voor niet fossiele hulpbronnen) (ADPE): 0.00000729; Gipsplaat, Abiotisch Uitputtingspotentieel (voor fossiele hulpbronnen) (ADPF): 25.04; Gipsplaat, Databron: https://www.oekobaudat.de/OEKOBAU.DAT/resource/processes/1a24808b-9116-422e-93fb-d435f74a038a?version=00.05.000
Pset_SlabCommon - IsExternal: no; LoadBearing: yes
CPset_Phasing - Renovation Phase: Bestaand

# IfcSlab: Gipsplaat 33, f7 Vormvaste grondstoffen, gebonden met gips_Vloer-x
In: 1e verdieping
Material: Gipsplaat
CPset_Phasing - Renovation Phase: Bestaand
Pset_SlabCommon - IsExternal: no; LoadBearing: yes
Material Properties - Gipsplaat, ThermalConductivity: 0.23; Gipsplaat, SpecificHeatCapacity: 840 J/kg/K; Gipsplaat, MassDensity: 800 kg/m3; Gipsplaat, Embodied Energy: 6.75 (MJ/kg); Gipsplaat, Embodied Carbon: 0.38 (kgCO₂/kg); Gipsplaat, Name: Gipsplaat; Gipsplaat, Participates in Collision Detection: yes; Gipsplaat, Aardopwarmingsvermogen (GWP): 1.513; Gipsplaat, Ozonafbrekend Vermogen (ODP): 1.32e-07; Gipsplaat, Fotochemische Vermogen tot Ozonvorming (POCP): 0.000358; Gipsplaat, Verzuringsvermogen (AP): 0.0082; Gipsplaat, Eutrofiëringspotentieel (EP): 0.00138; Gipsplaat, Abiotisch Uitputtingspotentieel (voor niet fossiele hulpbronnen) (ADPE): 0.00000729; Gipsplaat, Abiotisch Uitputtingspotentieel (voor fossiele hulpbronnen) (ADPF): 25.04; Gipsplaat, Databron: https://www.oekobaudat.de/OEKOBAU.DAT/resource/processes/1a24808b-9116-422e-93fb-d435f74a038a?version=00.05.000

# IfcSlab: Hout - Multiplex 180, i4 In lagen verlijmd hout_Vloer-x
In: Begane grond
Material: Hout - Multiplex
CPset_Phasing - Renovation Phase: Bestaand
Pset_SlabCommon - IsExternal: no; LoadBearing: yes
Material Properties - Hout - Multiplex, ThermalConductivity: 0.17; Hout - Multiplex, SpecificHeatCapacity: 1600 J/kg/K; Hout - Multiplex, MassDensity: 700 kg/m3; Hout - Multiplex, Embodied Energy: 15 (MJ/kg); Hout - Multiplex, Embodied Carbon: 0.77 (kgCO₂/kg); Hout - Multiplex, Name: Hout - Multiplex; Hout - Multiplex, Participates in Collision Detection: yes; Hout - Multiplex, Aardopwarmingsvermogen (GWP): -32.4496; Hout - Multiplex, Ozonafbrekend Vermogen (ODP): 0; Hout - Multiplex, Fotochemische Vermogen tot Ozonvorming (POCP): -0.00287346; Hout - Multiplex, Verzuringsvermogen (AP): 0.138611; Hout - Multiplex, Eutrofiëringspotentieel (EP): 0.0523292; Hout - Multiplex, Abiotisch Uitputtingspotentieel (voor niet fossiele hulpbronnen) (ADPE): -0.0000777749; Hout - Multiplex, Abiotisch Uitputtingspotentieel (voor fossiele hulpbronnen) (ADPF): -4006.31; Hout - Multiplex, Databron: https://www.oekobaudat.de/OEKOBAU.DAT/resource/processes/cc180aec-8a5c-4e07-b1a0-1ab81dd746ac?version=20.20.120

# IfcSlab: Hout - Multiplex 20 (48)
Material: Hout - Multiplex
CPset_Phasing - Renovation Phase: Bestaand
Pset_SlabCommon - IsExternal: no; LoadBearing: yes
Material Properties - Hout - Multiplex, ThermalConductivity: 0.17; Hout - Multiplex, SpecificHeatCapacity: 1600 J/kg/K; Hout - Multiplex, MassDensity: 700 kg/m3; Hout - Multiplex, Embodied Energy: 15 (MJ/kg); Hout - Multiplex, Embodied Carbon: 0.77 (kgCO₂/kg); Hout - Multiplex, Name: Hout - Multiplex; Hout - Multiplex, Participates in Collision Detection: yes; Hout - Multiplex, Aardopwarmingsvermogen (GWP): -32.4496; Hout - Multiplex, Ozonafbrekend Vermogen (ODP): 0; Hout - Multiplex, Fotochemische Vermogen tot Ozonvorming (POCP): -0.00287346; Hout - Multiplex, Verzuringsvermogen (AP): 0.138611; Hout - Multiplex, Eutrofiëringspotentieel (EP): 0.0523292; Hout - Multiplex, Abiotisch Uitputtingspotentieel (voor niet fossiele hulpbronnen) (ADPE): -0.0000777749; Hout - Multiplex, Abiotisch Uitputtingspotentieel (voor fossiele hulpbronnen) (ADPF): -4006.31; Hout - Multiplex, Databron: https://www.oekobaudat.de/OEKOBAU.DAT/resource/processes/cc180aec-8a5c-4e07-b1a0-1ab81dd746ac?version=20.20.120
Name | In
19 x i4 In lagen verlijmd hout_Vloer-x | Begane grond
29 x i4 In lagen verlijmd hout_Vloer-x | 1e verdieping

# IfcSlab: Hout - Multiplex 830, i4 In lagen verlijmd hout_Vloer-x
In: Begane grond
Material: Hout - Multiplex
CPset_Phasing - Renovation Phase: Bestaand
Pset_SlabCommon - IsExternal: no; LoadBearing: yes
Material Properties - Hout - Multiplex, ThermalConductivity: 0.17; Hout - Multiplex, SpecificHeatCapacity: 1600 J/kg/K; Hout - Multiplex, MassDensity: 700 kg/m3; Hout - Multiplex, Embodied Energy: 15 (MJ/kg); Hout - Multiplex, Embodied Carbon: 0.77 (kgCO₂/kg); Hout - Multiplex, Name: Hout - Multiplex; Hout - Multiplex, Participates in Collision Detection: yes; Hout - Multiplex, Aardopwarmingsvermogen (GWP): -32.4496; Hout - Multiplex, Ozonafbrekend Vermogen (ODP): 0; Hout - Multiplex, Fotochemische Vermogen tot Ozonvorming (POCP): -0.00287346; Hout - Multiplex, Verzuringsvermogen (AP): 0.138611; Hout - Multiplex, Eutrofiëringspotentieel (EP): 0.0523292; Hout - Multiplex, Abiotisch Uitputtingspotentieel (voor niet fossiele hulpbronnen) (ADPE): -0.0000777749; Hout - Multiplex, Abiotisch Uitputtingspotentieel (voor fossiele hulpbronnen) (ADPF): -4006.31; Hout - Multiplex, Databron: https://www.oekobaudat.de/OEKOBAU.DAT/resource/processes/cc180aec-8a5c-4e07-b1a0-1ab81dd746ac?version=20.20.120

# IfcSlab: Hout AFW 18 (36)
Material: Hout AFW
CPset_Phasing - Renovation Phase: Bestaand
Pset_SlabCommon - IsExternal: no; LoadBearing: no
Material Properties - Hout AFW, ThermalConductivity: 0.14; Hout AFW, SpecificHeatCapacity: 1880 J/kg/K; Hout AFW, MassDensity: 550 kg/m3; Hout AFW, Embodied Energy: 7.4 (MJ/kg); Hout AFW, Embodied Carbon: 0.19 (kgCO₂/kg); Hout AFW, Name: Hout AFW; Hout AFW, Participates in Collision Detection: yes
Name | In
17 x i HOUT_Vloer-x | Begane grond
19 x i HOUT_Vloer-x | 1e verdieping

# IfcSlab: Hout AFW 20, i HOUT_Vloer-x
In: 1e verdieping
Material: Hout AFW
Material Properties - Hout AFW, ThermalConductivity: 0.14; Hout AFW, SpecificHeatCapacity: 1880 J/kg/K; Hout AFW, MassDensity: 550 kg/m3; Hout AFW, Embodied Energy: 7.4 (MJ/kg); Hout AFW, Embodied Carbon: 0.19 (kgCO₂/kg); Hout AFW, Name: Hout AFW; Hout AFW, Participates in Collision Detection: yes
CPset_Phasing - Renovation Phase: Bestaand
Pset_SlabCommon - IsExternal: no; LoadBearing: yes

# IfcSlab: Hout AFW 90, i HOUT_Vloer-x
In: 1e verdieping
Material: Hout AFW
CPset_Phasing - Renovation Phase: Bestaand
Material Properties - Hout AFW, ThermalConductivity: 0.14; Hout AFW, SpecificHeatCapacity: 1880 J/kg/K; Hout AFW, MassDensity: 550 kg/m3; Hout AFW, Embodied Energy: 7.4 (MJ/kg); Hout AFW, Embodied Carbon: 0.19 (kgCO₂/kg); Hout AFW, Name: Hout AFW; Hout AFW, Participates in Collision Detection: yes
Pset_SlabCommon - IsExternal: no; LoadBearing: yes

# IfcSlab: IfcSlab (3)
In: Begane grond
Type - PredefinedType: LANDING
CPset_Phasing - Renovation Phase: Bestaand
Name | Material | Beton gewapend prefab, ThermalConductivity | Beton gewapend prefab, SpecificHeatCapacity (J/kg/K) | Beton gewapend prefab, MassDensity (kg/m3) | Beton gewapend prefab, Embodied Energy | Beton gewapend prefab, Embodied Carbon | Beton gewapend prefab, Name | Beton gewapend prefab, Participates in Collision Detection | Beton gewapend prefab, Aardopwarmingsvermogen (GWP) | Beton gewapend prefab, Ozonafbrekend Vermogen (ODP) | Beton gewapend prefab, Fotochemische Vermogen tot Ozonvorming (POCP) | Beton gewapend prefab, Verzuringsvermogen (AP) | Beton gewapend prefab, Eutrofiëringspotentieel (EP) | Beton gewapend prefab, Abiotisch Uitputtingspotentieel (voor niet fossiele hulpbronnen) (ADPE) | Beton gewapend prefab, Abiotisch Uitputtingspotentieel (voor fossiele hulpbronnen) (ADPF) | Beton gewapend prefab, Databron
2 x 24_Trapconstructie-x | Beton gewapend prefab | 2.5 | 1000 | 2400 | 2.33 (MJ/kg) | 0.242 (kgCO₂/kg) | Beton gewapend prefab | yes | 129.993 | 0 | 0.00471246 | 0.182012 | 0.0346685 | 0.000140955 | 604.803 | https://www.oekobaudat.de/OEKOBAU.DAT/resource/processes/3470c523-ffcd-48df-93ff-dedfde86572a?version=20.19.010
24_Trapconstructie-x | Beton C | Material Properties - Beton C, ThermalConductivity: 2; Beton C, SpecificHeatCapacity: 840 J/kg/K; Beton C, MassDensity: 2400 kg/m3; Beton C, Embodied Energy: 0.75 (MJ/kg); Beton C, Embodied Carbon: 0.1 (kgCO₂/kg); Beton C, Name: Beton C; Beton C, Participates in Collision Detection: yes; Beton C, Aardopwarmingsvermogen (GWP): 1.27649; Beton C, Ozonafbrekend Vermogen (ODP): 0; Beton C, Fotochemische Vermogen tot Ozonvorming (POCP): -0.000842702; Beton C, Verzuringsvermogen (AP): 0.00257837; Beton C, Eutrofiëringspotentieel (EP): 0.000612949; Beton C, Abiotisch Uitputtingspotentieel (voor niet fossiele hulpbronnen) (ADPE): 1.07417e-07; Beton C, Abiotisch Uitputtingspotentieel (voor fossiele hulpbronnen) (ADPF): 17.1106; Beton C, Databron: https://www.oekobaudat.de/OEKOBAU.DAT/resource/processes/d3b59cac-3b4e-4d18-8c3a-780b553c9591?version=20.19.120

# IfcSlab: Isolatie - Kunststof hard 100, n7 Kunststof met cellenstructuur_Vloer-x
In: 2e dakoverzicht
Material: Isolatie - Kunststof hard
CPset_Phasing - Renovation Phase: Bestaand
Material Properties - Isolatie - Kunststof hard, ThermalConductivity: 0.029; Isolatie - Kunststof hard, SpecificHeatCapacity: 1470 J/kg/K; Isolatie - Kunststof hard, MassDensity: 100 kg/m3; Isolatie - Kunststof hard, Embodied Energy: 101.5 (MJ/kg); Isolatie - Kunststof hard, Embodied Carbon: 3.48 (kgCO₂/kg); Isolatie - Kunststof hard, Name: Isolatie - Kunststof hard; Isolatie - Kunststof hard, Participates in Collision Detection: yes; Isolatie - Kunststof hard, Aardopwarmingsvermogen (GWP): 0.04; Isolatie - Kunststof hard, Ozonafbrekend Vermogen (ODP): 0; Isolatie - Kunststof hard, Fotochemische Vermogen tot Ozonvorming (POCP): 0; Isolatie - Kunststof hard, Verzuringsvermogen (AP): 0.0000975; Isolatie - Kunststof hard, Eutrofiëringspotentieel (EP): 0.0000237; Isolatie - Kunststof hard, Abiotisch Uitputtingspotentieel (voor niet fossiele hulpbronnen) (ADPE): 0; Isolatie - Kunststof hard, Abiotisch Uitputtingspotentieel (voor fossiele hulpbronnen) (ADPF): 0.47; Isolatie - Kunststof hard, Databron: https://www.oekobaudat.de/OEKOBAU.DAT/resource/processes/41e09ab7-0e73-4303-84fd-97cb0809db02?version=00.04.000
Pset_SlabCommon - IsExternal: no; LoadBearing: no

# IfcSlab: Isolatie - Kunststof hard 145, n7 Kunststof met cellenstructuur_Vloer-x
In: 2e dakoverzicht
Material: Isolatie - Kunststof hard
CPset_Phasing - Renovation Phase: Bestaand
Pset_SlabCommon - IsExternal: no; LoadBearing: yes
Material Properties - Isolatie - Kunststof hard, ThermalConductivity: 0.029; Isolatie - Kunststof hard, SpecificHeatCapacity: 1470 J/kg/K; Isolatie - Kunststof hard, MassDensity: 100 kg/m3; Isolatie - Kunststof hard, Embodied Energy: 101.5 (MJ/kg); Isolatie - Kunststof hard, Embodied Carbon: 3.48 (kgCO₂/kg); Isolatie - Kunststof hard, Name: Isolatie - Kunststof hard; Isolatie - Kunststof hard, Participates in Collision Detection: yes; Isolatie - Kunststof hard, Aardopwarmingsvermogen (GWP): 0.04; Isolatie - Kunststof hard, Ozonafbrekend Vermogen (ODP): 0; Isolatie - Kunststof hard, Fotochemische Vermogen tot Ozonvorming (POCP): 0; Isolatie - Kunststof hard, Verzuringsvermogen (AP): 0.0000975; Isolatie - Kunststof hard, Eutrofiëringspotentieel (EP): 0.0000237; Isolatie - Kunststof hard, Abiotisch Uitputtingspotentieel (voor niet fossiele hulpbronnen) (ADPE): 0; Isolatie - Kunststof hard, Abiotisch Uitputtingspotentieel (voor fossiele hulpbronnen) (ADPF): 0.47; Isolatie - Kunststof hard, Databron: https://www.oekobaudat.de/OEKOBAU.DAT/resource/processes/41e09ab7-0e73-4303-84fd-97cb0809db02?version=00.04.000

# IfcSlab: Isolatie - Kunststof hard 170, n7 Kunststof met cellenstructuur_Vloer-x
In: 1e verdieping
Material: Isolatie - Kunststof hard
CPset_Phasing - Renovation Phase: Bestaand
Material Properties - Isolatie - Kunststof hard, ThermalConductivity: 0.029; Isolatie - Kunststof hard, SpecificHeatCapacity: 1470 J/kg/K; Isolatie - Kunststof hard, MassDensity: 100 kg/m3; Isolatie - Kunststof hard, Embodied Energy: 101.5 (MJ/kg); Isolatie - Kunststof hard, Embodied Carbon: 3.48 (kgCO₂/kg); Isolatie - Kunststof hard, Name: Isolatie - Kunststof hard; Isolatie - Kunststof hard, Participates in Collision Detection: yes; Isolatie - Kunststof hard, Aardopwarmingsvermogen (GWP): 0.04; Isolatie - Kunststof hard, Ozonafbrekend Vermogen (ODP): 0; Isolatie - Kunststof hard, Fotochemische Vermogen tot Ozonvorming (POCP): 0; Isolatie - Kunststof hard, Verzuringsvermogen (AP): 0.0000975; Isolatie - Kunststof hard, Eutrofiëringspotentieel (EP): 0.0000237; Isolatie - Kunststof hard, Abiotisch Uitputtingspotentieel (voor niet fossiele hulpbronnen) (ADPE): 0; Isolatie - Kunststof hard, Abiotisch Uitputtingspotentieel (voor fossiele hulpbronnen) (ADPF): 0.47; Isolatie - Kunststof hard, Databron: https://www.oekobaudat.de/OEKOBAU.DAT/resource/processes/41e09ab7-0e73-4303-84fd-97cb0809db02?version=00.04.000
Pset_SlabCommon - IsExternal: no; LoadBearing: yes

# IfcSlab: Isolatie - Kunststof hard 78, n7 Kunststof met cellenstructuur_Vloer-x
In: 1e verdieping
Material: Isolatie - Kunststof hard
CPset_Phasing - Renovation Phase: Bestaand
Pset_SlabCommon - IsExternal: no; LoadBearing: yes
Material Properties - Isolatie - Kunststof hard, ThermalConductivity: 0.029; Isolatie - Kunststof hard, SpecificHeatCapacity: 1470 J/kg/K; Isolatie - Kunststof hard, MassDensity: 100 kg/m3; Isolatie - Kunststof hard, Embodied Energy: 101.5 (MJ/kg); Isolatie - Kunststof hard, Embodied Carbon: 3.48 (kgCO₂/kg); Isolatie - Kunststof hard, Name: Isolatie - Kunststof hard; Isolatie - Kunststof hard, Participates in Collision Detection: yes; Isolatie - Kunststof hard, Aardopwarmingsvermogen (GWP): 0.04; Isolatie - Kunststof hard, Ozonafbrekend Vermogen (ODP): 0; Isolatie - Kunststof hard, Fotochemische Vermogen tot Ozonvorming (POCP): 0; Isolatie - Kunststof hard, Verzuringsvermogen (AP): 0.0000975; Isolatie - Kunststof hard, Eutrofiëringspotentieel (EP): 0.0000237; Isolatie - Kunststof hard, Abiotisch Uitputtingspotentieel (voor niet fossiele hulpbronnen) (ADPE): 0; Isolatie - Kunststof hard, Abiotisch Uitputtingspotentieel (voor fossiele hulpbronnen) (ADPF): 0.47; Isolatie - Kunststof hard, Databron: https://www.oekobaudat.de/OEKOBAU.DAT/resource/processes/41e09ab7-0e73-4303-84fd-97cb0809db02?version=00.04.000

# IfcSlab: Metaal - Aluminium 40 (4)
Material: Metaal - Aluminium
CPset_Phasing - Renovation Phase: Bestaand
Pset_SlabCommon - IsExternal: no; LoadBearing: yes
Material Properties - Metaal - Aluminium, ThermalConductivity: 160; Metaal - Aluminium, SpecificHeatCapacity: 880 J/kg/K; Metaal - Aluminium, MassDensity: 2800 kg/m3; Metaal - Aluminium, Embodied Energy: 155 (MJ/kg); Metaal - Aluminium, Embodied Carbon: 9.16 (kgCO₂/kg); Metaal - Aluminium, Name: Metaal - Aluminium; Metaal - Aluminium, Participates in Collision Detection: yes; Metaal - Aluminium, Aardopwarmingsvermogen (GWP): 0.002322; Metaal - Aluminium, Ozonafbrekend Vermogen (ODP): 0; Metaal - Aluminium, Fotochemische Vermogen tot Ozonvorming (POCP): 6.194e-07; Metaal - Aluminium, Verzuringsvermogen (AP): 0.000008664; Metaal - Aluminium, Eutrofiëringspotentieel (EP): 0.00000106; Metaal - Aluminium, Abiotisch Uitputtingspotentieel (voor niet fossiele hulpbronnen) (ADPE): 0; Metaal - Aluminium, Abiotisch Uitputtingspotentieel (voor fossiele hulpbronnen) (ADPF): 0.02659; Metaal - Aluminium, Databron: https://www.oekobaudat.de/OEKOBAU.DAT/resource/processes/c83d501f-d07f-4434-9d5c-862a7e8a3026?version=00.01.000; Metaal - Aluminium, Handelsgewicht (kg/m): 0; Metaal - Aluminium, Soortelijk gewicht (kg/m3): 7850; Metaal - Aluminium, Marge materiaal: 1
Name | In
3 x h4 Aluminium, aluminiumlegeringen_Vloer-x | 1e verdieping
h4 Aluminium, aluminiumlegeringen_Vloer-x | 2e dakoverzicht

# IfcSlab: Metaal - Staal AFW 18 (5)
In: 1e verdieping
Material: Metaal - Staal AFW
CPset_Phasing - Renovation Phase: Bestaand
Pset_SlabCommon - IsExternal: no; LoadBearing: yes
Material Properties - Metaal - Staal AFW, ThermalConductivity: 52; Metaal - Staal AFW, SpecificHeatCapacity: 530 J/kg/K; Metaal - Staal AFW, MassDensity: 7950 kg/m3; Metaal - Staal AFW, Embodied Energy: 25 (MJ/kg); Metaal - Staal AFW, Embodied Carbon: 1.91 (kgCO₂/kg); Metaal - Staal AFW, Name: Metaal - Staal AFW; Metaal - Staal AFW, Participates in Collision Detection: yes; Metaal - Staal AFW, Aardopwarmingsvermogen (GWP): 12.4; Metaal - Staal AFW, Ozonafbrekend Vermogen (ODP): 0; Metaal - Staal AFW, Fotochemische Vermogen tot Ozonvorming (POCP): 0.00443; Metaal - Staal AFW, Verzuringsvermogen (AP): 0.0382; Metaal - Staal AFW, Eutrofiëringspotentieel (EP): 0.00359; Metaal - Staal AFW, Abiotisch Uitputtingspotentieel (voor niet fossiele hulpbronnen) (ADPE): 0.000573; Metaal - Staal AFW, Abiotisch Uitputtingspotentieel (voor fossiele hulpbronnen) (ADPF): 126; Metaal - Staal AFW, Databron: https://www.oekobaudat.de/OEKOBAU.DAT/resource/processes/c3ac069a-6cc4-4d41-a5fc-565615547792?version=00.02.000; Metaal - Staal AFW, Handelsgewicht (kg/m): 0; Metaal - Staal AFW, Soortelijk gewicht (kg/m3): 7850; Metaal - Staal AFW, Marge materiaal: 1

# IfcStair (4)
CPset_Phasing - Renovation Phase: Bestaand
Pset_StairCommon - IsExternal: no
Name | In
24_Trap-x | Kelder
3 x 24_Trap-x | Begane grond

# IfcStairFlight: IfcStairFlight (7)
CPset_Phasing - Renovation Phase: Bestaand
Name | In | Material | Beton gewapend prefab, ThermalConductivity | Beton gewapend prefab, SpecificHeatCapacity (J/kg/K) | Beton gewapend prefab, MassDensity (kg/m3) | Beton gewapend prefab, Embodied Energy | Beton gewapend prefab, Embodied Carbon | Beton gewapend prefab, Name | Beton gewapend prefab, Participates in Collision Detection | Beton gewapend prefab, Aardopwarmingsvermogen (GWP) | Beton gewapend prefab, Ozonafbrekend Vermogen (ODP) | Beton gewapend prefab, Fotochemische Vermogen tot Ozonvorming (POCP) | Beton gewapend prefab, Verzuringsvermogen (AP) | Beton gewapend prefab, Eutrofiëringspotentieel (EP) | Beton gewapend prefab, Abiotisch Uitputtingspotentieel (voor niet fossiele hulpbronnen) (ADPE) | Beton gewapend prefab, Abiotisch Uitputtingspotentieel (voor fossiele hulpbronnen) (ADPF) | Beton gewapend prefab, Databron
24_Trapconstructie-x | Kelder | Beton gewapend prefab | 2.5 | 1000 | 2400 | 2.33 (MJ/kg) | 0.242 (kgCO₂/kg) | Beton gewapend prefab | yes | 129.993 | 0 | 0.00471246 | 0.182012 | 0.0346685 | 0.000140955 | 604.803 | https://www.oekobaudat.de/OEKOBAU.DAT/resource/processes/3470c523-ffcd-48df-93ff-dedfde86572a?version=20.19.010
2 x 24_Trapconstructie-x | Begane grond | Beton C | Material Properties - Beton C, ThermalConductivity: 2; Beton C, SpecificHeatCapacity: 840 J/kg/K; Beton C, MassDensity: 2400 kg/m3; Beton C, Embodied Energy: 0.75 (MJ/kg); Beton C, Embodied Carbon: 0.1 (kgCO₂/kg); Beton C, Name: Beton C; Beton C, Participates in Collision Detection: yes; Beton C, Aardopwarmingsvermogen (GWP): 1.27649; Beton C, Ozonafbrekend Vermogen (ODP): 0; Beton C, Fotochemische Vermogen tot Ozonvorming (POCP): -0.000842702; Beton C, Verzuringsvermogen (AP): 0.00257837; Beton C, Eutrofiëringspotentieel (EP): 0.000612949; Beton C, Abiotisch Uitputtingspotentieel (voor niet fossiele hulpbronnen) (ADPE): 1.07417e-07; Beton C, Abiotisch Uitputtingspotentieel (voor fossiele hulpbronnen) (ADPF): 17.1106; Beton C, Databron: https://www.oekobaudat.de/OEKOBAU.DAT/resource/processes/d3b59cac-3b4e-4d18-8c3a-780b553c9591?version=20.19.120
4 x 24_Trapconstructie-x | Begane grond | Beton gewapend prefab | 2.5 | 1000 | 2400 | 2.33 (MJ/kg) | 0.242 (kgCO₂/kg) | Beton gewapend prefab | yes | 129.993 | 0 | 0.00471246 | 0.182012 | 0.0346685 | 0.000140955 | 604.803 | https://www.oekobaudat.de/OEKOBAU.DAT/resource/processes/3470c523-ffcd-48df-93ff-dedfde86572a?version=20.19.010

# IfcWall: 21 Borstwering STO Buitengevelisolatie 439 (2)
In: 1e verdieping
Pset_WallCommon - IsExternal: yes; LoadBearing: no
CPset_Phasing - Renovation Phase: Bestaand

# IfcWall: 21 Borstwering metselwerk 434 (3)
In: 1e verdieping
CPset_Phasing - Renovation Phase: Bestaand
Pset_WallCommon - IsExternal: yes; LoadBearing: no

# IfcWall: 21 Buitenwand metselwerk - metselwerk 258 (2)
In: 1e verdieping
CPset_Phasing - Renovation Phase: Bestaand
Pset_WallCommon - IsExternal: yes; LoadBearing: yes

# IfcWall: 21 Buitenwand spouwmuur 464 (14)
CPset_Phasing - Renovation Phase: Bestaand
Pset_WallCommon - IsExternal: yes; LoadBearing: yes
Name | In
9 x 21_Wand-x | Begane grond
5 x 21_Wand-x | 1e verdieping

# IfcWall: 21 Buitenwand spouwmuur HSB 464 (2)
CPset_Phasing - Renovation Phase: Bestaand
Pset_WallCommon - IsExternal: yes; LoadBearing: yes
Name | In
21_Wand-x | Begane grond
21_Wand-x | 1e verdieping

# IfcWall: 21 Buitenwand spouwmuur excl. isolatie 464, 21_Wand-x
In: Begane grond
Pset_WallCommon - IsExternal: yes; LoadBearing: yes
CPset_Phasing - Renovation Phase: Bestaand

# IfcWall: 21 Buitenwand spouwmuur kalkzandsteen 464 (3)
In: Begane grond
CPset_Phasing - Renovation Phase: Bestaand
Pset_WallCommon - IsExternal: yes; LoadBearing: yes

# IfcWall: 21 Buitenwand spouwmuur overstek 434, 21_Wand-x
In: 1e verdieping
CPset_Phasing - Renovation Phase: Bestaand
Pset_WallCommon - IsExternal: yes; LoadBearing: no

# IfcWall: 21 Buitenwand staalplaat 268 (2)
In: Begane grond
CPset_Phasing - Renovation Phase: Bestaand
Pset_WallCommon - IsExternal: yes; LoadBearing: yes

# IfcWall: 21 Kantplank 300 297 (3)
Pset_WallCommon - IsExternal: yes; LoadBearing: yes
CPset_Phasing - Renovation Phase: Bestaand
Name | In
21_Wand-x | Kelder
2 x 21_Wand-x | 1e verdieping

# IfcWall: 21 Kantplank 60 60 (3)
In: Kelder
CPset_Phasing - Renovation Phase: Bestaand
Pset_WallCommon - IsExternal: yes; LoadBearing: yes

# IfcWall: 21 STO Buitengevelisolatie 120 271 (2)
CPset_Phasing - Renovation Phase: Bestaand
Pset_WallCommon - IsExternal: yes; LoadBearing: yes
Name | In
21_Wand-x | Begane grond
21_Wand-x | 1e verdieping

# IfcWall: 21 STO Buitengevelisolatie 160 390 (10)
Pset_WallCommon - IsExternal: yes; LoadBearing: yes
CPset_Phasing - Renovation Phase: Bestaand
Name | In
4 x 21_Wand-x | Begane grond
6 x 21_Wand-x | 1e verdieping

# IfcWall: 21 Zetwerk op Isolatie 63 (3)
In: 1e verdieping
Pset_WallCommon - IsExternal: yes; LoadBearing: yes
CPset_Phasing - Renovation Phase: Bestaand

# IfcWall: 22 HSB wand 214 214, 21_Wand-x
In: 1e verdieping
Pset_WallCommon - IsExternal: yes; LoadBearing: yes
CPset_Phasing - Renovation Phase: Bestaand

# IfcWall: ALG - ALGEMEEN 1 (2)
In: Begane grond
Material: ALG - ALGEMEEN
CPset_Phasing - Renovation Phase: Bestaand
Pset_WallCommon - IsExternal: yes; LoadBearing: yes
Material Properties - ALG - ALGEMEEN, ThermalConductivity: 0.27; ALG - ALGEMEEN, SpecificHeatCapacity: 840 J/kg/K; ALG - ALGEMEEN, MassDensity: 800 kg/m3; ALG - ALGEMEEN, Embodied Energy: 2 (MJ/kg); ALG - ALGEMEEN, Embodied Carbon: 0.13 (kgCO₂/kg); ALG - ALGEMEEN, Name: ALG - ALGEMEEN; ALG - ALGEMEEN, Participates in Collision Detection: yes; ALG - ALGEMEEN, Handelsgewicht (kg/m): 0; ALG - ALGEMEEN, Soortelijk gewicht (kg/m3): 7850; ALG - ALGEMEEN, Marge materiaal: 1

# IfcWall: ALG - ALGEMEEN 5 (2)
In: Begane grond
Material: ALG - ALGEMEEN
CPset_Phasing - Renovation Phase: Bestaand
Material Properties - ALG - ALGEMEEN, ThermalConductivity: 0.27; ALG - ALGEMEEN, SpecificHeatCapacity: 840 J/kg/K; ALG - ALGEMEEN, MassDensity: 800 kg/m3; ALG - ALGEMEEN, Embodied Energy: 2 (MJ/kg); ALG - ALGEMEEN, Embodied Carbon: 0.13 (kgCO₂/kg); ALG - ALGEMEEN, Name: ALG - ALGEMEEN; ALG - ALGEMEEN, Participates in Collision Detection: yes; ALG - ALGEMEEN, Handelsgewicht (kg/m): 0; ALG - ALGEMEEN, Soortelijk gewicht (kg/m3): 7850; ALG - ALGEMEEN, Marge materiaal: 1
Pset_WallCommon - IsExternal: yes; LoadBearing: yes

# IfcWall: ALG - ISOLATIE 50, 21_Wand-x
In: Begane grond
Material: ALG - ISOLATIE
Pset_WallCommon - IsExternal: yes; LoadBearing: yes
Material Properties - ALG - ISOLATIE, ThermalConductivity: 0.035; ALG - ISOLATIE, SpecificHeatCapacity: 840 J/kg/K; ALG - ISOLATIE, MassDensity: 45 kg/m3; ALG - ISOLATIE, Embodied Energy: 16.8 (MJ/kg); ALG - ISOLATIE, Embodied Carbon: 1.05 (kgCO₂/kg); ALG - ISOLATIE, Name: ALG - ISOLATIE; ALG - ISOLATIE, Participates in Collision Detection: yes
CPset_Phasing - Renovation Phase: Bestaand

# IfcWall: ALG - LICHTE SCHEIDINGSWAND 214, 21_Wand-x
In: Begane grond
Material: ALG - LICHTE SCHEIDINGSWAND
CPset_Phasing - Renovation Phase: Bestaand
Material Properties - ALG - LICHTE SCHEIDINGSWAND, ThermalConductivity: 0.27; ALG - LICHTE SCHEIDINGSWAND, SpecificHeatCapacity: 840 J/kg/K; ALG - LICHTE SCHEIDINGSWAND, MassDensity: 800 kg/m3; ALG - LICHTE SCHEIDINGSWAND, Embodied Energy: 2 (MJ/kg); ALG - LICHTE SCHEIDINGSWAND, Embodied Carbon: 0.13 (kgCO₂/kg); ALG - LICHTE SCHEIDINGSWAND, Name: ALG - LICHTE SCHEIDINGSWAND; ALG - LICHTE SCHEIDINGSWAND, Participates in Collision Detection: yes
Pset_WallCommon - IsExternal: yes; LoadBearing: no

# IfcWall: Eternit wit 8, 21_Wand-x
In: 1e verdieping
Material: Eternit wit
CPset_Phasing - Renovation Phase: Bestaand
Pset_WallCommon - IsExternal: yes; LoadBearing: no
Material Properties - Eternit wit, ThermalConductivity: 0.45; Eternit wit, SpecificHeatCapacity: 840 J/kg/K; Eternit wit, MassDensity: 1400 kg/m3; Eternit wit, Embodied Energy: 6.75 (MJ/kg); Eternit wit, Embodied Carbon: 0.38 (kgCO₂/kg); Eternit wit, Name: Eternit wit; Eternit wit, Participates in Collision Detection: yes; Eternit wit, Aardopwarmingsvermogen (GWP): 1.62283; Eternit wit, Ozonafbrekend Vermogen (ODP): 0; Eternit wit, Fotochemische Vermogen tot Ozonvorming (POCP): 33.9565; Eternit wit, Verzuringsvermogen (AP): 0.000135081; Eternit wit, Eutrofiëringspotentieel (EP): 0.00274111; Eternit wit, Abiotisch Uitputtingspotentieel (voor niet fossiele hulpbronnen) (ADPE): 0; Eternit wit, Abiotisch Uitputtingspotentieel (voor fossiele hulpbronnen) (ADPF): 0.000893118; Eternit wit, Databron: https://www.oekobaudat.de/OEKOBAU.DAT/resource/processes/07423e99-8c7c-4e93-8311-dcf7ae85c41d?version=20.20.010

# IfcWall: Glas 20, 21_Wand-x
In: 1e verdieping
Material: Glas
Pset_WallCommon - IsExternal: yes; LoadBearing: yes
Material Properties - Glas, ThermalConductivity: 1.2; Glas, SpecificHeatCapacity: 795 J/kg/K; Glas, MassDensity: 2180 kg/m3; Glas, Embodied Energy: 15 (MJ/kg); Glas, Embodied Carbon: 0.86 (kgCO₂/kg); Glas, Name: Glas; Glas, Participates in Collision Detection: yes; Glas, Aardopwarmingsvermogen (GWP): 44.3346; Glas, Ozonafbrekend Vermogen (ODP): 0; Glas, Fotochemische Vermogen tot Ozonvorming (POCP): 0.0213557; Glas, Verzuringsvermogen (AP): 0.281643; Glas, Eutrofiëringspotentieel (EP): 0.0316879; Glas, Abiotisch Uitputtingspotentieel (voor niet fossiele hulpbronnen) (ADPE): 0.00000449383; Glas, Abiotisch Uitputtingspotentieel (voor fossiele hulpbronnen) (ADPF): 628.803; Glas, Databron: https://www.oekobaudat.de/OEKOBAU.DAT/resource/processes/1f2d6e42-9ffc-421d-990d-555eee4a7529?version=20.19.120
CPset_Phasing - Renovation Phase: Bestaand

# IfcWall: Hout - Multiplex 20 (61)
Material: Hout - Multiplex
CPset_Phasing - Renovation Phase: Bestaand
Pset_WallCommon - IsExternal: yes; LoadBearing: yes
Material Properties - Hout - Multiplex, ThermalConductivity: 0.17; Hout - Multiplex, SpecificHeatCapacity: 1600 J/kg/K; Hout - Multiplex, MassDensity: 700 kg/m3; Hout - Multiplex, Embodied Energy: 15 (MJ/kg); Hout - Multiplex, Embodied Carbon: 0.77 (kgCO₂/kg); Hout - Multiplex, Name: Hout - Multiplex; Hout - Multiplex, Participates in Collision Detection: yes; Hout - Multiplex, Aardopwarmingsvermogen (GWP): -32.4496; Hout - Multiplex, Ozonafbrekend Vermogen (ODP): 0; Hout - Multiplex, Fotochemische Vermogen tot Ozonvorming (POCP): -0.00287346; Hout - Multiplex, Verzuringsvermogen (AP): 0.138611; Hout - Multiplex, Eutrofiëringspotentieel (EP): 0.0523292; Hout - Multiplex, Abiotisch Uitputtingspotentieel (voor niet fossiele hulpbronnen) (ADPE): -0.0000777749; Hout - Multiplex, Abiotisch Uitputtingspotentieel (voor fossiele hulpbronnen) (ADPF): -4006.31; Hout - Multiplex, Databron: https://www.oekobaudat.de/OEKOBAU.DAT/resource/processes/cc180aec-8a5c-4e07-b1a0-1ab81dd746ac?version=20.20.120
Name | In
24 x 21_Wand-x | Begane grond
37 x 21_Wand-x | 1e verdieping

# IfcWall: Hout - Multiplex 50 (8)
Material: Hout - Multiplex
Pset_WallCommon - IsExternal: yes; LoadBearing: yes
Material Properties - Hout - Multiplex, ThermalConductivity: 0.17; Hout - Multiplex, SpecificHeatCapacity: 1600 J/kg/K; Hout - Multiplex, MassDensity: 700 kg/m3; Hout - Multiplex, Embodied Energy: 15 (MJ/kg); Hout - Multiplex, Embodied Carbon: 0.77 (kgCO₂/kg); Hout - Multiplex, Name: Hout - Multiplex; Hout - Multiplex, Participates in Collision Detection: yes; Hout - Multiplex, Aardopwarmingsvermogen (GWP): -32.4496; Hout - Multiplex, Ozonafbrekend Vermogen (ODP): 0; Hout - Multiplex, Fotochemische Vermogen tot Ozonvorming (POCP): -0.00287346; Hout - Multiplex, Verzuringsvermogen (AP): 0.138611; Hout - Multiplex, Eutrofiëringspotentieel (EP): 0.0523292; Hout - Multiplex, Abiotisch Uitputtingspotentieel (voor niet fossiele hulpbronnen) (ADPE): -0.0000777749; Hout - Multiplex, Abiotisch Uitputtingspotentieel (voor fossiele hulpbronnen) (ADPF): -4006.31; Hout - Multiplex, Databron: https://www.oekobaudat.de/OEKOBAU.DAT/resource/processes/cc180aec-8a5c-4e07-b1a0-1ab81dd746ac?version=20.20.120
CPset_Phasing - Renovation Phase: Bestaand
Name | In
3 x 21_Wand-x | Begane grond
5 x 21_Wand-x | 1e verdieping

# IfcWall: Isolatie - Kunststof hard 85 (4)
In: 2e dakoverzicht
Material: Isolatie - Kunststof hard
CPset_Phasing - Renovation Phase: Bestaand
Pset_WallCommon - IsExternal: yes; LoadBearing: yes
Material Properties - Isolatie - Kunststof hard, ThermalConductivity: 0.029; Isolatie - Kunststof hard, SpecificHeatCapacity: 1470 J/kg/K; Isolatie - Kunststof hard, MassDensity: 100 kg/m3; Isolatie - Kunststof hard, Embodied Energy: 101.5 (MJ/kg); Isolatie - Kunststof hard, Embodied Carbon: 3.48 (kgCO₂/kg); Isolatie - Kunststof hard, Name: Isolatie - Kunststof hard; Isolatie - Kunststof hard, Participates in Collision Detection: yes; Isolatie - Kunststof hard, Aardopwarmingsvermogen (GWP): 0.04; Isolatie - Kunststof hard, Ozonafbrekend Vermogen (ODP): 0; Isolatie - Kunststof hard, Fotochemische Vermogen tot Ozonvorming (POCP): 0; Isolatie - Kunststof hard, Verzuringsvermogen (AP): 0.0000975; Isolatie - Kunststof hard, Eutrofiëringspotentieel (EP): 0.0000237; Isolatie - Kunststof hard, Abiotisch Uitputtingspotentieel (voor niet fossiele hulpbronnen) (ADPE): 0; Isolatie - Kunststof hard, Abiotisch Uitputtingspotentieel (voor fossiele hulpbronnen) (ADPF): 0.47; Isolatie - Kunststof hard, Databron: https://www.oekobaudat.de/OEKOBAU.DAT/resource/processes/41e09ab7-0e73-4303-84fd-97cb0809db02?version=00.04.000

# IfcWall: Kurk 6 (8)
Material: Kurk
Pset_WallCommon - IsExternal: yes; LoadBearing: yes
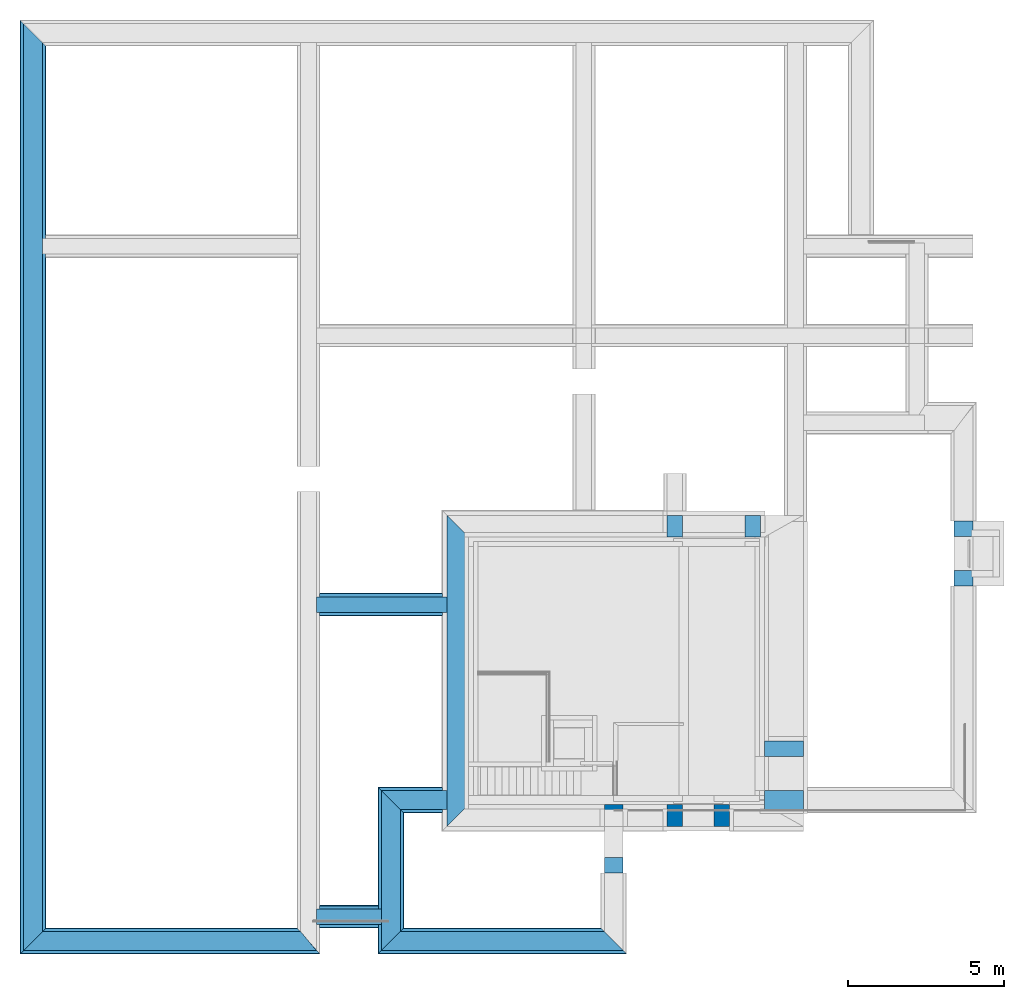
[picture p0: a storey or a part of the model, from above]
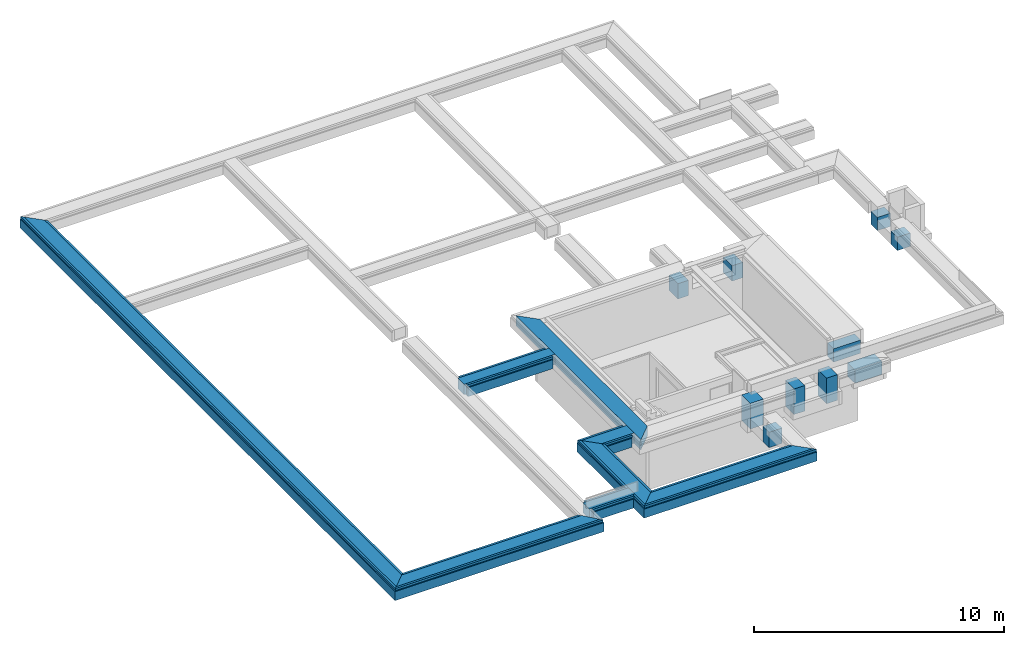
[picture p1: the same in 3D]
Properties of the parts of a building model (IFC2X3), part 7 of 7

# IfcWall: Kurk 6 (8)
Material Properties - Kurk, ThermalConductivity: 0.17; Kurk, SpecificHeatCapacity: 1600 J/kg/K; Kurk, MassDensity: 700 kg/m3; Kurk, Embodied Energy: 15 (MJ/kg); Kurk, Embodied Carbon: 0.77 (kgCO₂/kg); Kurk, Name: Kurk; Kurk, Participates in Collision Detection: yes; Kurk, Aardopwarmingsvermogen (GWP): -32.4496; Kurk, Ozonafbrekend Vermogen (ODP): 0; Kurk, Fotochemische Vermogen tot Ozonvorming (POCP): -0.00287346; Kurk, Verzuringsvermogen (AP): 0.138611; Kurk, Eutrofiëringspotentieel (EP): 0.0523292; Kurk, Abiotisch Uitputtingspotentieel (voor niet fossiele hulpbronnen) (ADPE): -0.0000777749; Kurk, Abiotisch Uitputtingspotentieel (voor fossiele hulpbronnen) (ADPF): -4006.31; Kurk, Databron: https://www.oekobaudat.de/OEKOBAU.DAT/resource/processes/cc180aec-8a5c-4e07-b1a0-1ab81dd746ac?version=20.20.120
CPset_Phasing - Renovation Phase: Bestaand
Name | In
4 x 21_Wand-x | Begane grond
4 x 21_Wand-x | 1e verdieping

# IfcWall: Metaal - Staal C 15, 21_Wand-x
In: 1e verdieping
Material: Metaal - Staal C
CPset_Phasing - Renovation Phase: Bestaand
Material Properties - Metaal - Staal C, ThermalConductivity: 52; Metaal - Staal C, SpecificHeatCapacity: 530 J/kg/K; Metaal - Staal C, MassDensity: 7950 kg/m3; Metaal - Staal C, Embodied Energy: 25 (MJ/kg); Metaal - Staal C, Embodied Carbon: 1.91 (kgCO₂/kg); Metaal - Staal C, Name: Metaal - Staal C; Metaal - Staal C, Participates in Collision Detection: yes; Metaal - Staal C, Aardopwarmingsvermogen (GWP): 323.71; Metaal - Staal C, Ozonafbrekend Vermogen (ODP): 0; Metaal - Staal C, Fotochemische Vermogen tot Ozonvorming (POCP): 0.17963; Metaal - Staal C, Verzuringsvermogen (AP): 0.43354; Metaal - Staal C, Eutrofiëringspotentieel (EP): 0.014961; Metaal - Staal C, Abiotisch Uitputtingspotentieel (voor niet fossiele hulpbronnen) (ADPE): 0.00080492; Metaal - Staal C, Abiotisch Uitputtingspotentieel (voor fossiele hulpbronnen) (ADPF): 2862.1; Metaal - Staal C, Databron: https://www.oekobaudat.de/OEKOBAU.DAT/resource/processes/a85fbb4a-60a0-4ba9-9cfa-cdfbe1ec7f00?version=00.01.000
Pset_WallCommon - IsExternal: yes; LoadBearing: yes

# IfcWall: Metaal - Staal C 2 (3)
In: Begane grond
Material: Metaal - Staal C
CPset_Phasing - Renovation Phase: Bestaand
Pset_WallCommon - IsExternal: yes; LoadBearing: yes
Material Properties - Metaal - Staal C, ThermalConductivity: 52; Metaal - Staal C, SpecificHeatCapacity: 530 J/kg/K; Metaal - Staal C, MassDensity: 7950 kg/m3; Metaal - Staal C, Embodied Energy: 25 (MJ/kg); Metaal - Staal C, Embodied Carbon: 1.91 (kgCO₂/kg); Metaal - Staal C, Name: Metaal - Staal C; Metaal - Staal C, Participates in Collision Detection: yes; Metaal - Staal C, Aardopwarmingsvermogen (GWP): 323.71; Metaal - Staal C, Ozonafbrekend Vermogen (ODP): 0; Metaal - Staal C, Fotochemische Vermogen tot Ozonvorming (POCP): 0.17963; Metaal - Staal C, Verzuringsvermogen (AP): 0.43354; Metaal - Staal C, Eutrofiëringspotentieel (EP): 0.014961; Metaal - Staal C, Abiotisch Uitputtingspotentieel (voor niet fossiele hulpbronnen) (ADPE): 0.00080492; Metaal - Staal C, Abiotisch Uitputtingspotentieel (voor fossiele hulpbronnen) (ADPF): 2862.1; Metaal - Staal C, Databron: https://www.oekobaudat.de/OEKOBAU.DAT/resource/processes/a85fbb4a-60a0-4ba9-9cfa-cdfbe1ec7f00?version=00.01.000

# IfcWall: Metaal - Staal C 6 (3)
In: Begane grond
Material: Metaal - Staal C
CPset_Phasing - Renovation Phase: Bestaand
Material Properties - Metaal - Staal C, ThermalConductivity: 52; Metaal - Staal C, SpecificHeatCapacity: 530 J/kg/K; Metaal - Staal C, MassDensity: 7950 kg/m3; Metaal - Staal C, Embodied Energy: 25 (MJ/kg); Metaal - Staal C, Embodied Carbon: 1.91 (kgCO₂/kg); Metaal - Staal C, Name: Metaal - Staal C; Metaal - Staal C, Participates in Collision Detection: yes; Metaal - Staal C, Aardopwarmingsvermogen (GWP): 323.71; Metaal - Staal C, Ozonafbrekend Vermogen (ODP): 0; Metaal - Staal C, Fotochemische Vermogen tot Ozonvorming (POCP): 0.17963; Metaal - Staal C, Verzuringsvermogen (AP): 0.43354; Metaal - Staal C, Eutrofiëringspotentieel (EP): 0.014961; Metaal - Staal C, Abiotisch Uitputtingspotentieel (voor niet fossiele hulpbronnen) (ADPE): 0.00080492; Metaal - Staal C, Abiotisch Uitputtingspotentieel (voor fossiele hulpbronnen) (ADPF): 2862.1; Metaal - Staal C, Databron: https://www.oekobaudat.de/OEKOBAU.DAT/resource/processes/a85fbb4a-60a0-4ba9-9cfa-cdfbe1ec7f00?version=00.01.000
Pset_WallCommon - IsExternal: yes; LoadBearing: yes

# IfcWall: Steen - Baksteen 70, 21_Wand-x
In: Begane grond
Material: Steen - Baksteen
CPset_Phasing - Renovation Phase: Bestaand
Pset_WallCommon - IsExternal: yes; LoadBearing: yes
Material Properties - Steen - Baksteen, ThermalConductivity: 0.9; Steen - Baksteen, SpecificHeatCapacity: 840 J/kg/K; Steen - Baksteen, MassDensity: 1600 kg/m3; Steen - Baksteen, Embodied Energy: 3 (MJ/kg); Steen - Baksteen, Embodied Carbon: 0.23 (kgCO₂/kg); Steen - Baksteen, Name: Steen - Baksteen; Steen - Baksteen, Participates in Collision Detection: yes; Steen - Baksteen, Aardopwarmingsvermogen (GWP): 113; Steen - Baksteen, Ozonafbrekend Vermogen (ODP): 0; Steen - Baksteen, Fotochemische Vermogen tot Ozonvorming (POCP): 0.012; Steen - Baksteen, Verzuringsvermogen (AP): 0.094; Steen - Baksteen, Eutrofiëringspotentieel (EP): 0.0189; Steen - Baksteen, Abiotisch Uitputtingspotentieel (voor niet fossiele hulpbronnen) (ADPE): 0.0000099; Steen - Baksteen, Abiotisch Uitputtingspotentieel (voor fossiele hulpbronnen) (ADPF): 1150; Steen - Baksteen, Databron: https://www.oekobaudat.de/OEKOBAU.DAT/resource/processes/08dd0308-eebf-4db1-82ee-b340d070c9b9?version=00.06.000

# IfcWall: Steen - Kalkzandsteen 100, 21_Wand-x
In: Begane grond
Material: Steen - Kalkzandsteen
Pset_WallCommon - IsExternal: yes; LoadBearing: yes
CPset_Phasing - Renovation Phase: Bestaand
Material Properties - Steen - Kalkzandsteen, ThermalConductivity: 0.9; Steen - Kalkzandsteen, SpecificHeatCapacity: 840 J/kg/K; Steen - Kalkzandsteen, MassDensity: 1900 kg/m3; Steen - Kalkzandsteen, Embodied Energy: 0.75 (MJ/kg); Steen - Kalkzandsteen, Embodied Carbon: 0.1 (kgCO₂/kg); Steen - Kalkzandsteen, Name: Steen - Kalkzandsteen; Steen - Kalkzandsteen, Participates in Collision Detection: yes; Steen - Kalkzandsteen, Aardopwarmingsvermogen (GWP): 1.69601; Steen - Kalkzandsteen, Ozonafbrekend Vermogen (ODP): 0; Steen - Kalkzandsteen, Fotochemische Vermogen tot Ozonvorming (POCP): -0.0042842; Steen - Kalkzandsteen, Verzuringsvermogen (AP): 0.0101137; Steen - Kalkzandsteen, Eutrofiëringspotentieel (EP): 0.00257216; Steen - Kalkzandsteen, Abiotisch Uitputtingspotentieel (voor niet fossiele hulpbronnen) (ADPE): 1.44694e-07; Steen - Kalkzandsteen, Abiotisch Uitputtingspotentieel (voor fossiele hulpbronnen) (ADPF): 23.0485; Steen - Kalkzandsteen, Databron: https://www.oekobaudat.de/OEKOBAU.DAT/resource/processes/a758fb6a-7fb1-4cdc-b652-c42cf2f7632c?version=20.20.020

# IfcWall: Steen - Kalkzandsteen 150, 21_Wand-x
In: Begane grond
Material: Steen - Kalkzandsteen
CPset_Phasing - Renovation Phase: Bestaand
Pset_WallCommon - IsExternal: yes; LoadBearing: yes
Material Properties - Steen - Kalkzandsteen, ThermalConductivity: 0.9; Steen - Kalkzandsteen, SpecificHeatCapacity: 840 J/kg/K; Steen - Kalkzandsteen, MassDensity: 1900 kg/m3; Steen - Kalkzandsteen, Embodied Energy: 0.75 (MJ/kg); Steen - Kalkzandsteen, Embodied Carbon: 0.1 (kgCO₂/kg); Steen - Kalkzandsteen, Name: Steen - Kalkzandsteen; Steen - Kalkzandsteen, Participates in Collision Detection: yes; Steen - Kalkzandsteen, Aardopwarmingsvermogen (GWP): 1.69601; Steen - Kalkzandsteen, Ozonafbrekend Vermogen (ODP): 0; Steen - Kalkzandsteen, Fotochemische Vermogen tot Ozonvorming (POCP): -0.0042842; Steen - Kalkzandsteen, Verzuringsvermogen (AP): 0.0101137; Steen - Kalkzandsteen, Eutrofiëringspotentieel (EP): 0.00257216; Steen - Kalkzandsteen, Abiotisch Uitputtingspotentieel (voor niet fossiele hulpbronnen) (ADPE): 1.44694e-07; Steen - Kalkzandsteen, Abiotisch Uitputtingspotentieel (voor fossiele hulpbronnen) (ADPF): 23.0485; Steen - Kalkzandsteen, Databron: https://www.oekobaudat.de/OEKOBAU.DAT/resource/processes/a758fb6a-7fb1-4cdc-b652-c42cf2f7632c?version=20.20.020

# IfcWall: Wandeinde 2 26 (2)
In: 1e verdieping
CPset_Phasing - Renovation Phase: Bestaand
